VERSION 5.8 ;
BUSBITCHARS "[]" ;
DIVIDERCHAR "/" ;
UNITS
    DATABASE MICRONS 1000 ;
END UNITS

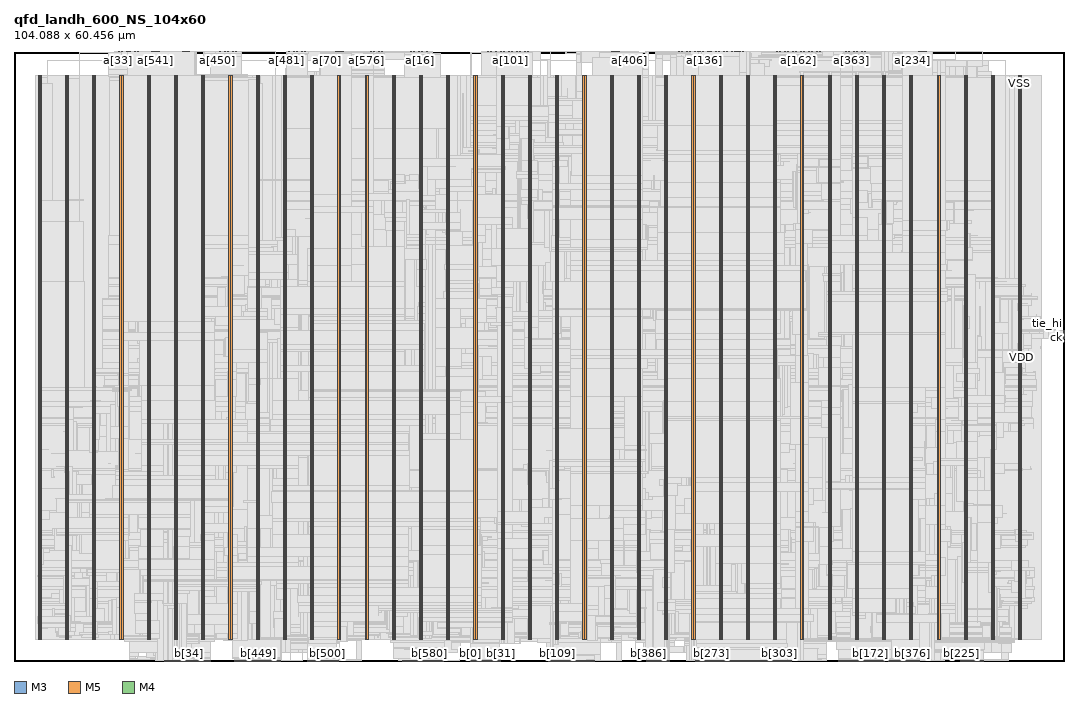
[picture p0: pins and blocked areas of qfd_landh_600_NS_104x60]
MACRO qfd_landh_600_NS_104x60
  FOREIGN qfd_landh_600_NS_104x60 0 0 ;
  CLASS BLOCK ;
  SIZE 104.088 BY 60.456 ;
  PIN a[0]
    DIRECTION INPUT ;
    USE SIGNAL ;
    PORT
      LAYER M3 ;
        RECT  39.06 60.419 39.078 60.456 ;
    END
  END a[0]
  PIN a[100]
    DIRECTION INPUT ;
    USE SIGNAL ;
    PORT
      LAYER M3 ;
        RECT  49.14 60.419 49.158 60.456 ;
    END
  END a[100]
  PIN a[101]
    DIRECTION INPUT ;
    USE SIGNAL ;
    PORT
      LAYER M3 ;
        RECT  49.212 60.419 49.23 60.456 ;
    END
  END a[101]
  PIN a[102]
    DIRECTION INPUT ;
    USE SIGNAL ;
    PORT
      LAYER M3 ;
        RECT  49.284 60.419 49.302 60.456 ;
    END
  END a[102]
  PIN a[103]
    DIRECTION INPUT ;
    USE SIGNAL ;
    PORT
      LAYER M3 ;
        RECT  49.356 60.419 49.374 60.456 ;
    END
  END a[103]
  PIN a[104]
    DIRECTION INPUT ;
    USE SIGNAL ;
    PORT
      LAYER M3 ;
        RECT  49.428 60.419 49.446 60.456 ;
    END
  END a[104]
  PIN a[105]
    DIRECTION INPUT ;
    USE SIGNAL ;
    PORT
      LAYER M3 ;
        RECT  49.5 60.419 49.518 60.456 ;
    END
  END a[105]
  PIN a[106]
    DIRECTION INPUT ;
    USE SIGNAL ;
    PORT
      LAYER M3 ;
        RECT  49.572 60.419 49.59 60.456 ;
    END
  END a[106]
  PIN a[107]
    DIRECTION INPUT ;
    USE SIGNAL ;
    PORT
      LAYER M3 ;
        RECT  49.644 60.419 49.662 60.456 ;
    END
  END a[107]
  PIN a[108]
    DIRECTION INPUT ;
    USE SIGNAL ;
    PORT
      LAYER M3 ;
        RECT  49.716 60.419 49.734 60.456 ;
    END
  END a[108]
  PIN a[109]
    DIRECTION INPUT ;
    USE SIGNAL ;
    PORT
      LAYER M3 ;
        RECT  49.788 60.419 49.806 60.456 ;
    END
  END a[109]
  PIN a[10]
    DIRECTION INPUT ;
    USE SIGNAL ;
    PORT
      LAYER M3 ;
        RECT  39.78 60.419 39.798 60.456 ;
    END
  END a[10]
  PIN a[110]
    DIRECTION INPUT ;
    USE SIGNAL ;
    PORT
      LAYER M3 ;
        RECT  49.86 60.419 49.878 60.456 ;
    END
  END a[110]
  PIN a[111]
    DIRECTION INPUT ;
    USE SIGNAL ;
    PORT
      LAYER M3 ;
        RECT  49.932 60.419 49.95 60.456 ;
    END
  END a[111]
  PIN a[112]
    DIRECTION INPUT ;
    USE SIGNAL ;
    PORT
      LAYER M3 ;
        RECT  50.004 60.419 50.022 60.456 ;
    END
  END a[112]
  PIN a[113]
    DIRECTION INPUT ;
    USE SIGNAL ;
    PORT
      LAYER M3 ;
        RECT  50.076 60.419 50.094 60.456 ;
    END
  END a[113]
  PIN a[114]
    DIRECTION INPUT ;
    USE SIGNAL ;
    PORT
      LAYER M3 ;
        RECT  50.148 60.419 50.166 60.456 ;
    END
  END a[114]
  PIN a[115]
    DIRECTION INPUT ;
    USE SIGNAL ;
    PORT
      LAYER M3 ;
        RECT  50.22 60.419 50.238 60.456 ;
    END
  END a[115]
  PIN a[116]
    DIRECTION INPUT ;
    USE SIGNAL ;
    PORT
      LAYER M3 ;
        RECT  50.292 60.419 50.31 60.456 ;
    END
  END a[116]
  PIN a[117]
    DIRECTION INPUT ;
    USE SIGNAL ;
    PORT
      LAYER M3 ;
        RECT  50.364 60.419 50.382 60.456 ;
    END
  END a[117]
  PIN a[118]
    DIRECTION INPUT ;
    USE SIGNAL ;
    PORT
      LAYER M3 ;
        RECT  50.436 60.419 50.454 60.456 ;
    END
  END a[118]
  PIN a[119]
    DIRECTION INPUT ;
    USE SIGNAL ;
    PORT
      LAYER M3 ;
        RECT  50.508 60.419 50.526 60.456 ;
    END
  END a[119]
  PIN a[11]
    DIRECTION INPUT ;
    USE SIGNAL ;
    PORT
      LAYER M3 ;
        RECT  39.852 60.419 39.87 60.456 ;
    END
  END a[11]
  PIN a[120]
    DIRECTION INPUT ;
    USE SIGNAL ;
    PORT
      LAYER M3 ;
        RECT  50.58 60.419 50.598 60.456 ;
    END
  END a[120]
  PIN a[121]
    DIRECTION INPUT ;
    USE SIGNAL ;
    PORT
      LAYER M3 ;
        RECT  50.652 60.419 50.67 60.456 ;
    END
  END a[121]
  PIN a[122]
    DIRECTION INPUT ;
    USE SIGNAL ;
    PORT
      LAYER M3 ;
        RECT  50.724 60.419 50.742 60.456 ;
    END
  END a[122]
  PIN a[123]
    DIRECTION INPUT ;
    USE SIGNAL ;
    PORT
      LAYER M3 ;
        RECT  50.796 60.419 50.814 60.456 ;
    END
  END a[123]
  PIN a[124]
    DIRECTION INPUT ;
    USE SIGNAL ;
    PORT
      LAYER M3 ;
        RECT  50.868 60.419 50.886 60.456 ;
    END
  END a[124]
  PIN a[125]
    DIRECTION INPUT ;
    USE SIGNAL ;
    PORT
      LAYER M3 ;
        RECT  50.94 60.419 50.958 60.456 ;
    END
  END a[125]
  PIN a[126]
    DIRECTION INPUT ;
    USE SIGNAL ;
    PORT
      LAYER M3 ;
        RECT  51.012 60.419 51.03 60.456 ;
    END
  END a[126]
  PIN a[127]
    DIRECTION INPUT ;
    USE SIGNAL ;
    PORT
      LAYER M3 ;
        RECT  51.084 60.419 51.102 60.456 ;
    END
  END a[127]
  PIN a[128]
    DIRECTION INPUT ;
    USE SIGNAL ;
    PORT
      LAYER M3 ;
        RECT  67.86 60.419 67.878 60.456 ;
    END
  END a[128]
  PIN a[129]
    DIRECTION INPUT ;
    USE SIGNAL ;
    PORT
      LAYER M3 ;
        RECT  67.932 60.419 67.95 60.456 ;
    END
  END a[129]
  PIN a[12]
    DIRECTION INPUT ;
    USE SIGNAL ;
    PORT
      LAYER M3 ;
        RECT  39.924 60.419 39.942 60.456 ;
    END
  END a[12]
  PIN a[130]
    DIRECTION INPUT ;
    USE SIGNAL ;
    PORT
      LAYER M3 ;
        RECT  68.004 60.419 68.022 60.456 ;
    END
  END a[130]
  PIN a[131]
    DIRECTION INPUT ;
    USE SIGNAL ;
    PORT
      LAYER M3 ;
        RECT  68.076 60.419 68.094 60.456 ;
    END
  END a[131]
  PIN a[132]
    DIRECTION INPUT ;
    USE SIGNAL ;
    PORT
      LAYER M3 ;
        RECT  68.148 60.419 68.166 60.456 ;
    END
  END a[132]
  PIN a[133]
    DIRECTION INPUT ;
    USE SIGNAL ;
    PORT
      LAYER M3 ;
        RECT  68.22 60.419 68.238 60.456 ;
    END
  END a[133]
  PIN a[134]
    DIRECTION INPUT ;
    USE SIGNAL ;
    PORT
      LAYER M3 ;
        RECT  68.292 60.419 68.31 60.456 ;
    END
  END a[134]
  PIN a[135]
    DIRECTION INPUT ;
    USE SIGNAL ;
    PORT
      LAYER M3 ;
        RECT  68.364 60.419 68.382 60.456 ;
    END
  END a[135]
  PIN a[136]
    DIRECTION INPUT ;
    USE SIGNAL ;
    PORT
      LAYER M3 ;
        RECT  68.436 60.419 68.454 60.456 ;
    END
  END a[136]
  PIN a[137]
    DIRECTION INPUT ;
    USE SIGNAL ;
    PORT
      LAYER M3 ;
        RECT  68.508 60.419 68.526 60.456 ;
    END
  END a[137]
  PIN a[138]
    DIRECTION INPUT ;
    USE SIGNAL ;
    PORT
      LAYER M3 ;
        RECT  68.58 60.419 68.598 60.456 ;
    END
  END a[138]
  PIN a[139]
    DIRECTION INPUT ;
    USE SIGNAL ;
    PORT
      LAYER M3 ;
        RECT  68.652 60.419 68.67 60.456 ;
    END
  END a[139]
  PIN a[13]
    DIRECTION INPUT ;
    USE SIGNAL ;
    PORT
      LAYER M3 ;
        RECT  39.996 60.419 40.014 60.456 ;
    END
  END a[13]
  PIN a[140]
    DIRECTION INPUT ;
    USE SIGNAL ;
    PORT
      LAYER M3 ;
        RECT  68.724 60.419 68.742 60.456 ;
    END
  END a[140]
  PIN a[141]
    DIRECTION INPUT ;
    USE SIGNAL ;
    PORT
      LAYER M3 ;
        RECT  68.796 60.419 68.814 60.456 ;
    END
  END a[141]
  PIN a[142]
    DIRECTION INPUT ;
    USE SIGNAL ;
    PORT
      LAYER M3 ;
        RECT  68.868 60.419 68.886 60.456 ;
    END
  END a[142]
  PIN a[143]
    DIRECTION INPUT ;
    USE SIGNAL ;
    PORT
      LAYER M3 ;
        RECT  68.94 60.419 68.958 60.456 ;
    END
  END a[143]
  PIN a[144]
    DIRECTION INPUT ;
    USE SIGNAL ;
    PORT
      LAYER M3 ;
        RECT  69.012 60.419 69.03 60.456 ;
    END
  END a[144]
  PIN a[145]
    DIRECTION INPUT ;
    USE SIGNAL ;
    PORT
      LAYER M3 ;
        RECT  69.084 60.419 69.102 60.456 ;
    END
  END a[145]
  PIN a[146]
    DIRECTION INPUT ;
    USE SIGNAL ;
    PORT
      LAYER M3 ;
        RECT  69.156 60.419 69.174 60.456 ;
    END
  END a[146]
  PIN a[147]
    DIRECTION INPUT ;
    USE SIGNAL ;
    PORT
      LAYER M3 ;
        RECT  69.228 60.419 69.246 60.456 ;
    END
  END a[147]
  PIN a[148]
    DIRECTION INPUT ;
    USE SIGNAL ;
    PORT
      LAYER M3 ;
        RECT  69.3 60.419 69.318 60.456 ;
    END
  END a[148]
  PIN a[149]
    DIRECTION INPUT ;
    USE SIGNAL ;
    PORT
      LAYER M3 ;
        RECT  69.372 60.419 69.39 60.456 ;
    END
  END a[149]
  PIN a[14]
    DIRECTION INPUT ;
    USE SIGNAL ;
    PORT
      LAYER M3 ;
        RECT  40.068 60.419 40.086 60.456 ;
    END
  END a[14]
  PIN a[150]
    DIRECTION INPUT ;
    USE SIGNAL ;
    PORT
      LAYER M3 ;
        RECT  69.444 60.419 69.462 60.456 ;
    END
  END a[150]
  PIN a[151]
    DIRECTION INPUT ;
    USE SIGNAL ;
    PORT
      LAYER M3 ;
        RECT  69.516 60.419 69.534 60.456 ;
    END
  END a[151]
  PIN a[152]
    DIRECTION INPUT ;
    USE SIGNAL ;
    PORT
      LAYER M3 ;
        RECT  69.588 60.419 69.606 60.456 ;
    END
  END a[152]
  PIN a[153]
    DIRECTION INPUT ;
    USE SIGNAL ;
    PORT
      LAYER M3 ;
        RECT  69.66 60.419 69.678 60.456 ;
    END
  END a[153]
  PIN a[154]
    DIRECTION INPUT ;
    USE SIGNAL ;
    PORT
      LAYER M3 ;
        RECT  69.732 60.419 69.75 60.456 ;
    END
  END a[154]
  PIN a[155]
    DIRECTION INPUT ;
    USE SIGNAL ;
    PORT
      LAYER M3 ;
        RECT  69.804 60.419 69.822 60.456 ;
    END
  END a[155]
  PIN a[156]
    DIRECTION INPUT ;
    USE SIGNAL ;
    PORT
      LAYER M3 ;
        RECT  69.876 60.419 69.894 60.456 ;
    END
  END a[156]
  PIN a[157]
    DIRECTION INPUT ;
    USE SIGNAL ;
    PORT
      LAYER M3 ;
        RECT  69.948 60.419 69.966 60.456 ;
    END
  END a[157]
  PIN a[158]
    DIRECTION INPUT ;
    USE SIGNAL ;
    PORT
      LAYER M3 ;
        RECT  70.02 60.419 70.038 60.456 ;
    END
  END a[158]
  PIN a[159]
    DIRECTION INPUT ;
    USE SIGNAL ;
    PORT
      LAYER M3 ;
        RECT  70.092 60.419 70.11 60.456 ;
    END
  END a[159]
  PIN a[15]
    DIRECTION INPUT ;
    USE SIGNAL ;
    PORT
      LAYER M3 ;
        RECT  40.14 60.419 40.158 60.456 ;
    END
  END a[15]
  PIN a[160]
    DIRECTION INPUT ;
    USE SIGNAL ;
    PORT
      LAYER M3 ;
        RECT  77.652 60.419 77.67 60.456 ;
    END
  END a[160]
  PIN a[161]
    DIRECTION INPUT ;
    USE SIGNAL ;
    PORT
      LAYER M3 ;
        RECT  77.724 60.419 77.742 60.456 ;
    END
  END a[161]
  PIN a[162]
    DIRECTION INPUT ;
    USE SIGNAL ;
    PORT
      LAYER M3 ;
        RECT  77.796 60.419 77.814 60.456 ;
    END
  END a[162]
  PIN a[163]
    DIRECTION INPUT ;
    USE SIGNAL ;
    PORT
      LAYER M3 ;
        RECT  77.868 60.419 77.886 60.456 ;
    END
  END a[163]
  PIN a[164]
    DIRECTION INPUT ;
    USE SIGNAL ;
    PORT
      LAYER M3 ;
        RECT  77.94 60.419 77.958 60.456 ;
    END
  END a[164]
  PIN a[165]
    DIRECTION INPUT ;
    USE SIGNAL ;
    PORT
      LAYER M3 ;
        RECT  78.012 60.419 78.03 60.456 ;
    END
  END a[165]
  PIN a[166]
    DIRECTION INPUT ;
    USE SIGNAL ;
    PORT
      LAYER M3 ;
        RECT  78.084 60.419 78.102 60.456 ;
    END
  END a[166]
  PIN a[167]
    DIRECTION INPUT ;
    USE SIGNAL ;
    PORT
      LAYER M3 ;
        RECT  78.156 60.419 78.174 60.456 ;
    END
  END a[167]
  PIN a[168]
    DIRECTION INPUT ;
    USE SIGNAL ;
    PORT
      LAYER M3 ;
        RECT  78.228 60.419 78.246 60.456 ;
    END
  END a[168]
  PIN a[169]
    DIRECTION INPUT ;
    USE SIGNAL ;
    PORT
      LAYER M3 ;
        RECT  78.3 60.419 78.318 60.456 ;
    END
  END a[169]
  PIN a[16]
    DIRECTION INPUT ;
    USE SIGNAL ;
    PORT
      LAYER M3 ;
        RECT  40.212 60.419 40.23 60.456 ;
    END
  END a[16]
  PIN a[170]
    DIRECTION INPUT ;
    USE SIGNAL ;
    PORT
      LAYER M3 ;
        RECT  78.372 60.419 78.39 60.456 ;
    END
  END a[170]
  PIN a[171]
    DIRECTION INPUT ;
    USE SIGNAL ;
    PORT
      LAYER M3 ;
        RECT  78.444 60.419 78.462 60.456 ;
    END
  END a[171]
  PIN a[172]
    DIRECTION INPUT ;
    USE SIGNAL ;
    PORT
      LAYER M3 ;
        RECT  78.516 60.419 78.534 60.456 ;
    END
  END a[172]
  PIN a[173]
    DIRECTION INPUT ;
    USE SIGNAL ;
    PORT
      LAYER M3 ;
        RECT  78.588 60.419 78.606 60.456 ;
    END
  END a[173]
  PIN a[174]
    DIRECTION INPUT ;
    USE SIGNAL ;
    PORT
      LAYER M3 ;
        RECT  78.66 60.419 78.678 60.456 ;
    END
  END a[174]
  PIN a[175]
    DIRECTION INPUT ;
    USE SIGNAL ;
    PORT
      LAYER M3 ;
        RECT  78.732 60.419 78.75 60.456 ;
    END
  END a[175]
  PIN a[176]
    DIRECTION INPUT ;
    USE SIGNAL ;
    PORT
      LAYER M3 ;
        RECT  78.804 60.419 78.822 60.456 ;
    END
  END a[176]
  PIN a[177]
    DIRECTION INPUT ;
    USE SIGNAL ;
    PORT
      LAYER M3 ;
        RECT  78.876 60.419 78.894 60.456 ;
    END
  END a[177]
  PIN a[178]
    DIRECTION INPUT ;
    USE SIGNAL ;
    PORT
      LAYER M3 ;
        RECT  78.948 60.419 78.966 60.456 ;
    END
  END a[178]
  PIN a[179]
    DIRECTION INPUT ;
    USE SIGNAL ;
    PORT
      LAYER M3 ;
        RECT  79.02 60.419 79.038 60.456 ;
    END
  END a[179]
  PIN a[17]
    DIRECTION INPUT ;
    USE SIGNAL ;
    PORT
      LAYER M3 ;
        RECT  40.284 60.419 40.302 60.456 ;
    END
  END a[17]
  PIN a[180]
    DIRECTION INPUT ;
    USE SIGNAL ;
    PORT
      LAYER M3 ;
        RECT  79.092 60.419 79.11 60.456 ;
    END
  END a[180]
  PIN a[181]
    DIRECTION INPUT ;
    USE SIGNAL ;
    PORT
      LAYER M3 ;
        RECT  79.164 60.419 79.182 60.456 ;
    END
  END a[181]
  PIN a[182]
    DIRECTION INPUT ;
    USE SIGNAL ;
    PORT
      LAYER M3 ;
        RECT  79.236 60.419 79.254 60.456 ;
    END
  END a[182]
  PIN a[183]
    DIRECTION INPUT ;
    USE SIGNAL ;
    PORT
      LAYER M3 ;
        RECT  79.308 60.419 79.326 60.456 ;
    END
  END a[183]
  PIN a[184]
    DIRECTION INPUT ;
    USE SIGNAL ;
    PORT
      LAYER M3 ;
        RECT  79.38 60.419 79.398 60.456 ;
    END
  END a[184]
  PIN a[185]
    DIRECTION INPUT ;
    USE SIGNAL ;
    PORT
      LAYER M3 ;
        RECT  79.452 60.419 79.47 60.456 ;
    END
  END a[185]
  PIN a[186]
    DIRECTION INPUT ;
    USE SIGNAL ;
    PORT
      LAYER M3 ;
        RECT  79.524 60.419 79.542 60.456 ;
    END
  END a[186]
  PIN a[187]
    DIRECTION INPUT ;
    USE SIGNAL ;
    PORT
      LAYER M3 ;
        RECT  79.596 60.419 79.614 60.456 ;
    END
  END a[187]
  PIN a[188]
    DIRECTION INPUT ;
    USE SIGNAL ;
    PORT
      LAYER M3 ;
        RECT  79.668 60.419 79.686 60.456 ;
    END
  END a[188]
  PIN a[189]
    DIRECTION INPUT ;
    USE SIGNAL ;
    PORT
      LAYER M3 ;
        RECT  79.74 60.419 79.758 60.456 ;
    END
  END a[189]
  PIN a[18]
    DIRECTION INPUT ;
    USE SIGNAL ;
    PORT
      LAYER M3 ;
        RECT  40.356 60.419 40.374 60.456 ;
    END
  END a[18]
  PIN a[190]
    DIRECTION INPUT ;
    USE SIGNAL ;
    PORT
      LAYER M3 ;
        RECT  79.812 60.419 79.83 60.456 ;
    END
  END a[190]
  PIN a[191]
    DIRECTION INPUT ;
    USE SIGNAL ;
    PORT
      LAYER M3 ;
        RECT  79.884 60.419 79.902 60.456 ;
    END
  END a[191]
  PIN a[192]
    DIRECTION INPUT ;
    USE SIGNAL ;
    PORT
      LAYER M3 ;
        RECT  70.164 60.419 70.182 60.456 ;
    END
  END a[192]
  PIN a[193]
    DIRECTION INPUT ;
    USE SIGNAL ;
    PORT
      LAYER M3 ;
        RECT  70.236 60.419 70.254 60.456 ;
    END
  END a[193]
  PIN a[194]
    DIRECTION INPUT ;
    USE SIGNAL ;
    PORT
      LAYER M3 ;
        RECT  70.308 60.419 70.326 60.456 ;
    END
  END a[194]
  PIN a[195]
    DIRECTION INPUT ;
    USE SIGNAL ;
    PORT
      LAYER M3 ;
        RECT  70.38 60.419 70.398 60.456 ;
    END
  END a[195]
  PIN a[196]
    DIRECTION INPUT ;
    USE SIGNAL ;
    PORT
      LAYER M3 ;
        RECT  70.452 60.419 70.47 60.456 ;
    END
  END a[196]
  PIN a[197]
    DIRECTION INPUT ;
    USE SIGNAL ;
    PORT
      LAYER M3 ;
        RECT  70.524 60.419 70.542 60.456 ;
    END
  END a[197]
  PIN a[198]
    DIRECTION INPUT ;
    USE SIGNAL ;
    PORT
      LAYER M3 ;
        RECT  70.596 60.419 70.614 60.456 ;
    END
  END a[198]
  PIN a[199]
    DIRECTION INPUT ;
    USE SIGNAL ;
    PORT
      LAYER M3 ;
        RECT  70.668 60.419 70.686 60.456 ;
    END
  END a[199]
  PIN a[19]
    DIRECTION INPUT ;
    USE SIGNAL ;
    PORT
      LAYER M3 ;
        RECT  40.428 60.419 40.446 60.456 ;
    END
  END a[19]
  PIN a[1]
    DIRECTION INPUT ;
    USE SIGNAL ;
    PORT
      LAYER M3 ;
        RECT  39.132 60.419 39.15 60.456 ;
    END
  END a[1]
  PIN a[200]
    DIRECTION INPUT ;
    USE SIGNAL ;
    PORT
      LAYER M3 ;
        RECT  70.74 60.419 70.758 60.456 ;
    END
  END a[200]
  PIN a[201]
    DIRECTION INPUT ;
    USE SIGNAL ;
    PORT
      LAYER M3 ;
        RECT  70.812 60.419 70.83 60.456 ;
    END
  END a[201]
  PIN a[202]
    DIRECTION INPUT ;
    USE SIGNAL ;
    PORT
      LAYER M3 ;
        RECT  70.884 60.419 70.902 60.456 ;
    END
  END a[202]
  PIN a[203]
    DIRECTION INPUT ;
    USE SIGNAL ;
    PORT
      LAYER M3 ;
        RECT  70.956 60.419 70.974 60.456 ;
    END
  END a[203]
  PIN a[204]
    DIRECTION INPUT ;
    USE SIGNAL ;
    PORT
      LAYER M3 ;
        RECT  71.028 60.419 71.046 60.456 ;
    END
  END a[204]
  PIN a[205]
    DIRECTION INPUT ;
    USE SIGNAL ;
    PORT
      LAYER M3 ;
        RECT  71.1 60.419 71.118 60.456 ;
    END
  END a[205]
  PIN a[206]
    DIRECTION INPUT ;
    USE SIGNAL ;
    PORT
      LAYER M3 ;
        RECT  71.172 60.419 71.19 60.456 ;
    END
  END a[206]
  PIN a[207]
    DIRECTION INPUT ;
    USE SIGNAL ;
    PORT
      LAYER M3 ;
        RECT  71.244 60.419 71.262 60.456 ;
    END
  END a[207]
  PIN a[208]
    DIRECTION INPUT ;
    USE SIGNAL ;
    PORT
      LAYER M3 ;
        RECT  71.316 60.419 71.334 60.456 ;
    END
  END a[208]
  PIN a[209]
    DIRECTION INPUT ;
    USE SIGNAL ;
    PORT
      LAYER M3 ;
        RECT  71.388 60.419 71.406 60.456 ;
    END
  END a[209]
  PIN a[20]
    DIRECTION INPUT ;
    USE SIGNAL ;
    PORT
      LAYER M3 ;
        RECT  40.5 60.419 40.518 60.456 ;
    END
  END a[20]
  PIN a[210]
    DIRECTION INPUT ;
    USE SIGNAL ;
    PORT
      LAYER M3 ;
        RECT  71.46 60.419 71.478 60.456 ;
    END
  END a[210]
  PIN a[211]
    DIRECTION INPUT ;
    USE SIGNAL ;
    PORT
      LAYER M3 ;
        RECT  71.532 60.419 71.55 60.456 ;
    END
  END a[211]
  PIN a[212]
    DIRECTION INPUT ;
    USE SIGNAL ;
    PORT
      LAYER M3 ;
        RECT  71.604 60.419 71.622 60.456 ;
    END
  END a[212]
  PIN a[213]
    DIRECTION INPUT ;
    USE SIGNAL ;
    PORT
      LAYER M3 ;
        RECT  71.676 60.419 71.694 60.456 ;
    END
  END a[213]
  PIN a[214]
    DIRECTION INPUT ;
    USE SIGNAL ;
    PORT
      LAYER M3 ;
        RECT  71.748 60.419 71.766 60.456 ;
    END
  END a[214]
  PIN a[215]
    DIRECTION INPUT ;
    USE SIGNAL ;
    PORT
      LAYER M3 ;
        RECT  71.82 60.419 71.838 60.456 ;
    END
  END a[215]
  PIN a[216]
    DIRECTION INPUT ;
    USE SIGNAL ;
    PORT
      LAYER M3 ;
        RECT  71.892 60.419 71.91 60.456 ;
    END
  END a[216]
  PIN a[217]
    DIRECTION INPUT ;
    USE SIGNAL ;
    PORT
      LAYER M3 ;
        RECT  71.964 60.419 71.982 60.456 ;
    END
  END a[217]
  PIN a[218]
    DIRECTION INPUT ;
    USE SIGNAL ;
    PORT
      LAYER M3 ;
        RECT  72.036 60.419 72.054 60.456 ;
    END
  END a[218]
  PIN a[219]
    DIRECTION INPUT ;
    USE SIGNAL ;
    PORT
      LAYER M3 ;
        RECT  72.108 60.419 72.126 60.456 ;
    END
  END a[219]
  PIN a[21]
    DIRECTION INPUT ;
    USE SIGNAL ;
    PORT
      LAYER M3 ;
        RECT  40.572 60.419 40.59 60.456 ;
    END
  END a[21]
  PIN a[220]
    DIRECTION INPUT ;
    USE SIGNAL ;
    PORT
      LAYER M3 ;
        RECT  72.18 60.419 72.198 60.456 ;
    END
  END a[220]
  PIN a[221]
    DIRECTION INPUT ;
    USE SIGNAL ;
    PORT
      LAYER M3 ;
        RECT  72.252 60.419 72.27 60.456 ;
    END
  END a[221]
  PIN a[222]
    DIRECTION INPUT ;
    USE SIGNAL ;
    PORT
      LAYER M3 ;
        RECT  72.324 60.419 72.342 60.456 ;
    END
  END a[222]
  PIN a[223]
    DIRECTION INPUT ;
    USE SIGNAL ;
    PORT
      LAYER M3 ;
        RECT  72.396 60.419 72.414 60.456 ;
    END
  END a[223]
  PIN a[224]
    DIRECTION INPUT ;
    USE SIGNAL ;
    PORT
      LAYER M5 ;
        RECT  88.08 60.372 88.104 60.456 ;
    END
  END a[224]
  PIN a[225]
    DIRECTION INPUT ;
    USE SIGNAL ;
    PORT
      LAYER M5 ;
        RECT  88.176 60.372 88.2 60.456 ;
    END
  END a[225]
  PIN a[226]
    DIRECTION INPUT ;
    USE SIGNAL ;
    PORT
      LAYER M5 ;
        RECT  88.272 60.372 88.296 60.456 ;
    END
  END a[226]
  PIN a[227]
    DIRECTION INPUT ;
    USE SIGNAL ;
    PORT
      LAYER M5 ;
        RECT  88.368 60.372 88.392 60.456 ;
    END
  END a[227]
  PIN a[228]
    DIRECTION INPUT ;
    USE SIGNAL ;
    PORT
      LAYER M5 ;
        RECT  88.464 60.372 88.488 60.456 ;
    END
  END a[228]
  PIN a[229]
    DIRECTION INPUT ;
    USE SIGNAL ;
    PORT
      LAYER M5 ;
        RECT  88.56 60.372 88.584 60.456 ;
    END
  END a[229]
  PIN a[22]
    DIRECTION INPUT ;
    USE SIGNAL ;
    PORT
      LAYER M3 ;
        RECT  40.644 60.419 40.662 60.456 ;
    END
  END a[22]
  PIN a[230]
    DIRECTION INPUT ;
    USE SIGNAL ;
    PORT
      LAYER M5 ;
        RECT  88.656 60.372 88.68 60.456 ;
    END
  END a[230]
  PIN a[231]
    DIRECTION INPUT ;
    USE SIGNAL ;
    PORT
      LAYER M5 ;
        RECT  88.752 60.372 88.776 60.456 ;
    END
  END a[231]
  PIN a[232]
    DIRECTION INPUT ;
    USE SIGNAL ;
    PORT
      LAYER M5 ;
        RECT  88.848 60.372 88.872 60.456 ;
    END
  END a[232]
  PIN a[233]
    DIRECTION INPUT ;
    USE SIGNAL ;
    PORT
      LAYER M5 ;
        RECT  88.944 60.372 88.968 60.456 ;
    END
  END a[233]
  PIN a[234]
    DIRECTION INPUT ;
    USE SIGNAL ;
    PORT
      LAYER M5 ;
        RECT  89.04 60.372 89.064 60.456 ;
    END
  END a[234]
  PIN a[235]
    DIRECTION INPUT ;
    USE SIGNAL ;
    PORT
      LAYER M5 ;
        RECT  89.136 60.372 89.16 60.456 ;
    END
  END a[235]
  PIN a[236]
    DIRECTION INPUT ;
    USE SIGNAL ;
    PORT
      LAYER M5 ;
        RECT  89.232 60.372 89.256 60.456 ;
    END
  END a[236]
  PIN a[237]
    DIRECTION INPUT ;
    USE SIGNAL ;
    PORT
      LAYER M5 ;
        RECT  89.328 60.372 89.352 60.456 ;
    END
  END a[237]
  PIN a[238]
    DIRECTION INPUT ;
    USE SIGNAL ;
    PORT
      LAYER M5 ;
        RECT  89.424 60.372 89.448 60.456 ;
    END
  END a[238]
  PIN a[239]
    DIRECTION INPUT ;
    USE SIGNAL ;
    PORT
      LAYER M5 ;
        RECT  89.52 60.372 89.544 60.456 ;
    END
  END a[239]
  PIN a[23]
    DIRECTION INPUT ;
    USE SIGNAL ;
    PORT
      LAYER M3 ;
        RECT  40.716 60.419 40.734 60.456 ;
    END
  END a[23]
  PIN a[240]
    DIRECTION INPUT ;
    USE SIGNAL ;
    PORT
      LAYER M5 ;
        RECT  89.616 60.372 89.64 60.456 ;
    END
  END a[240]
  PIN a[241]
    DIRECTION INPUT ;
    USE SIGNAL ;
    PORT
      LAYER M5 ;
        RECT  89.712 60.372 89.736 60.456 ;
    END
  END a[241]
  PIN a[242]
    DIRECTION INPUT ;
    USE SIGNAL ;
    PORT
      LAYER M5 ;
        RECT  89.808 60.372 89.832 60.456 ;
    END
  END a[242]
  PIN a[243]
    DIRECTION INPUT ;
    USE SIGNAL ;
    PORT
      LAYER M5 ;
        RECT  89.904 60.372 89.928 60.456 ;
    END
  END a[243]
  PIN a[244]
    DIRECTION INPUT ;
    USE SIGNAL ;
    PORT
      LAYER M5 ;
        RECT  90 60.372 90.024 60.456 ;
    END
  END a[244]
  PIN a[245]
    DIRECTION INPUT ;
    USE SIGNAL ;
    PORT
      LAYER M5 ;
        RECT  90.096 60.372 90.12 60.456 ;
    END
  END a[245]
  PIN a[246]
    DIRECTION INPUT ;
    USE SIGNAL ;
    PORT
      LAYER M5 ;
        RECT  90.192 60.372 90.216 60.456 ;
    END
  END a[246]
  PIN a[247]
    DIRECTION INPUT ;
    USE SIGNAL ;
    PORT
      LAYER M5 ;
        RECT  90.288 60.372 90.312 60.456 ;
    END
  END a[247]
  PIN a[248]
    DIRECTION INPUT ;
    USE SIGNAL ;
    PORT
      LAYER M5 ;
        RECT  90.384 60.372 90.408 60.456 ;
    END
  END a[248]
  PIN a[249]
    DIRECTION INPUT ;
    USE SIGNAL ;
    PORT
      LAYER M5 ;
        RECT  90.48 60.372 90.504 60.456 ;
    END
  END a[249]
  PIN a[24]
    DIRECTION INPUT ;
    USE SIGNAL ;
    PORT
      LAYER M3 ;
        RECT  40.788 60.419 40.806 60.456 ;
    END
  END a[24]
  PIN a[250]
    DIRECTION INPUT ;
    USE SIGNAL ;
    PORT
      LAYER M5 ;
        RECT  90.576 60.372 90.6 60.456 ;
    END
  END a[250]
  PIN a[251]
    DIRECTION INPUT ;
    USE SIGNAL ;
    PORT
      LAYER M5 ;
        RECT  90.672 60.372 90.696 60.456 ;
    END
  END a[251]
  PIN a[252]
    DIRECTION INPUT ;
    USE SIGNAL ;
    PORT
      LAYER M5 ;
        RECT  90.768 60.372 90.792 60.456 ;
    END
  END a[252]
  PIN a[253]
    DIRECTION INPUT ;
    USE SIGNAL ;
    PORT
      LAYER M5 ;
        RECT  90.864 60.372 90.888 60.456 ;
    END
  END a[253]
  PIN a[254]
    DIRECTION INPUT ;
    USE SIGNAL ;
    PORT
      LAYER M5 ;
        RECT  90.96 60.372 90.984 60.456 ;
    END
  END a[254]
  PIN a[255]
    DIRECTION INPUT ;
    USE SIGNAL ;
    PORT
      LAYER M5 ;
        RECT  91.056 60.372 91.08 60.456 ;
    END
  END a[255]
  PIN a[256]
    DIRECTION INPUT ;
    USE SIGNAL ;
    PORT
      LAYER M3 ;
        RECT  65.556 60.419 65.574 60.456 ;
    END
  END a[256]
  PIN a[257]
    DIRECTION INPUT ;
    USE SIGNAL ;
    PORT
      LAYER M3 ;
        RECT  65.628 60.419 65.646 60.456 ;
    END
  END a[257]
  PIN a[258]
    DIRECTION INPUT ;
    USE SIGNAL ;
    PORT
      LAYER M3 ;
        RECT  65.7 60.419 65.718 60.456 ;
    END
  END a[258]
  PIN a[259]
    DIRECTION INPUT ;
    USE SIGNAL ;
    PORT
      LAYER M3 ;
        RECT  65.772 60.419 65.79 60.456 ;
    END
  END a[259]
  PIN a[25]
    DIRECTION INPUT ;
    USE SIGNAL ;
    PORT
      LAYER M3 ;
        RECT  40.86 60.419 40.878 60.456 ;
    END
  END a[25]
  PIN a[260]
    DIRECTION INPUT ;
    USE SIGNAL ;
    PORT
      LAYER M3 ;
        RECT  65.844 60.419 65.862 60.456 ;
    END
  END a[260]
  PIN a[261]
    DIRECTION INPUT ;
    USE SIGNAL ;
    PORT
      LAYER M3 ;
        RECT  65.916 60.419 65.934 60.456 ;
    END
  END a[261]
  PIN a[262]
    DIRECTION INPUT ;
    USE SIGNAL ;
    PORT
      LAYER M3 ;
        RECT  65.988 60.419 66.006 60.456 ;
    END
  END a[262]
  PIN a[263]
    DIRECTION INPUT ;
    USE SIGNAL ;
    PORT
      LAYER M3 ;
        RECT  66.06 60.419 66.078 60.456 ;
    END
  END a[263]
  PIN a[264]
    DIRECTION INPUT ;
    USE SIGNAL ;
    PORT
      LAYER M3 ;
        RECT  66.132 60.419 66.15 60.456 ;
    END
  END a[264]
  PIN a[265]
    DIRECTION INPUT ;
    USE SIGNAL ;
    PORT
      LAYER M3 ;
        RECT  66.204 60.419 66.222 60.456 ;
    END
  END a[265]
  PIN a[266]
    DIRECTION INPUT ;
    USE SIGNAL ;
    PORT
      LAYER M3 ;
        RECT  66.276 60.419 66.294 60.456 ;
    END
  END a[266]
  PIN a[267]
    DIRECTION INPUT ;
    USE SIGNAL ;
    PORT
      LAYER M3 ;
        RECT  66.348 60.419 66.366 60.456 ;
    END
  END a[267]
  PIN a[268]
    DIRECTION INPUT ;
    USE SIGNAL ;
    PORT
      LAYER M3 ;
        RECT  66.42 60.419 66.438 60.456 ;
    END
  END a[268]
  PIN a[269]
    DIRECTION INPUT ;
    USE SIGNAL ;
    PORT
      LAYER M3 ;
        RECT  66.492 60.419 66.51 60.456 ;
    END
  END a[269]
  PIN a[26]
    DIRECTION INPUT ;
    USE SIGNAL ;
    PORT
      LAYER M3 ;
        RECT  40.932 60.419 40.95 60.456 ;
    END
  END a[26]
  PIN a[270]
    DIRECTION INPUT ;
    USE SIGNAL ;
    PORT
      LAYER M3 ;
        RECT  66.564 60.419 66.582 60.456 ;
    END
  END a[270]
  PIN a[271]
    DIRECTION INPUT ;
    USE SIGNAL ;
    PORT
      LAYER M3 ;
        RECT  66.636 60.419 66.654 60.456 ;
    END
  END a[271]
  PIN a[272]
    DIRECTION INPUT ;
    USE SIGNAL ;
    PORT
      LAYER M3 ;
        RECT  66.708 60.419 66.726 60.456 ;
    END
  END a[272]
  PIN a[273]
    DIRECTION INPUT ;
    USE SIGNAL ;
    PORT
      LAYER M3 ;
        RECT  66.78 60.419 66.798 60.456 ;
    END
  END a[273]
  PIN a[274]
    DIRECTION INPUT ;
    USE SIGNAL ;
    PORT
      LAYER M3 ;
        RECT  66.852 60.419 66.87 60.456 ;
    END
  END a[274]
  PIN a[275]
    DIRECTION INPUT ;
    USE SIGNAL ;
    PORT
      LAYER M3 ;
        RECT  66.924 60.419 66.942 60.456 ;
    END
  END a[275]
  PIN a[276]
    DIRECTION INPUT ;
    USE SIGNAL ;
    PORT
      LAYER M3 ;
        RECT  66.996 60.419 67.014 60.456 ;
    END
  END a[276]
  PIN a[277]
    DIRECTION INPUT ;
    USE SIGNAL ;
    PORT
      LAYER M3 ;
        RECT  67.068 60.419 67.086 60.456 ;
    END
  END a[277]
  PIN a[278]
    DIRECTION INPUT ;
    USE SIGNAL ;
    PORT
      LAYER M3 ;
        RECT  67.14 60.419 67.158 60.456 ;
    END
  END a[278]
  PIN a[279]
    DIRECTION INPUT ;
    USE SIGNAL ;
    PORT
      LAYER M3 ;
        RECT  67.212 60.419 67.23 60.456 ;
    END
  END a[279]
  PIN a[27]
    DIRECTION INPUT ;
    USE SIGNAL ;
    PORT
      LAYER M3 ;
        RECT  41.004 60.419 41.022 60.456 ;
    END
  END a[27]
  PIN a[280]
    DIRECTION INPUT ;
    USE SIGNAL ;
    PORT
      LAYER M3 ;
        RECT  67.284 60.419 67.302 60.456 ;
    END
  END a[280]
  PIN a[281]
    DIRECTION INPUT ;
    USE SIGNAL ;
    PORT
      LAYER M3 ;
        RECT  67.356 60.419 67.374 60.456 ;
    END
  END a[281]
  PIN a[282]
    DIRECTION INPUT ;
    USE SIGNAL ;
    PORT
      LAYER M3 ;
        RECT  67.428 60.419 67.446 60.456 ;
    END
  END a[282]
  PIN a[283]
    DIRECTION INPUT ;
    USE SIGNAL ;
    PORT
      LAYER M3 ;
        RECT  67.5 60.419 67.518 60.456 ;
    END
  END a[283]
  PIN a[284]
    DIRECTION INPUT ;
    USE SIGNAL ;
    PORT
      LAYER M3 ;
        RECT  67.572 60.419 67.59 60.456 ;
    END
  END a[284]
  PIN a[285]
    DIRECTION INPUT ;
    USE SIGNAL ;
    PORT
      LAYER M3 ;
        RECT  67.644 60.419 67.662 60.456 ;
    END
  END a[285]
  PIN a[286]
    DIRECTION INPUT ;
    USE SIGNAL ;
    PORT
      LAYER M3 ;
        RECT  67.716 60.419 67.734 60.456 ;
    END
  END a[286]
  PIN a[287]
    DIRECTION INPUT ;
    USE SIGNAL ;
    PORT
      LAYER M3 ;
        RECT  67.788 60.419 67.806 60.456 ;
    END
  END a[287]
  PIN a[288]
    DIRECTION INPUT ;
    USE SIGNAL ;
    PORT
      LAYER M5 ;
        RECT  68.88 60.372 68.904 60.456 ;
    END
  END a[288]
  PIN a[289]
    DIRECTION INPUT ;
    USE SIGNAL ;
    PORT
      LAYER M5 ;
        RECT  68.976 60.372 69 60.456 ;
    END
  END a[289]
  PIN a[28]
    DIRECTION INPUT ;
    USE SIGNAL ;
    PORT
      LAYER M3 ;
        RECT  41.076 60.419 41.094 60.456 ;
    END
  END a[28]
  PIN a[290]
    DIRECTION INPUT ;
    USE SIGNAL ;
    PORT
      LAYER M5 ;
        RECT  69.072 60.372 69.096 60.456 ;
    END
  END a[290]
  PIN a[291]
    DIRECTION INPUT ;
    USE SIGNAL ;
    PORT
      LAYER M5 ;
        RECT  69.168 60.372 69.192 60.456 ;
    END
  END a[291]
  PIN a[292]
    DIRECTION INPUT ;
    USE SIGNAL ;
    PORT
      LAYER M5 ;
        RECT  69.264 60.372 69.288 60.456 ;
    END
  END a[292]
  PIN a[293]
    DIRECTION INPUT ;
    USE SIGNAL ;
    PORT
      LAYER M5 ;
        RECT  69.36 60.372 69.384 60.456 ;
    END
  END a[293]
  PIN a[294]
    DIRECTION INPUT ;
    USE SIGNAL ;
    PORT
      LAYER M5 ;
        RECT  69.456 60.372 69.48 60.456 ;
    END
  END a[294]
  PIN a[295]
    DIRECTION INPUT ;
    USE SIGNAL ;
    PORT
      LAYER M5 ;
        RECT  69.552 60.372 69.576 60.456 ;
    END
  END a[295]
  PIN a[296]
    DIRECTION INPUT ;
    USE SIGNAL ;
    PORT
      LAYER M5 ;
        RECT  69.648 60.372 69.672 60.456 ;
    END
  END a[296]
  PIN a[297]
    DIRECTION INPUT ;
    USE SIGNAL ;
    PORT
      LAYER M5 ;
        RECT  69.744 60.372 69.768 60.456 ;
    END
  END a[297]
  PIN a[298]
    DIRECTION INPUT ;
    USE SIGNAL ;
    PORT
      LAYER M5 ;
        RECT  69.84 60.372 69.864 60.456 ;
    END
  END a[298]
  PIN a[299]
    DIRECTION INPUT ;
    USE SIGNAL ;
    PORT
      LAYER M5 ;
        RECT  69.936 60.372 69.96 60.456 ;
    END
  END a[299]
  PIN a[29]
    DIRECTION INPUT ;
    USE SIGNAL ;
    PORT
      LAYER M3 ;
        RECT  41.148 60.419 41.166 60.456 ;
    END
  END a[29]
  PIN a[2]
    DIRECTION INPUT ;
    USE SIGNAL ;
    PORT
      LAYER M3 ;
        RECT  39.204 60.419 39.222 60.456 ;
    END
  END a[2]
  PIN a[300]
    DIRECTION INPUT ;
    USE SIGNAL ;
    PORT
      LAYER M5 ;
        RECT  70.032 60.372 70.056 60.456 ;
    END
  END a[300]
  PIN a[301]
    DIRECTION INPUT ;
    USE SIGNAL ;
    PORT
      LAYER M5 ;
        RECT  70.128 60.372 70.152 60.456 ;
    END
  END a[301]
  PIN a[302]
    DIRECTION INPUT ;
    USE SIGNAL ;
    PORT
      LAYER M5 ;
        RECT  70.224 60.372 70.248 60.456 ;
    END
  END a[302]
  PIN a[303]
    DIRECTION INPUT ;
    USE SIGNAL ;
    PORT
      LAYER M5 ;
        RECT  70.32 60.372 70.344 60.456 ;
    END
  END a[303]
  PIN a[304]
    DIRECTION INPUT ;
    USE SIGNAL ;
    PORT
      LAYER M5 ;
        RECT  70.416 60.372 70.44 60.456 ;
    END
  END a[304]
  PIN a[305]
    DIRECTION INPUT ;
    USE SIGNAL ;
    PORT
      LAYER M5 ;
        RECT  70.512 60.372 70.536 60.456 ;
    END
  END a[305]
  PIN a[306]
    DIRECTION INPUT ;
    USE SIGNAL ;
    PORT
      LAYER M5 ;
        RECT  70.608 60.372 70.632 60.456 ;
    END
  END a[306]
  PIN a[307]
    DIRECTION INPUT ;
    USE SIGNAL ;
    PORT
      LAYER M5 ;
        RECT  70.704 60.372 70.728 60.456 ;
    END
  END a[307]
  PIN a[308]
    DIRECTION INPUT ;
    USE SIGNAL ;
    PORT
      LAYER M5 ;
        RECT  70.8 60.372 70.824 60.456 ;
    END
  END a[308]
  PIN a[309]
    DIRECTION INPUT ;
    USE SIGNAL ;
    PORT
      LAYER M5 ;
        RECT  70.896 60.372 70.92 60.456 ;
    END
  END a[309]
  PIN a[30]
    DIRECTION INPUT ;
    USE SIGNAL ;
    PORT
      LAYER M3 ;
        RECT  41.22 60.419 41.238 60.456 ;
    END
  END a[30]
  PIN a[310]
    DIRECTION INPUT ;
    USE SIGNAL ;
    PORT
      LAYER M5 ;
        RECT  70.992 60.372 71.016 60.456 ;
    END
  END a[310]
  PIN a[311]
    DIRECTION INPUT ;
    USE SIGNAL ;
    PORT
      LAYER M5 ;
        RECT  71.088 60.372 71.112 60.456 ;
    END
  END a[311]
  PIN a[312]
    DIRECTION INPUT ;
    USE SIGNAL ;
    PORT
      LAYER M5 ;
        RECT  71.184 60.372 71.208 60.456 ;
    END
  END a[312]
  PIN a[313]
    DIRECTION INPUT ;
    USE SIGNAL ;
    PORT
      LAYER M5 ;
        RECT  71.28 60.372 71.304 60.456 ;
    END
  END a[313]
  PIN a[314]
    DIRECTION INPUT ;
    USE SIGNAL ;
    PORT
      LAYER M5 ;
        RECT  71.376 60.372 71.4 60.456 ;
    END
  END a[314]
  PIN a[315]
    DIRECTION INPUT ;
    USE SIGNAL ;
    PORT
      LAYER M5 ;
        RECT  71.472 60.372 71.496 60.456 ;
    END
  END a[315]
  PIN a[316]
    DIRECTION INPUT ;
    USE SIGNAL ;
    PORT
      LAYER M5 ;
        RECT  71.568 60.372 71.592 60.456 ;
    END
  END a[316]
  PIN a[317]
    DIRECTION INPUT ;
    USE SIGNAL ;
    PORT
      LAYER M5 ;
        RECT  71.664 60.372 71.688 60.456 ;
    END
  END a[317]
  PIN a[318]
    DIRECTION INPUT ;
    USE SIGNAL ;
    PORT
      LAYER M5 ;
        RECT  71.76 60.372 71.784 60.456 ;
    END
  END a[318]
  PIN a[319]
    DIRECTION INPUT ;
    USE SIGNAL ;
    PORT
      LAYER M5 ;
        RECT  71.856 60.372 71.88 60.456 ;
    END
  END a[319]
  PIN a[31]
    DIRECTION INPUT ;
    USE SIGNAL ;
    PORT
      LAYER M3 ;
        RECT  41.292 60.419 41.31 60.456 ;
    END
  END a[31]
  PIN a[320]
    DIRECTION INPUT ;
    USE SIGNAL ;
    PORT
      LAYER M3 ;
        RECT  75.348 60.419 75.366 60.456 ;
    END
  END a[320]
  PIN a[321]
    DIRECTION INPUT ;
    USE SIGNAL ;
    PORT
      LAYER M3 ;
        RECT  75.42 60.419 75.438 60.456 ;
    END
  END a[321]
  PIN a[322]
    DIRECTION INPUT ;
    USE SIGNAL ;
    PORT
      LAYER M3 ;
        RECT  75.492 60.419 75.51 60.456 ;
    END
  END a[322]
  PIN a[323]
    DIRECTION INPUT ;
    USE SIGNAL ;
    PORT
      LAYER M3 ;
        RECT  75.564 60.419 75.582 60.456 ;
    END
  END a[323]
  PIN a[324]
    DIRECTION INPUT ;
    USE SIGNAL ;
    PORT
      LAYER M3 ;
        RECT  75.636 60.419 75.654 60.456 ;
    END
  END a[324]
  PIN a[325]
    DIRECTION INPUT ;
    USE SIGNAL ;
    PORT
      LAYER M3 ;
        RECT  75.708 60.419 75.726 60.456 ;
    END
  END a[325]
  PIN a[326]
    DIRECTION INPUT ;
    USE SIGNAL ;
    PORT
      LAYER M3 ;
        RECT  75.78 60.419 75.798 60.456 ;
    END
  END a[326]
  PIN a[327]
    DIRECTION INPUT ;
    USE SIGNAL ;
    PORT
      LAYER M3 ;
        RECT  75.852 60.419 75.87 60.456 ;
    END
  END a[327]
  PIN a[328]
    DIRECTION INPUT ;
    USE SIGNAL ;
    PORT
      LAYER M3 ;
        RECT  75.924 60.419 75.942 60.456 ;
    END
  END a[328]
  PIN a[329]
    DIRECTION INPUT ;
    USE SIGNAL ;
    PORT
      LAYER M3 ;
        RECT  75.996 60.419 76.014 60.456 ;
    END
  END a[329]
  PIN a[32]
    DIRECTION INPUT ;
    USE SIGNAL ;
    PORT
      LAYER M3 ;
        RECT  10.26 60.419 10.278 60.456 ;
    END
  END a[32]
  PIN a[330]
    DIRECTION INPUT ;
    USE SIGNAL ;
    PORT
      LAYER M3 ;
        RECT  76.068 60.419 76.086 60.456 ;
    END
  END a[330]
  PIN a[331]
    DIRECTION INPUT ;
    USE SIGNAL ;
    PORT
      LAYER M3 ;
        RECT  76.14 60.419 76.158 60.456 ;
    END
  END a[331]
  PIN a[332]
    DIRECTION INPUT ;
    USE SIGNAL ;
    PORT
      LAYER M3 ;
        RECT  76.212 60.419 76.23 60.456 ;
    END
  END a[332]
  PIN a[333]
    DIRECTION INPUT ;
    USE SIGNAL ;
    PORT
      LAYER M3 ;
        RECT  76.284 60.419 76.302 60.456 ;
    END
  END a[333]
  PIN a[334]
    DIRECTION INPUT ;
    USE SIGNAL ;
    PORT
      LAYER M3 ;
        RECT  76.356 60.419 76.374 60.456 ;
    END
  END a[334]
  PIN a[335]
    DIRECTION INPUT ;
    USE SIGNAL ;
    PORT
      LAYER M3 ;
        RECT  76.428 60.419 76.446 60.456 ;
    END
  END a[335]
  PIN a[336]
    DIRECTION INPUT ;
    USE SIGNAL ;
    PORT
      LAYER M3 ;
        RECT  76.5 60.419 76.518 60.456 ;
    END
  END a[336]
  PIN a[337]
    DIRECTION INPUT ;
    USE SIGNAL ;
    PORT
      LAYER M3 ;
        RECT  76.572 60.419 76.59 60.456 ;
    END
  END a[337]
  PIN a[338]
    DIRECTION INPUT ;
    USE SIGNAL ;
    PORT
      LAYER M3 ;
        RECT  76.644 60.419 76.662 60.456 ;
    END
  END a[338]
  PIN a[339]
    DIRECTION INPUT ;
    USE SIGNAL ;
    PORT
      LAYER M3 ;
        RECT  76.716 60.419 76.734 60.456 ;
    END
  END a[339]
  PIN a[33]
    DIRECTION INPUT ;
    USE SIGNAL ;
    PORT
      LAYER M3 ;
        RECT  10.332 60.419 10.35 60.456 ;
    END
  END a[33]
  PIN a[340]
    DIRECTION INPUT ;
    USE SIGNAL ;
    PORT
      LAYER M3 ;
        RECT  76.788 60.419 76.806 60.456 ;
    END
  END a[340]
  PIN a[341]
    DIRECTION INPUT ;
    USE SIGNAL ;
    PORT
      LAYER M3 ;
        RECT  76.86 60.419 76.878 60.456 ;
    END
  END a[341]
  PIN a[342]
    DIRECTION INPUT ;
    USE SIGNAL ;
    PORT
      LAYER M3 ;
        RECT  76.932 60.419 76.95 60.456 ;
    END
  END a[342]
  PIN a[343]
    DIRECTION INPUT ;
    USE SIGNAL ;
    PORT
      LAYER M3 ;
        RECT  77.004 60.419 77.022 60.456 ;
    END
  END a[343]
  PIN a[344]
    DIRECTION INPUT ;
    USE SIGNAL ;
    PORT
      LAYER M3 ;
        RECT  77.076 60.419 77.094 60.456 ;
    END
  END a[344]
  PIN a[345]
    DIRECTION INPUT ;
    USE SIGNAL ;
    PORT
      LAYER M3 ;
        RECT  77.148 60.419 77.166 60.456 ;
    END
  END a[345]
  PIN a[346]
    DIRECTION INPUT ;
    USE SIGNAL ;
    PORT
      LAYER M3 ;
        RECT  77.22 60.419 77.238 60.456 ;
    END
  END a[346]
  PIN a[347]
    DIRECTION INPUT ;
    USE SIGNAL ;
    PORT
      LAYER M3 ;
        RECT  77.292 60.419 77.31 60.456 ;
    END
  END a[347]
  PIN a[348]
    DIRECTION INPUT ;
    USE SIGNAL ;
    PORT
      LAYER M3 ;
        RECT  77.364 60.419 77.382 60.456 ;
    END
  END a[348]
  PIN a[349]
    DIRECTION INPUT ;
    USE SIGNAL ;
    PORT
      LAYER M3 ;
        RECT  77.436 60.419 77.454 60.456 ;
    END
  END a[349]
  PIN a[34]
    DIRECTION INPUT ;
    USE SIGNAL ;
    PORT
      LAYER M3 ;
        RECT  10.404 60.419 10.422 60.456 ;
    END
  END a[34]
  PIN a[350]
    DIRECTION INPUT ;
    USE SIGNAL ;
    PORT
      LAYER M3 ;
        RECT  77.508 60.419 77.526 60.456 ;
    END
  END a[350]
  PIN a[351]
    DIRECTION INPUT ;
    USE SIGNAL ;
    PORT
      LAYER M3 ;
        RECT  77.58 60.419 77.598 60.456 ;
    END
  END a[351]
  PIN a[352]
    DIRECTION INPUT ;
    USE SIGNAL ;
    PORT
      LAYER M3 ;
        RECT  82.26 60.419 82.278 60.456 ;
    END
  END a[352]
  PIN a[353]
    DIRECTION INPUT ;
    USE SIGNAL ;
    PORT
      LAYER M3 ;
        RECT  82.332 60.419 82.35 60.456 ;
    END
  END a[353]
  PIN a[354]
    DIRECTION INPUT ;
    USE SIGNAL ;
    PORT
      LAYER M3 ;
        RECT  82.404 60.419 82.422 60.456 ;
    END
  END a[354]
  PIN a[355]
    DIRECTION INPUT ;
    USE SIGNAL ;
    PORT
      LAYER M3 ;
        RECT  82.476 60.419 82.494 60.456 ;
    END
  END a[355]
  PIN a[356]
    DIRECTION INPUT ;
    USE SIGNAL ;
    PORT
      LAYER M3 ;
        RECT  82.548 60.419 82.566 60.456 ;
    END
  END a[356]
  PIN a[357]
    DIRECTION INPUT ;
    USE SIGNAL ;
    PORT
      LAYER M3 ;
        RECT  82.62 60.419 82.638 60.456 ;
    END
  END a[357]
  PIN a[358]
    DIRECTION INPUT ;
    USE SIGNAL ;
    PORT
      LAYER M3 ;
        RECT  82.692 60.419 82.71 60.456 ;
    END
  END a[358]
  PIN a[359]
    DIRECTION INPUT ;
    USE SIGNAL ;
    PORT
      LAYER M3 ;
        RECT  82.764 60.419 82.782 60.456 ;
    END
  END a[359]
  PIN a[35]
    DIRECTION INPUT ;
    USE SIGNAL ;
    PORT
      LAYER M3 ;
        RECT  10.476 60.419 10.494 60.456 ;
    END
  END a[35]
  PIN a[360]
    DIRECTION INPUT ;
    USE SIGNAL ;
    PORT
      LAYER M3 ;
        RECT  82.836 60.419 82.854 60.456 ;
    END
  END a[360]
  PIN a[361]
    DIRECTION INPUT ;
    USE SIGNAL ;
    PORT
      LAYER M3 ;
        RECT  82.908 60.419 82.926 60.456 ;
    END
  END a[361]
  PIN a[362]
    DIRECTION INPUT ;
    USE SIGNAL ;
    PORT
      LAYER M3 ;
        RECT  82.98 60.419 82.998 60.456 ;
    END
  END a[362]
  PIN a[363]
    DIRECTION INPUT ;
    USE SIGNAL ;
    PORT
      LAYER M3 ;
        RECT  83.052 60.419 83.07 60.456 ;
    END
  END a[363]
  PIN a[364]
    DIRECTION INPUT ;
    USE SIGNAL ;
    PORT
      LAYER M3 ;
        RECT  83.124 60.419 83.142 60.456 ;
    END
  END a[364]
  PIN a[365]
    DIRECTION INPUT ;
    USE SIGNAL ;
    PORT
      LAYER M3 ;
        RECT  83.196 60.419 83.214 60.456 ;
    END
  END a[365]
  PIN a[366]
    DIRECTION INPUT ;
    USE SIGNAL ;
    PORT
      LAYER M3 ;
        RECT  83.268 60.419 83.286 60.456 ;
    END
  END a[366]
  PIN a[367]
    DIRECTION INPUT ;
    USE SIGNAL ;
    PORT
      LAYER M3 ;
        RECT  83.34 60.419 83.358 60.456 ;
    END
  END a[367]
  PIN a[368]
    DIRECTION INPUT ;
    USE SIGNAL ;
    PORT
      LAYER M3 ;
        RECT  83.412 60.419 83.43 60.456 ;
    END
  END a[368]
  PIN a[369]
    DIRECTION INPUT ;
    USE SIGNAL ;
    PORT
      LAYER M3 ;
        RECT  83.484 60.419 83.502 60.456 ;
    END
  END a[369]
  PIN a[36]
    DIRECTION INPUT ;
    USE SIGNAL ;
    PORT
      LAYER M3 ;
        RECT  10.548 60.419 10.566 60.456 ;
    END
  END a[36]
  PIN a[370]
    DIRECTION INPUT ;
    USE SIGNAL ;
    PORT
      LAYER M3 ;
        RECT  83.556 60.419 83.574 60.456 ;
    END
  END a[370]
  PIN a[371]
    DIRECTION INPUT ;
    USE SIGNAL ;
    PORT
      LAYER M3 ;
        RECT  83.628 60.419 83.646 60.456 ;
    END
  END a[371]
  PIN a[372]
    DIRECTION INPUT ;
    USE SIGNAL ;
    PORT
      LAYER M3 ;
        RECT  83.7 60.419 83.718 60.456 ;
    END
  END a[372]
  PIN a[373]
    DIRECTION INPUT ;
    USE SIGNAL ;
    PORT
      LAYER M3 ;
        RECT  83.772 60.419 83.79 60.456 ;
    END
  END a[373]
  PIN a[374]
    DIRECTION INPUT ;
    USE SIGNAL ;
    PORT
      LAYER M3 ;
        RECT  83.844 60.419 83.862 60.456 ;
    END
  END a[374]
  PIN a[375]
    DIRECTION INPUT ;
    USE SIGNAL ;
    PORT
      LAYER M3 ;
        RECT  83.916 60.419 83.934 60.456 ;
    END
  END a[375]
  PIN a[376]
    DIRECTION INPUT ;
    USE SIGNAL ;
    PORT
      LAYER M3 ;
        RECT  83.988 60.419 84.006 60.456 ;
    END
  END a[376]
  PIN a[377]
    DIRECTION INPUT ;
    USE SIGNAL ;
    PORT
      LAYER M3 ;
        RECT  84.06 60.419 84.078 60.456 ;
    END
  END a[377]
  PIN a[378]
    DIRECTION INPUT ;
    USE SIGNAL ;
    PORT
      LAYER M3 ;
        RECT  84.132 60.419 84.15 60.456 ;
    END
  END a[378]
  PIN a[379]
    DIRECTION INPUT ;
    USE SIGNAL ;
    PORT
      LAYER M3 ;
        RECT  84.204 60.419 84.222 60.456 ;
    END
  END a[379]
  PIN a[37]
    DIRECTION INPUT ;
    USE SIGNAL ;
    PORT
      LAYER M3 ;
        RECT  10.62 60.419 10.638 60.456 ;
    END
  END a[37]
  PIN a[380]
    DIRECTION INPUT ;
    USE SIGNAL ;
    PORT
      LAYER M3 ;
        RECT  84.276 60.419 84.294 60.456 ;
    END
  END a[380]
  PIN a[381]
    DIRECTION INPUT ;
    USE SIGNAL ;
    PORT
      LAYER M3 ;
        RECT  84.348 60.419 84.366 60.456 ;
    END
  END a[381]
  PIN a[382]
    DIRECTION INPUT ;
    USE SIGNAL ;
    PORT
      LAYER M3 ;
        RECT  84.42 60.419 84.438 60.456 ;
    END
  END a[382]
  PIN a[383]
    DIRECTION INPUT ;
    USE SIGNAL ;
    PORT
      LAYER M3 ;
        RECT  84.492 60.419 84.51 60.456 ;
    END
  END a[383]
  PIN a[384]
    DIRECTION INPUT ;
    USE SIGNAL ;
    PORT
      LAYER M5 ;
        RECT  58.896 60.372 58.92 60.456 ;
    END
  END a[384]
  PIN a[385]
    DIRECTION INPUT ;
    USE SIGNAL ;
    PORT
      LAYER M5 ;
        RECT  58.992 60.372 59.016 60.456 ;
    END
  END a[385]
  PIN a[386]
    DIRECTION INPUT ;
    USE SIGNAL ;
    PORT
      LAYER M5 ;
        RECT  59.088 60.372 59.112 60.456 ;
    END
  END a[386]
  PIN a[387]
    DIRECTION INPUT ;
    USE SIGNAL ;
    PORT
      LAYER M5 ;
        RECT  59.184 60.372 59.208 60.456 ;
    END
  END a[387]
  PIN a[388]
    DIRECTION INPUT ;
    USE SIGNAL ;
    PORT
      LAYER M5 ;
        RECT  59.28 60.372 59.304 60.456 ;
    END
  END a[388]
  PIN a[389]
    DIRECTION INPUT ;
    USE SIGNAL ;
    PORT
      LAYER M5 ;
        RECT  59.376 60.372 59.4 60.456 ;
    END
  END a[389]
  PIN a[38]
    DIRECTION INPUT ;
    USE SIGNAL ;
    PORT
      LAYER M3 ;
        RECT  10.692 60.419 10.71 60.456 ;
    END
  END a[38]
  PIN a[390]
    DIRECTION INPUT ;
    USE SIGNAL ;
    PORT
      LAYER M5 ;
        RECT  59.472 60.372 59.496 60.456 ;
    END
  END a[390]
  PIN a[391]
    DIRECTION INPUT ;
    USE SIGNAL ;
    PORT
      LAYER M5 ;
        RECT  59.568 60.372 59.592 60.456 ;
    END
  END a[391]
  PIN a[392]
    DIRECTION INPUT ;
    USE SIGNAL ;
    PORT
      LAYER M5 ;
        RECT  59.664 60.372 59.688 60.456 ;
    END
  END a[392]
  PIN a[393]
    DIRECTION INPUT ;
    USE SIGNAL ;
    PORT
      LAYER M5 ;
        RECT  59.76 60.372 59.784 60.456 ;
    END
  END a[393]
  PIN a[394]
    DIRECTION INPUT ;
    USE SIGNAL ;
    PORT
      LAYER M5 ;
        RECT  59.856 60.372 59.88 60.456 ;
    END
  END a[394]
  PIN a[395]
    DIRECTION INPUT ;
    USE SIGNAL ;
    PORT
      LAYER M5 ;
        RECT  59.952 60.372 59.976 60.456 ;
    END
  END a[395]
  PIN a[396]
    DIRECTION INPUT ;
    USE SIGNAL ;
    PORT
      LAYER M5 ;
        RECT  60.048 60.372 60.072 60.456 ;
    END
  END a[396]
  PIN a[397]
    DIRECTION INPUT ;
    USE SIGNAL ;
    PORT
      LAYER M5 ;
        RECT  60.144 60.372 60.168 60.456 ;
    END
  END a[397]
  PIN a[398]
    DIRECTION INPUT ;
    USE SIGNAL ;
    PORT
      LAYER M5 ;
        RECT  60.24 60.372 60.264 60.456 ;
    END
  END a[398]
  PIN a[399]
    DIRECTION INPUT ;
    USE SIGNAL ;
    PORT
      LAYER M5 ;
        RECT  60.336 60.372 60.36 60.456 ;
    END
  END a[399]
  PIN a[39]
    DIRECTION INPUT ;
    USE SIGNAL ;
    PORT
      LAYER M3 ;
        RECT  10.764 60.419 10.782 60.456 ;
    END
  END a[39]
  PIN a[3]
    DIRECTION INPUT ;
    USE SIGNAL ;
    PORT
      LAYER M3 ;
        RECT  39.276 60.419 39.294 60.456 ;
    END
  END a[3]
  PIN a[400]
    DIRECTION INPUT ;
    USE SIGNAL ;
    PORT
      LAYER M5 ;
        RECT  60.432 60.372 60.456 60.456 ;
    END
  END a[400]
  PIN a[401]
    DIRECTION INPUT ;
    USE SIGNAL ;
    PORT
      LAYER M5 ;
        RECT  60.528 60.372 60.552 60.456 ;
    END
  END a[401]
  PIN a[402]
    DIRECTION INPUT ;
    USE SIGNAL ;
    PORT
      LAYER M5 ;
        RECT  60.624 60.372 60.648 60.456 ;
    END
  END a[402]
  PIN a[403]
    DIRECTION INPUT ;
    USE SIGNAL ;
    PORT
      LAYER M5 ;
        RECT  60.72 60.372 60.744 60.456 ;
    END
  END a[403]
  PIN a[404]
    DIRECTION INPUT ;
    USE SIGNAL ;
    PORT
      LAYER M5 ;
        RECT  60.816 60.372 60.84 60.456 ;
    END
  END a[404]
  PIN a[405]
    DIRECTION INPUT ;
    USE SIGNAL ;
    PORT
      LAYER M5 ;
        RECT  60.912 60.372 60.936 60.456 ;
    END
  END a[405]
  PIN a[406]
    DIRECTION INPUT ;
    USE SIGNAL ;
    PORT
      LAYER M5 ;
        RECT  61.008 60.372 61.032 60.456 ;
    END
  END a[406]
  PIN a[407]
    DIRECTION INPUT ;
    USE SIGNAL ;
    PORT
      LAYER M5 ;
        RECT  61.104 60.372 61.128 60.456 ;
    END
  END a[407]
  PIN a[408]
    DIRECTION INPUT ;
    USE SIGNAL ;
    PORT
      LAYER M5 ;
        RECT  61.2 60.372 61.224 60.456 ;
    END
  END a[408]
  PIN a[409]
    DIRECTION INPUT ;
    USE SIGNAL ;
    PORT
      LAYER M5 ;
        RECT  61.296 60.372 61.32 60.456 ;
    END
  END a[409]
  PIN a[40]
    DIRECTION INPUT ;
    USE SIGNAL ;
    PORT
      LAYER M3 ;
        RECT  10.836 60.419 10.854 60.456 ;
    END
  END a[40]
  PIN a[410]
    DIRECTION INPUT ;
    USE SIGNAL ;
    PORT
      LAYER M5 ;
        RECT  61.392 60.372 61.416 60.456 ;
    END
  END a[410]
  PIN a[411]
    DIRECTION INPUT ;
    USE SIGNAL ;
    PORT
      LAYER M5 ;
        RECT  61.488 60.372 61.512 60.456 ;
    END
  END a[411]
  PIN a[412]
    DIRECTION INPUT ;
    USE SIGNAL ;
    PORT
      LAYER M5 ;
        RECT  61.584 60.372 61.608 60.456 ;
    END
  END a[412]
  PIN a[413]
    DIRECTION INPUT ;
    USE SIGNAL ;
    PORT
      LAYER M5 ;
        RECT  61.68 60.372 61.704 60.456 ;
    END
  END a[413]
  PIN a[414]
    DIRECTION INPUT ;
    USE SIGNAL ;
    PORT
      LAYER M5 ;
        RECT  61.776 60.372 61.8 60.456 ;
    END
  END a[414]
  PIN a[415]
    DIRECTION INPUT ;
    USE SIGNAL ;
    PORT
      LAYER M5 ;
        RECT  61.872 60.372 61.896 60.456 ;
    END
  END a[415]
  PIN a[416]
    DIRECTION INPUT ;
    USE SIGNAL ;
    PORT
      LAYER M3 ;
        RECT  46.548 60.419 46.566 60.456 ;
    END
  END a[416]
  PIN a[417]
    DIRECTION INPUT ;
    USE SIGNAL ;
    PORT
      LAYER M3 ;
        RECT  46.62 60.419 46.638 60.456 ;
    END
  END a[417]
  PIN a[418]
    DIRECTION INPUT ;
    USE SIGNAL ;
    PORT
      LAYER M3 ;
        RECT  46.692 60.419 46.71 60.456 ;
    END
  END a[418]
  PIN a[419]
    DIRECTION INPUT ;
    USE SIGNAL ;
    PORT
      LAYER M3 ;
        RECT  46.764 60.419 46.782 60.456 ;
    END
  END a[419]
  PIN a[41]
    DIRECTION INPUT ;
    USE SIGNAL ;
    PORT
      LAYER M3 ;
        RECT  10.908 60.419 10.926 60.456 ;
    END
  END a[41]
  PIN a[420]
    DIRECTION INPUT ;
    USE SIGNAL ;
    PORT
      LAYER M3 ;
        RECT  46.836 60.419 46.854 60.456 ;
    END
  END a[420]
  PIN a[421]
    DIRECTION INPUT ;
    USE SIGNAL ;
    PORT
      LAYER M3 ;
        RECT  46.908 60.419 46.926 60.456 ;
    END
  END a[421]
  PIN a[422]
    DIRECTION INPUT ;
    USE SIGNAL ;
    PORT
      LAYER M3 ;
        RECT  46.98 60.419 46.998 60.456 ;
    END
  END a[422]
  PIN a[423]
    DIRECTION INPUT ;
    USE SIGNAL ;
    PORT
      LAYER M3 ;
        RECT  47.052 60.419 47.07 60.456 ;
    END
  END a[423]
  PIN a[424]
    DIRECTION INPUT ;
    USE SIGNAL ;
    PORT
      LAYER M3 ;
        RECT  47.124 60.419 47.142 60.456 ;
    END
  END a[424]
  PIN a[425]
    DIRECTION INPUT ;
    USE SIGNAL ;
    PORT
      LAYER M3 ;
        RECT  47.196 60.419 47.214 60.456 ;
    END
  END a[425]
  PIN a[426]
    DIRECTION INPUT ;
    USE SIGNAL ;
    PORT
      LAYER M3 ;
        RECT  47.268 60.419 47.286 60.456 ;
    END
  END a[426]
  PIN a[427]
    DIRECTION INPUT ;
    USE SIGNAL ;
    PORT
      LAYER M3 ;
        RECT  47.34 60.419 47.358 60.456 ;
    END
  END a[427]
  PIN a[428]
    DIRECTION INPUT ;
    USE SIGNAL ;
    PORT
      LAYER M3 ;
        RECT  47.412 60.419 47.43 60.456 ;
    END
  END a[428]
  PIN a[429]
    DIRECTION INPUT ;
    USE SIGNAL ;
    PORT
      LAYER M3 ;
        RECT  47.484 60.419 47.502 60.456 ;
    END
  END a[429]
  PIN a[42]
    DIRECTION INPUT ;
    USE SIGNAL ;
    PORT
      LAYER M3 ;
        RECT  10.98 60.419 10.998 60.456 ;
    END
  END a[42]
  PIN a[430]
    DIRECTION INPUT ;
    USE SIGNAL ;
    PORT
      LAYER M3 ;
        RECT  47.556 60.419 47.574 60.456 ;
    END
  END a[430]
  PIN a[431]
    DIRECTION INPUT ;
    USE SIGNAL ;
    PORT
      LAYER M3 ;
        RECT  47.628 60.419 47.646 60.456 ;
    END
  END a[431]
  PIN a[432]
    DIRECTION INPUT ;
    USE SIGNAL ;
    PORT
      LAYER M3 ;
        RECT  47.7 60.419 47.718 60.456 ;
    END
  END a[432]
  PIN a[433]
    DIRECTION INPUT ;
    USE SIGNAL ;
    PORT
      LAYER M3 ;
        RECT  47.772 60.419 47.79 60.456 ;
    END
  END a[433]
  PIN a[434]
    DIRECTION INPUT ;
    USE SIGNAL ;
    PORT
      LAYER M3 ;
        RECT  47.844 60.419 47.862 60.456 ;
    END
  END a[434]
  PIN a[435]
    DIRECTION INPUT ;
    USE SIGNAL ;
    PORT
      LAYER M3 ;
        RECT  47.916 60.419 47.934 60.456 ;
    END
  END a[435]
  PIN a[436]
    DIRECTION INPUT ;
    USE SIGNAL ;
    PORT
      LAYER M3 ;
        RECT  47.988 60.419 48.006 60.456 ;
    END
  END a[436]
  PIN a[437]
    DIRECTION INPUT ;
    USE SIGNAL ;
    PORT
      LAYER M3 ;
        RECT  48.06 60.419 48.078 60.456 ;
    END
  END a[437]
  PIN a[438]
    DIRECTION INPUT ;
    USE SIGNAL ;
    PORT
      LAYER M3 ;
        RECT  48.132 60.419 48.15 60.456 ;
    END
  END a[438]
  PIN a[439]
    DIRECTION INPUT ;
    USE SIGNAL ;
    PORT
      LAYER M3 ;
        RECT  48.204 60.419 48.222 60.456 ;
    END
  END a[439]
  PIN a[43]
    DIRECTION INPUT ;
    USE SIGNAL ;
    PORT
      LAYER M3 ;
        RECT  11.052 60.419 11.07 60.456 ;
    END
  END a[43]
  PIN a[440]
    DIRECTION INPUT ;
    USE SIGNAL ;
    PORT
      LAYER M3 ;
        RECT  48.276 60.419 48.294 60.456 ;
    END
  END a[440]
  PIN a[441]
    DIRECTION INPUT ;
    USE SIGNAL ;
    PORT
      LAYER M3 ;
        RECT  48.348 60.419 48.366 60.456 ;
    END
  END a[441]
  PIN a[442]
    DIRECTION INPUT ;
    USE SIGNAL ;
    PORT
      LAYER M3 ;
        RECT  48.42 60.419 48.438 60.456 ;
    END
  END a[442]
  PIN a[443]
    DIRECTION INPUT ;
    USE SIGNAL ;
    PORT
      LAYER M3 ;
        RECT  48.492 60.419 48.51 60.456 ;
    END
  END a[443]
  PIN a[444]
    DIRECTION INPUT ;
    USE SIGNAL ;
    PORT
      LAYER M3 ;
        RECT  48.564 60.419 48.582 60.456 ;
    END
  END a[444]
  PIN a[445]
    DIRECTION INPUT ;
    USE SIGNAL ;
    PORT
      LAYER M3 ;
        RECT  48.636 60.419 48.654 60.456 ;
    END
  END a[445]
  PIN a[446]
    DIRECTION INPUT ;
    USE SIGNAL ;
    PORT
      LAYER M3 ;
        RECT  48.708 60.419 48.726 60.456 ;
    END
  END a[446]
  PIN a[447]
    DIRECTION INPUT ;
    USE SIGNAL ;
    PORT
      LAYER M3 ;
        RECT  48.78 60.419 48.798 60.456 ;
    END
  END a[447]
  PIN a[448]
    DIRECTION INPUT ;
    USE SIGNAL ;
    PORT
      LAYER M3 ;
        RECT  20.052 60.419 20.07 60.456 ;
    END
  END a[448]
  PIN a[449]
    DIRECTION INPUT ;
    USE SIGNAL ;
    PORT
      LAYER M3 ;
        RECT  20.124 60.419 20.142 60.456 ;
    END
  END a[449]
  PIN a[44]
    DIRECTION INPUT ;
    USE SIGNAL ;
    PORT
      LAYER M3 ;
        RECT  11.124 60.419 11.142 60.456 ;
    END
  END a[44]
  PIN a[450]
    DIRECTION INPUT ;
    USE SIGNAL ;
    PORT
      LAYER M3 ;
        RECT  20.196 60.419 20.214 60.456 ;
    END
  END a[450]
  PIN a[451]
    DIRECTION INPUT ;
    USE SIGNAL ;
    PORT
      LAYER M3 ;
        RECT  20.268 60.419 20.286 60.456 ;
    END
  END a[451]
  PIN a[452]
    DIRECTION INPUT ;
    USE SIGNAL ;
    PORT
      LAYER M3 ;
        RECT  20.34 60.419 20.358 60.456 ;
    END
  END a[452]
  PIN a[453]
    DIRECTION INPUT ;
    USE SIGNAL ;
    PORT
      LAYER M3 ;
        RECT  20.412 60.419 20.43 60.456 ;
    END
  END a[453]
  PIN a[454]
    DIRECTION INPUT ;
    USE SIGNAL ;
    PORT
      LAYER M3 ;
        RECT  20.484 60.419 20.502 60.456 ;
    END
  END a[454]
  PIN a[455]
    DIRECTION INPUT ;
    USE SIGNAL ;
    PORT
      LAYER M3 ;
        RECT  20.556 60.419 20.574 60.456 ;
    END
  END a[455]
  PIN a[456]
    DIRECTION INPUT ;
    USE SIGNAL ;
    PORT
      LAYER M3 ;
        RECT  20.628 60.419 20.646 60.456 ;
    END
  END a[456]
  PIN a[457]
    DIRECTION INPUT ;
    USE SIGNAL ;
    PORT
      LAYER M3 ;
        RECT  20.7 60.419 20.718 60.456 ;
    END
  END a[457]
  PIN a[458]
    DIRECTION INPUT ;
    USE SIGNAL ;
    PORT
      LAYER M3 ;
        RECT  20.772 60.419 20.79 60.456 ;
    END
  END a[458]
  PIN a[459]
    DIRECTION INPUT ;
    USE SIGNAL ;
    PORT
      LAYER M3 ;
        RECT  20.844 60.419 20.862 60.456 ;
    END
  END a[459]
  PIN a[45]
    DIRECTION INPUT ;
    USE SIGNAL ;
    PORT
      LAYER M3 ;
        RECT  11.196 60.419 11.214 60.456 ;
    END
  END a[45]
  PIN a[460]
    DIRECTION INPUT ;
    USE SIGNAL ;
    PORT
      LAYER M3 ;
        RECT  20.916 60.419 20.934 60.456 ;
    END
  END a[460]
  PIN a[461]
    DIRECTION INPUT ;
    USE SIGNAL ;
    PORT
      LAYER M3 ;
        RECT  20.988 60.419 21.006 60.456 ;
    END
  END a[461]
  PIN a[462]
    DIRECTION INPUT ;
    USE SIGNAL ;
    PORT
      LAYER M3 ;
        RECT  21.06 60.419 21.078 60.456 ;
    END
  END a[462]
  PIN a[463]
    DIRECTION INPUT ;
    USE SIGNAL ;
    PORT
      LAYER M3 ;
        RECT  21.132 60.419 21.15 60.456 ;
    END
  END a[463]
  PIN a[464]
    DIRECTION INPUT ;
    USE SIGNAL ;
    PORT
      LAYER M3 ;
        RECT  21.204 60.419 21.222 60.456 ;
    END
  END a[464]
  PIN a[465]
    DIRECTION INPUT ;
    USE SIGNAL ;
    PORT
      LAYER M3 ;
        RECT  21.276 60.419 21.294 60.456 ;
    END
  END a[465]
  PIN a[466]
    DIRECTION INPUT ;
    USE SIGNAL ;
    PORT
      LAYER M3 ;
        RECT  21.348 60.419 21.366 60.456 ;
    END
  END a[466]
  PIN a[467]
    DIRECTION INPUT ;
    USE SIGNAL ;
    PORT
      LAYER M3 ;
        RECT  21.42 60.419 21.438 60.456 ;
    END
  END a[467]
  PIN a[468]
    DIRECTION INPUT ;
    USE SIGNAL ;
    PORT
      LAYER M3 ;
        RECT  21.492 60.419 21.51 60.456 ;
    END
  END a[468]
  PIN a[469]
    DIRECTION INPUT ;
    USE SIGNAL ;
    PORT
      LAYER M3 ;
        RECT  21.564 60.419 21.582 60.456 ;
    END
  END a[469]
  PIN a[46]
    DIRECTION INPUT ;
    USE SIGNAL ;
    PORT
      LAYER M3 ;
        RECT  11.268 60.419 11.286 60.456 ;
    END
  END a[46]
  PIN a[470]
    DIRECTION INPUT ;
    USE SIGNAL ;
    PORT
      LAYER M3 ;
        RECT  21.636 60.419 21.654 60.456 ;
    END
  END a[470]
  PIN a[471]
    DIRECTION INPUT ;
    USE SIGNAL ;
    PORT
      LAYER M3 ;
        RECT  21.708 60.419 21.726 60.456 ;
    END
  END a[471]
  PIN a[472]
    DIRECTION INPUT ;
    USE SIGNAL ;
    PORT
      LAYER M3 ;
        RECT  21.78 60.419 21.798 60.456 ;
    END
  END a[472]
  PIN a[473]
    DIRECTION INPUT ;
    USE SIGNAL ;
    PORT
      LAYER M3 ;
        RECT  21.852 60.419 21.87 60.456 ;
    END
  END a[473]
  PIN a[474]
    DIRECTION INPUT ;
    USE SIGNAL ;
    PORT
      LAYER M3 ;
        RECT  21.924 60.419 21.942 60.456 ;
    END
  END a[474]
  PIN a[475]
    DIRECTION INPUT ;
    USE SIGNAL ;
    PORT
      LAYER M3 ;
        RECT  21.996 60.419 22.014 60.456 ;
    END
  END a[475]
  PIN a[476]
    DIRECTION INPUT ;
    USE SIGNAL ;
    PORT
      LAYER M3 ;
        RECT  22.068 60.419 22.086 60.456 ;
    END
  END a[476]
  PIN a[477]
    DIRECTION INPUT ;
    USE SIGNAL ;
    PORT
      LAYER M3 ;
        RECT  22.14 60.419 22.158 60.456 ;
    END
  END a[477]
  PIN a[478]
    DIRECTION INPUT ;
    USE SIGNAL ;
    PORT
      LAYER M3 ;
        RECT  22.212 60.419 22.23 60.456 ;
    END
  END a[478]
  PIN a[479]
    DIRECTION INPUT ;
    USE SIGNAL ;
    PORT
      LAYER M3 ;
        RECT  22.284 60.419 22.302 60.456 ;
    END
  END a[479]
  PIN a[47]
    DIRECTION INPUT ;
    USE SIGNAL ;
    PORT
      LAYER M3 ;
        RECT  11.34 60.419 11.358 60.456 ;
    END
  END a[47]
  PIN a[480]
    DIRECTION INPUT ;
    USE SIGNAL ;
    PORT
      LAYER M3 ;
        RECT  26.964 60.419 26.982 60.456 ;
    END
  END a[480]
  PIN a[481]
    DIRECTION INPUT ;
    USE SIGNAL ;
    PORT
      LAYER M3 ;
        RECT  27.036 60.419 27.054 60.456 ;
    END
  END a[481]
  PIN a[482]
    DIRECTION INPUT ;
    USE SIGNAL ;
    PORT
      LAYER M3 ;
        RECT  27.108 60.419 27.126 60.456 ;
    END
  END a[482]
  PIN a[483]
    DIRECTION INPUT ;
    USE SIGNAL ;
    PORT
      LAYER M3 ;
        RECT  27.18 60.419 27.198 60.456 ;
    END
  END a[483]
  PIN a[484]
    DIRECTION INPUT ;
    USE SIGNAL ;
    PORT
      LAYER M3 ;
        RECT  27.252 60.419 27.27 60.456 ;
    END
  END a[484]
  PIN a[485]
    DIRECTION INPUT ;
    USE SIGNAL ;
    PORT
      LAYER M3 ;
        RECT  27.324 60.419 27.342 60.456 ;
    END
  END a[485]
  PIN a[486]
    DIRECTION INPUT ;
    USE SIGNAL ;
    PORT
      LAYER M3 ;
        RECT  27.396 60.419 27.414 60.456 ;
    END
  END a[486]
  PIN a[487]
    DIRECTION INPUT ;
    USE SIGNAL ;
    PORT
      LAYER M3 ;
        RECT  27.468 60.419 27.486 60.456 ;
    END
  END a[487]
  PIN a[488]
    DIRECTION INPUT ;
    USE SIGNAL ;
    PORT
      LAYER M3 ;
        RECT  27.54 60.419 27.558 60.456 ;
    END
  END a[488]
  PIN a[489]
    DIRECTION INPUT ;
    USE SIGNAL ;
    PORT
      LAYER M3 ;
        RECT  27.612 60.419 27.63 60.456 ;
    END
  END a[489]
  PIN a[48]
    DIRECTION INPUT ;
    USE SIGNAL ;
    PORT
      LAYER M3 ;
        RECT  11.412 60.419 11.43 60.456 ;
    END
  END a[48]
  PIN a[490]
    DIRECTION INPUT ;
    USE SIGNAL ;
    PORT
      LAYER M3 ;
        RECT  27.684 60.419 27.702 60.456 ;
    END
  END a[490]
  PIN a[491]
    DIRECTION INPUT ;
    USE SIGNAL ;
    PORT
      LAYER M3 ;
        RECT  27.756 60.419 27.774 60.456 ;
    END
  END a[491]
  PIN a[492]
    DIRECTION INPUT ;
    USE SIGNAL ;
    PORT
      LAYER M3 ;
        RECT  27.828 60.419 27.846 60.456 ;
    END
  END a[492]
  PIN a[493]
    DIRECTION INPUT ;
    USE SIGNAL ;
    PORT
      LAYER M3 ;
        RECT  27.9 60.419 27.918 60.456 ;
    END
  END a[493]
  PIN a[494]
    DIRECTION INPUT ;
    USE SIGNAL ;
    PORT
      LAYER M3 ;
        RECT  27.972 60.419 27.99 60.456 ;
    END
  END a[494]
  PIN a[495]
    DIRECTION INPUT ;
    USE SIGNAL ;
    PORT
      LAYER M3 ;
        RECT  28.044 60.419 28.062 60.456 ;
    END
  END a[495]
  PIN a[496]
    DIRECTION INPUT ;
    USE SIGNAL ;
    PORT
      LAYER M3 ;
        RECT  28.116 60.419 28.134 60.456 ;
    END
  END a[496]
  PIN a[497]
    DIRECTION INPUT ;
    USE SIGNAL ;
    PORT
      LAYER M3 ;
        RECT  28.188 60.419 28.206 60.456 ;
    END
  END a[497]
  PIN a[498]
    DIRECTION INPUT ;
    USE SIGNAL ;
    PORT
      LAYER M3 ;
        RECT  28.26 60.419 28.278 60.456 ;
    END
  END a[498]
  PIN a[499]
    DIRECTION INPUT ;
    USE SIGNAL ;
    PORT
      LAYER M3 ;
        RECT  28.332 60.419 28.35 60.456 ;
    END
  END a[499]
  PIN a[49]
    DIRECTION INPUT ;
    USE SIGNAL ;
    PORT
      LAYER M3 ;
        RECT  11.484 60.419 11.502 60.456 ;
    END
  END a[49]
  PIN a[4]
    DIRECTION INPUT ;
    USE SIGNAL ;
    PORT
      LAYER M3 ;
        RECT  39.348 60.419 39.366 60.456 ;
    END
  END a[4]
  PIN a[500]
    DIRECTION INPUT ;
    USE SIGNAL ;
    PORT
      LAYER M3 ;
        RECT  28.404 60.419 28.422 60.456 ;
    END
  END a[500]
  PIN a[501]
    DIRECTION INPUT ;
    USE SIGNAL ;
    PORT
      LAYER M3 ;
        RECT  28.476 60.419 28.494 60.456 ;
    END
  END a[501]
  PIN a[502]
    DIRECTION INPUT ;
    USE SIGNAL ;
    PORT
      LAYER M3 ;
        RECT  28.548 60.419 28.566 60.456 ;
    END
  END a[502]
  PIN a[503]
    DIRECTION INPUT ;
    USE SIGNAL ;
    PORT
      LAYER M3 ;
        RECT  28.62 60.419 28.638 60.456 ;
    END
  END a[503]
  PIN a[504]
    DIRECTION INPUT ;
    USE SIGNAL ;
    PORT
      LAYER M3 ;
        RECT  28.692 60.419 28.71 60.456 ;
    END
  END a[504]
  PIN a[505]
    DIRECTION INPUT ;
    USE SIGNAL ;
    PORT
      LAYER M3 ;
        RECT  28.764 60.419 28.782 60.456 ;
    END
  END a[505]
  PIN a[506]
    DIRECTION INPUT ;
    USE SIGNAL ;
    PORT
      LAYER M3 ;
        RECT  28.836 60.419 28.854 60.456 ;
    END
  END a[506]
  PIN a[507]
    DIRECTION INPUT ;
    USE SIGNAL ;
    PORT
      LAYER M3 ;
        RECT  28.908 60.419 28.926 60.456 ;
    END
  END a[507]
  PIN a[508]
    DIRECTION INPUT ;
    USE SIGNAL ;
    PORT
      LAYER M3 ;
        RECT  28.98 60.419 28.998 60.456 ;
    END
  END a[508]
  PIN a[509]
    DIRECTION INPUT ;
    USE SIGNAL ;
    PORT
      LAYER M3 ;
        RECT  29.052 60.419 29.07 60.456 ;
    END
  END a[509]
  PIN a[50]
    DIRECTION INPUT ;
    USE SIGNAL ;
    PORT
      LAYER M3 ;
        RECT  11.556 60.419 11.574 60.456 ;
    END
  END a[50]
  PIN a[510]
    DIRECTION INPUT ;
    USE SIGNAL ;
    PORT
      LAYER M3 ;
        RECT  29.124 60.419 29.142 60.456 ;
    END
  END a[510]
  PIN a[511]
    DIRECTION INPUT ;
    USE SIGNAL ;
    PORT
      LAYER M3 ;
        RECT  29.196 60.419 29.214 60.456 ;
    END
  END a[511]
  PIN a[512]
    DIRECTION INPUT ;
    USE SIGNAL ;
    PORT
      LAYER M5 ;
        RECT  11.28 60.372 11.304 60.456 ;
    END
  END a[512]
  PIN a[513]
    DIRECTION INPUT ;
    USE SIGNAL ;
    PORT
      LAYER M5 ;
        RECT  11.376 60.372 11.4 60.456 ;
    END
  END a[513]
  PIN a[514]
    DIRECTION INPUT ;
    USE SIGNAL ;
    PORT
      LAYER M5 ;
        RECT  11.472 60.372 11.496 60.456 ;
    END
  END a[514]
  PIN a[515]
    DIRECTION INPUT ;
    USE SIGNAL ;
    PORT
      LAYER M5 ;
        RECT  11.568 60.372 11.592 60.456 ;
    END
  END a[515]
  PIN a[516]
    DIRECTION INPUT ;
    USE SIGNAL ;
    PORT
      LAYER M5 ;
        RECT  11.664 60.372 11.688 60.456 ;
    END
  END a[516]
  PIN a[517]
    DIRECTION INPUT ;
    USE SIGNAL ;
    PORT
      LAYER M5 ;
        RECT  11.76 60.372 11.784 60.456 ;
    END
  END a[517]
  PIN a[518]
    DIRECTION INPUT ;
    USE SIGNAL ;
    PORT
      LAYER M5 ;
        RECT  11.856 60.372 11.88 60.456 ;
    END
  END a[518]
  PIN a[519]
    DIRECTION INPUT ;
    USE SIGNAL ;
    PORT
      LAYER M5 ;
        RECT  11.952 60.372 11.976 60.456 ;
    END
  END a[519]
  PIN a[51]
    DIRECTION INPUT ;
    USE SIGNAL ;
    PORT
      LAYER M3 ;
        RECT  11.628 60.419 11.646 60.456 ;
    END
  END a[51]
  PIN a[520]
    DIRECTION INPUT ;
    USE SIGNAL ;
    PORT
      LAYER M5 ;
        RECT  12.048 60.372 12.072 60.456 ;
    END
  END a[520]
  PIN a[521]
    DIRECTION INPUT ;
    USE SIGNAL ;
    PORT
      LAYER M5 ;
        RECT  12.144 60.372 12.168 60.456 ;
    END
  END a[521]
  PIN a[522]
    DIRECTION INPUT ;
    USE SIGNAL ;
    PORT
      LAYER M5 ;
        RECT  12.24 60.372 12.264 60.456 ;
    END
  END a[522]
  PIN a[523]
    DIRECTION INPUT ;
    USE SIGNAL ;
    PORT
      LAYER M5 ;
        RECT  12.336 60.372 12.36 60.456 ;
    END
  END a[523]
  PIN a[524]
    DIRECTION INPUT ;
    USE SIGNAL ;
    PORT
      LAYER M5 ;
        RECT  12.432 60.372 12.456 60.456 ;
    END
  END a[524]
  PIN a[525]
    DIRECTION INPUT ;
    USE SIGNAL ;
    PORT
      LAYER M5 ;
        RECT  12.528 60.372 12.552 60.456 ;
    END
  END a[525]
  PIN a[526]
    DIRECTION INPUT ;
    USE SIGNAL ;
    PORT
      LAYER M5 ;
        RECT  12.624 60.372 12.648 60.456 ;
    END
  END a[526]
  PIN a[527]
    DIRECTION INPUT ;
    USE SIGNAL ;
    PORT
      LAYER M5 ;
        RECT  12.72 60.372 12.744 60.456 ;
    END
  END a[527]
  PIN a[528]
    DIRECTION INPUT ;
    USE SIGNAL ;
    PORT
      LAYER M5 ;
        RECT  12.816 60.372 12.84 60.456 ;
    END
  END a[528]
  PIN a[529]
    DIRECTION INPUT ;
    USE SIGNAL ;
    PORT
      LAYER M5 ;
        RECT  12.912 60.372 12.936 60.456 ;
    END
  END a[529]
  PIN a[52]
    DIRECTION INPUT ;
    USE SIGNAL ;
    PORT
      LAYER M3 ;
        RECT  11.7 60.419 11.718 60.456 ;
    END
  END a[52]
  PIN a[530]
    DIRECTION INPUT ;
    USE SIGNAL ;
    PORT
      LAYER M5 ;
        RECT  13.008 60.372 13.032 60.456 ;
    END
  END a[530]
  PIN a[531]
    DIRECTION INPUT ;
    USE SIGNAL ;
    PORT
      LAYER M5 ;
        RECT  13.104 60.372 13.128 60.456 ;
    END
  END a[531]
  PIN a[532]
    DIRECTION INPUT ;
    USE SIGNAL ;
    PORT
      LAYER M5 ;
        RECT  13.2 60.372 13.224 60.456 ;
    END
  END a[532]
  PIN a[533]
    DIRECTION INPUT ;
    USE SIGNAL ;
    PORT
      LAYER M5 ;
        RECT  13.296 60.372 13.32 60.456 ;
    END
  END a[533]
  PIN a[534]
    DIRECTION INPUT ;
    USE SIGNAL ;
    PORT
      LAYER M5 ;
        RECT  13.392 60.372 13.416 60.456 ;
    END
  END a[534]
  PIN a[535]
    DIRECTION INPUT ;
    USE SIGNAL ;
    PORT
      LAYER M5 ;
        RECT  13.488 60.372 13.512 60.456 ;
    END
  END a[535]
  PIN a[536]
    DIRECTION INPUT ;
    USE SIGNAL ;
    PORT
      LAYER M5 ;
        RECT  13.584 60.372 13.608 60.456 ;
    END
  END a[536]
  PIN a[537]
    DIRECTION INPUT ;
    USE SIGNAL ;
    PORT
      LAYER M5 ;
        RECT  13.68 60.372 13.704 60.456 ;
    END
  END a[537]
  PIN a[538]
    DIRECTION INPUT ;
    USE SIGNAL ;
    PORT
      LAYER M5 ;
        RECT  13.776 60.372 13.8 60.456 ;
    END
  END a[538]
  PIN a[539]
    DIRECTION INPUT ;
    USE SIGNAL ;
    PORT
      LAYER M5 ;
        RECT  13.872 60.372 13.896 60.456 ;
    END
  END a[539]
  PIN a[53]
    DIRECTION INPUT ;
    USE SIGNAL ;
    PORT
      LAYER M3 ;
        RECT  11.772 60.419 11.79 60.456 ;
    END
  END a[53]
  PIN a[540]
    DIRECTION INPUT ;
    USE SIGNAL ;
    PORT
      LAYER M5 ;
        RECT  13.968 60.372 13.992 60.456 ;
    END
  END a[540]
  PIN a[541]
    DIRECTION INPUT ;
    USE SIGNAL ;
    PORT
      LAYER M5 ;
        RECT  14.064 60.372 14.088 60.456 ;
    END
  END a[541]
  PIN a[542]
    DIRECTION INPUT ;
    USE SIGNAL ;
    PORT
      LAYER M5 ;
        RECT  14.16 60.372 14.184 60.456 ;
    END
  END a[542]
  PIN a[543]
    DIRECTION INPUT ;
    USE SIGNAL ;
    PORT
      LAYER M5 ;
        RECT  14.256 60.372 14.28 60.456 ;
    END
  END a[543]
  PIN a[544]
    DIRECTION INPUT ;
    USE SIGNAL ;
    PORT
      LAYER M5 ;
        RECT  14.352 60.372 14.376 60.456 ;
    END
  END a[544]
  PIN a[545]
    DIRECTION INPUT ;
    USE SIGNAL ;
    PORT
      LAYER M5 ;
        RECT  14.448 60.372 14.472 60.456 ;
    END
  END a[545]
  PIN a[546]
    DIRECTION INPUT ;
    USE SIGNAL ;
    PORT
      LAYER M5 ;
        RECT  14.544 60.372 14.568 60.456 ;
    END
  END a[546]
  PIN a[547]
    DIRECTION INPUT ;
    USE SIGNAL ;
    PORT
      LAYER M5 ;
        RECT  14.64 60.372 14.664 60.456 ;
    END
  END a[547]
  PIN a[548]
    DIRECTION INPUT ;
    USE SIGNAL ;
    PORT
      LAYER M5 ;
        RECT  14.736 60.372 14.76 60.456 ;
    END
  END a[548]
  PIN a[549]
    DIRECTION INPUT ;
    USE SIGNAL ;
    PORT
      LAYER M5 ;
        RECT  14.832 60.372 14.856 60.456 ;
    END
  END a[549]
  PIN a[54]
    DIRECTION INPUT ;
    USE SIGNAL ;
    PORT
      LAYER M3 ;
        RECT  11.844 60.419 11.862 60.456 ;
    END
  END a[54]
  PIN a[550]
    DIRECTION INPUT ;
    USE SIGNAL ;
    PORT
      LAYER M5 ;
        RECT  14.928 60.372 14.952 60.456 ;
    END
  END a[550]
  PIN a[551]
    DIRECTION INPUT ;
    USE SIGNAL ;
    PORT
      LAYER M5 ;
        RECT  15.024 60.372 15.048 60.456 ;
    END
  END a[551]
  PIN a[552]
    DIRECTION INPUT ;
    USE SIGNAL ;
    PORT
      LAYER M5 ;
        RECT  15.12 60.372 15.144 60.456 ;
    END
  END a[552]
  PIN a[553]
    DIRECTION INPUT ;
    USE SIGNAL ;
    PORT
      LAYER M5 ;
        RECT  15.216 60.372 15.24 60.456 ;
    END
  END a[553]
  PIN a[554]
    DIRECTION INPUT ;
    USE SIGNAL ;
    PORT
      LAYER M5 ;
        RECT  15.312 60.372 15.336 60.456 ;
    END
  END a[554]
  PIN a[555]
    DIRECTION INPUT ;
    USE SIGNAL ;
    PORT
      LAYER M5 ;
        RECT  15.408 60.372 15.432 60.456 ;
    END
  END a[555]
  PIN a[556]
    DIRECTION INPUT ;
    USE SIGNAL ;
    PORT
      LAYER M5 ;
        RECT  15.504 60.372 15.528 60.456 ;
    END
  END a[556]
  PIN a[557]
    DIRECTION INPUT ;
    USE SIGNAL ;
    PORT
      LAYER M5 ;
        RECT  15.6 60.372 15.624 60.456 ;
    END
  END a[557]
  PIN a[558]
    DIRECTION INPUT ;
    USE SIGNAL ;
    PORT
      LAYER M5 ;
        RECT  15.696 60.372 15.72 60.456 ;
    END
  END a[558]
  PIN a[559]
    DIRECTION INPUT ;
    USE SIGNAL ;
    PORT
      LAYER M5 ;
        RECT  15.792 60.372 15.816 60.456 ;
    END
  END a[559]
  PIN a[55]
    DIRECTION INPUT ;
    USE SIGNAL ;
    PORT
      LAYER M3 ;
        RECT  11.916 60.419 11.934 60.456 ;
    END
  END a[55]
  PIN a[560]
    DIRECTION INPUT ;
    USE SIGNAL ;
    PORT
      LAYER M5 ;
        RECT  15.888 60.372 15.912 60.456 ;
    END
  END a[560]
  PIN a[561]
    DIRECTION INPUT ;
    USE SIGNAL ;
    PORT
      LAYER M5 ;
        RECT  15.984 60.372 16.008 60.456 ;
    END
  END a[561]
  PIN a[562]
    DIRECTION INPUT ;
    USE SIGNAL ;
    PORT
      LAYER M5 ;
        RECT  16.08 60.372 16.104 60.456 ;
    END
  END a[562]
  PIN a[563]
    DIRECTION INPUT ;
    USE SIGNAL ;
    PORT
      LAYER M5 ;
        RECT  16.176 60.372 16.2 60.456 ;
    END
  END a[563]
  PIN a[564]
    DIRECTION INPUT ;
    USE SIGNAL ;
    PORT
      LAYER M5 ;
        RECT  16.272 60.372 16.296 60.456 ;
    END
  END a[564]
  PIN a[565]
    DIRECTION INPUT ;
    USE SIGNAL ;
    PORT
      LAYER M5 ;
        RECT  16.368 60.372 16.392 60.456 ;
    END
  END a[565]
  PIN a[566]
    DIRECTION INPUT ;
    USE SIGNAL ;
    PORT
      LAYER M5 ;
        RECT  16.464 60.372 16.488 60.456 ;
    END
  END a[566]
  PIN a[567]
    DIRECTION INPUT ;
    USE SIGNAL ;
    PORT
      LAYER M5 ;
        RECT  16.56 60.372 16.584 60.456 ;
    END
  END a[567]
  PIN a[568]
    DIRECTION INPUT ;
    USE SIGNAL ;
    PORT
      LAYER M5 ;
        RECT  16.656 60.372 16.68 60.456 ;
    END
  END a[568]
  PIN a[569]
    DIRECTION INPUT ;
    USE SIGNAL ;
    PORT
      LAYER M5 ;
        RECT  16.752 60.372 16.776 60.456 ;
    END
  END a[569]
  PIN a[56]
    DIRECTION INPUT ;
    USE SIGNAL ;
    PORT
      LAYER M3 ;
        RECT  11.988 60.419 12.006 60.456 ;
    END
  END a[56]
  PIN a[570]
    DIRECTION INPUT ;
    USE SIGNAL ;
    PORT
      LAYER M5 ;
        RECT  16.848 60.372 16.872 60.456 ;
    END
  END a[570]
  PIN a[571]
    DIRECTION INPUT ;
    USE SIGNAL ;
    PORT
      LAYER M5 ;
        RECT  16.944 60.372 16.968 60.456 ;
    END
  END a[571]
  PIN a[572]
    DIRECTION INPUT ;
    USE SIGNAL ;
    PORT
      LAYER M5 ;
        RECT  17.04 60.372 17.064 60.456 ;
    END
  END a[572]
  PIN a[573]
    DIRECTION INPUT ;
    USE SIGNAL ;
    PORT
      LAYER M5 ;
        RECT  17.136 60.372 17.16 60.456 ;
    END
  END a[573]
  PIN a[574]
    DIRECTION INPUT ;
    USE SIGNAL ;
    PORT
      LAYER M5 ;
        RECT  17.232 60.372 17.256 60.456 ;
    END
  END a[574]
  PIN a[575]
    DIRECTION INPUT ;
    USE SIGNAL ;
    PORT
      LAYER M5 ;
        RECT  17.328 60.372 17.352 60.456 ;
    END
  END a[575]
  PIN a[576]
    DIRECTION INPUT ;
    USE SIGNAL ;
    PORT
      LAYER M3 ;
        RECT  34.956 60.419 34.974 60.456 ;
    END
  END a[576]
  PIN a[577]
    DIRECTION INPUT ;
    USE SIGNAL ;
    PORT
      LAYER M3 ;
        RECT  35.028 60.419 35.046 60.456 ;
    END
  END a[577]
  PIN a[578]
    DIRECTION INPUT ;
    USE SIGNAL ;
    PORT
      LAYER M3 ;
        RECT  35.1 60.419 35.118 60.456 ;
    END
  END a[578]
  PIN a[579]
    DIRECTION INPUT ;
    USE SIGNAL ;
    PORT
      LAYER M3 ;
        RECT  35.172 60.419 35.19 60.456 ;
    END
  END a[579]
  PIN a[57]
    DIRECTION INPUT ;
    USE SIGNAL ;
    PORT
      LAYER M3 ;
        RECT  12.06 60.419 12.078 60.456 ;
    END
  END a[57]
  PIN a[580]
    DIRECTION INPUT ;
    USE SIGNAL ;
    PORT
      LAYER M3 ;
        RECT  35.244 60.419 35.262 60.456 ;
    END
  END a[580]
  PIN a[581]
    DIRECTION INPUT ;
    USE SIGNAL ;
    PORT
      LAYER M3 ;
        RECT  35.316 60.419 35.334 60.456 ;
    END
  END a[581]
  PIN a[582]
    DIRECTION INPUT ;
    USE SIGNAL ;
    PORT
      LAYER M3 ;
        RECT  35.388 60.419 35.406 60.456 ;
    END
  END a[582]
  PIN a[583]
    DIRECTION INPUT ;
    USE SIGNAL ;
    PORT
      LAYER M3 ;
        RECT  35.46 60.419 35.478 60.456 ;
    END
  END a[583]
  PIN a[584]
    DIRECTION INPUT ;
    USE SIGNAL ;
    PORT
      LAYER M3 ;
        RECT  35.532 60.419 35.55 60.456 ;
    END
  END a[584]
  PIN a[585]
    DIRECTION INPUT ;
    USE SIGNAL ;
    PORT
      LAYER M3 ;
        RECT  35.604 60.419 35.622 60.456 ;
    END
  END a[585]
  PIN a[586]
    DIRECTION INPUT ;
    USE SIGNAL ;
    PORT
      LAYER M3 ;
        RECT  35.676 60.419 35.694 60.456 ;
    END
  END a[586]
  PIN a[587]
    DIRECTION INPUT ;
    USE SIGNAL ;
    PORT
      LAYER M3 ;
        RECT  35.748 60.419 35.766 60.456 ;
    END
  END a[587]
  PIN a[588]
    DIRECTION INPUT ;
    USE SIGNAL ;
    PORT
      LAYER M3 ;
        RECT  35.82 60.419 35.838 60.456 ;
    END
  END a[588]
  PIN a[589]
    DIRECTION INPUT ;
    USE SIGNAL ;
    PORT
      LAYER M3 ;
        RECT  35.892 60.419 35.91 60.456 ;
    END
  END a[589]
  PIN a[58]
    DIRECTION INPUT ;
    USE SIGNAL ;
    PORT
      LAYER M3 ;
        RECT  12.132 60.419 12.15 60.456 ;
    END
  END a[58]
  PIN a[590]
    DIRECTION INPUT ;
    USE SIGNAL ;
    PORT
      LAYER M3 ;
        RECT  35.964 60.419 35.982 60.456 ;
    END
  END a[590]
  PIN a[591]
    DIRECTION INPUT ;
    USE SIGNAL ;
    PORT
      LAYER M3 ;
        RECT  36.036 60.419 36.054 60.456 ;
    END
  END a[591]
  PIN a[592]
    DIRECTION INPUT ;
    USE SIGNAL ;
    PORT
      LAYER M3 ;
        RECT  36.108 60.419 36.126 60.456 ;
    END
  END a[592]
  PIN a[593]
    DIRECTION INPUT ;
    USE SIGNAL ;
    PORT
      LAYER M3 ;
        RECT  36.18 60.419 36.198 60.456 ;
    END
  END a[593]
  PIN a[594]
    DIRECTION INPUT ;
    USE SIGNAL ;
    PORT
      LAYER M3 ;
        RECT  36.252 60.419 36.27 60.456 ;
    END
  END a[594]
  PIN a[595]
    DIRECTION INPUT ;
    USE SIGNAL ;
    PORT
      LAYER M3 ;
        RECT  36.324 60.419 36.342 60.456 ;
    END
  END a[595]
  PIN a[596]
    DIRECTION INPUT ;
    USE SIGNAL ;
    PORT
      LAYER M3 ;
        RECT  36.396 60.419 36.414 60.456 ;
    END
  END a[596]
  PIN a[597]
    DIRECTION INPUT ;
    USE SIGNAL ;
    PORT
      LAYER M3 ;
        RECT  36.468 60.419 36.486 60.456 ;
    END
  END a[597]
  PIN a[598]
    DIRECTION INPUT ;
    USE SIGNAL ;
    PORT
      LAYER M3 ;
        RECT  36.54 60.419 36.558 60.456 ;
    END
  END a[598]
  PIN a[599]
    DIRECTION INPUT ;
    USE SIGNAL ;
    PORT
      LAYER M3 ;
        RECT  36.612 60.419 36.63 60.456 ;
    END
  END a[599]
  PIN a[59]
    DIRECTION INPUT ;
    USE SIGNAL ;
    PORT
      LAYER M3 ;
        RECT  12.204 60.419 12.222 60.456 ;
    END
  END a[59]
  PIN a[5]
    DIRECTION INPUT ;
    USE SIGNAL ;
    PORT
      LAYER M3 ;
        RECT  39.42 60.419 39.438 60.456 ;
    END
  END a[5]
  PIN a[60]
    DIRECTION INPUT ;
    USE SIGNAL ;
    PORT
      LAYER M3 ;
        RECT  12.276 60.419 12.294 60.456 ;
    END
  END a[60]
  PIN a[61]
    DIRECTION INPUT ;
    USE SIGNAL ;
    PORT
      LAYER M3 ;
        RECT  12.348 60.419 12.366 60.456 ;
    END
  END a[61]
  PIN a[62]
    DIRECTION INPUT ;
    USE SIGNAL ;
    PORT
      LAYER M3 ;
        RECT  12.42 60.419 12.438 60.456 ;
    END
  END a[62]
  PIN a[63]
    DIRECTION INPUT ;
    USE SIGNAL ;
    PORT
      LAYER M3 ;
        RECT  12.492 60.419 12.51 60.456 ;
    END
  END a[63]
  PIN a[64]
    DIRECTION INPUT ;
    USE SIGNAL ;
    PORT
      LAYER M5 ;
        RECT  30.48 60.372 30.504 60.456 ;
    END
  END a[64]
  PIN a[65]
    DIRECTION INPUT ;
    USE SIGNAL ;
    PORT
      LAYER M5 ;
        RECT  30.576 60.372 30.6 60.456 ;
    END
  END a[65]
  PIN a[66]
    DIRECTION INPUT ;
    USE SIGNAL ;
    PORT
      LAYER M5 ;
        RECT  30.672 60.372 30.696 60.456 ;
    END
  END a[66]
  PIN a[67]
    DIRECTION INPUT ;
    USE SIGNAL ;
    PORT
      LAYER M5 ;
        RECT  30.768 60.372 30.792 60.456 ;
    END
  END a[67]
  PIN a[68]
    DIRECTION INPUT ;
    USE SIGNAL ;
    PORT
      LAYER M5 ;
        RECT  30.864 60.372 30.888 60.456 ;
    END
  END a[68]
  PIN a[69]
    DIRECTION INPUT ;
    USE SIGNAL ;
    PORT
      LAYER M5 ;
        RECT  30.96 60.372 30.984 60.456 ;
    END
  END a[69]
  PIN a[6]
    DIRECTION INPUT ;
    USE SIGNAL ;
    PORT
      LAYER M3 ;
        RECT  39.492 60.419 39.51 60.456 ;
    END
  END a[6]
  PIN a[70]
    DIRECTION INPUT ;
    USE SIGNAL ;
    PORT
      LAYER M5 ;
        RECT  31.056 60.372 31.08 60.456 ;
    END
  END a[70]
  PIN a[71]
    DIRECTION INPUT ;
    USE SIGNAL ;
    PORT
      LAYER M5 ;
        RECT  31.152 60.372 31.176 60.456 ;
    END
  END a[71]
  PIN a[72]
    DIRECTION INPUT ;
    USE SIGNAL ;
    PORT
      LAYER M5 ;
        RECT  31.248 60.372 31.272 60.456 ;
    END
  END a[72]
  PIN a[73]
    DIRECTION INPUT ;
    USE SIGNAL ;
    PORT
      LAYER M5 ;
        RECT  31.344 60.372 31.368 60.456 ;
    END
  END a[73]
  PIN a[74]
    DIRECTION INPUT ;
    USE SIGNAL ;
    PORT
      LAYER M5 ;
        RECT  31.44 60.372 31.464 60.456 ;
    END
  END a[74]
  PIN a[75]
    DIRECTION INPUT ;
    USE SIGNAL ;
    PORT
      LAYER M5 ;
        RECT  31.536 60.372 31.56 60.456 ;
    END
  END a[75]
  PIN a[76]
    DIRECTION INPUT ;
    USE SIGNAL ;
    PORT
      LAYER M5 ;
        RECT  31.632 60.372 31.656 60.456 ;
    END
  END a[76]
  PIN a[77]
    DIRECTION INPUT ;
    USE SIGNAL ;
    PORT
      LAYER M5 ;
        RECT  31.728 60.372 31.752 60.456 ;
    END
  END a[77]
  PIN a[78]
    DIRECTION INPUT ;
    USE SIGNAL ;
    PORT
      LAYER M5 ;
        RECT  31.824 60.372 31.848 60.456 ;
    END
  END a[78]
  PIN a[79]
    DIRECTION INPUT ;
    USE SIGNAL ;
    PORT
      LAYER M5 ;
        RECT  31.92 60.372 31.944 60.456 ;
    END
  END a[79]
  PIN a[7]
    DIRECTION INPUT ;
    USE SIGNAL ;
    PORT
      LAYER M3 ;
        RECT  39.564 60.419 39.582 60.456 ;
    END
  END a[7]
  PIN a[80]
    DIRECTION INPUT ;
    USE SIGNAL ;
    PORT
      LAYER M5 ;
        RECT  32.016 60.372 32.04 60.456 ;
    END
  END a[80]
  PIN a[81]
    DIRECTION INPUT ;
    USE SIGNAL ;
    PORT
      LAYER M5 ;
        RECT  32.112 60.372 32.136 60.456 ;
    END
  END a[81]
  PIN a[82]
    DIRECTION INPUT ;
    USE SIGNAL ;
    PORT
      LAYER M5 ;
        RECT  32.208 60.372 32.232 60.456 ;
    END
  END a[82]
  PIN a[83]
    DIRECTION INPUT ;
    USE SIGNAL ;
    PORT
      LAYER M5 ;
        RECT  32.304 60.372 32.328 60.456 ;
    END
  END a[83]
  PIN a[84]
    DIRECTION INPUT ;
    USE SIGNAL ;
    PORT
      LAYER M5 ;
        RECT  32.4 60.372 32.424 60.456 ;
    END
  END a[84]
  PIN a[85]
    DIRECTION INPUT ;
    USE SIGNAL ;
    PORT
      LAYER M5 ;
        RECT  32.496 60.372 32.52 60.456 ;
    END
  END a[85]
  PIN a[86]
    DIRECTION INPUT ;
    USE SIGNAL ;
    PORT
      LAYER M5 ;
        RECT  32.592 60.372 32.616 60.456 ;
    END
  END a[86]
  PIN a[87]
    DIRECTION INPUT ;
    USE SIGNAL ;
    PORT
      LAYER M5 ;
        RECT  32.688 60.372 32.712 60.456 ;
    END
  END a[87]
  PIN a[88]
    DIRECTION INPUT ;
    USE SIGNAL ;
    PORT
      LAYER M5 ;
        RECT  32.784 60.372 32.808 60.456 ;
    END
  END a[88]
  PIN a[89]
    DIRECTION INPUT ;
    USE SIGNAL ;
    PORT
      LAYER M5 ;
        RECT  32.88 60.372 32.904 60.456 ;
    END
  END a[89]
  PIN a[8]
    DIRECTION INPUT ;
    USE SIGNAL ;
    PORT
      LAYER M3 ;
        RECT  39.636 60.419 39.654 60.456 ;
    END
  END a[8]
  PIN a[90]
    DIRECTION INPUT ;
    USE SIGNAL ;
    PORT
      LAYER M5 ;
        RECT  32.976 60.372 33 60.456 ;
    END
  END a[90]
  PIN a[91]
    DIRECTION INPUT ;
    USE SIGNAL ;
    PORT
      LAYER M5 ;
        RECT  33.072 60.372 33.096 60.456 ;
    END
  END a[91]
  PIN a[92]
    DIRECTION INPUT ;
    USE SIGNAL ;
    PORT
      LAYER M5 ;
        RECT  33.168 60.372 33.192 60.456 ;
    END
  END a[92]
  PIN a[93]
    DIRECTION INPUT ;
    USE SIGNAL ;
    PORT
      LAYER M5 ;
        RECT  33.264 60.372 33.288 60.456 ;
    END
  END a[93]
  PIN a[94]
    DIRECTION INPUT ;
    USE SIGNAL ;
    PORT
      LAYER M5 ;
        RECT  33.36 60.372 33.384 60.456 ;
    END
  END a[94]
  PIN a[95]
    DIRECTION INPUT ;
    USE SIGNAL ;
    PORT
      LAYER M5 ;
        RECT  33.456 60.372 33.48 60.456 ;
    END
  END a[95]
  PIN a[96]
    DIRECTION INPUT ;
    USE SIGNAL ;
    PORT
      LAYER M3 ;
        RECT  48.852 60.419 48.87 60.456 ;
    END
  END a[96]
  PIN a[97]
    DIRECTION INPUT ;
    USE SIGNAL ;
    PORT
      LAYER M3 ;
        RECT  48.924 60.419 48.942 60.456 ;
    END
  END a[97]
  PIN a[98]
    DIRECTION INPUT ;
    USE SIGNAL ;
    PORT
      LAYER M3 ;
        RECT  48.996 60.419 49.014 60.456 ;
    END
  END a[98]
  PIN a[99]
    DIRECTION INPUT ;
    USE SIGNAL ;
    PORT
      LAYER M3 ;
        RECT  49.068 60.419 49.086 60.456 ;
    END
  END a[99]
  PIN a[9]
    DIRECTION INPUT ;
    USE SIGNAL ;
    PORT
      LAYER M3 ;
        RECT  39.708 60.419 39.726 60.456 ;
    END
  END a[9]
  PIN b[0]
    DIRECTION OUTPUT ;
    USE SIGNAL ;
    PORT
      LAYER M5 ;
        RECT  45.264 0 45.288 0.084 ;
    END
  END b[0]
  PIN b[100]
    DIRECTION OUTPUT ;
    USE SIGNAL ;
    PORT
      LAYER M3 ;
        RECT  53.244 0 53.262 0.037 ;
    END
  END b[100]
  PIN b[101]
    DIRECTION OUTPUT ;
    USE SIGNAL ;
    PORT
      LAYER M3 ;
        RECT  53.316 0 53.334 0.037 ;
    END
  END b[101]
  PIN b[102]
    DIRECTION OUTPUT ;
    USE SIGNAL ;
    PORT
      LAYER M3 ;
        RECT  53.388 0 53.406 0.037 ;
    END
  END b[102]
  PIN b[103]
    DIRECTION OUTPUT ;
    USE SIGNAL ;
    PORT
      LAYER M3 ;
        RECT  53.46 0 53.478 0.037 ;
    END
  END b[103]
  PIN b[104]
    DIRECTION OUTPUT ;
    USE SIGNAL ;
    PORT
      LAYER M3 ;
        RECT  53.532 0 53.55 0.037 ;
    END
  END b[104]
  PIN b[105]
    DIRECTION OUTPUT ;
    USE SIGNAL ;
    PORT
      LAYER M3 ;
        RECT  53.604 0 53.622 0.037 ;
    END
  END b[105]
  PIN b[106]
    DIRECTION OUTPUT ;
    USE SIGNAL ;
    PORT
      LAYER M3 ;
        RECT  53.676 0 53.694 0.037 ;
    END
  END b[106]
  PIN b[107]
    DIRECTION OUTPUT ;
    USE SIGNAL ;
    PORT
      LAYER M3 ;
        RECT  53.748 0 53.766 0.037 ;
    END
  END b[107]
  PIN b[108]
    DIRECTION OUTPUT ;
    USE SIGNAL ;
    PORT
      LAYER M3 ;
        RECT  53.82 0 53.838 0.037 ;
    END
  END b[108]
  PIN b[109]
    DIRECTION OUTPUT ;
    USE SIGNAL ;
    PORT
      LAYER M3 ;
        RECT  53.892 0 53.91 0.037 ;
    END
  END b[109]
  PIN b[10]
    DIRECTION OUTPUT ;
    USE SIGNAL ;
    PORT
      LAYER M5 ;
        RECT  46.224 0 46.248 0.084 ;
    END
  END b[10]
  PIN b[110]
    DIRECTION OUTPUT ;
    USE SIGNAL ;
    PORT
      LAYER M3 ;
        RECT  53.964 0 53.982 0.037 ;
    END
  END b[110]
  PIN b[111]
    DIRECTION OUTPUT ;
    USE SIGNAL ;
    PORT
      LAYER M3 ;
        RECT  54.036 0 54.054 0.037 ;
    END
  END b[111]
  PIN b[112]
    DIRECTION OUTPUT ;
    USE SIGNAL ;
    PORT
      LAYER M3 ;
        RECT  54.108 0 54.126 0.037 ;
    END
  END b[112]
  PIN b[113]
    DIRECTION OUTPUT ;
    USE SIGNAL ;
    PORT
      LAYER M3 ;
        RECT  54.18 0 54.198 0.037 ;
    END
  END b[113]
  PIN b[114]
    DIRECTION OUTPUT ;
    USE SIGNAL ;
    PORT
      LAYER M3 ;
        RECT  54.252 0 54.27 0.037 ;
    END
  END b[114]
  PIN b[115]
    DIRECTION OUTPUT ;
    USE SIGNAL ;
    PORT
      LAYER M3 ;
        RECT  54.324 0 54.342 0.037 ;
    END
  END b[115]
  PIN b[116]
    DIRECTION OUTPUT ;
    USE SIGNAL ;
    PORT
      LAYER M3 ;
        RECT  54.396 0 54.414 0.037 ;
    END
  END b[116]
  PIN b[117]
    DIRECTION OUTPUT ;
    USE SIGNAL ;
    PORT
      LAYER M3 ;
        RECT  54.468 0 54.486 0.037 ;
    END
  END b[117]
  PIN b[118]
    DIRECTION OUTPUT ;
    USE SIGNAL ;
    PORT
      LAYER M3 ;
        RECT  54.54 0 54.558 0.037 ;
    END
  END b[118]
  PIN b[119]
    DIRECTION OUTPUT ;
    USE SIGNAL ;
    PORT
      LAYER M3 ;
        RECT  54.612 0 54.63 0.037 ;
    END
  END b[119]
  PIN b[11]
    DIRECTION OUTPUT ;
    USE SIGNAL ;
    PORT
      LAYER M5 ;
        RECT  46.32 0 46.344 0.084 ;
    END
  END b[11]
  PIN b[120]
    DIRECTION OUTPUT ;
    USE SIGNAL ;
    PORT
      LAYER M3 ;
        RECT  54.684 0 54.702 0.037 ;
    END
  END b[120]
  PIN b[121]
    DIRECTION OUTPUT ;
    USE SIGNAL ;
    PORT
      LAYER M3 ;
        RECT  54.756 0 54.774 0.037 ;
    END
  END b[121]
  PIN b[122]
    DIRECTION OUTPUT ;
    USE SIGNAL ;
    PORT
      LAYER M3 ;
        RECT  54.828 0 54.846 0.037 ;
    END
  END b[122]
  PIN b[123]
    DIRECTION OUTPUT ;
    USE SIGNAL ;
    PORT
      LAYER M3 ;
        RECT  54.9 0 54.918 0.037 ;
    END
  END b[123]
  PIN b[124]
    DIRECTION OUTPUT ;
    USE SIGNAL ;
    PORT
      LAYER M3 ;
        RECT  54.972 0 54.99 0.037 ;
    END
  END b[124]
  PIN b[125]
    DIRECTION OUTPUT ;
    USE SIGNAL ;
    PORT
      LAYER M3 ;
        RECT  55.044 0 55.062 0.037 ;
    END
  END b[125]
  PIN b[126]
    DIRECTION OUTPUT ;
    USE SIGNAL ;
    PORT
      LAYER M3 ;
        RECT  55.116 0 55.134 0.037 ;
    END
  END b[126]
  PIN b[127]
    DIRECTION OUTPUT ;
    USE SIGNAL ;
    PORT
      LAYER M3 ;
        RECT  55.188 0 55.206 0.037 ;
    END
  END b[127]
  PIN b[128]
    DIRECTION OUTPUT ;
    USE SIGNAL ;
    PORT
      LAYER M5 ;
        RECT  70.608 0 70.632 0.084 ;
    END
  END b[128]
  PIN b[129]
    DIRECTION OUTPUT ;
    USE SIGNAL ;
    PORT
      LAYER M5 ;
        RECT  70.704 0 70.728 0.084 ;
    END
  END b[129]
  PIN b[12]
    DIRECTION OUTPUT ;
    USE SIGNAL ;
    PORT
      LAYER M5 ;
        RECT  46.416 0 46.44 0.084 ;
    END
  END b[12]
  PIN b[130]
    DIRECTION OUTPUT ;
    USE SIGNAL ;
    PORT
      LAYER M5 ;
        RECT  70.8 0 70.824 0.084 ;
    END
  END b[130]
  PIN b[131]
    DIRECTION OUTPUT ;
    USE SIGNAL ;
    PORT
      LAYER M5 ;
        RECT  70.896 0 70.92 0.084 ;
    END
  END b[131]
  PIN b[132]
    DIRECTION OUTPUT ;
    USE SIGNAL ;
    PORT
      LAYER M5 ;
        RECT  70.992 0 71.016 0.084 ;
    END
  END b[132]
  PIN b[133]
    DIRECTION OUTPUT ;
    USE SIGNAL ;
    PORT
      LAYER M5 ;
        RECT  71.088 0 71.112 0.084 ;
    END
  END b[133]
  PIN b[134]
    DIRECTION OUTPUT ;
    USE SIGNAL ;
    PORT
      LAYER M5 ;
        RECT  71.184 0 71.208 0.084 ;
    END
  END b[134]
  PIN b[135]
    DIRECTION OUTPUT ;
    USE SIGNAL ;
    PORT
      LAYER M5 ;
        RECT  71.28 0 71.304 0.084 ;
    END
  END b[135]
  PIN b[136]
    DIRECTION OUTPUT ;
    USE SIGNAL ;
    PORT
      LAYER M5 ;
        RECT  71.376 0 71.4 0.084 ;
    END
  END b[136]
  PIN b[137]
    DIRECTION OUTPUT ;
    USE SIGNAL ;
    PORT
      LAYER M5 ;
        RECT  71.472 0 71.496 0.084 ;
    END
  END b[137]
  PIN b[138]
    DIRECTION OUTPUT ;
    USE SIGNAL ;
    PORT
      LAYER M5 ;
        RECT  71.568 0 71.592 0.084 ;
    END
  END b[138]
  PIN b[139]
    DIRECTION OUTPUT ;
    USE SIGNAL ;
    PORT
      LAYER M5 ;
        RECT  71.664 0 71.688 0.084 ;
    END
  END b[139]
  PIN b[13]
    DIRECTION OUTPUT ;
    USE SIGNAL ;
    PORT
      LAYER M5 ;
        RECT  46.512 0 46.536 0.084 ;
    END
  END b[13]
  PIN b[140]
    DIRECTION OUTPUT ;
    USE SIGNAL ;
    PORT
      LAYER M5 ;
        RECT  71.76 0 71.784 0.084 ;
    END
  END b[140]
  PIN b[141]
    DIRECTION OUTPUT ;
    USE SIGNAL ;
    PORT
      LAYER M5 ;
        RECT  71.856 0 71.88 0.084 ;
    END
  END b[141]
  PIN b[142]
    DIRECTION OUTPUT ;
    USE SIGNAL ;
    PORT
      LAYER M5 ;
        RECT  71.952 0 71.976 0.084 ;
    END
  END b[142]
  PIN b[143]
    DIRECTION OUTPUT ;
    USE SIGNAL ;
    PORT
      LAYER M5 ;
        RECT  72.048 0 72.072 0.084 ;
    END
  END b[143]
  PIN b[144]
    DIRECTION OUTPUT ;
    USE SIGNAL ;
    PORT
      LAYER M5 ;
        RECT  72.144 0 72.168 0.084 ;
    END
  END b[144]
  PIN b[145]
    DIRECTION OUTPUT ;
    USE SIGNAL ;
    PORT
      LAYER M5 ;
        RECT  72.24 0 72.264 0.084 ;
    END
  END b[145]
  PIN b[146]
    DIRECTION OUTPUT ;
    USE SIGNAL ;
    PORT
      LAYER M5 ;
        RECT  72.336 0 72.36 0.084 ;
    END
  END b[146]
  PIN b[147]
    DIRECTION OUTPUT ;
    USE SIGNAL ;
    PORT
      LAYER M5 ;
        RECT  72.432 0 72.456 0.084 ;
    END
  END b[147]
  PIN b[148]
    DIRECTION OUTPUT ;
    USE SIGNAL ;
    PORT
      LAYER M5 ;
        RECT  72.528 0 72.552 0.084 ;
    END
  END b[148]
  PIN b[149]
    DIRECTION OUTPUT ;
    USE SIGNAL ;
    PORT
      LAYER M5 ;
        RECT  72.624 0 72.648 0.084 ;
    END
  END b[149]
  PIN b[14]
    DIRECTION OUTPUT ;
    USE SIGNAL ;
    PORT
      LAYER M5 ;
        RECT  46.608 0 46.632 0.084 ;
    END
  END b[14]
  PIN b[150]
    DIRECTION OUTPUT ;
    USE SIGNAL ;
    PORT
      LAYER M5 ;
        RECT  72.72 0 72.744 0.084 ;
    END
  END b[150]
  PIN b[151]
    DIRECTION OUTPUT ;
    USE SIGNAL ;
    PORT
      LAYER M5 ;
        RECT  72.816 0 72.84 0.084 ;
    END
  END b[151]
  PIN b[152]
    DIRECTION OUTPUT ;
    USE SIGNAL ;
    PORT
      LAYER M5 ;
        RECT  72.912 0 72.936 0.084 ;
    END
  END b[152]
  PIN b[153]
    DIRECTION OUTPUT ;
    USE SIGNAL ;
    PORT
      LAYER M5 ;
        RECT  73.008 0 73.032 0.084 ;
    END
  END b[153]
  PIN b[154]
    DIRECTION OUTPUT ;
    USE SIGNAL ;
    PORT
      LAYER M5 ;
        RECT  73.104 0 73.128 0.084 ;
    END
  END b[154]
  PIN b[155]
    DIRECTION OUTPUT ;
    USE SIGNAL ;
    PORT
      LAYER M5 ;
        RECT  73.2 0 73.224 0.084 ;
    END
  END b[155]
  PIN b[156]
    DIRECTION OUTPUT ;
    USE SIGNAL ;
    PORT
      LAYER M5 ;
        RECT  73.296 0 73.32 0.084 ;
    END
  END b[156]
  PIN b[157]
    DIRECTION OUTPUT ;
    USE SIGNAL ;
    PORT
      LAYER M5 ;
        RECT  73.392 0 73.416 0.084 ;
    END
  END b[157]
  PIN b[158]
    DIRECTION OUTPUT ;
    USE SIGNAL ;
    PORT
      LAYER M5 ;
        RECT  73.488 0 73.512 0.084 ;
    END
  END b[158]
  PIN b[159]
    DIRECTION OUTPUT ;
    USE SIGNAL ;
    PORT
      LAYER M5 ;
        RECT  73.584 0 73.608 0.084 ;
    END
  END b[159]
  PIN b[15]
    DIRECTION OUTPUT ;
    USE SIGNAL ;
    PORT
      LAYER M5 ;
        RECT  46.704 0 46.728 0.084 ;
    END
  END b[15]
  PIN b[160]
    DIRECTION OUTPUT ;
    USE SIGNAL ;
    PORT
      LAYER M3 ;
        RECT  84.06 0 84.078 0.037 ;
    END
  END b[160]
  PIN b[161]
    DIRECTION OUTPUT ;
    USE SIGNAL ;
    PORT
      LAYER M3 ;
        RECT  84.132 0 84.15 0.037 ;
    END
  END b[161]
  PIN b[162]
    DIRECTION OUTPUT ;
    USE SIGNAL ;
    PORT
      LAYER M3 ;
        RECT  84.204 0 84.222 0.037 ;
    END
  END b[162]
  PIN b[163]
    DIRECTION OUTPUT ;
    USE SIGNAL ;
    PORT
      LAYER M3 ;
        RECT  84.276 0 84.294 0.037 ;
    END
  END b[163]
  PIN b[164]
    DIRECTION OUTPUT ;
    USE SIGNAL ;
    PORT
      LAYER M3 ;
        RECT  84.348 0 84.366 0.037 ;
    END
  END b[164]
  PIN b[165]
    DIRECTION OUTPUT ;
    USE SIGNAL ;
    PORT
      LAYER M3 ;
        RECT  84.42 0 84.438 0.037 ;
    END
  END b[165]
  PIN b[166]
    DIRECTION OUTPUT ;
    USE SIGNAL ;
    PORT
      LAYER M3 ;
        RECT  84.492 0 84.51 0.037 ;
    END
  END b[166]
  PIN b[167]
    DIRECTION OUTPUT ;
    USE SIGNAL ;
    PORT
      LAYER M3 ;
        RECT  84.564 0 84.582 0.037 ;
    END
  END b[167]
  PIN b[168]
    DIRECTION OUTPUT ;
    USE SIGNAL ;
    PORT
      LAYER M3 ;
        RECT  84.636 0 84.654 0.037 ;
    END
  END b[168]
  PIN b[169]
    DIRECTION OUTPUT ;
    USE SIGNAL ;
    PORT
      LAYER M3 ;
        RECT  84.708 0 84.726 0.037 ;
    END
  END b[169]
  PIN b[16]
    DIRECTION OUTPUT ;
    USE SIGNAL ;
    PORT
      LAYER M5 ;
        RECT  46.8 0 46.824 0.084 ;
    END
  END b[16]
  PIN b[170]
    DIRECTION OUTPUT ;
    USE SIGNAL ;
    PORT
      LAYER M3 ;
        RECT  84.78 0 84.798 0.037 ;
    END
  END b[170]
  PIN b[171]
    DIRECTION OUTPUT ;
    USE SIGNAL ;
    PORT
      LAYER M3 ;
        RECT  84.852 0 84.87 0.037 ;
    END
  END b[171]
  PIN b[172]
    DIRECTION OUTPUT ;
    USE SIGNAL ;
    PORT
      LAYER M3 ;
        RECT  84.924 0 84.942 0.037 ;
    END
  END b[172]
  PIN b[173]
    DIRECTION OUTPUT ;
    USE SIGNAL ;
    PORT
      LAYER M3 ;
        RECT  84.996 0 85.014 0.037 ;
    END
  END b[173]
  PIN b[174]
    DIRECTION OUTPUT ;
    USE SIGNAL ;
    PORT
      LAYER M3 ;
        RECT  85.068 0 85.086 0.037 ;
    END
  END b[174]
  PIN b[175]
    DIRECTION OUTPUT ;
    USE SIGNAL ;
    PORT
      LAYER M3 ;
        RECT  85.14 0 85.158 0.037 ;
    END
  END b[175]
  PIN b[176]
    DIRECTION OUTPUT ;
    USE SIGNAL ;
    PORT
      LAYER M3 ;
        RECT  85.212 0 85.23 0.037 ;
    END
  END b[176]
  PIN b[177]
    DIRECTION OUTPUT ;
    USE SIGNAL ;
    PORT
      LAYER M3 ;
        RECT  85.284 0 85.302 0.037 ;
    END
  END b[177]
  PIN b[178]
    DIRECTION OUTPUT ;
    USE SIGNAL ;
    PORT
      LAYER M3 ;
        RECT  85.356 0 85.374 0.037 ;
    END
  END b[178]
  PIN b[179]
    DIRECTION OUTPUT ;
    USE SIGNAL ;
    PORT
      LAYER M3 ;
        RECT  85.428 0 85.446 0.037 ;
    END
  END b[179]
  PIN b[17]
    DIRECTION OUTPUT ;
    USE SIGNAL ;
    PORT
      LAYER M5 ;
        RECT  46.896 0 46.92 0.084 ;
    END
  END b[17]
  PIN b[180]
    DIRECTION OUTPUT ;
    USE SIGNAL ;
    PORT
      LAYER M3 ;
        RECT  85.5 0 85.518 0.037 ;
    END
  END b[180]
  PIN b[181]
    DIRECTION OUTPUT ;
    USE SIGNAL ;
    PORT
      LAYER M3 ;
        RECT  85.572 0 85.59 0.037 ;
    END
  END b[181]
  PIN b[182]
    DIRECTION OUTPUT ;
    USE SIGNAL ;
    PORT
      LAYER M3 ;
        RECT  85.644 0 85.662 0.037 ;
    END
  END b[182]
  PIN b[183]
    DIRECTION OUTPUT ;
    USE SIGNAL ;
    PORT
      LAYER M3 ;
        RECT  85.716 0 85.734 0.037 ;
    END
  END b[183]
  PIN b[184]
    DIRECTION OUTPUT ;
    USE SIGNAL ;
    PORT
      LAYER M3 ;
        RECT  85.788 0 85.806 0.037 ;
    END
  END b[184]
  PIN b[185]
    DIRECTION OUTPUT ;
    USE SIGNAL ;
    PORT
      LAYER M3 ;
        RECT  85.86 0 85.878 0.037 ;
    END
  END b[185]
  PIN b[186]
    DIRECTION OUTPUT ;
    USE SIGNAL ;
    PORT
      LAYER M3 ;
        RECT  85.932 0 85.95 0.037 ;
    END
  END b[186]
  PIN b[187]
    DIRECTION OUTPUT ;
    USE SIGNAL ;
    PORT
      LAYER M3 ;
        RECT  86.004 0 86.022 0.037 ;
    END
  END b[187]
  PIN b[188]
    DIRECTION OUTPUT ;
    USE SIGNAL ;
    PORT
      LAYER M3 ;
        RECT  86.076 0 86.094 0.037 ;
    END
  END b[188]
  PIN b[189]
    DIRECTION OUTPUT ;
    USE SIGNAL ;
    PORT
      LAYER M3 ;
        RECT  86.148 0 86.166 0.037 ;
    END
  END b[189]
  PIN b[18]
    DIRECTION OUTPUT ;
    USE SIGNAL ;
    PORT
      LAYER M5 ;
        RECT  46.992 0 47.016 0.084 ;
    END
  END b[18]
  PIN b[190]
    DIRECTION OUTPUT ;
    USE SIGNAL ;
    PORT
      LAYER M3 ;
        RECT  86.22 0 86.238 0.037 ;
    END
  END b[190]
  PIN b[191]
    DIRECTION OUTPUT ;
    USE SIGNAL ;
    PORT
      LAYER M3 ;
        RECT  86.292 0 86.31 0.037 ;
    END
  END b[191]
  PIN b[192]
    DIRECTION OUTPUT ;
    USE SIGNAL ;
    PORT
      LAYER M5 ;
        RECT  73.68 0 73.704 0.084 ;
    END
  END b[192]
  PIN b[193]
    DIRECTION OUTPUT ;
    USE SIGNAL ;
    PORT
      LAYER M5 ;
        RECT  73.776 0 73.8 0.084 ;
    END
  END b[193]
  PIN b[194]
    DIRECTION OUTPUT ;
    USE SIGNAL ;
    PORT
      LAYER M5 ;
        RECT  73.872 0 73.896 0.084 ;
    END
  END b[194]
  PIN b[195]
    DIRECTION OUTPUT ;
    USE SIGNAL ;
    PORT
      LAYER M5 ;
        RECT  73.968 0 73.992 0.084 ;
    END
  END b[195]
  PIN b[196]
    DIRECTION OUTPUT ;
    USE SIGNAL ;
    PORT
      LAYER M5 ;
        RECT  74.064 0 74.088 0.084 ;
    END
  END b[196]
  PIN b[197]
    DIRECTION OUTPUT ;
    USE SIGNAL ;
    PORT
      LAYER M5 ;
        RECT  74.16 0 74.184 0.084 ;
    END
  END b[197]
  PIN b[198]
    DIRECTION OUTPUT ;
    USE SIGNAL ;
    PORT
      LAYER M5 ;
        RECT  74.256 0 74.28 0.084 ;
    END
  END b[198]
  PIN b[199]
    DIRECTION OUTPUT ;
    USE SIGNAL ;
    PORT
      LAYER M5 ;
        RECT  74.352 0 74.376 0.084 ;
    END
  END b[199]
  PIN b[19]
    DIRECTION OUTPUT ;
    USE SIGNAL ;
    PORT
      LAYER M5 ;
        RECT  47.088 0 47.112 0.084 ;
    END
  END b[19]
  PIN b[1]
    DIRECTION OUTPUT ;
    USE SIGNAL ;
    PORT
      LAYER M5 ;
        RECT  45.36 0 45.384 0.084 ;
    END
  END b[1]
  PIN b[200]
    DIRECTION OUTPUT ;
    USE SIGNAL ;
    PORT
      LAYER M5 ;
        RECT  74.448 0 74.472 0.084 ;
    END
  END b[200]
  PIN b[201]
    DIRECTION OUTPUT ;
    USE SIGNAL ;
    PORT
      LAYER M5 ;
        RECT  74.544 0 74.568 0.084 ;
    END
  END b[201]
  PIN b[202]
    DIRECTION OUTPUT ;
    USE SIGNAL ;
    PORT
      LAYER M5 ;
        RECT  74.64 0 74.664 0.084 ;
    END
  END b[202]
  PIN b[203]
    DIRECTION OUTPUT ;
    USE SIGNAL ;
    PORT
      LAYER M5 ;
        RECT  74.736 0 74.76 0.084 ;
    END
  END b[203]
  PIN b[204]
    DIRECTION OUTPUT ;
    USE SIGNAL ;
    PORT
      LAYER M5 ;
        RECT  74.832 0 74.856 0.084 ;
    END
  END b[204]
  PIN b[205]
    DIRECTION OUTPUT ;
    USE SIGNAL ;
    PORT
      LAYER M5 ;
        RECT  74.928 0 74.952 0.084 ;
    END
  END b[205]
  PIN b[206]
    DIRECTION OUTPUT ;
    USE SIGNAL ;
    PORT
      LAYER M5 ;
        RECT  75.024 0 75.048 0.084 ;
    END
  END b[206]
  PIN b[207]
    DIRECTION OUTPUT ;
    USE SIGNAL ;
    PORT
      LAYER M5 ;
        RECT  75.12 0 75.144 0.084 ;
    END
  END b[207]
  PIN b[208]
    DIRECTION OUTPUT ;
    USE SIGNAL ;
    PORT
      LAYER M5 ;
        RECT  75.216 0 75.24 0.084 ;
    END
  END b[208]
  PIN b[209]
    DIRECTION OUTPUT ;
    USE SIGNAL ;
    PORT
      LAYER M5 ;
        RECT  75.312 0 75.336 0.084 ;
    END
  END b[209]
  PIN b[20]
    DIRECTION OUTPUT ;
    USE SIGNAL ;
    PORT
      LAYER M5 ;
        RECT  47.184 0 47.208 0.084 ;
    END
  END b[20]
  PIN b[210]
    DIRECTION OUTPUT ;
    USE SIGNAL ;
    PORT
      LAYER M5 ;
        RECT  75.408 0 75.432 0.084 ;
    END
  END b[210]
  PIN b[211]
    DIRECTION OUTPUT ;
    USE SIGNAL ;
    PORT
      LAYER M5 ;
        RECT  75.504 0 75.528 0.084 ;
    END
  END b[211]
  PIN b[212]
    DIRECTION OUTPUT ;
    USE SIGNAL ;
    PORT
      LAYER M5 ;
        RECT  75.6 0 75.624 0.084 ;
    END
  END b[212]
  PIN b[213]
    DIRECTION OUTPUT ;
    USE SIGNAL ;
    PORT
      LAYER M5 ;
        RECT  75.696 0 75.72 0.084 ;
    END
  END b[213]
  PIN b[214]
    DIRECTION OUTPUT ;
    USE SIGNAL ;
    PORT
      LAYER M5 ;
        RECT  75.792 0 75.816 0.084 ;
    END
  END b[214]
  PIN b[215]
    DIRECTION OUTPUT ;
    USE SIGNAL ;
    PORT
      LAYER M5 ;
        RECT  75.888 0 75.912 0.084 ;
    END
  END b[215]
  PIN b[216]
    DIRECTION OUTPUT ;
    USE SIGNAL ;
    PORT
      LAYER M5 ;
        RECT  75.984 0 76.008 0.084 ;
    END
  END b[216]
  PIN b[217]
    DIRECTION OUTPUT ;
    USE SIGNAL ;
    PORT
      LAYER M5 ;
        RECT  76.08 0 76.104 0.084 ;
    END
  END b[217]
  PIN b[218]
    DIRECTION OUTPUT ;
    USE SIGNAL ;
    PORT
      LAYER M5 ;
        RECT  76.176 0 76.2 0.084 ;
    END
  END b[218]
  PIN b[219]
    DIRECTION OUTPUT ;
    USE SIGNAL ;
    PORT
      LAYER M5 ;
        RECT  76.272 0 76.296 0.084 ;
    END
  END b[219]
  PIN b[21]
    DIRECTION OUTPUT ;
    USE SIGNAL ;
    PORT
      LAYER M5 ;
        RECT  47.28 0 47.304 0.084 ;
    END
  END b[21]
  PIN b[220]
    DIRECTION OUTPUT ;
    USE SIGNAL ;
    PORT
      LAYER M5 ;
        RECT  76.368 0 76.392 0.084 ;
    END
  END b[220]
  PIN b[221]
    DIRECTION OUTPUT ;
    USE SIGNAL ;
    PORT
      LAYER M5 ;
        RECT  76.464 0 76.488 0.084 ;
    END
  END b[221]
  PIN b[222]
    DIRECTION OUTPUT ;
    USE SIGNAL ;
    PORT
      LAYER M5 ;
        RECT  76.56 0 76.584 0.084 ;
    END
  END b[222]
  PIN b[223]
    DIRECTION OUTPUT ;
    USE SIGNAL ;
    PORT
      LAYER M5 ;
        RECT  76.656 0 76.68 0.084 ;
    END
  END b[223]
  PIN b[224]
    DIRECTION OUTPUT ;
    USE SIGNAL ;
    PORT
      LAYER M3 ;
        RECT  93.852 0 93.87 0.037 ;
    END
  END b[224]
  PIN b[225]
    DIRECTION OUTPUT ;
    USE SIGNAL ;
    PORT
      LAYER M3 ;
        RECT  93.924 0 93.942 0.037 ;
    END
  END b[225]
  PIN b[226]
    DIRECTION OUTPUT ;
    USE SIGNAL ;
    PORT
      LAYER M3 ;
        RECT  93.996 0 94.014 0.037 ;
    END
  END b[226]
  PIN b[227]
    DIRECTION OUTPUT ;
    USE SIGNAL ;
    PORT
      LAYER M3 ;
        RECT  94.068 0 94.086 0.037 ;
    END
  END b[227]
  PIN b[228]
    DIRECTION OUTPUT ;
    USE SIGNAL ;
    PORT
      LAYER M3 ;
        RECT  94.14 0 94.158 0.037 ;
    END
  END b[228]
  PIN b[229]
    DIRECTION OUTPUT ;
    USE SIGNAL ;
    PORT
      LAYER M3 ;
        RECT  94.212 0 94.23 0.037 ;
    END
  END b[229]
  PIN b[22]
    DIRECTION OUTPUT ;
    USE SIGNAL ;
    PORT
      LAYER M5 ;
        RECT  47.376 0 47.4 0.084 ;
    END
  END b[22]
  PIN b[230]
    DIRECTION OUTPUT ;
    USE SIGNAL ;
    PORT
      LAYER M3 ;
        RECT  94.284 0 94.302 0.037 ;
    END
  END b[230]
  PIN b[231]
    DIRECTION OUTPUT ;
    USE SIGNAL ;
    PORT
      LAYER M3 ;
        RECT  94.356 0 94.374 0.037 ;
    END
  END b[231]
  PIN b[232]
    DIRECTION OUTPUT ;
    USE SIGNAL ;
    PORT
      LAYER M3 ;
        RECT  94.428 0 94.446 0.037 ;
    END
  END b[232]
  PIN b[233]
    DIRECTION OUTPUT ;
    USE SIGNAL ;
    PORT
      LAYER M3 ;
        RECT  94.5 0 94.518 0.037 ;
    END
  END b[233]
  PIN b[234]
    DIRECTION OUTPUT ;
    USE SIGNAL ;
    PORT
      LAYER M3 ;
        RECT  94.572 0 94.59 0.037 ;
    END
  END b[234]
  PIN b[235]
    DIRECTION OUTPUT ;
    USE SIGNAL ;
    PORT
      LAYER M3 ;
        RECT  94.644 0 94.662 0.037 ;
    END
  END b[235]
  PIN b[236]
    DIRECTION OUTPUT ;
    USE SIGNAL ;
    PORT
      LAYER M3 ;
        RECT  94.716 0 94.734 0.037 ;
    END
  END b[236]
  PIN b[237]
    DIRECTION OUTPUT ;
    USE SIGNAL ;
    PORT
      LAYER M3 ;
        RECT  94.788 0 94.806 0.037 ;
    END
  END b[237]
  PIN b[238]
    DIRECTION OUTPUT ;
    USE SIGNAL ;
    PORT
      LAYER M3 ;
        RECT  94.86 0 94.878 0.037 ;
    END
  END b[238]
  PIN b[239]
    DIRECTION OUTPUT ;
    USE SIGNAL ;
    PORT
      LAYER M3 ;
        RECT  94.932 0 94.95 0.037 ;
    END
  END b[239]
  PIN b[23]
    DIRECTION OUTPUT ;
    USE SIGNAL ;
    PORT
      LAYER M5 ;
        RECT  47.472 0 47.496 0.084 ;
    END
  END b[23]
  PIN b[240]
    DIRECTION OUTPUT ;
    USE SIGNAL ;
    PORT
      LAYER M3 ;
        RECT  95.004 0 95.022 0.037 ;
    END
  END b[240]
  PIN b[241]
    DIRECTION OUTPUT ;
    USE SIGNAL ;
    PORT
      LAYER M3 ;
        RECT  95.076 0 95.094 0.037 ;
    END
  END b[241]
  PIN b[242]
    DIRECTION OUTPUT ;
    USE SIGNAL ;
    PORT
      LAYER M3 ;
        RECT  95.148 0 95.166 0.037 ;
    END
  END b[242]
  PIN b[243]
    DIRECTION OUTPUT ;
    USE SIGNAL ;
    PORT
      LAYER M3 ;
        RECT  95.22 0 95.238 0.037 ;
    END
  END b[243]
  PIN b[244]
    DIRECTION OUTPUT ;
    USE SIGNAL ;
    PORT
      LAYER M3 ;
        RECT  95.292 0 95.31 0.037 ;
    END
  END b[244]
  PIN b[245]
    DIRECTION OUTPUT ;
    USE SIGNAL ;
    PORT
      LAYER M3 ;
        RECT  95.364 0 95.382 0.037 ;
    END
  END b[245]
  PIN b[246]
    DIRECTION OUTPUT ;
    USE SIGNAL ;
    PORT
      LAYER M3 ;
        RECT  95.436 0 95.454 0.037 ;
    END
  END b[246]
  PIN b[247]
    DIRECTION OUTPUT ;
    USE SIGNAL ;
    PORT
      LAYER M3 ;
        RECT  95.508 0 95.526 0.037 ;
    END
  END b[247]
  PIN b[248]
    DIRECTION OUTPUT ;
    USE SIGNAL ;
    PORT
      LAYER M3 ;
        RECT  95.58 0 95.598 0.037 ;
    END
  END b[248]
  PIN b[249]
    DIRECTION OUTPUT ;
    USE SIGNAL ;
    PORT
      LAYER M3 ;
        RECT  95.652 0 95.67 0.037 ;
    END
  END b[249]
  PIN b[24]
    DIRECTION OUTPUT ;
    USE SIGNAL ;
    PORT
      LAYER M5 ;
        RECT  47.568 0 47.592 0.084 ;
    END
  END b[24]
  PIN b[250]
    DIRECTION OUTPUT ;
    USE SIGNAL ;
    PORT
      LAYER M3 ;
        RECT  95.724 0 95.742 0.037 ;
    END
  END b[250]
  PIN b[251]
    DIRECTION OUTPUT ;
    USE SIGNAL ;
    PORT
      LAYER M3 ;
        RECT  95.796 0 95.814 0.037 ;
    END
  END b[251]
  PIN b[252]
    DIRECTION OUTPUT ;
    USE SIGNAL ;
    PORT
      LAYER M3 ;
        RECT  95.868 0 95.886 0.037 ;
    END
  END b[252]
  PIN b[253]
    DIRECTION OUTPUT ;
    USE SIGNAL ;
    PORT
      LAYER M3 ;
        RECT  95.94 0 95.958 0.037 ;
    END
  END b[253]
  PIN b[254]
    DIRECTION OUTPUT ;
    USE SIGNAL ;
    PORT
      LAYER M3 ;
        RECT  96.012 0 96.03 0.037 ;
    END
  END b[254]
  PIN b[255]
    DIRECTION OUTPUT ;
    USE SIGNAL ;
    PORT
      LAYER M3 ;
        RECT  96.084 0 96.102 0.037 ;
    END
  END b[255]
  PIN b[256]
    DIRECTION OUTPUT ;
    USE SIGNAL ;
    PORT
      LAYER M5 ;
        RECT  67.536 0 67.56 0.084 ;
    END
  END b[256]
  PIN b[257]
    DIRECTION OUTPUT ;
    USE SIGNAL ;
    PORT
      LAYER M5 ;
        RECT  67.632 0 67.656 0.084 ;
    END
  END b[257]
  PIN b[258]
    DIRECTION OUTPUT ;
    USE SIGNAL ;
    PORT
      LAYER M5 ;
        RECT  67.728 0 67.752 0.084 ;
    END
  END b[258]
  PIN b[259]
    DIRECTION OUTPUT ;
    USE SIGNAL ;
    PORT
      LAYER M5 ;
        RECT  67.824 0 67.848 0.084 ;
    END
  END b[259]
  PIN b[25]
    DIRECTION OUTPUT ;
    USE SIGNAL ;
    PORT
      LAYER M5 ;
        RECT  47.664 0 47.688 0.084 ;
    END
  END b[25]
  PIN b[260]
    DIRECTION OUTPUT ;
    USE SIGNAL ;
    PORT
      LAYER M5 ;
        RECT  67.92 0 67.944 0.084 ;
    END
  END b[260]
  PIN b[261]
    DIRECTION OUTPUT ;
    USE SIGNAL ;
    PORT
      LAYER M5 ;
        RECT  68.016 0 68.04 0.084 ;
    END
  END b[261]
  PIN b[262]
    DIRECTION OUTPUT ;
    USE SIGNAL ;
    PORT
      LAYER M5 ;
        RECT  68.112 0 68.136 0.084 ;
    END
  END b[262]
  PIN b[263]
    DIRECTION OUTPUT ;
    USE SIGNAL ;
    PORT
      LAYER M5 ;
        RECT  68.208 0 68.232 0.084 ;
    END
  END b[263]
  PIN b[264]
    DIRECTION OUTPUT ;
    USE SIGNAL ;
    PORT
      LAYER M5 ;
        RECT  68.304 0 68.328 0.084 ;
    END
  END b[264]
  PIN b[265]
    DIRECTION OUTPUT ;
    USE SIGNAL ;
    PORT
      LAYER M5 ;
        RECT  68.4 0 68.424 0.084 ;
    END
  END b[265]
  PIN b[266]
    DIRECTION OUTPUT ;
    USE SIGNAL ;
    PORT
      LAYER M5 ;
        RECT  68.496 0 68.52 0.084 ;
    END
  END b[266]
  PIN b[267]
    DIRECTION OUTPUT ;
    USE SIGNAL ;
    PORT
      LAYER M5 ;
        RECT  68.592 0 68.616 0.084 ;
    END
  END b[267]
  PIN b[268]
    DIRECTION OUTPUT ;
    USE SIGNAL ;
    PORT
      LAYER M5 ;
        RECT  68.688 0 68.712 0.084 ;
    END
  END b[268]
  PIN b[269]
    DIRECTION OUTPUT ;
    USE SIGNAL ;
    PORT
      LAYER M5 ;
        RECT  68.784 0 68.808 0.084 ;
    END
  END b[269]
  PIN b[26]
    DIRECTION OUTPUT ;
    USE SIGNAL ;
    PORT
      LAYER M5 ;
        RECT  47.76 0 47.784 0.084 ;
    END
  END b[26]
  PIN b[270]
    DIRECTION OUTPUT ;
    USE SIGNAL ;
    PORT
      LAYER M5 ;
        RECT  68.88 0 68.904 0.084 ;
    END
  END b[270]
  PIN b[271]
    DIRECTION OUTPUT ;
    USE SIGNAL ;
    PORT
      LAYER M5 ;
        RECT  68.976 0 69 0.084 ;
    END
  END b[271]
  PIN b[272]
    DIRECTION OUTPUT ;
    USE SIGNAL ;
    PORT
      LAYER M5 ;
        RECT  69.072 0 69.096 0.084 ;
    END
  END b[272]
  PIN b[273]
    DIRECTION OUTPUT ;
    USE SIGNAL ;
    PORT
      LAYER M5 ;
        RECT  69.168 0 69.192 0.084 ;
    END
  END b[273]
  PIN b[274]
    DIRECTION OUTPUT ;
    USE SIGNAL ;
    PORT
      LAYER M5 ;
        RECT  69.264 0 69.288 0.084 ;
    END
  END b[274]
  PIN b[275]
    DIRECTION OUTPUT ;
    USE SIGNAL ;
    PORT
      LAYER M5 ;
        RECT  69.36 0 69.384 0.084 ;
    END
  END b[275]
  PIN b[276]
    DIRECTION OUTPUT ;
    USE SIGNAL ;
    PORT
      LAYER M5 ;
        RECT  69.456 0 69.48 0.084 ;
    END
  END b[276]
  PIN b[277]
    DIRECTION OUTPUT ;
    USE SIGNAL ;
    PORT
      LAYER M5 ;
        RECT  69.552 0 69.576 0.084 ;
    END
  END b[277]
  PIN b[278]
    DIRECTION OUTPUT ;
    USE SIGNAL ;
    PORT
      LAYER M5 ;
        RECT  69.648 0 69.672 0.084 ;
    END
  END b[278]
  PIN b[279]
    DIRECTION OUTPUT ;
    USE SIGNAL ;
    PORT
      LAYER M5 ;
        RECT  69.744 0 69.768 0.084 ;
    END
  END b[279]
  PIN b[27]
    DIRECTION OUTPUT ;
    USE SIGNAL ;
    PORT
      LAYER M5 ;
        RECT  47.856 0 47.88 0.084 ;
    END
  END b[27]
  PIN b[280]
    DIRECTION OUTPUT ;
    USE SIGNAL ;
    PORT
      LAYER M5 ;
        RECT  69.84 0 69.864 0.084 ;
    END
  END b[280]
  PIN b[281]
    DIRECTION OUTPUT ;
    USE SIGNAL ;
    PORT
      LAYER M5 ;
        RECT  69.936 0 69.96 0.084 ;
    END
  END b[281]
  PIN b[282]
    DIRECTION OUTPUT ;
    USE SIGNAL ;
    PORT
      LAYER M5 ;
        RECT  70.032 0 70.056 0.084 ;
    END
  END b[282]
  PIN b[283]
    DIRECTION OUTPUT ;
    USE SIGNAL ;
    PORT
      LAYER M5 ;
        RECT  70.128 0 70.152 0.084 ;
    END
  END b[283]
  PIN b[284]
    DIRECTION OUTPUT ;
    USE SIGNAL ;
    PORT
      LAYER M5 ;
        RECT  70.224 0 70.248 0.084 ;
    END
  END b[284]
  PIN b[285]
    DIRECTION OUTPUT ;
    USE SIGNAL ;
    PORT
      LAYER M5 ;
        RECT  70.32 0 70.344 0.084 ;
    END
  END b[285]
  PIN b[286]
    DIRECTION OUTPUT ;
    USE SIGNAL ;
    PORT
      LAYER M5 ;
        RECT  70.416 0 70.44 0.084 ;
    END
  END b[286]
  PIN b[287]
    DIRECTION OUTPUT ;
    USE SIGNAL ;
    PORT
      LAYER M5 ;
        RECT  70.512 0 70.536 0.084 ;
    END
  END b[287]
  PIN b[288]
    DIRECTION OUTPUT ;
    USE SIGNAL ;
    PORT
      LAYER M3 ;
        RECT  74.844 0 74.862 0.037 ;
    END
  END b[288]
  PIN b[289]
    DIRECTION OUTPUT ;
    USE SIGNAL ;
    PORT
      LAYER M3 ;
        RECT  74.916 0 74.934 0.037 ;
    END
  END b[289]
  PIN b[28]
    DIRECTION OUTPUT ;
    USE SIGNAL ;
    PORT
      LAYER M5 ;
        RECT  47.952 0 47.976 0.084 ;
    END
  END b[28]
  PIN b[290]
    DIRECTION OUTPUT ;
    USE SIGNAL ;
    PORT
      LAYER M3 ;
        RECT  74.988 0 75.006 0.037 ;
    END
  END b[290]
  PIN b[291]
    DIRECTION OUTPUT ;
    USE SIGNAL ;
    PORT
      LAYER M3 ;
        RECT  75.06 0 75.078 0.037 ;
    END
  END b[291]
  PIN b[292]
    DIRECTION OUTPUT ;
    USE SIGNAL ;
    PORT
      LAYER M3 ;
        RECT  75.132 0 75.15 0.037 ;
    END
  END b[292]
  PIN b[293]
    DIRECTION OUTPUT ;
    USE SIGNAL ;
    PORT
      LAYER M3 ;
        RECT  75.204 0 75.222 0.037 ;
    END
  END b[293]
  PIN b[294]
    DIRECTION OUTPUT ;
    USE SIGNAL ;
    PORT
      LAYER M3 ;
        RECT  75.276 0 75.294 0.037 ;
    END
  END b[294]
  PIN b[295]
    DIRECTION OUTPUT ;
    USE SIGNAL ;
    PORT
      LAYER M3 ;
        RECT  75.348 0 75.366 0.037 ;
    END
  END b[295]
  PIN b[296]
    DIRECTION OUTPUT ;
    USE SIGNAL ;
    PORT
      LAYER M3 ;
        RECT  75.42 0 75.438 0.037 ;
    END
  END b[296]
  PIN b[297]
    DIRECTION OUTPUT ;
    USE SIGNAL ;
    PORT
      LAYER M3 ;
        RECT  75.492 0 75.51 0.037 ;
    END
  END b[297]
  PIN b[298]
    DIRECTION OUTPUT ;
    USE SIGNAL ;
    PORT
      LAYER M3 ;
        RECT  75.564 0 75.582 0.037 ;
    END
  END b[298]
  PIN b[299]
    DIRECTION OUTPUT ;
    USE SIGNAL ;
    PORT
      LAYER M3 ;
        RECT  75.636 0 75.654 0.037 ;
    END
  END b[299]
  PIN b[29]
    DIRECTION OUTPUT ;
    USE SIGNAL ;
    PORT
      LAYER M5 ;
        RECT  48.048 0 48.072 0.084 ;
    END
  END b[29]
  PIN b[2]
    DIRECTION OUTPUT ;
    USE SIGNAL ;
    PORT
      LAYER M5 ;
        RECT  45.456 0 45.48 0.084 ;
    END
  END b[2]
  PIN b[300]
    DIRECTION OUTPUT ;
    USE SIGNAL ;
    PORT
      LAYER M3 ;
        RECT  75.708 0 75.726 0.037 ;
    END
  END b[300]
  PIN b[301]
    DIRECTION OUTPUT ;
    USE SIGNAL ;
    PORT
      LAYER M3 ;
        RECT  75.78 0 75.798 0.037 ;
    END
  END b[301]
  PIN b[302]
    DIRECTION OUTPUT ;
    USE SIGNAL ;
    PORT
      LAYER M3 ;
        RECT  75.852 0 75.87 0.037 ;
    END
  END b[302]
  PIN b[303]
    DIRECTION OUTPUT ;
    USE SIGNAL ;
    PORT
      LAYER M3 ;
        RECT  75.924 0 75.942 0.037 ;
    END
  END b[303]
  PIN b[304]
    DIRECTION OUTPUT ;
    USE SIGNAL ;
    PORT
      LAYER M3 ;
        RECT  75.996 0 76.014 0.037 ;
    END
  END b[304]
  PIN b[305]
    DIRECTION OUTPUT ;
    USE SIGNAL ;
    PORT
      LAYER M3 ;
        RECT  76.068 0 76.086 0.037 ;
    END
  END b[305]
  PIN b[306]
    DIRECTION OUTPUT ;
    USE SIGNAL ;
    PORT
      LAYER M3 ;
        RECT  76.14 0 76.158 0.037 ;
    END
  END b[306]
  PIN b[307]
    DIRECTION OUTPUT ;
    USE SIGNAL ;
    PORT
      LAYER M3 ;
        RECT  76.212 0 76.23 0.037 ;
    END
  END b[307]
  PIN b[308]
    DIRECTION OUTPUT ;
    USE SIGNAL ;
    PORT
      LAYER M3 ;
        RECT  76.284 0 76.302 0.037 ;
    END
  END b[308]
  PIN b[309]
    DIRECTION OUTPUT ;
    USE SIGNAL ;
    PORT
      LAYER M3 ;
        RECT  76.356 0 76.374 0.037 ;
    END
  END b[309]
  PIN b[30]
    DIRECTION OUTPUT ;
    USE SIGNAL ;
    PORT
      LAYER M5 ;
        RECT  48.144 0 48.168 0.084 ;
    END
  END b[30]
  PIN b[310]
    DIRECTION OUTPUT ;
    USE SIGNAL ;
    PORT
      LAYER M3 ;
        RECT  76.428 0 76.446 0.037 ;
    END
  END b[310]
  PIN b[311]
    DIRECTION OUTPUT ;
    USE SIGNAL ;
    PORT
      LAYER M3 ;
        RECT  76.5 0 76.518 0.037 ;
    END
  END b[311]
  PIN b[312]
    DIRECTION OUTPUT ;
    USE SIGNAL ;
    PORT
      LAYER M3 ;
        RECT  76.572 0 76.59 0.037 ;
    END
  END b[312]
  PIN b[313]
    DIRECTION OUTPUT ;
    USE SIGNAL ;
    PORT
      LAYER M3 ;
        RECT  76.644 0 76.662 0.037 ;
    END
  END b[313]
  PIN b[314]
    DIRECTION OUTPUT ;
    USE SIGNAL ;
    PORT
      LAYER M3 ;
        RECT  76.716 0 76.734 0.037 ;
    END
  END b[314]
  PIN b[315]
    DIRECTION OUTPUT ;
    USE SIGNAL ;
    PORT
      LAYER M3 ;
        RECT  76.788 0 76.806 0.037 ;
    END
  END b[315]
  PIN b[316]
    DIRECTION OUTPUT ;
    USE SIGNAL ;
    PORT
      LAYER M3 ;
        RECT  76.86 0 76.878 0.037 ;
    END
  END b[316]
  PIN b[317]
    DIRECTION OUTPUT ;
    USE SIGNAL ;
    PORT
      LAYER M3 ;
        RECT  76.932 0 76.95 0.037 ;
    END
  END b[317]
  PIN b[318]
    DIRECTION OUTPUT ;
    USE SIGNAL ;
    PORT
      LAYER M3 ;
        RECT  77.004 0 77.022 0.037 ;
    END
  END b[318]
  PIN b[319]
    DIRECTION OUTPUT ;
    USE SIGNAL ;
    PORT
      LAYER M3 ;
        RECT  77.076 0 77.094 0.037 ;
    END
  END b[319]
  PIN b[31]
    DIRECTION OUTPUT ;
    USE SIGNAL ;
    PORT
      LAYER M5 ;
        RECT  48.24 0 48.264 0.084 ;
    END
  END b[31]
  PIN b[320]
    DIRECTION OUTPUT ;
    USE SIGNAL ;
    PORT
      LAYER M3 ;
        RECT  81.756 0 81.774 0.037 ;
    END
  END b[320]
  PIN b[321]
    DIRECTION OUTPUT ;
    USE SIGNAL ;
    PORT
      LAYER M3 ;
        RECT  81.828 0 81.846 0.037 ;
    END
  END b[321]
  PIN b[322]
    DIRECTION OUTPUT ;
    USE SIGNAL ;
    PORT
      LAYER M3 ;
        RECT  81.9 0 81.918 0.037 ;
    END
  END b[322]
  PIN b[323]
    DIRECTION OUTPUT ;
    USE SIGNAL ;
    PORT
      LAYER M3 ;
        RECT  81.972 0 81.99 0.037 ;
    END
  END b[323]
  PIN b[324]
    DIRECTION OUTPUT ;
    USE SIGNAL ;
    PORT
      LAYER M3 ;
        RECT  82.044 0 82.062 0.037 ;
    END
  END b[324]
  PIN b[325]
    DIRECTION OUTPUT ;
    USE SIGNAL ;
    PORT
      LAYER M3 ;
        RECT  82.116 0 82.134 0.037 ;
    END
  END b[325]
  PIN b[326]
    DIRECTION OUTPUT ;
    USE SIGNAL ;
    PORT
      LAYER M3 ;
        RECT  82.188 0 82.206 0.037 ;
    END
  END b[326]
  PIN b[327]
    DIRECTION OUTPUT ;
    USE SIGNAL ;
    PORT
      LAYER M3 ;
        RECT  82.26 0 82.278 0.037 ;
    END
  END b[327]
  PIN b[328]
    DIRECTION OUTPUT ;
    USE SIGNAL ;
    PORT
      LAYER M3 ;
        RECT  82.332 0 82.35 0.037 ;
    END
  END b[328]
  PIN b[329]
    DIRECTION OUTPUT ;
    USE SIGNAL ;
    PORT
      LAYER M3 ;
        RECT  82.404 0 82.422 0.037 ;
    END
  END b[329]
  PIN b[32]
    DIRECTION OUTPUT ;
    USE SIGNAL ;
    PORT
      LAYER M3 ;
        RECT  17.244 0 17.262 0.037 ;
    END
  END b[32]
  PIN b[330]
    DIRECTION OUTPUT ;
    USE SIGNAL ;
    PORT
      LAYER M3 ;
        RECT  82.476 0 82.494 0.037 ;
    END
  END b[330]
  PIN b[331]
    DIRECTION OUTPUT ;
    USE SIGNAL ;
    PORT
      LAYER M3 ;
        RECT  82.548 0 82.566 0.037 ;
    END
  END b[331]
  PIN b[332]
    DIRECTION OUTPUT ;
    USE SIGNAL ;
    PORT
      LAYER M3 ;
        RECT  82.62 0 82.638 0.037 ;
    END
  END b[332]
  PIN b[333]
    DIRECTION OUTPUT ;
    USE SIGNAL ;
    PORT
      LAYER M3 ;
        RECT  82.692 0 82.71 0.037 ;
    END
  END b[333]
  PIN b[334]
    DIRECTION OUTPUT ;
    USE SIGNAL ;
    PORT
      LAYER M3 ;
        RECT  82.764 0 82.782 0.037 ;
    END
  END b[334]
  PIN b[335]
    DIRECTION OUTPUT ;
    USE SIGNAL ;
    PORT
      LAYER M3 ;
        RECT  82.836 0 82.854 0.037 ;
    END
  END b[335]
  PIN b[336]
    DIRECTION OUTPUT ;
    USE SIGNAL ;
    PORT
      LAYER M3 ;
        RECT  82.908 0 82.926 0.037 ;
    END
  END b[336]
  PIN b[337]
    DIRECTION OUTPUT ;
    USE SIGNAL ;
    PORT
      LAYER M3 ;
        RECT  82.98 0 82.998 0.037 ;
    END
  END b[337]
  PIN b[338]
    DIRECTION OUTPUT ;
    USE SIGNAL ;
    PORT
      LAYER M3 ;
        RECT  83.052 0 83.07 0.037 ;
    END
  END b[338]
  PIN b[339]
    DIRECTION OUTPUT ;
    USE SIGNAL ;
    PORT
      LAYER M3 ;
        RECT  83.124 0 83.142 0.037 ;
    END
  END b[339]
  PIN b[33]
    DIRECTION OUTPUT ;
    USE SIGNAL ;
    PORT
      LAYER M3 ;
        RECT  17.316 0 17.334 0.037 ;
    END
  END b[33]
  PIN b[340]
    DIRECTION OUTPUT ;
    USE SIGNAL ;
    PORT
      LAYER M3 ;
        RECT  83.196 0 83.214 0.037 ;
    END
  END b[340]
  PIN b[341]
    DIRECTION OUTPUT ;
    USE SIGNAL ;
    PORT
      LAYER M3 ;
        RECT  83.268 0 83.286 0.037 ;
    END
  END b[341]
  PIN b[342]
    DIRECTION OUTPUT ;
    USE SIGNAL ;
    PORT
      LAYER M3 ;
        RECT  83.34 0 83.358 0.037 ;
    END
  END b[342]
  PIN b[343]
    DIRECTION OUTPUT ;
    USE SIGNAL ;
    PORT
      LAYER M3 ;
        RECT  83.412 0 83.43 0.037 ;
    END
  END b[343]
  PIN b[344]
    DIRECTION OUTPUT ;
    USE SIGNAL ;
    PORT
      LAYER M3 ;
        RECT  83.484 0 83.502 0.037 ;
    END
  END b[344]
  PIN b[345]
    DIRECTION OUTPUT ;
    USE SIGNAL ;
    PORT
      LAYER M3 ;
        RECT  83.556 0 83.574 0.037 ;
    END
  END b[345]
  PIN b[346]
    DIRECTION OUTPUT ;
    USE SIGNAL ;
    PORT
      LAYER M3 ;
        RECT  83.628 0 83.646 0.037 ;
    END
  END b[346]
  PIN b[347]
    DIRECTION OUTPUT ;
    USE SIGNAL ;
    PORT
      LAYER M3 ;
        RECT  83.7 0 83.718 0.037 ;
    END
  END b[347]
  PIN b[348]
    DIRECTION OUTPUT ;
    USE SIGNAL ;
    PORT
      LAYER M3 ;
        RECT  83.772 0 83.79 0.037 ;
    END
  END b[348]
  PIN b[349]
    DIRECTION OUTPUT ;
    USE SIGNAL ;
    PORT
      LAYER M3 ;
        RECT  83.844 0 83.862 0.037 ;
    END
  END b[349]
  PIN b[34]
    DIRECTION OUTPUT ;
    USE SIGNAL ;
    PORT
      LAYER M3 ;
        RECT  17.388 0 17.406 0.037 ;
    END
  END b[34]
  PIN b[350]
    DIRECTION OUTPUT ;
    USE SIGNAL ;
    PORT
      LAYER M3 ;
        RECT  83.916 0 83.934 0.037 ;
    END
  END b[350]
  PIN b[351]
    DIRECTION OUTPUT ;
    USE SIGNAL ;
    PORT
      LAYER M3 ;
        RECT  83.988 0 84.006 0.037 ;
    END
  END b[351]
  PIN b[352]
    DIRECTION OUTPUT ;
    USE SIGNAL ;
    PORT
      LAYER M5 ;
        RECT  86.736 0 86.76 0.084 ;
    END
  END b[352]
  PIN b[353]
    DIRECTION OUTPUT ;
    USE SIGNAL ;
    PORT
      LAYER M5 ;
        RECT  86.832 0 86.856 0.084 ;
    END
  END b[353]
  PIN b[354]
    DIRECTION OUTPUT ;
    USE SIGNAL ;
    PORT
      LAYER M5 ;
        RECT  86.928 0 86.952 0.084 ;
    END
  END b[354]
  PIN b[355]
    DIRECTION OUTPUT ;
    USE SIGNAL ;
    PORT
      LAYER M5 ;
        RECT  87.024 0 87.048 0.084 ;
    END
  END b[355]
  PIN b[356]
    DIRECTION OUTPUT ;
    USE SIGNAL ;
    PORT
      LAYER M5 ;
        RECT  87.12 0 87.144 0.084 ;
    END
  END b[356]
  PIN b[357]
    DIRECTION OUTPUT ;
    USE SIGNAL ;
    PORT
      LAYER M5 ;
        RECT  87.216 0 87.24 0.084 ;
    END
  END b[357]
  PIN b[358]
    DIRECTION OUTPUT ;
    USE SIGNAL ;
    PORT
      LAYER M5 ;
        RECT  87.312 0 87.336 0.084 ;
    END
  END b[358]
  PIN b[359]
    DIRECTION OUTPUT ;
    USE SIGNAL ;
    PORT
      LAYER M5 ;
        RECT  87.408 0 87.432 0.084 ;
    END
  END b[359]
  PIN b[35]
    DIRECTION OUTPUT ;
    USE SIGNAL ;
    PORT
      LAYER M3 ;
        RECT  17.46 0 17.478 0.037 ;
    END
  END b[35]
  PIN b[360]
    DIRECTION OUTPUT ;
    USE SIGNAL ;
    PORT
      LAYER M5 ;
        RECT  87.504 0 87.528 0.084 ;
    END
  END b[360]
  PIN b[361]
    DIRECTION OUTPUT ;
    USE SIGNAL ;
    PORT
      LAYER M5 ;
        RECT  87.6 0 87.624 0.084 ;
    END
  END b[361]
  PIN b[362]
    DIRECTION OUTPUT ;
    USE SIGNAL ;
    PORT
      LAYER M5 ;
        RECT  87.696 0 87.72 0.084 ;
    END
  END b[362]
  PIN b[363]
    DIRECTION OUTPUT ;
    USE SIGNAL ;
    PORT
      LAYER M5 ;
        RECT  87.792 0 87.816 0.084 ;
    END
  END b[363]
  PIN b[364]
    DIRECTION OUTPUT ;
    USE SIGNAL ;
    PORT
      LAYER M5 ;
        RECT  87.888 0 87.912 0.084 ;
    END
  END b[364]
  PIN b[365]
    DIRECTION OUTPUT ;
    USE SIGNAL ;
    PORT
      LAYER M5 ;
        RECT  87.984 0 88.008 0.084 ;
    END
  END b[365]
  PIN b[366]
    DIRECTION OUTPUT ;
    USE SIGNAL ;
    PORT
      LAYER M5 ;
        RECT  88.08 0 88.104 0.084 ;
    END
  END b[366]
  PIN b[367]
    DIRECTION OUTPUT ;
    USE SIGNAL ;
    PORT
      LAYER M5 ;
        RECT  88.176 0 88.2 0.084 ;
    END
  END b[367]
  PIN b[368]
    DIRECTION OUTPUT ;
    USE SIGNAL ;
    PORT
      LAYER M5 ;
        RECT  88.272 0 88.296 0.084 ;
    END
  END b[368]
  PIN b[369]
    DIRECTION OUTPUT ;
    USE SIGNAL ;
    PORT
      LAYER M5 ;
        RECT  88.368 0 88.392 0.084 ;
    END
  END b[369]
  PIN b[36]
    DIRECTION OUTPUT ;
    USE SIGNAL ;
    PORT
      LAYER M3 ;
        RECT  17.532 0 17.55 0.037 ;
    END
  END b[36]
  PIN b[370]
    DIRECTION OUTPUT ;
    USE SIGNAL ;
    PORT
      LAYER M5 ;
        RECT  88.464 0 88.488 0.084 ;
    END
  END b[370]
  PIN b[371]
    DIRECTION OUTPUT ;
    USE SIGNAL ;
    PORT
      LAYER M5 ;
        RECT  88.56 0 88.584 0.084 ;
    END
  END b[371]
  PIN b[372]
    DIRECTION OUTPUT ;
    USE SIGNAL ;
    PORT
      LAYER M5 ;
        RECT  88.656 0 88.68 0.084 ;
    END
  END b[372]
  PIN b[373]
    DIRECTION OUTPUT ;
    USE SIGNAL ;
    PORT
      LAYER M5 ;
        RECT  88.752 0 88.776 0.084 ;
    END
  END b[373]
  PIN b[374]
    DIRECTION OUTPUT ;
    USE SIGNAL ;
    PORT
      LAYER M5 ;
        RECT  88.848 0 88.872 0.084 ;
    END
  END b[374]
  PIN b[375]
    DIRECTION OUTPUT ;
    USE SIGNAL ;
    PORT
      LAYER M5 ;
        RECT  88.944 0 88.968 0.084 ;
    END
  END b[375]
  PIN b[376]
    DIRECTION OUTPUT ;
    USE SIGNAL ;
    PORT
      LAYER M5 ;
        RECT  89.04 0 89.064 0.084 ;
    END
  END b[376]
  PIN b[377]
    DIRECTION OUTPUT ;
    USE SIGNAL ;
    PORT
      LAYER M5 ;
        RECT  89.136 0 89.16 0.084 ;
    END
  END b[377]
  PIN b[378]
    DIRECTION OUTPUT ;
    USE SIGNAL ;
    PORT
      LAYER M5 ;
        RECT  89.232 0 89.256 0.084 ;
    END
  END b[378]
  PIN b[379]
    DIRECTION OUTPUT ;
    USE SIGNAL ;
    PORT
      LAYER M5 ;
        RECT  89.328 0 89.352 0.084 ;
    END
  END b[379]
  PIN b[37]
    DIRECTION OUTPUT ;
    USE SIGNAL ;
    PORT
      LAYER M3 ;
        RECT  17.604 0 17.622 0.037 ;
    END
  END b[37]
  PIN b[380]
    DIRECTION OUTPUT ;
    USE SIGNAL ;
    PORT
      LAYER M5 ;
        RECT  89.424 0 89.448 0.084 ;
    END
  END b[380]
  PIN b[381]
    DIRECTION OUTPUT ;
    USE SIGNAL ;
    PORT
      LAYER M5 ;
        RECT  89.52 0 89.544 0.084 ;
    END
  END b[381]
  PIN b[382]
    DIRECTION OUTPUT ;
    USE SIGNAL ;
    PORT
      LAYER M5 ;
        RECT  89.616 0 89.64 0.084 ;
    END
  END b[382]
  PIN b[383]
    DIRECTION OUTPUT ;
    USE SIGNAL ;
    PORT
      LAYER M5 ;
        RECT  89.712 0 89.736 0.084 ;
    END
  END b[383]
  PIN b[384]
    DIRECTION OUTPUT ;
    USE SIGNAL ;
    PORT
      LAYER M3 ;
        RECT  62.748 0 62.766 0.037 ;
    END
  END b[384]
  PIN b[385]
    DIRECTION OUTPUT ;
    USE SIGNAL ;
    PORT
      LAYER M3 ;
        RECT  62.82 0 62.838 0.037 ;
    END
  END b[385]
  PIN b[386]
    DIRECTION OUTPUT ;
    USE SIGNAL ;
    PORT
      LAYER M3 ;
        RECT  62.892 0 62.91 0.037 ;
    END
  END b[386]
  PIN b[387]
    DIRECTION OUTPUT ;
    USE SIGNAL ;
    PORT
      LAYER M3 ;
        RECT  62.964 0 62.982 0.037 ;
    END
  END b[387]
  PIN b[388]
    DIRECTION OUTPUT ;
    USE SIGNAL ;
    PORT
      LAYER M3 ;
        RECT  63.036 0 63.054 0.037 ;
    END
  END b[388]
  PIN b[389]
    DIRECTION OUTPUT ;
    USE SIGNAL ;
    PORT
      LAYER M3 ;
        RECT  63.108 0 63.126 0.037 ;
    END
  END b[389]
  PIN b[38]
    DIRECTION OUTPUT ;
    USE SIGNAL ;
    PORT
      LAYER M3 ;
        RECT  17.676 0 17.694 0.037 ;
    END
  END b[38]
  PIN b[390]
    DIRECTION OUTPUT ;
    USE SIGNAL ;
    PORT
      LAYER M3 ;
        RECT  63.18 0 63.198 0.037 ;
    END
  END b[390]
  PIN b[391]
    DIRECTION OUTPUT ;
    USE SIGNAL ;
    PORT
      LAYER M3 ;
        RECT  63.252 0 63.27 0.037 ;
    END
  END b[391]
  PIN b[392]
    DIRECTION OUTPUT ;
    USE SIGNAL ;
    PORT
      LAYER M3 ;
        RECT  63.324 0 63.342 0.037 ;
    END
  END b[392]
  PIN b[393]
    DIRECTION OUTPUT ;
    USE SIGNAL ;
    PORT
      LAYER M3 ;
        RECT  63.396 0 63.414 0.037 ;
    END
  END b[393]
  PIN b[394]
    DIRECTION OUTPUT ;
    USE SIGNAL ;
    PORT
      LAYER M3 ;
        RECT  63.468 0 63.486 0.037 ;
    END
  END b[394]
  PIN b[395]
    DIRECTION OUTPUT ;
    USE SIGNAL ;
    PORT
      LAYER M3 ;
        RECT  63.54 0 63.558 0.037 ;
    END
  END b[395]
  PIN b[396]
    DIRECTION OUTPUT ;
    USE SIGNAL ;
    PORT
      LAYER M3 ;
        RECT  63.612 0 63.63 0.037 ;
    END
  END b[396]
  PIN b[397]
    DIRECTION OUTPUT ;
    USE SIGNAL ;
    PORT
      LAYER M3 ;
        RECT  63.684 0 63.702 0.037 ;
    END
  END b[397]
  PIN b[398]
    DIRECTION OUTPUT ;
    USE SIGNAL ;
    PORT
      LAYER M3 ;
        RECT  63.756 0 63.774 0.037 ;
    END
  END b[398]
  PIN b[399]
    DIRECTION OUTPUT ;
    USE SIGNAL ;
    PORT
      LAYER M3 ;
        RECT  63.828 0 63.846 0.037 ;
    END
  END b[399]
  PIN b[39]
    DIRECTION OUTPUT ;
    USE SIGNAL ;
    PORT
      LAYER M3 ;
        RECT  17.748 0 17.766 0.037 ;
    END
  END b[39]
  PIN b[3]
    DIRECTION OUTPUT ;
    USE SIGNAL ;
    PORT
      LAYER M5 ;
        RECT  45.552 0 45.576 0.084 ;
    END
  END b[3]
  PIN b[400]
    DIRECTION OUTPUT ;
    USE SIGNAL ;
    PORT
      LAYER M3 ;
        RECT  63.9 0 63.918 0.037 ;
    END
  END b[400]
  PIN b[401]
    DIRECTION OUTPUT ;
    USE SIGNAL ;
    PORT
      LAYER M3 ;
        RECT  63.972 0 63.99 0.037 ;
    END
  END b[401]
  PIN b[402]
    DIRECTION OUTPUT ;
    USE SIGNAL ;
    PORT
      LAYER M3 ;
        RECT  64.044 0 64.062 0.037 ;
    END
  END b[402]
  PIN b[403]
    DIRECTION OUTPUT ;
    USE SIGNAL ;
    PORT
      LAYER M3 ;
        RECT  64.116 0 64.134 0.037 ;
    END
  END b[403]
  PIN b[404]
    DIRECTION OUTPUT ;
    USE SIGNAL ;
    PORT
      LAYER M3 ;
        RECT  64.188 0 64.206 0.037 ;
    END
  END b[404]
  PIN b[405]
    DIRECTION OUTPUT ;
    USE SIGNAL ;
    PORT
      LAYER M3 ;
        RECT  64.26 0 64.278 0.037 ;
    END
  END b[405]
  PIN b[406]
    DIRECTION OUTPUT ;
    USE SIGNAL ;
    PORT
      LAYER M3 ;
        RECT  64.332 0 64.35 0.037 ;
    END
  END b[406]
  PIN b[407]
    DIRECTION OUTPUT ;
    USE SIGNAL ;
    PORT
      LAYER M3 ;
        RECT  64.404 0 64.422 0.037 ;
    END
  END b[407]
  PIN b[408]
    DIRECTION OUTPUT ;
    USE SIGNAL ;
    PORT
      LAYER M3 ;
        RECT  64.476 0 64.494 0.037 ;
    END
  END b[408]
  PIN b[409]
    DIRECTION OUTPUT ;
    USE SIGNAL ;
    PORT
      LAYER M3 ;
        RECT  64.548 0 64.566 0.037 ;
    END
  END b[409]
  PIN b[40]
    DIRECTION OUTPUT ;
    USE SIGNAL ;
    PORT
      LAYER M3 ;
        RECT  17.82 0 17.838 0.037 ;
    END
  END b[40]
  PIN b[410]
    DIRECTION OUTPUT ;
    USE SIGNAL ;
    PORT
      LAYER M3 ;
        RECT  64.62 0 64.638 0.037 ;
    END
  END b[410]
  PIN b[411]
    DIRECTION OUTPUT ;
    USE SIGNAL ;
    PORT
      LAYER M3 ;
        RECT  64.692 0 64.71 0.037 ;
    END
  END b[411]
  PIN b[412]
    DIRECTION OUTPUT ;
    USE SIGNAL ;
    PORT
      LAYER M3 ;
        RECT  64.764 0 64.782 0.037 ;
    END
  END b[412]
  PIN b[413]
    DIRECTION OUTPUT ;
    USE SIGNAL ;
    PORT
      LAYER M3 ;
        RECT  64.836 0 64.854 0.037 ;
    END
  END b[413]
  PIN b[414]
    DIRECTION OUTPUT ;
    USE SIGNAL ;
    PORT
      LAYER M3 ;
        RECT  64.908 0 64.926 0.037 ;
    END
  END b[414]
  PIN b[415]
    DIRECTION OUTPUT ;
    USE SIGNAL ;
    PORT
      LAYER M3 ;
        RECT  64.98 0 64.998 0.037 ;
    END
  END b[415]
  PIN b[416]
    DIRECTION OUTPUT ;
    USE SIGNAL ;
    PORT
      LAYER M3 ;
        RECT  55.26 0 55.278 0.037 ;
    END
  END b[416]
  PIN b[417]
    DIRECTION OUTPUT ;
    USE SIGNAL ;
    PORT
      LAYER M3 ;
        RECT  55.332 0 55.35 0.037 ;
    END
  END b[417]
  PIN b[418]
    DIRECTION OUTPUT ;
    USE SIGNAL ;
    PORT
      LAYER M3 ;
        RECT  55.404 0 55.422 0.037 ;
    END
  END b[418]
  PIN b[419]
    DIRECTION OUTPUT ;
    USE SIGNAL ;
    PORT
      LAYER M3 ;
        RECT  55.476 0 55.494 0.037 ;
    END
  END b[419]
  PIN b[41]
    DIRECTION OUTPUT ;
    USE SIGNAL ;
    PORT
      LAYER M3 ;
        RECT  17.892 0 17.91 0.037 ;
    END
  END b[41]
  PIN b[420]
    DIRECTION OUTPUT ;
    USE SIGNAL ;
    PORT
      LAYER M3 ;
        RECT  55.548 0 55.566 0.037 ;
    END
  END b[420]
  PIN b[421]
    DIRECTION OUTPUT ;
    USE SIGNAL ;
    PORT
      LAYER M3 ;
        RECT  55.62 0 55.638 0.037 ;
    END
  END b[421]
  PIN b[422]
    DIRECTION OUTPUT ;
    USE SIGNAL ;
    PORT
      LAYER M3 ;
        RECT  55.692 0 55.71 0.037 ;
    END
  END b[422]
  PIN b[423]
    DIRECTION OUTPUT ;
    USE SIGNAL ;
    PORT
      LAYER M3 ;
        RECT  55.764 0 55.782 0.037 ;
    END
  END b[423]
  PIN b[424]
    DIRECTION OUTPUT ;
    USE SIGNAL ;
    PORT
      LAYER M3 ;
        RECT  55.836 0 55.854 0.037 ;
    END
  END b[424]
  PIN b[425]
    DIRECTION OUTPUT ;
    USE SIGNAL ;
    PORT
      LAYER M3 ;
        RECT  55.908 0 55.926 0.037 ;
    END
  END b[425]
  PIN b[426]
    DIRECTION OUTPUT ;
    USE SIGNAL ;
    PORT
      LAYER M3 ;
        RECT  55.98 0 55.998 0.037 ;
    END
  END b[426]
  PIN b[427]
    DIRECTION OUTPUT ;
    USE SIGNAL ;
    PORT
      LAYER M3 ;
        RECT  56.052 0 56.07 0.037 ;
    END
  END b[427]
  PIN b[428]
    DIRECTION OUTPUT ;
    USE SIGNAL ;
    PORT
      LAYER M3 ;
        RECT  56.124 0 56.142 0.037 ;
    END
  END b[428]
  PIN b[429]
    DIRECTION OUTPUT ;
    USE SIGNAL ;
    PORT
      LAYER M3 ;
        RECT  56.196 0 56.214 0.037 ;
    END
  END b[429]
  PIN b[42]
    DIRECTION OUTPUT ;
    USE SIGNAL ;
    PORT
      LAYER M3 ;
        RECT  17.964 0 17.982 0.037 ;
    END
  END b[42]
  PIN b[430]
    DIRECTION OUTPUT ;
    USE SIGNAL ;
    PORT
      LAYER M3 ;
        RECT  56.268 0 56.286 0.037 ;
    END
  END b[430]
  PIN b[431]
    DIRECTION OUTPUT ;
    USE SIGNAL ;
    PORT
      LAYER M3 ;
        RECT  56.34 0 56.358 0.037 ;
    END
  END b[431]
  PIN b[432]
    DIRECTION OUTPUT ;
    USE SIGNAL ;
    PORT
      LAYER M3 ;
        RECT  56.412 0 56.43 0.037 ;
    END
  END b[432]
  PIN b[433]
    DIRECTION OUTPUT ;
    USE SIGNAL ;
    PORT
      LAYER M3 ;
        RECT  56.484 0 56.502 0.037 ;
    END
  END b[433]
  PIN b[434]
    DIRECTION OUTPUT ;
    USE SIGNAL ;
    PORT
      LAYER M3 ;
        RECT  56.556 0 56.574 0.037 ;
    END
  END b[434]
  PIN b[435]
    DIRECTION OUTPUT ;
    USE SIGNAL ;
    PORT
      LAYER M3 ;
        RECT  56.628 0 56.646 0.037 ;
    END
  END b[435]
  PIN b[436]
    DIRECTION OUTPUT ;
    USE SIGNAL ;
    PORT
      LAYER M3 ;
        RECT  56.7 0 56.718 0.037 ;
    END
  END b[436]
  PIN b[437]
    DIRECTION OUTPUT ;
    USE SIGNAL ;
    PORT
      LAYER M3 ;
        RECT  56.772 0 56.79 0.037 ;
    END
  END b[437]
  PIN b[438]
    DIRECTION OUTPUT ;
    USE SIGNAL ;
    PORT
      LAYER M3 ;
        RECT  56.844 0 56.862 0.037 ;
    END
  END b[438]
  PIN b[439]
    DIRECTION OUTPUT ;
    USE SIGNAL ;
    PORT
      LAYER M3 ;
        RECT  56.916 0 56.934 0.037 ;
    END
  END b[439]
  PIN b[43]
    DIRECTION OUTPUT ;
    USE SIGNAL ;
    PORT
      LAYER M3 ;
        RECT  18.036 0 18.054 0.037 ;
    END
  END b[43]
  PIN b[440]
    DIRECTION OUTPUT ;
    USE SIGNAL ;
    PORT
      LAYER M3 ;
        RECT  56.988 0 57.006 0.037 ;
    END
  END b[440]
  PIN b[441]
    DIRECTION OUTPUT ;
    USE SIGNAL ;
    PORT
      LAYER M3 ;
        RECT  57.06 0 57.078 0.037 ;
    END
  END b[441]
  PIN b[442]
    DIRECTION OUTPUT ;
    USE SIGNAL ;
    PORT
      LAYER M3 ;
        RECT  57.132 0 57.15 0.037 ;
    END
  END b[442]
  PIN b[443]
    DIRECTION OUTPUT ;
    USE SIGNAL ;
    PORT
      LAYER M3 ;
        RECT  57.204 0 57.222 0.037 ;
    END
  END b[443]
  PIN b[444]
    DIRECTION OUTPUT ;
    USE SIGNAL ;
    PORT
      LAYER M3 ;
        RECT  57.276 0 57.294 0.037 ;
    END
  END b[444]
  PIN b[445]
    DIRECTION OUTPUT ;
    USE SIGNAL ;
    PORT
      LAYER M3 ;
        RECT  57.348 0 57.366 0.037 ;
    END
  END b[445]
  PIN b[446]
    DIRECTION OUTPUT ;
    USE SIGNAL ;
    PORT
      LAYER M3 ;
        RECT  57.42 0 57.438 0.037 ;
    END
  END b[446]
  PIN b[447]
    DIRECTION OUTPUT ;
    USE SIGNAL ;
    PORT
      LAYER M3 ;
        RECT  57.492 0 57.51 0.037 ;
    END
  END b[447]
  PIN b[448]
    DIRECTION OUTPUT ;
    USE SIGNAL ;
    PORT
      LAYER M3 ;
        RECT  24.156 0 24.174 0.037 ;
    END
  END b[448]
  PIN b[449]
    DIRECTION OUTPUT ;
    USE SIGNAL ;
    PORT
      LAYER M3 ;
        RECT  24.228 0 24.246 0.037 ;
    END
  END b[449]
  PIN b[44]
    DIRECTION OUTPUT ;
    USE SIGNAL ;
    PORT
      LAYER M3 ;
        RECT  18.108 0 18.126 0.037 ;
    END
  END b[44]
  PIN b[450]
    DIRECTION OUTPUT ;
    USE SIGNAL ;
    PORT
      LAYER M3 ;
        RECT  24.3 0 24.318 0.037 ;
    END
  END b[450]
  PIN b[451]
    DIRECTION OUTPUT ;
    USE SIGNAL ;
    PORT
      LAYER M3 ;
        RECT  24.372 0 24.39 0.037 ;
    END
  END b[451]
  PIN b[452]
    DIRECTION OUTPUT ;
    USE SIGNAL ;
    PORT
      LAYER M3 ;
        RECT  24.444 0 24.462 0.037 ;
    END
  END b[452]
  PIN b[453]
    DIRECTION OUTPUT ;
    USE SIGNAL ;
    PORT
      LAYER M3 ;
        RECT  24.516 0 24.534 0.037 ;
    END
  END b[453]
  PIN b[454]
    DIRECTION OUTPUT ;
    USE SIGNAL ;
    PORT
      LAYER M3 ;
        RECT  24.588 0 24.606 0.037 ;
    END
  END b[454]
  PIN b[455]
    DIRECTION OUTPUT ;
    USE SIGNAL ;
    PORT
      LAYER M3 ;
        RECT  24.66 0 24.678 0.037 ;
    END
  END b[455]
  PIN b[456]
    DIRECTION OUTPUT ;
    USE SIGNAL ;
    PORT
      LAYER M3 ;
        RECT  24.732 0 24.75 0.037 ;
    END
  END b[456]
  PIN b[457]
    DIRECTION OUTPUT ;
    USE SIGNAL ;
    PORT
      LAYER M3 ;
        RECT  24.804 0 24.822 0.037 ;
    END
  END b[457]
  PIN b[458]
    DIRECTION OUTPUT ;
    USE SIGNAL ;
    PORT
      LAYER M3 ;
        RECT  24.876 0 24.894 0.037 ;
    END
  END b[458]
  PIN b[459]
    DIRECTION OUTPUT ;
    USE SIGNAL ;
    PORT
      LAYER M3 ;
        RECT  24.948 0 24.966 0.037 ;
    END
  END b[459]
  PIN b[45]
    DIRECTION OUTPUT ;
    USE SIGNAL ;
    PORT
      LAYER M3 ;
        RECT  18.18 0 18.198 0.037 ;
    END
  END b[45]
  PIN b[460]
    DIRECTION OUTPUT ;
    USE SIGNAL ;
    PORT
      LAYER M3 ;
        RECT  25.02 0 25.038 0.037 ;
    END
  END b[460]
  PIN b[461]
    DIRECTION OUTPUT ;
    USE SIGNAL ;
    PORT
      LAYER M3 ;
        RECT  25.092 0 25.11 0.037 ;
    END
  END b[461]
  PIN b[462]
    DIRECTION OUTPUT ;
    USE SIGNAL ;
    PORT
      LAYER M3 ;
        RECT  25.164 0 25.182 0.037 ;
    END
  END b[462]
  PIN b[463]
    DIRECTION OUTPUT ;
    USE SIGNAL ;
    PORT
      LAYER M3 ;
        RECT  25.236 0 25.254 0.037 ;
    END
  END b[463]
  PIN b[464]
    DIRECTION OUTPUT ;
    USE SIGNAL ;
    PORT
      LAYER M3 ;
        RECT  25.308 0 25.326 0.037 ;
    END
  END b[464]
  PIN b[465]
    DIRECTION OUTPUT ;
    USE SIGNAL ;
    PORT
      LAYER M3 ;
        RECT  25.38 0 25.398 0.037 ;
    END
  END b[465]
  PIN b[466]
    DIRECTION OUTPUT ;
    USE SIGNAL ;
    PORT
      LAYER M3 ;
        RECT  25.452 0 25.47 0.037 ;
    END
  END b[466]
  PIN b[467]
    DIRECTION OUTPUT ;
    USE SIGNAL ;
    PORT
      LAYER M3 ;
        RECT  25.524 0 25.542 0.037 ;
    END
  END b[467]
  PIN b[468]
    DIRECTION OUTPUT ;
    USE SIGNAL ;
    PORT
      LAYER M3 ;
        RECT  25.596 0 25.614 0.037 ;
    END
  END b[468]
  PIN b[469]
    DIRECTION OUTPUT ;
    USE SIGNAL ;
    PORT
      LAYER M3 ;
        RECT  25.668 0 25.686 0.037 ;
    END
  END b[469]
  PIN b[46]
    DIRECTION OUTPUT ;
    USE SIGNAL ;
    PORT
      LAYER M3 ;
        RECT  18.252 0 18.27 0.037 ;
    END
  END b[46]
  PIN b[470]
    DIRECTION OUTPUT ;
    USE SIGNAL ;
    PORT
      LAYER M3 ;
        RECT  25.74 0 25.758 0.037 ;
    END
  END b[470]
  PIN b[471]
    DIRECTION OUTPUT ;
    USE SIGNAL ;
    PORT
      LAYER M3 ;
        RECT  25.812 0 25.83 0.037 ;
    END
  END b[471]
  PIN b[472]
    DIRECTION OUTPUT ;
    USE SIGNAL ;
    PORT
      LAYER M3 ;
        RECT  25.884 0 25.902 0.037 ;
    END
  END b[472]
  PIN b[473]
    DIRECTION OUTPUT ;
    USE SIGNAL ;
    PORT
      LAYER M3 ;
        RECT  25.956 0 25.974 0.037 ;
    END
  END b[473]
  PIN b[474]
    DIRECTION OUTPUT ;
    USE SIGNAL ;
    PORT
      LAYER M3 ;
        RECT  26.028 0 26.046 0.037 ;
    END
  END b[474]
  PIN b[475]
    DIRECTION OUTPUT ;
    USE SIGNAL ;
    PORT
      LAYER M3 ;
        RECT  26.1 0 26.118 0.037 ;
    END
  END b[475]
  PIN b[476]
    DIRECTION OUTPUT ;
    USE SIGNAL ;
    PORT
      LAYER M3 ;
        RECT  26.172 0 26.19 0.037 ;
    END
  END b[476]
  PIN b[477]
    DIRECTION OUTPUT ;
    USE SIGNAL ;
    PORT
      LAYER M3 ;
        RECT  26.244 0 26.262 0.037 ;
    END
  END b[477]
  PIN b[478]
    DIRECTION OUTPUT ;
    USE SIGNAL ;
    PORT
      LAYER M3 ;
        RECT  26.316 0 26.334 0.037 ;
    END
  END b[478]
  PIN b[479]
    DIRECTION OUTPUT ;
    USE SIGNAL ;
    PORT
      LAYER M3 ;
        RECT  26.388 0 26.406 0.037 ;
    END
  END b[479]
  PIN b[47]
    DIRECTION OUTPUT ;
    USE SIGNAL ;
    PORT
      LAYER M3 ;
        RECT  18.324 0 18.342 0.037 ;
    END
  END b[47]
  PIN b[480]
    DIRECTION OUTPUT ;
    USE SIGNAL ;
    PORT
      LAYER M5 ;
        RECT  29.136 0 29.16 0.084 ;
    END
  END b[480]
  PIN b[481]
    DIRECTION OUTPUT ;
    USE SIGNAL ;
    PORT
      LAYER M5 ;
        RECT  29.232 0 29.256 0.084 ;
    END
  END b[481]
  PIN b[482]
    DIRECTION OUTPUT ;
    USE SIGNAL ;
    PORT
      LAYER M5 ;
        RECT  29.328 0 29.352 0.084 ;
    END
  END b[482]
  PIN b[483]
    DIRECTION OUTPUT ;
    USE SIGNAL ;
    PORT
      LAYER M5 ;
        RECT  29.424 0 29.448 0.084 ;
    END
  END b[483]
  PIN b[484]
    DIRECTION OUTPUT ;
    USE SIGNAL ;
    PORT
      LAYER M5 ;
        RECT  29.52 0 29.544 0.084 ;
    END
  END b[484]
  PIN b[485]
    DIRECTION OUTPUT ;
    USE SIGNAL ;
    PORT
      LAYER M5 ;
        RECT  29.616 0 29.64 0.084 ;
    END
  END b[485]
  PIN b[486]
    DIRECTION OUTPUT ;
    USE SIGNAL ;
    PORT
      LAYER M5 ;
        RECT  29.712 0 29.736 0.084 ;
    END
  END b[486]
  PIN b[487]
    DIRECTION OUTPUT ;
    USE SIGNAL ;
    PORT
      LAYER M5 ;
        RECT  29.808 0 29.832 0.084 ;
    END
  END b[487]
  PIN b[488]
    DIRECTION OUTPUT ;
    USE SIGNAL ;
    PORT
      LAYER M5 ;
        RECT  29.904 0 29.928 0.084 ;
    END
  END b[488]
  PIN b[489]
    DIRECTION OUTPUT ;
    USE SIGNAL ;
    PORT
      LAYER M5 ;
        RECT  30 0 30.024 0.084 ;
    END
  END b[489]
  PIN b[48]
    DIRECTION OUTPUT ;
    USE SIGNAL ;
    PORT
      LAYER M3 ;
        RECT  18.396 0 18.414 0.037 ;
    END
  END b[48]
  PIN b[490]
    DIRECTION OUTPUT ;
    USE SIGNAL ;
    PORT
      LAYER M5 ;
        RECT  30.096 0 30.12 0.084 ;
    END
  END b[490]
  PIN b[491]
    DIRECTION OUTPUT ;
    USE SIGNAL ;
    PORT
      LAYER M5 ;
        RECT  30.192 0 30.216 0.084 ;
    END
  END b[491]
  PIN b[492]
    DIRECTION OUTPUT ;
    USE SIGNAL ;
    PORT
      LAYER M5 ;
        RECT  30.288 0 30.312 0.084 ;
    END
  END b[492]
  PIN b[493]
    DIRECTION OUTPUT ;
    USE SIGNAL ;
    PORT
      LAYER M5 ;
        RECT  30.384 0 30.408 0.084 ;
    END
  END b[493]
  PIN b[494]
    DIRECTION OUTPUT ;
    USE SIGNAL ;
    PORT
      LAYER M5 ;
        RECT  30.48 0 30.504 0.084 ;
    END
  END b[494]
  PIN b[495]
    DIRECTION OUTPUT ;
    USE SIGNAL ;
    PORT
      LAYER M5 ;
        RECT  30.576 0 30.6 0.084 ;
    END
  END b[495]
  PIN b[496]
    DIRECTION OUTPUT ;
    USE SIGNAL ;
    PORT
      LAYER M5 ;
        RECT  30.672 0 30.696 0.084 ;
    END
  END b[496]
  PIN b[497]
    DIRECTION OUTPUT ;
    USE SIGNAL ;
    PORT
      LAYER M5 ;
        RECT  30.768 0 30.792 0.084 ;
    END
  END b[497]
  PIN b[498]
    DIRECTION OUTPUT ;
    USE SIGNAL ;
    PORT
      LAYER M5 ;
        RECT  30.864 0 30.888 0.084 ;
    END
  END b[498]
  PIN b[499]
    DIRECTION OUTPUT ;
    USE SIGNAL ;
    PORT
      LAYER M5 ;
        RECT  30.96 0 30.984 0.084 ;
    END
  END b[499]
  PIN b[49]
    DIRECTION OUTPUT ;
    USE SIGNAL ;
    PORT
      LAYER M3 ;
        RECT  18.468 0 18.486 0.037 ;
    END
  END b[49]
  PIN b[4]
    DIRECTION OUTPUT ;
    USE SIGNAL ;
    PORT
      LAYER M5 ;
        RECT  45.648 0 45.672 0.084 ;
    END
  END b[4]
  PIN b[500]
    DIRECTION OUTPUT ;
    USE SIGNAL ;
    PORT
      LAYER M5 ;
        RECT  31.056 0 31.08 0.084 ;
    END
  END b[500]
  PIN b[501]
    DIRECTION OUTPUT ;
    USE SIGNAL ;
    PORT
      LAYER M5 ;
        RECT  31.152 0 31.176 0.084 ;
    END
  END b[501]
  PIN b[502]
    DIRECTION OUTPUT ;
    USE SIGNAL ;
    PORT
      LAYER M5 ;
        RECT  31.248 0 31.272 0.084 ;
    END
  END b[502]
  PIN b[503]
    DIRECTION OUTPUT ;
    USE SIGNAL ;
    PORT
      LAYER M5 ;
        RECT  31.344 0 31.368 0.084 ;
    END
  END b[503]
  PIN b[504]
    DIRECTION OUTPUT ;
    USE SIGNAL ;
    PORT
      LAYER M5 ;
        RECT  31.44 0 31.464 0.084 ;
    END
  END b[504]
  PIN b[505]
    DIRECTION OUTPUT ;
    USE SIGNAL ;
    PORT
      LAYER M5 ;
        RECT  31.536 0 31.56 0.084 ;
    END
  END b[505]
  PIN b[506]
    DIRECTION OUTPUT ;
    USE SIGNAL ;
    PORT
      LAYER M5 ;
        RECT  31.632 0 31.656 0.084 ;
    END
  END b[506]
  PIN b[507]
    DIRECTION OUTPUT ;
    USE SIGNAL ;
    PORT
      LAYER M5 ;
        RECT  31.728 0 31.752 0.084 ;
    END
  END b[507]
  PIN b[508]
    DIRECTION OUTPUT ;
    USE SIGNAL ;
    PORT
      LAYER M5 ;
        RECT  31.824 0 31.848 0.084 ;
    END
  END b[508]
  PIN b[509]
    DIRECTION OUTPUT ;
    USE SIGNAL ;
    PORT
      LAYER M5 ;
        RECT  31.92 0 31.944 0.084 ;
    END
  END b[509]
  PIN b[50]
    DIRECTION OUTPUT ;
    USE SIGNAL ;
    PORT
      LAYER M3 ;
        RECT  18.54 0 18.558 0.037 ;
    END
  END b[50]
  PIN b[510]
    DIRECTION OUTPUT ;
    USE SIGNAL ;
    PORT
      LAYER M5 ;
        RECT  32.016 0 32.04 0.084 ;
    END
  END b[510]
  PIN b[511]
    DIRECTION OUTPUT ;
    USE SIGNAL ;
    PORT
      LAYER M5 ;
        RECT  32.112 0 32.136 0.084 ;
    END
  END b[511]
  PIN b[512]
    DIRECTION OUTPUT ;
    USE SIGNAL ;
    PORT
      LAYER M3 ;
        RECT  14.94 0 14.958 0.037 ;
    END
  END b[512]
  PIN b[513]
    DIRECTION OUTPUT ;
    USE SIGNAL ;
    PORT
      LAYER M3 ;
        RECT  15.012 0 15.03 0.037 ;
    END
  END b[513]
  PIN b[514]
    DIRECTION OUTPUT ;
    USE SIGNAL ;
    PORT
      LAYER M3 ;
        RECT  15.084 0 15.102 0.037 ;
    END
  END b[514]
  PIN b[515]
    DIRECTION OUTPUT ;
    USE SIGNAL ;
    PORT
      LAYER M3 ;
        RECT  15.156 0 15.174 0.037 ;
    END
  END b[515]
  PIN b[516]
    DIRECTION OUTPUT ;
    USE SIGNAL ;
    PORT
      LAYER M3 ;
        RECT  15.228 0 15.246 0.037 ;
    END
  END b[516]
  PIN b[517]
    DIRECTION OUTPUT ;
    USE SIGNAL ;
    PORT
      LAYER M3 ;
        RECT  15.3 0 15.318 0.037 ;
    END
  END b[517]
  PIN b[518]
    DIRECTION OUTPUT ;
    USE SIGNAL ;
    PORT
      LAYER M3 ;
        RECT  15.372 0 15.39 0.037 ;
    END
  END b[518]
  PIN b[519]
    DIRECTION OUTPUT ;
    USE SIGNAL ;
    PORT
      LAYER M3 ;
        RECT  15.444 0 15.462 0.037 ;
    END
  END b[519]
  PIN b[51]
    DIRECTION OUTPUT ;
    USE SIGNAL ;
    PORT
      LAYER M3 ;
        RECT  18.612 0 18.63 0.037 ;
    END
  END b[51]
  PIN b[520]
    DIRECTION OUTPUT ;
    USE SIGNAL ;
    PORT
      LAYER M3 ;
        RECT  15.516 0 15.534 0.037 ;
    END
  END b[520]
  PIN b[521]
    DIRECTION OUTPUT ;
    USE SIGNAL ;
    PORT
      LAYER M3 ;
        RECT  15.588 0 15.606 0.037 ;
    END
  END b[521]
  PIN b[522]
    DIRECTION OUTPUT ;
    USE SIGNAL ;
    PORT
      LAYER M3 ;
        RECT  15.66 0 15.678 0.037 ;
    END
  END b[522]
  PIN b[523]
    DIRECTION OUTPUT ;
    USE SIGNAL ;
    PORT
      LAYER M3 ;
        RECT  15.732 0 15.75 0.037 ;
    END
  END b[523]
  PIN b[524]
    DIRECTION OUTPUT ;
    USE SIGNAL ;
    PORT
      LAYER M3 ;
        RECT  15.804 0 15.822 0.037 ;
    END
  END b[524]
  PIN b[525]
    DIRECTION OUTPUT ;
    USE SIGNAL ;
    PORT
      LAYER M3 ;
        RECT  15.876 0 15.894 0.037 ;
    END
  END b[525]
  PIN b[526]
    DIRECTION OUTPUT ;
    USE SIGNAL ;
    PORT
      LAYER M3 ;
        RECT  15.948 0 15.966 0.037 ;
    END
  END b[526]
  PIN b[527]
    DIRECTION OUTPUT ;
    USE SIGNAL ;
    PORT
      LAYER M3 ;
        RECT  16.02 0 16.038 0.037 ;
    END
  END b[527]
  PIN b[528]
    DIRECTION OUTPUT ;
    USE SIGNAL ;
    PORT
      LAYER M3 ;
        RECT  16.092 0 16.11 0.037 ;
    END
  END b[528]
  PIN b[529]
    DIRECTION OUTPUT ;
    USE SIGNAL ;
    PORT
      LAYER M3 ;
        RECT  16.164 0 16.182 0.037 ;
    END
  END b[529]
  PIN b[52]
    DIRECTION OUTPUT ;
    USE SIGNAL ;
    PORT
      LAYER M3 ;
        RECT  18.684 0 18.702 0.037 ;
    END
  END b[52]
  PIN b[530]
    DIRECTION OUTPUT ;
    USE SIGNAL ;
    PORT
      LAYER M3 ;
        RECT  16.236 0 16.254 0.037 ;
    END
  END b[530]
  PIN b[531]
    DIRECTION OUTPUT ;
    USE SIGNAL ;
    PORT
      LAYER M3 ;
        RECT  16.308 0 16.326 0.037 ;
    END
  END b[531]
  PIN b[532]
    DIRECTION OUTPUT ;
    USE SIGNAL ;
    PORT
      LAYER M3 ;
        RECT  16.38 0 16.398 0.037 ;
    END
  END b[532]
  PIN b[533]
    DIRECTION OUTPUT ;
    USE SIGNAL ;
    PORT
      LAYER M3 ;
        RECT  16.452 0 16.47 0.037 ;
    END
  END b[533]
  PIN b[534]
    DIRECTION OUTPUT ;
    USE SIGNAL ;
    PORT
      LAYER M3 ;
        RECT  16.524 0 16.542 0.037 ;
    END
  END b[534]
  PIN b[535]
    DIRECTION OUTPUT ;
    USE SIGNAL ;
    PORT
      LAYER M3 ;
        RECT  16.596 0 16.614 0.037 ;
    END
  END b[535]
  PIN b[536]
    DIRECTION OUTPUT ;
    USE SIGNAL ;
    PORT
      LAYER M3 ;
        RECT  16.668 0 16.686 0.037 ;
    END
  END b[536]
  PIN b[537]
    DIRECTION OUTPUT ;
    USE SIGNAL ;
    PORT
      LAYER M3 ;
        RECT  16.74 0 16.758 0.037 ;
    END
  END b[537]
  PIN b[538]
    DIRECTION OUTPUT ;
    USE SIGNAL ;
    PORT
      LAYER M3 ;
        RECT  16.812 0 16.83 0.037 ;
    END
  END b[538]
  PIN b[539]
    DIRECTION OUTPUT ;
    USE SIGNAL ;
    PORT
      LAYER M3 ;
        RECT  16.884 0 16.902 0.037 ;
    END
  END b[539]
  PIN b[53]
    DIRECTION OUTPUT ;
    USE SIGNAL ;
    PORT
      LAYER M3 ;
        RECT  18.756 0 18.774 0.037 ;
    END
  END b[53]
  PIN b[540]
    DIRECTION OUTPUT ;
    USE SIGNAL ;
    PORT
      LAYER M3 ;
        RECT  16.956 0 16.974 0.037 ;
    END
  END b[540]
  PIN b[541]
    DIRECTION OUTPUT ;
    USE SIGNAL ;
    PORT
      LAYER M3 ;
        RECT  17.028 0 17.046 0.037 ;
    END
  END b[541]
  PIN b[542]
    DIRECTION OUTPUT ;
    USE SIGNAL ;
    PORT
      LAYER M3 ;
        RECT  17.1 0 17.118 0.037 ;
    END
  END b[542]
  PIN b[543]
    DIRECTION OUTPUT ;
    USE SIGNAL ;
    PORT
      LAYER M3 ;
        RECT  17.172 0 17.19 0.037 ;
    END
  END b[543]
  PIN b[544]
    DIRECTION OUTPUT ;
    USE SIGNAL ;
    PORT
      LAYER M3 ;
        RECT  21.852 0 21.87 0.037 ;
    END
  END b[544]
  PIN b[545]
    DIRECTION OUTPUT ;
    USE SIGNAL ;
    PORT
      LAYER M3 ;
        RECT  21.924 0 21.942 0.037 ;
    END
  END b[545]
  PIN b[546]
    DIRECTION OUTPUT ;
    USE SIGNAL ;
    PORT
      LAYER M3 ;
        RECT  21.996 0 22.014 0.037 ;
    END
  END b[546]
  PIN b[547]
    DIRECTION OUTPUT ;
    USE SIGNAL ;
    PORT
      LAYER M3 ;
        RECT  22.068 0 22.086 0.037 ;
    END
  END b[547]
  PIN b[548]
    DIRECTION OUTPUT ;
    USE SIGNAL ;
    PORT
      LAYER M3 ;
        RECT  22.14 0 22.158 0.037 ;
    END
  END b[548]
  PIN b[549]
    DIRECTION OUTPUT ;
    USE SIGNAL ;
    PORT
      LAYER M3 ;
        RECT  22.212 0 22.23 0.037 ;
    END
  END b[549]
  PIN b[54]
    DIRECTION OUTPUT ;
    USE SIGNAL ;
    PORT
      LAYER M3 ;
        RECT  18.828 0 18.846 0.037 ;
    END
  END b[54]
  PIN b[550]
    DIRECTION OUTPUT ;
    USE SIGNAL ;
    PORT
      LAYER M3 ;
        RECT  22.284 0 22.302 0.037 ;
    END
  END b[550]
  PIN b[551]
    DIRECTION OUTPUT ;
    USE SIGNAL ;
    PORT
      LAYER M3 ;
        RECT  22.356 0 22.374 0.037 ;
    END
  END b[551]
  PIN b[552]
    DIRECTION OUTPUT ;
    USE SIGNAL ;
    PORT
      LAYER M3 ;
        RECT  22.428 0 22.446 0.037 ;
    END
  END b[552]
  PIN b[553]
    DIRECTION OUTPUT ;
    USE SIGNAL ;
    PORT
      LAYER M3 ;
        RECT  22.5 0 22.518 0.037 ;
    END
  END b[553]
  PIN b[554]
    DIRECTION OUTPUT ;
    USE SIGNAL ;
    PORT
      LAYER M3 ;
        RECT  22.572 0 22.59 0.037 ;
    END
  END b[554]
  PIN b[555]
    DIRECTION OUTPUT ;
    USE SIGNAL ;
    PORT
      LAYER M3 ;
        RECT  22.644 0 22.662 0.037 ;
    END
  END b[555]
  PIN b[556]
    DIRECTION OUTPUT ;
    USE SIGNAL ;
    PORT
      LAYER M3 ;
        RECT  22.716 0 22.734 0.037 ;
    END
  END b[556]
  PIN b[557]
    DIRECTION OUTPUT ;
    USE SIGNAL ;
    PORT
      LAYER M3 ;
        RECT  22.788 0 22.806 0.037 ;
    END
  END b[557]
  PIN b[558]
    DIRECTION OUTPUT ;
    USE SIGNAL ;
    PORT
      LAYER M3 ;
        RECT  22.86 0 22.878 0.037 ;
    END
  END b[558]
  PIN b[559]
    DIRECTION OUTPUT ;
    USE SIGNAL ;
    PORT
      LAYER M3 ;
        RECT  22.932 0 22.95 0.037 ;
    END
  END b[559]
  PIN b[55]
    DIRECTION OUTPUT ;
    USE SIGNAL ;
    PORT
      LAYER M3 ;
        RECT  18.9 0 18.918 0.037 ;
    END
  END b[55]
  PIN b[560]
    DIRECTION OUTPUT ;
    USE SIGNAL ;
    PORT
      LAYER M3 ;
        RECT  23.004 0 23.022 0.037 ;
    END
  END b[560]
  PIN b[561]
    DIRECTION OUTPUT ;
    USE SIGNAL ;
    PORT
      LAYER M3 ;
        RECT  23.076 0 23.094 0.037 ;
    END
  END b[561]
  PIN b[562]
    DIRECTION OUTPUT ;
    USE SIGNAL ;
    PORT
      LAYER M3 ;
        RECT  23.148 0 23.166 0.037 ;
    END
  END b[562]
  PIN b[563]
    DIRECTION OUTPUT ;
    USE SIGNAL ;
    PORT
      LAYER M3 ;
        RECT  23.22 0 23.238 0.037 ;
    END
  END b[563]
  PIN b[564]
    DIRECTION OUTPUT ;
    USE SIGNAL ;
    PORT
      LAYER M3 ;
        RECT  23.292 0 23.31 0.037 ;
    END
  END b[564]
  PIN b[565]
    DIRECTION OUTPUT ;
    USE SIGNAL ;
    PORT
      LAYER M3 ;
        RECT  23.364 0 23.382 0.037 ;
    END
  END b[565]
  PIN b[566]
    DIRECTION OUTPUT ;
    USE SIGNAL ;
    PORT
      LAYER M3 ;
        RECT  23.436 0 23.454 0.037 ;
    END
  END b[566]
  PIN b[567]
    DIRECTION OUTPUT ;
    USE SIGNAL ;
    PORT
      LAYER M3 ;
        RECT  23.508 0 23.526 0.037 ;
    END
  END b[567]
  PIN b[568]
    DIRECTION OUTPUT ;
    USE SIGNAL ;
    PORT
      LAYER M3 ;
        RECT  23.58 0 23.598 0.037 ;
    END
  END b[568]
  PIN b[569]
    DIRECTION OUTPUT ;
    USE SIGNAL ;
    PORT
      LAYER M3 ;
        RECT  23.652 0 23.67 0.037 ;
    END
  END b[569]
  PIN b[56]
    DIRECTION OUTPUT ;
    USE SIGNAL ;
    PORT
      LAYER M3 ;
        RECT  18.972 0 18.99 0.037 ;
    END
  END b[56]
  PIN b[570]
    DIRECTION OUTPUT ;
    USE SIGNAL ;
    PORT
      LAYER M3 ;
        RECT  23.724 0 23.742 0.037 ;
    END
  END b[570]
  PIN b[571]
    DIRECTION OUTPUT ;
    USE SIGNAL ;
    PORT
      LAYER M3 ;
        RECT  23.796 0 23.814 0.037 ;
    END
  END b[571]
  PIN b[572]
    DIRECTION OUTPUT ;
    USE SIGNAL ;
    PORT
      LAYER M3 ;
        RECT  23.868 0 23.886 0.037 ;
    END
  END b[572]
  PIN b[573]
    DIRECTION OUTPUT ;
    USE SIGNAL ;
    PORT
      LAYER M3 ;
        RECT  23.94 0 23.958 0.037 ;
    END
  END b[573]
  PIN b[574]
    DIRECTION OUTPUT ;
    USE SIGNAL ;
    PORT
      LAYER M3 ;
        RECT  24.012 0 24.03 0.037 ;
    END
  END b[574]
  PIN b[575]
    DIRECTION OUTPUT ;
    USE SIGNAL ;
    PORT
      LAYER M3 ;
        RECT  24.084 0 24.102 0.037 ;
    END
  END b[575]
  PIN b[576]
    DIRECTION OUTPUT ;
    USE SIGNAL ;
    PORT
      LAYER M3 ;
        RECT  40.86 0 40.878 0.037 ;
    END
  END b[576]
  PIN b[577]
    DIRECTION OUTPUT ;
    USE SIGNAL ;
    PORT
      LAYER M3 ;
        RECT  40.932 0 40.95 0.037 ;
    END
  END b[577]
  PIN b[578]
    DIRECTION OUTPUT ;
    USE SIGNAL ;
    PORT
      LAYER M3 ;
        RECT  41.004 0 41.022 0.037 ;
    END
  END b[578]
  PIN b[579]
    DIRECTION OUTPUT ;
    USE SIGNAL ;
    PORT
      LAYER M3 ;
        RECT  41.076 0 41.094 0.037 ;
    END
  END b[579]
  PIN b[57]
    DIRECTION OUTPUT ;
    USE SIGNAL ;
    PORT
      LAYER M3 ;
        RECT  19.044 0 19.062 0.037 ;
    END
  END b[57]
  PIN b[580]
    DIRECTION OUTPUT ;
    USE SIGNAL ;
    PORT
      LAYER M3 ;
        RECT  41.148 0 41.166 0.037 ;
    END
  END b[580]
  PIN b[581]
    DIRECTION OUTPUT ;
    USE SIGNAL ;
    PORT
      LAYER M3 ;
        RECT  41.22 0 41.238 0.037 ;
    END
  END b[581]
  PIN b[582]
    DIRECTION OUTPUT ;
    USE SIGNAL ;
    PORT
      LAYER M3 ;
        RECT  41.292 0 41.31 0.037 ;
    END
  END b[582]
  PIN b[583]
    DIRECTION OUTPUT ;
    USE SIGNAL ;
    PORT
      LAYER M3 ;
        RECT  41.364 0 41.382 0.037 ;
    END
  END b[583]
  PIN b[584]
    DIRECTION OUTPUT ;
    USE SIGNAL ;
    PORT
      LAYER M3 ;
        RECT  41.436 0 41.454 0.037 ;
    END
  END b[584]
  PIN b[585]
    DIRECTION OUTPUT ;
    USE SIGNAL ;
    PORT
      LAYER M3 ;
        RECT  41.508 0 41.526 0.037 ;
    END
  END b[585]
  PIN b[586]
    DIRECTION OUTPUT ;
    USE SIGNAL ;
    PORT
      LAYER M3 ;
        RECT  41.58 0 41.598 0.037 ;
    END
  END b[586]
  PIN b[587]
    DIRECTION OUTPUT ;
    USE SIGNAL ;
    PORT
      LAYER M3 ;
        RECT  41.652 0 41.67 0.037 ;
    END
  END b[587]
  PIN b[588]
    DIRECTION OUTPUT ;
    USE SIGNAL ;
    PORT
      LAYER M3 ;
        RECT  41.724 0 41.742 0.037 ;
    END
  END b[588]
  PIN b[589]
    DIRECTION OUTPUT ;
    USE SIGNAL ;
    PORT
      LAYER M3 ;
        RECT  41.796 0 41.814 0.037 ;
    END
  END b[589]
  PIN b[58]
    DIRECTION OUTPUT ;
    USE SIGNAL ;
    PORT
      LAYER M3 ;
        RECT  19.116 0 19.134 0.037 ;
    END
  END b[58]
  PIN b[590]
    DIRECTION OUTPUT ;
    USE SIGNAL ;
    PORT
      LAYER M3 ;
        RECT  41.868 0 41.886 0.037 ;
    END
  END b[590]
  PIN b[591]
    DIRECTION OUTPUT ;
    USE SIGNAL ;
    PORT
      LAYER M3 ;
        RECT  41.94 0 41.958 0.037 ;
    END
  END b[591]
  PIN b[592]
    DIRECTION OUTPUT ;
    USE SIGNAL ;
    PORT
      LAYER M3 ;
        RECT  42.012 0 42.03 0.037 ;
    END
  END b[592]
  PIN b[593]
    DIRECTION OUTPUT ;
    USE SIGNAL ;
    PORT
      LAYER M3 ;
        RECT  42.084 0 42.102 0.037 ;
    END
  END b[593]
  PIN b[594]
    DIRECTION OUTPUT ;
    USE SIGNAL ;
    PORT
      LAYER M3 ;
        RECT  42.156 0 42.174 0.037 ;
    END
  END b[594]
  PIN b[595]
    DIRECTION OUTPUT ;
    USE SIGNAL ;
    PORT
      LAYER M3 ;
        RECT  42.228 0 42.246 0.037 ;
    END
  END b[595]
  PIN b[596]
    DIRECTION OUTPUT ;
    USE SIGNAL ;
    PORT
      LAYER M3 ;
        RECT  42.3 0 42.318 0.037 ;
    END
  END b[596]
  PIN b[597]
    DIRECTION OUTPUT ;
    USE SIGNAL ;
    PORT
      LAYER M3 ;
        RECT  42.372 0 42.39 0.037 ;
    END
  END b[597]
  PIN b[598]
    DIRECTION OUTPUT ;
    USE SIGNAL ;
    PORT
      LAYER M3 ;
        RECT  42.444 0 42.462 0.037 ;
    END
  END b[598]
  PIN b[599]
    DIRECTION OUTPUT ;
    USE SIGNAL ;
    PORT
      LAYER M3 ;
        RECT  42.516 0 42.534 0.037 ;
    END
  END b[599]
  PIN b[59]
    DIRECTION OUTPUT ;
    USE SIGNAL ;
    PORT
      LAYER M3 ;
        RECT  19.188 0 19.206 0.037 ;
    END
  END b[59]
  PIN b[5]
    DIRECTION OUTPUT ;
    USE SIGNAL ;
    PORT
      LAYER M5 ;
        RECT  45.744 0 45.768 0.084 ;
    END
  END b[5]
  PIN b[60]
    DIRECTION OUTPUT ;
    USE SIGNAL ;
    PORT
      LAYER M3 ;
        RECT  19.26 0 19.278 0.037 ;
    END
  END b[60]
  PIN b[61]
    DIRECTION OUTPUT ;
    USE SIGNAL ;
    PORT
      LAYER M3 ;
        RECT  19.332 0 19.35 0.037 ;
    END
  END b[61]
  PIN b[62]
    DIRECTION OUTPUT ;
    USE SIGNAL ;
    PORT
      LAYER M3 ;
        RECT  19.404 0 19.422 0.037 ;
    END
  END b[62]
  PIN b[63]
    DIRECTION OUTPUT ;
    USE SIGNAL ;
    PORT
      LAYER M3 ;
        RECT  19.476 0 19.494 0.037 ;
    END
  END b[63]
  PIN b[64]
    DIRECTION OUTPUT ;
    USE SIGNAL ;
    PORT
      LAYER M3 ;
        RECT  38.556 0 38.574 0.037 ;
    END
  END b[64]
  PIN b[65]
    DIRECTION OUTPUT ;
    USE SIGNAL ;
    PORT
      LAYER M3 ;
        RECT  38.628 0 38.646 0.037 ;
    END
  END b[65]
  PIN b[66]
    DIRECTION OUTPUT ;
    USE SIGNAL ;
    PORT
      LAYER M3 ;
        RECT  38.7 0 38.718 0.037 ;
    END
  END b[66]
  PIN b[67]
    DIRECTION OUTPUT ;
    USE SIGNAL ;
    PORT
      LAYER M3 ;
        RECT  38.772 0 38.79 0.037 ;
    END
  END b[67]
  PIN b[68]
    DIRECTION OUTPUT ;
    USE SIGNAL ;
    PORT
      LAYER M3 ;
        RECT  38.844 0 38.862 0.037 ;
    END
  END b[68]
  PIN b[69]
    DIRECTION OUTPUT ;
    USE SIGNAL ;
    PORT
      LAYER M3 ;
        RECT  38.916 0 38.934 0.037 ;
    END
  END b[69]
  PIN b[6]
    DIRECTION OUTPUT ;
    USE SIGNAL ;
    PORT
      LAYER M5 ;
        RECT  45.84 0 45.864 0.084 ;
    END
  END b[6]
  PIN b[70]
    DIRECTION OUTPUT ;
    USE SIGNAL ;
    PORT
      LAYER M3 ;
        RECT  38.988 0 39.006 0.037 ;
    END
  END b[70]
  PIN b[71]
    DIRECTION OUTPUT ;
    USE SIGNAL ;
    PORT
      LAYER M3 ;
        RECT  39.06 0 39.078 0.037 ;
    END
  END b[71]
  PIN b[72]
    DIRECTION OUTPUT ;
    USE SIGNAL ;
    PORT
      LAYER M3 ;
        RECT  39.132 0 39.15 0.037 ;
    END
  END b[72]
  PIN b[73]
    DIRECTION OUTPUT ;
    USE SIGNAL ;
    PORT
      LAYER M3 ;
        RECT  39.204 0 39.222 0.037 ;
    END
  END b[73]
  PIN b[74]
    DIRECTION OUTPUT ;
    USE SIGNAL ;
    PORT
      LAYER M3 ;
        RECT  39.276 0 39.294 0.037 ;
    END
  END b[74]
  PIN b[75]
    DIRECTION OUTPUT ;
    USE SIGNAL ;
    PORT
      LAYER M3 ;
        RECT  39.348 0 39.366 0.037 ;
    END
  END b[75]
  PIN b[76]
    DIRECTION OUTPUT ;
    USE SIGNAL ;
    PORT
      LAYER M3 ;
        RECT  39.42 0 39.438 0.037 ;
    END
  END b[76]
  PIN b[77]
    DIRECTION OUTPUT ;
    USE SIGNAL ;
    PORT
      LAYER M3 ;
        RECT  39.492 0 39.51 0.037 ;
    END
  END b[77]
  PIN b[78]
    DIRECTION OUTPUT ;
    USE SIGNAL ;
    PORT
      LAYER M3 ;
        RECT  39.564 0 39.582 0.037 ;
    END
  END b[78]
  PIN b[79]
    DIRECTION OUTPUT ;
    USE SIGNAL ;
    PORT
      LAYER M3 ;
        RECT  39.636 0 39.654 0.037 ;
    END
  END b[79]
  PIN b[7]
    DIRECTION OUTPUT ;
    USE SIGNAL ;
    PORT
      LAYER M5 ;
        RECT  45.936 0 45.96 0.084 ;
    END
  END b[7]
  PIN b[80]
    DIRECTION OUTPUT ;
    USE SIGNAL ;
    PORT
      LAYER M3 ;
        RECT  39.708 0 39.726 0.037 ;
    END
  END b[80]
  PIN b[81]
    DIRECTION OUTPUT ;
    USE SIGNAL ;
    PORT
      LAYER M3 ;
        RECT  39.78 0 39.798 0.037 ;
    END
  END b[81]
  PIN b[82]
    DIRECTION OUTPUT ;
    USE SIGNAL ;
    PORT
      LAYER M3 ;
        RECT  39.852 0 39.87 0.037 ;
    END
  END b[82]
  PIN b[83]
    DIRECTION OUTPUT ;
    USE SIGNAL ;
    PORT
      LAYER M3 ;
        RECT  39.924 0 39.942 0.037 ;
    END
  END b[83]
  PIN b[84]
    DIRECTION OUTPUT ;
    USE SIGNAL ;
    PORT
      LAYER M3 ;
        RECT  39.996 0 40.014 0.037 ;
    END
  END b[84]
  PIN b[85]
    DIRECTION OUTPUT ;
    USE SIGNAL ;
    PORT
      LAYER M3 ;
        RECT  40.068 0 40.086 0.037 ;
    END
  END b[85]
  PIN b[86]
    DIRECTION OUTPUT ;
    USE SIGNAL ;
    PORT
      LAYER M3 ;
        RECT  40.14 0 40.158 0.037 ;
    END
  END b[86]
  PIN b[87]
    DIRECTION OUTPUT ;
    USE SIGNAL ;
    PORT
      LAYER M3 ;
        RECT  40.212 0 40.23 0.037 ;
    END
  END b[87]
  PIN b[88]
    DIRECTION OUTPUT ;
    USE SIGNAL ;
    PORT
      LAYER M3 ;
        RECT  40.284 0 40.302 0.037 ;
    END
  END b[88]
  PIN b[89]
    DIRECTION OUTPUT ;
    USE SIGNAL ;
    PORT
      LAYER M3 ;
        RECT  40.356 0 40.374 0.037 ;
    END
  END b[89]
  PIN b[8]
    DIRECTION OUTPUT ;
    USE SIGNAL ;
    PORT
      LAYER M5 ;
        RECT  46.032 0 46.056 0.084 ;
    END
  END b[8]
  PIN b[90]
    DIRECTION OUTPUT ;
    USE SIGNAL ;
    PORT
      LAYER M3 ;
        RECT  40.428 0 40.446 0.037 ;
    END
  END b[90]
  PIN b[91]
    DIRECTION OUTPUT ;
    USE SIGNAL ;
    PORT
      LAYER M3 ;
        RECT  40.5 0 40.518 0.037 ;
    END
  END b[91]
  PIN b[92]
    DIRECTION OUTPUT ;
    USE SIGNAL ;
    PORT
      LAYER M3 ;
        RECT  40.572 0 40.59 0.037 ;
    END
  END b[92]
  PIN b[93]
    DIRECTION OUTPUT ;
    USE SIGNAL ;
    PORT
      LAYER M3 ;
        RECT  40.644 0 40.662 0.037 ;
    END
  END b[93]
  PIN b[94]
    DIRECTION OUTPUT ;
    USE SIGNAL ;
    PORT
      LAYER M3 ;
        RECT  40.716 0 40.734 0.037 ;
    END
  END b[94]
  PIN b[95]
    DIRECTION OUTPUT ;
    USE SIGNAL ;
    PORT
      LAYER M3 ;
        RECT  40.788 0 40.806 0.037 ;
    END
  END b[95]
  PIN b[96]
    DIRECTION OUTPUT ;
    USE SIGNAL ;
    PORT
      LAYER M3 ;
        RECT  52.956 0 52.974 0.037 ;
    END
  END b[96]
  PIN b[97]
    DIRECTION OUTPUT ;
    USE SIGNAL ;
    PORT
      LAYER M3 ;
        RECT  53.028 0 53.046 0.037 ;
    END
  END b[97]
  PIN b[98]
    DIRECTION OUTPUT ;
    USE SIGNAL ;
    PORT
      LAYER M3 ;
        RECT  53.1 0 53.118 0.037 ;
    END
  END b[98]
  PIN b[99]
    DIRECTION OUTPUT ;
    USE SIGNAL ;
    PORT
      LAYER M3 ;
        RECT  53.172 0 53.19 0.037 ;
    END
  END b[99]
  PIN b[9]
    DIRECTION OUTPUT ;
    USE SIGNAL ;
    PORT
      LAYER M5 ;
        RECT  46.128 0 46.152 0.084 ;
    END
  END b[9]
  PIN ck
    DIRECTION INPUT ;
    USE SIGNAL ;
    PORT
      LAYER M4 ;
        RECT  104.004 32.016 104.088 32.04 ;
    END
  END ck
  PIN ckf
    DIRECTION INPUT ;
    USE SIGNAL ;
    PORT
      LAYER M4 ;
        RECT  104.004 32.112 104.088 32.136 ;
    END
  END ckf
  PIN ea
    DIRECTION INPUT ;
    USE SIGNAL ;
    PORT
      LAYER M3 ;
        RECT  36.684 60.419 36.702 60.456 ;
    END
  END ea
  PIN fault
    DIRECTION OUTPUT ;
    USE SIGNAL ;
    PORT
      LAYER M4 ;
        RECT  104.004 32.208 104.088 32.232 ;
    END
  END fault
  PIN k0
    DIRECTION INPUT ;
    USE SIGNAL ;
    PORT
      LAYER M4 ;
        RECT  104.004 32.304 104.088 32.328 ;
    END
  END k0
  PIN k1
    DIRECTION INPUT ;
    USE SIGNAL ;
    PORT
      LAYER M4 ;
        RECT  104.004 32.4 104.088 32.424 ;
    END
  END k1
  PIN k2
    DIRECTION INPUT ;
    USE SIGNAL ;
    PORT
      LAYER M4 ;
        RECT  104.004 32.496 104.088 32.52 ;
    END
  END k2
  PIN rs
    DIRECTION INPUT ;
    USE SIGNAL ;
    PORT
      LAYER M4 ;
        RECT  104.004 32.592 104.088 32.616 ;
    END
  END rs
  PIN tie_hi
    DIRECTION OUTPUT ;
    USE SIGNAL ;
    PORT
      LAYER M4 ;
        RECT  104.004 32.688 104.088 32.712 ;
    END
  END tie_hi
  PIN tie_lo
    DIRECTION OUTPUT ;
    USE SIGNAL ;
    PORT
      LAYER M4 ;
        RECT  104.004 32.784 104.088 32.808 ;
    END
  END tie_lo
  PIN VDD
    DIRECTION INOUT ;
    USE POWER ;
    PORT
      LAYER M5 ;
        RECT  99.792 2.151 99.912 58.073 ;
        RECT  97.092 2.151 97.212 58.073 ;
        RECT  94.392 2.151 94.512 58.073 ;
        RECT  91.692 2.151 91.812 58.073 ;
        RECT  88.992 2.151 89.112 58.073 ;
        RECT  86.292 2.151 86.412 58.073 ;
        RECT  83.592 2.151 83.712 58.073 ;
        RECT  80.892 2.151 81.012 58.073 ;
        RECT  78.192 2.151 78.312 58.073 ;
        RECT  75.492 2.151 75.612 58.073 ;
        RECT  72.792 2.151 72.912 58.073 ;
        RECT  70.092 2.151 70.212 58.073 ;
        RECT  67.392 2.151 67.512 58.073 ;
        RECT  64.692 2.151 64.812 58.073 ;
        RECT  61.992 2.151 62.112 58.073 ;
        RECT  59.292 2.151 59.412 58.073 ;
        RECT  56.592 2.151 56.712 58.073 ;
        RECT  53.892 2.151 54.012 58.073 ;
        RECT  51.192 2.151 51.312 58.073 ;
        RECT  48.492 2.151 48.612 58.073 ;
        RECT  45.792 2.151 45.912 58.073 ;
        RECT  43.092 2.151 43.212 58.073 ;
        RECT  40.392 2.151 40.512 58.073 ;
        RECT  37.692 2.151 37.812 58.073 ;
        RECT  34.992 2.151 35.112 58.073 ;
        RECT  32.292 2.151 32.412 58.073 ;
        RECT  29.592 2.151 29.712 58.073 ;
        RECT  26.892 2.151 27.012 58.073 ;
        RECT  24.192 2.151 24.312 58.073 ;
        RECT  21.492 2.151 21.612 58.073 ;
        RECT  18.792 2.151 18.912 58.073 ;
        RECT  16.092 2.151 16.212 58.073 ;
        RECT  13.392 2.151 13.512 58.073 ;
        RECT  10.692 2.151 10.812 58.073 ;
        RECT  7.992 2.151 8.112 58.073 ;
        RECT  5.292 2.151 5.412 58.073 ;
        RECT  2.592 2.151 2.712 58.073 ;
    END
  END VDD
  PIN VSS
    DIRECTION INOUT ;
    USE GROUND ;
    PORT
      LAYER M5 ;
        RECT  99.6 2.137 99.72 58.059 ;
        RECT  96.9 2.137 97.02 58.059 ;
        RECT  94.2 2.137 94.32 58.059 ;
        RECT  91.5 2.137 91.62 58.059 ;
        RECT  88.8 2.137 88.92 58.059 ;
        RECT  86.1 2.137 86.22 58.059 ;
        RECT  83.4 2.137 83.52 58.059 ;
        RECT  80.7 2.137 80.82 58.059 ;
        RECT  78 2.137 78.12 58.059 ;
        RECT  75.3 2.137 75.42 58.059 ;
        RECT  72.6 2.137 72.72 58.059 ;
        RECT  69.9 2.137 70.02 58.059 ;
        RECT  67.2 2.137 67.32 58.059 ;
        RECT  64.5 2.137 64.62 58.059 ;
        RECT  61.8 2.137 61.92 58.059 ;
        RECT  59.1 2.137 59.22 58.059 ;
        RECT  56.4 2.137 56.52 58.059 ;
        RECT  53.7 2.137 53.82 58.059 ;
        RECT  51 2.137 51.12 58.059 ;
        RECT  48.3 2.137 48.42 58.059 ;
        RECT  45.6 2.137 45.72 58.059 ;
        RECT  42.9 2.137 43.02 58.059 ;
        RECT  40.2 2.137 40.32 58.059 ;
        RECT  37.5 2.137 37.62 58.059 ;
        RECT  34.8 2.137 34.92 58.059 ;
        RECT  32.1 2.137 32.22 58.059 ;
        RECT  29.4 2.137 29.52 58.059 ;
        RECT  26.7 2.137 26.82 58.059 ;
        RECT  24 2.137 24.12 58.059 ;
        RECT  21.3 2.137 21.42 58.059 ;
        RECT  18.6 2.137 18.72 58.059 ;
        RECT  15.9 2.137 16.02 58.059 ;
        RECT  13.2 2.137 13.32 58.059 ;
        RECT  10.5 2.137 10.62 58.059 ;
        RECT  7.8 2.137 7.92 58.059 ;
        RECT  5.1 2.137 5.22 58.059 ;
        RECT  2.4 2.137 2.52 58.059 ;
    END
  END VSS
  OBS
    LAYER RVTN ;
     RECT  2.16 2.16 101.898 2.295 ;
     RECT  2.16 2.565 101.898 2.835 ;
     RECT  2.16 3.105 101.898 3.375 ;
     RECT  2.16 3.645 101.898 3.915 ;
     RECT  2.16 4.185 101.898 4.455 ;
     RECT  2.16 4.725 101.898 4.995 ;
     RECT  2.16 5.265 101.898 5.535 ;
     RECT  2.16 5.805 101.898 6.075 ;
     RECT  2.16 6.345 101.898 6.615 ;
     RECT  2.16 6.885 101.898 7.155 ;
     RECT  2.16 7.425 101.898 7.695 ;
     RECT  2.16 7.965 101.898 8.235 ;
     RECT  2.16 8.505 101.898 8.775 ;
     RECT  2.16 9.045 101.898 9.315 ;
     RECT  2.16 9.585 101.898 9.855 ;
     RECT  2.16 10.125 101.898 10.395 ;
     RECT  2.16 10.665 101.898 10.935 ;
     RECT  2.16 11.205 101.898 11.475 ;
     RECT  2.16 11.745 101.898 12.015 ;
     RECT  2.16 12.285 101.898 12.555 ;
     RECT  2.16 12.825 101.898 13.095 ;
     RECT  2.16 13.365 101.898 13.635 ;
     RECT  2.16 13.905 101.898 14.175 ;
     RECT  2.16 14.445 101.898 14.715 ;
     RECT  2.16 14.985 101.898 15.255 ;
     RECT  2.16 15.525 101.898 15.795 ;
     RECT  2.16 16.065 101.898 16.335 ;
     RECT  2.16 16.605 101.898 16.875 ;
     RECT  2.16 17.145 101.898 17.415 ;
     RECT  2.16 17.685 101.898 17.955 ;
     RECT  2.16 18.225 101.898 18.495 ;
     RECT  2.16 18.765 101.898 19.035 ;
     RECT  2.16 19.305 101.898 19.575 ;
     RECT  2.16 19.845 101.898 20.115 ;
     RECT  2.16 20.385 101.898 20.655 ;
     RECT  2.16 20.925 101.898 21.195 ;
     RECT  2.16 21.465 101.898 21.735 ;
     RECT  2.16 22.005 101.898 22.275 ;
     RECT  2.16 22.545 101.898 22.815 ;
     RECT  2.16 23.085 101.898 23.355 ;
     RECT  2.16 23.625 101.898 23.895 ;
     RECT  2.16 24.165 101.898 24.435 ;
     RECT  2.16 24.705 101.898 24.975 ;
     RECT  2.16 25.245 101.898 25.515 ;
     RECT  2.16 25.785 101.898 26.055 ;
     RECT  2.16 26.325 101.898 26.595 ;
     RECT  2.16 26.865 101.898 27.135 ;
     RECT  2.16 27.405 101.898 27.675 ;
     RECT  2.16 27.945 101.898 28.215 ;
     RECT  2.16 28.485 101.898 28.755 ;
     RECT  2.16 29.025 101.898 29.295 ;
     RECT  2.16 29.565 101.898 29.835 ;
     RECT  2.16 30.105 101.898 30.375 ;
     RECT  2.16 30.645 101.898 30.915 ;
     RECT  2.16 31.185 101.898 31.455 ;
     RECT  2.16 31.725 101.898 31.995 ;
     RECT  2.16 32.265 101.898 32.535 ;
     RECT  2.16 32.805 101.898 33.075 ;
     RECT  2.16 33.345 101.898 33.615 ;
     RECT  2.16 33.885 101.898 34.155 ;
     RECT  2.16 34.425 101.898 34.695 ;
     RECT  2.16 34.965 101.898 35.235 ;
     RECT  2.16 35.505 101.898 35.775 ;
     RECT  2.16 36.045 101.898 36.315 ;
     RECT  2.16 36.585 101.898 36.855 ;
     RECT  2.16 37.125 101.898 37.395 ;
     RECT  2.16 37.665 101.898 37.935 ;
     RECT  2.16 38.205 101.898 38.475 ;
     RECT  2.16 38.745 101.898 39.015 ;
     RECT  2.16 39.285 101.898 39.555 ;
     RECT  2.16 39.825 101.898 40.095 ;
     RECT  2.16 40.365 101.898 40.635 ;
     RECT  2.16 40.905 101.898 41.175 ;
     RECT  2.16 41.445 101.898 41.715 ;
     RECT  2.16 41.985 101.898 42.255 ;
     RECT  2.16 42.525 101.898 42.795 ;
     RECT  2.16 43.065 101.898 43.335 ;
     RECT  2.16 43.605 101.898 43.875 ;
     RECT  2.16 44.145 101.898 44.415 ;
     RECT  2.16 44.685 101.898 44.955 ;
     RECT  2.16 45.225 101.898 45.495 ;
     RECT  2.16 45.765 101.898 46.035 ;
     RECT  2.16 46.305 101.898 46.575 ;
     RECT  2.16 46.845 101.898 47.115 ;
     RECT  2.16 47.385 101.898 47.655 ;
     RECT  2.16 47.925 101.898 48.195 ;
     RECT  2.16 48.465 101.898 48.735 ;
     RECT  2.16 49.005 101.898 49.275 ;
     RECT  2.16 49.545 101.898 49.815 ;
     RECT  2.16 50.085 101.898 50.355 ;
     RECT  2.16 50.625 101.898 50.895 ;
     RECT  2.16 51.165 101.898 51.435 ;
     RECT  2.16 51.705 101.898 51.975 ;
     RECT  2.16 52.245 101.898 52.515 ;
     RECT  2.16 52.785 101.898 53.055 ;
     RECT  2.16 53.325 101.898 53.595 ;
     RECT  2.16 53.865 101.898 54.135 ;
     RECT  2.16 54.405 101.898 54.675 ;
     RECT  2.16 54.945 101.898 55.215 ;
     RECT  2.16 55.485 101.898 55.755 ;
     RECT  2.16 56.025 101.898 56.295 ;
     RECT  2.16 56.565 101.898 56.835 ;
     RECT  2.16 57.105 101.898 57.375 ;
     RECT  2.16 57.645 101.898 57.915 ;
    LAYER RVTP ;
     RECT  2.16 2.295 101.898 2.565 ;
     RECT  2.16 2.835 101.898 3.105 ;
     RECT  2.16 3.375 101.898 3.645 ;
     RECT  2.16 3.915 101.898 4.185 ;
     RECT  2.16 4.455 101.898 4.725 ;
     RECT  2.16 4.995 101.898 5.265 ;
     RECT  2.16 5.535 101.898 5.805 ;
     RECT  2.16 6.075 101.898 6.345 ;
     RECT  2.16 6.615 101.898 6.885 ;
     RECT  2.16 7.155 101.898 7.425 ;
     RECT  2.16 7.695 101.898 7.965 ;
     RECT  2.16 8.235 101.898 8.505 ;
     RECT  2.16 8.775 101.898 9.045 ;
     RECT  2.16 9.315 101.898 9.585 ;
     RECT  2.16 9.855 101.898 10.125 ;
     RECT  2.16 10.395 101.898 10.665 ;
     RECT  2.16 10.935 101.898 11.205 ;
     RECT  2.16 11.475 101.898 11.745 ;
     RECT  2.16 12.015 101.898 12.285 ;
     RECT  2.16 12.555 101.898 12.825 ;
     RECT  2.16 13.095 101.898 13.365 ;
     RECT  2.16 13.635 101.898 13.905 ;
     RECT  2.16 14.175 101.898 14.445 ;
     RECT  2.16 14.715 101.898 14.985 ;
     RECT  2.16 15.255 101.898 15.525 ;
     RECT  2.16 15.795 101.898 16.065 ;
     RECT  2.16 16.335 101.898 16.605 ;
     RECT  2.16 16.875 101.898 17.145 ;
     RECT  2.16 17.415 101.898 17.685 ;
     RECT  2.16 17.955 101.898 18.225 ;
     RECT  2.16 18.495 101.898 18.765 ;
     RECT  2.16 19.035 101.898 19.305 ;
     RECT  2.16 19.575 101.898 19.845 ;
     RECT  2.16 20.115 101.898 20.385 ;
     RECT  2.16 20.655 101.898 20.925 ;
     RECT  2.16 21.195 101.898 21.465 ;
     RECT  2.16 21.735 101.898 22.005 ;
     RECT  2.16 22.275 101.898 22.545 ;
     RECT  2.16 22.815 101.898 23.085 ;
     RECT  2.16 23.355 101.898 23.625 ;
     RECT  2.16 23.895 101.898 24.165 ;
     RECT  2.16 24.435 101.898 24.705 ;
     RECT  2.16 24.975 101.898 25.245 ;
     RECT  2.16 25.515 101.898 25.785 ;
     RECT  2.16 26.055 101.898 26.325 ;
     RECT  2.16 26.595 101.898 26.865 ;
     RECT  2.16 27.135 101.898 27.405 ;
     RECT  2.16 27.675 101.898 27.945 ;
     RECT  2.16 28.215 101.898 28.485 ;
     RECT  2.16 28.755 101.898 29.025 ;
     RECT  2.16 29.295 101.898 29.565 ;
     RECT  2.16 29.835 101.898 30.105 ;
     RECT  2.16 30.375 101.898 30.645 ;
     RECT  2.16 30.915 101.898 31.185 ;
     RECT  2.16 31.455 101.898 31.725 ;
     RECT  2.16 31.995 101.898 32.265 ;
     RECT  2.16 32.535 101.898 32.805 ;
     RECT  2.16 33.075 101.898 33.345 ;
     RECT  2.16 33.615 101.898 33.885 ;
     RECT  2.16 34.155 101.898 34.425 ;
     RECT  2.16 34.695 101.898 34.965 ;
     RECT  2.16 35.235 101.898 35.505 ;
     RECT  2.16 35.775 101.898 36.045 ;
     RECT  2.16 36.315 101.898 36.585 ;
     RECT  2.16 36.855 101.898 37.125 ;
     RECT  2.16 37.395 101.898 37.665 ;
     RECT  2.16 37.935 101.898 38.205 ;
     RECT  2.16 38.475 101.898 38.745 ;
     RECT  2.16 39.015 101.898 39.285 ;
     RECT  2.16 39.555 101.898 39.825 ;
     RECT  2.16 40.095 101.898 40.365 ;
     RECT  2.16 40.635 101.898 40.905 ;
     RECT  2.16 41.175 101.898 41.445 ;
     RECT  2.16 41.715 101.898 41.985 ;
     RECT  2.16 42.255 101.898 42.525 ;
     RECT  2.16 42.795 101.898 43.065 ;
     RECT  2.16 43.335 101.898 43.605 ;
     RECT  2.16 43.875 101.898 44.145 ;
     RECT  2.16 44.415 101.898 44.685 ;
     RECT  2.16 44.955 101.898 45.225 ;
     RECT  2.16 45.495 101.898 45.765 ;
     RECT  2.16 46.035 101.898 46.305 ;
     RECT  2.16 46.575 101.898 46.845 ;
     RECT  2.16 47.115 101.898 47.385 ;
     RECT  2.16 47.655 101.898 47.925 ;
     RECT  2.16 48.195 101.898 48.465 ;
     RECT  2.16 48.735 101.898 49.005 ;
     RECT  2.16 49.275 101.898 49.545 ;
     RECT  2.16 49.815 101.898 50.085 ;
     RECT  2.16 50.355 101.898 50.625 ;
     RECT  2.16 50.895 101.898 51.165 ;
     RECT  2.16 51.435 101.898 51.705 ;
     RECT  2.16 51.975 101.898 52.245 ;
     RECT  2.16 52.515 101.898 52.785 ;
     RECT  2.16 53.055 101.898 53.325 ;
     RECT  2.16 53.595 101.898 53.865 ;
     RECT  2.16 54.135 101.898 54.405 ;
     RECT  2.16 54.675 101.898 54.945 ;
     RECT  2.16 55.215 101.898 55.485 ;
     RECT  2.16 55.755 101.898 56.025 ;
     RECT  2.16 56.295 101.898 56.565 ;
     RECT  2.16 56.835 101.898 57.105 ;
     RECT  2.16 57.375 101.898 57.645 ;
     RECT  2.16 57.915 101.898 58.05 ;
    LAYER M1 ;
     RECT  2.16 2.151 101.898 58.059 ;
    LAYER M2 ;
     RECT  3.307 59.544 9.427 59.562 ;
     RECT  2.16 2.151 9.535 58.059 ;
     RECT  9.535 2.151 9.959 58.176 ;
     RECT  9.427 59.274 10.075 59.562 ;
     RECT  9.931 60.39 10.075 60.408 ;
     RECT  10.075 59.274 10.283 60.408 ;
     RECT  10.283 59.544 10.319 60.408 ;
     RECT  10.319 60.156 10.787 60.408 ;
     RECT  9.959 2.151 10.939 58.059 ;
     RECT  10.939 1.926 11.623 58.059 ;
     RECT  11.623 1.926 11.947 58.104 ;
     RECT  11.407 0.18 12.055 0.198 ;
     RECT  11.947 1.422 12.163 58.104 ;
     RECT  12.055 0.18 12.271 0.234 ;
     RECT  10.787 60.201 13.171 60.408 ;
     RECT  13.171 60.201 13.199 60.444 ;
     RECT  12.271 0.18 13.567 0.468 ;
     RECT  12.163 1.422 13.603 58.14 ;
     RECT  13.567 0.144 13.819 0.468 ;
     RECT  13.603 1.296 13.819 58.14 ;
     RECT  13.199 60.39 14.027 60.444 ;
     RECT  13.819 0.144 15.259 58.14 ;
     RECT  15.259 0.036 17.339 58.14 ;
     RECT  14.027 60.426 18.031 60.444 ;
     RECT  17.339 0.036 18.059 58.104 ;
     RECT  18.059 1.422 18.131 58.104 ;
     RECT  18.059 0.036 18.779 0.549 ;
     RECT  18.031 60.39 18.823 60.444 ;
     RECT  18.823 59.976 18.851 60.444 ;
     RECT  18.779 0.036 18.959 0.396 ;
     RECT  18.131 1.8 18.995 58.104 ;
     RECT  18.959 0.036 19.211 0.234 ;
     RECT  19.211 0.036 19.247 0.054 ;
     RECT  18.995 1.836 19.319 58.104 ;
     RECT  19.319 1.926 19.895 58.104 ;
     RECT  19.895 2.151 20.119 58.104 ;
     RECT  18.851 59.976 20.767 60.408 ;
     RECT  20.119 2.151 20.803 58.176 ;
     RECT  20.767 59.931 20.947 60.408 ;
     RECT  20.947 59.886 21.235 60.408 ;
     RECT  20.803 2.07 21.271 58.176 ;
     RECT  21.271 2.07 21.695 58.716 ;
     RECT  21.703 0.216 21.811 0.234 ;
     RECT  21.695 2.07 21.919 58.104 ;
     RECT  21.811 0.144 21.955 0.234 ;
     RECT  21.955 0.072 22.091 0.234 ;
     RECT  22.091 0.072 22.279 0.162 ;
     RECT  22.243 1.152 22.379 1.17 ;
     RECT  21.235 59.544 22.567 60.408 ;
     RECT  22.387 1.224 22.595 1.242 ;
     RECT  22.567 59.544 22.595 60.444 ;
     RECT  21.919 2.034 22.667 58.104 ;
     RECT  22.279 0.036 22.819 0.162 ;
     RECT  22.819 0.036 22.891 0.234 ;
     RECT  22.667 2.07 23.171 58.104 ;
     RECT  23.251 1.152 23.575 1.17 ;
     RECT  22.891 0.036 23.639 0.279 ;
     RECT  23.575 1.152 23.683 1.242 ;
     RECT  23.171 2.07 23.683 58.059 ;
     RECT  23.639 0.072 24.007 0.279 ;
     RECT  24.007 0.072 24.079 0.324 ;
     RECT  24.079 0.072 24.323 0.36 ;
     RECT  24.323 0.108 24.395 0.36 ;
     RECT  23.683 1.152 24.431 58.059 ;
     RECT  24.395 0.216 24.467 0.36 ;
     RECT  24.467 0.306 24.503 0.36 ;
     RECT  24.503 0.306 25.447 0.324 ;
     RECT  25.447 0.036 25.591 0.324 ;
     RECT  24.431 1.422 25.591 58.059 ;
     RECT  22.595 60.426 25.943 60.444 ;
     RECT  25.591 0.036 26.519 58.059 ;
     RECT  26.519 0.846 26.959 58.059 ;
     RECT  22.595 59.544 27.031 59.562 ;
     RECT  27.031 59.544 27.103 60.102 ;
     RECT  26.959 0.846 28.247 58.716 ;
     RECT  26.519 0.036 28.607 0.054 ;
     RECT  27.103 59.544 29.083 60.372 ;
     RECT  28.247 0.846 29.831 58.446 ;
     RECT  29.831 2.106 29.975 58.446 ;
     RECT  29.831 0.846 30.127 0.864 ;
     RECT  30.127 0.108 30.487 0.864 ;
     RECT  29.975 2.151 30.883 58.446 ;
     RECT  30.487 0.036 31.091 0.864 ;
     RECT  30.883 2.106 31.235 58.446 ;
     RECT  31.235 2.106 31.963 58.14 ;
     RECT  31.963 2.07 32.171 58.14 ;
     RECT  32.171 2.07 33.431 58.104 ;
     RECT  33.431 2.106 33.647 58.104 ;
     RECT  31.091 0.036 34.223 0.198 ;
     RECT  34.195 1.152 34.295 1.17 ;
     RECT  34.223 0.036 34.403 0.126 ;
     RECT  34.403 0.108 34.475 0.126 ;
     RECT  33.647 2.151 34.627 58.104 ;
     RECT  34.627 2.151 34.663 58.599 ;
     RECT  34.663 2.151 34.951 58.644 ;
     RECT  34.951 2.151 35.699 58.716 ;
     RECT  35.699 2.151 36.347 58.104 ;
     RECT  29.083 59.544 36.527 60.444 ;
     RECT  36.347 2.151 37.327 58.059 ;
     RECT  37.651 0.261 38.155 0.279 ;
     RECT  37.327 1.8 38.767 58.059 ;
     RECT  38.767 1.224 38.839 58.059 ;
     RECT  36.527 59.58 38.939 60.444 ;
     RECT  38.155 0.036 39.595 0.279 ;
     RECT  38.839 1.152 39.595 58.059 ;
     RECT  39.595 0.036 39.811 58.059 ;
     RECT  39.811 0.036 39.947 58.518 ;
     RECT  38.939 59.58 40.163 60.408 ;
     RECT  40.163 60.084 41.531 60.408 ;
     RECT  41.531 60.084 41.639 60.219 ;
     RECT  39.947 0.036 42.035 58.059 ;
     RECT  41.639 60.201 42.323 60.219 ;
     RECT  42.035 0.846 43.943 58.059 ;
     RECT  42.035 0.036 44.195 0.054 ;
     RECT  43.943 1.152 44.267 58.059 ;
     RECT  44.267 1.836 44.879 58.059 ;
     RECT  44.879 2.151 45.751 58.059 ;
     RECT  45.751 2.106 45.823 58.059 ;
     RECT  45.823 2.07 46.031 58.059 ;
     RECT  45.283 60.282 46.363 60.3 ;
     RECT  46.363 60.282 46.399 60.408 ;
     RECT  46.031 2.106 46.795 58.059 ;
     RECT  46.399 60.201 46.831 60.408 ;
     RECT  46.831 60.156 47.003 60.408 ;
     RECT  46.795 1.881 47.111 58.059 ;
     RECT  47.003 60.201 47.687 60.408 ;
     RECT  47.687 60.201 47.723 60.336 ;
     RECT  47.111 2.034 47.911 58.059 ;
     RECT  47.723 60.201 47.983 60.219 ;
     RECT  47.983 59.58 48.487 60.219 ;
     RECT  48.487 59.58 48.631 60.408 ;
     RECT  48.631 59.544 51.043 60.408 ;
     RECT  47.911 1.962 51.907 58.059 ;
     RECT  51.043 59.544 52.187 60.444 ;
     RECT  51.907 1.881 52.447 58.059 ;
     RECT  52.187 59.544 52.943 59.598 ;
     RECT  52.447 1.836 52.951 58.059 ;
     RECT  52.951 1.728 53.167 58.059 ;
     RECT  53.167 1.224 53.483 58.059 ;
     RECT  53.599 0.108 53.671 0.126 ;
     RECT  53.671 0.036 53.815 0.126 ;
     RECT  53.815 0.036 54.059 0.198 ;
     RECT  54.059 0.036 54.131 0.126 ;
     RECT  53.483 1.836 54.319 58.059 ;
     RECT  54.895 0.036 55.687 0.234 ;
     RECT  54.319 1.152 55.687 58.059 ;
     RECT  55.687 0.036 55.823 58.059 ;
     RECT  55.823 1.881 56.695 58.059 ;
     RECT  55.823 0.036 56.803 0.666 ;
     RECT  56.695 1.836 56.803 58.059 ;
     RECT  56.803 0.036 57.011 58.059 ;
     RECT  57.011 1.836 57.911 58.059 ;
     RECT  52.943 59.544 57.911 59.562 ;
     RECT  57.011 0.036 58.127 0.666 ;
     RECT  52.187 60.426 58.415 60.444 ;
     RECT  57.911 1.881 59.279 58.059 ;
     RECT  59.279 1.926 59.567 58.059 ;
     RECT  58.127 0.036 59.783 0.054 ;
     RECT  59.567 2.034 62.311 58.059 ;
     RECT  62.635 60.39 62.851 60.408 ;
     RECT  62.311 1.836 62.923 58.059 ;
     RECT  62.923 1.728 63.283 58.059 ;
     RECT  62.851 0.036 63.463 0.054 ;
     RECT  62.419 59.544 63.607 59.562 ;
     RECT  62.851 60.39 63.607 60.444 ;
     RECT  63.463 0.036 63.859 0.126 ;
     RECT  63.859 0.036 64.399 0.198 ;
     RECT  64.399 0.036 64.435 0.36 ;
     RECT  63.283 1.152 64.435 58.059 ;
     RECT  64.435 0.036 64.715 58.059 ;
     RECT  64.715 1.152 64.823 58.059 ;
     RECT  64.715 0.036 64.931 0.279 ;
     RECT  64.931 0.036 64.967 0.054 ;
     RECT  64.823 1.962 65.111 58.059 ;
     RECT  63.607 59.544 65.119 60.444 ;
     RECT  64.823 1.152 65.435 1.17 ;
     RECT  65.111 2.07 66.487 58.059 ;
     RECT  65.119 59.391 67.307 60.444 ;
     RECT  66.559 1.152 67.351 1.17 ;
     RECT  66.487 1.926 67.351 58.059 ;
     RECT  67.351 1.152 67.855 58.716 ;
     RECT  67.855 0.486 67.955 58.716 ;
     RECT  67.955 1.764 68.027 58.716 ;
     RECT  67.955 0.486 68.179 0.504 ;
     RECT  67.307 60.084 68.215 60.444 ;
     RECT  68.179 0.414 68.899 0.504 ;
     RECT  68.027 1.764 69.079 58.14 ;
     RECT  69.079 1.764 69.115 58.176 ;
     RECT  68.215 59.814 69.431 60.444 ;
     RECT  69.431 59.814 69.503 60.408 ;
     RECT  68.899 0.414 69.647 0.549 ;
     RECT  69.503 59.814 70.051 60.336 ;
     RECT  69.647 0.414 70.151 0.504 ;
     RECT  69.115 1.764 70.375 58.248 ;
     RECT  70.051 59.742 70.411 60.336 ;
     RECT  70.411 59.742 70.519 60.408 ;
     RECT  70.375 1.764 71.375 58.446 ;
     RECT  71.375 1.926 71.735 58.446 ;
     RECT  71.735 2.106 71.879 58.446 ;
     RECT  71.879 2.106 72.643 58.104 ;
     RECT  72.643 2.106 73.283 58.716 ;
     RECT  73.283 2.106 74.255 58.059 ;
     RECT  70.519 59.544 74.435 60.408 ;
     RECT  74.435 59.661 74.651 60.408 ;
     RECT  74.651 60.156 74.687 60.408 ;
     RECT  74.911 1.26 74.983 1.278 ;
     RECT  74.983 1.152 75.199 1.278 ;
     RECT  75.199 1.152 75.379 1.359 ;
     RECT  74.767 0.036 75.415 0.054 ;
     RECT  74.687 60.156 75.415 60.336 ;
     RECT  75.379 1.152 75.487 1.404 ;
     RECT  74.255 2.151 75.487 58.059 ;
     RECT  75.487 1.152 75.559 58.059 ;
     RECT  75.415 60.156 75.631 60.408 ;
     RECT  75.415 0.036 75.739 0.126 ;
     RECT  75.559 1.152 75.739 58.716 ;
     RECT  75.739 0.036 76.091 58.716 ;
     RECT  75.631 59.976 76.495 60.408 ;
     RECT  76.783 58.968 77.143 58.986 ;
     RECT  76.495 59.931 77.143 60.408 ;
     RECT  77.143 58.968 77.927 60.408 ;
     RECT  76.091 0.036 78.079 58.059 ;
     RECT  77.927 58.968 78.079 60.372 ;
     RECT  78.079 0.036 78.763 60.372 ;
     RECT  78.763 0.036 79.555 60.408 ;
     RECT  79.555 0.036 79.763 60.444 ;
     RECT  79.763 1.881 79.943 60.444 ;
     RECT  79.943 1.926 79.979 60.444 ;
     RECT  79.763 0.036 80.087 0.864 ;
     RECT  80.087 0.036 80.195 0.09 ;
     RECT  80.087 0.846 80.231 0.864 ;
     RECT  80.195 0.036 80.591 0.054 ;
     RECT  79.979 2.034 81.247 60.444 ;
     RECT  81.715 0.036 81.931 0.054 ;
     RECT  81.931 0.036 81.967 0.126 ;
     RECT  81.967 0.036 82.067 0.198 ;
     RECT  81.535 1.152 82.291 1.17 ;
     RECT  81.247 1.962 82.291 60.444 ;
     RECT  82.291 1.152 82.571 60.444 ;
     RECT  82.067 0.036 82.975 0.126 ;
     RECT  82.571 1.728 83.479 60.444 ;
     RECT  83.479 1.53 83.659 60.444 ;
     RECT  82.975 0.036 83.695 0.198 ;
     RECT  83.659 1.26 83.875 60.444 ;
     RECT  83.695 0.036 83.947 0.279 ;
     RECT  83.875 1.224 83.947 60.444 ;
     RECT  83.947 0.036 84.775 0.324 ;
     RECT  83.947 1.152 84.775 60.444 ;
     RECT  84.775 0.036 86.279 60.444 ;
     RECT  86.279 0.108 86.675 60.444 ;
     RECT  86.675 0.18 87.143 60.444 ;
     RECT  87.143 0.306 87.539 60.444 ;
     RECT  87.539 0.846 87.683 60.444 ;
     RECT  88.879 0.036 92.039 0.054 ;
     RECT  87.683 0.846 92.795 59.634 ;
     RECT  87.683 60.39 93.335 60.444 ;
     RECT  92.795 0.846 94.171 59.562 ;
     RECT  94.171 0.108 94.279 59.562 ;
     RECT  94.279 0.036 95.423 59.562 ;
     RECT  95.423 0.882 95.495 59.562 ;
     RECT  95.423 0.036 95.891 0.126 ;
     RECT  95.891 0.036 95.999 0.054 ;
     RECT  93.335 60.39 96.035 60.408 ;
     RECT  95.495 59.544 96.611 59.562 ;
     RECT  95.495 0.882 96.899 58.446 ;
     RECT  96.899 0.882 98.663 58.059 ;
     RECT  98.663 0.882 98.843 0.9 ;
     RECT  98.663 1.881 99.167 58.059 ;
     RECT  99.167 2.151 101.898 58.059 ;
     RECT  101.898 32.274 102.047 32.904 ;
     RECT  102.047 32.31 103.199 32.904 ;
     RECT  103.199 32.31 103.235 32.49 ;
     RECT  103.235 32.472 103.271 32.49 ;
    LAYER M3 ;
     RECT  21.852 0.012 26.406 0.031 ;
     RECT  38.556 0.012 42.534 0.031 ;
     RECT  74.844 0.012 77.094 0.031 ;
     RECT  81.756 0.012 86.31 0.031 ;
     RECT  59.76 0.031 59.778 0.043 ;
     RECT  80.568 0.031 80.586 0.043 ;
     RECT  80.28 0.043 80.586 0.067 ;
     RECT  30.492 0.031 30.51 0.091 ;
     RECT  74.772 0.031 77.094 0.091 ;
     RECT  80.172 0.067 80.586 0.091 ;
     RECT  88.884 0.031 88.902 0.091 ;
     RECT  92.016 0.031 92.034 0.091 ;
     RECT  34.38 0.031 34.398 0.103 ;
     RECT  81.72 0.031 86.31 0.103 ;
     RECT  87.228 0.091 87.246 0.103 ;
     RECT  14.04 0.091 14.058 0.139 ;
     RECT  21.852 0.031 26.514 0.139 ;
     RECT  34.38 0.103 34.47 0.139 ;
     RECT  73.332 0.091 73.35 0.139 ;
     RECT  81.72 0.103 87.246 0.139 ;
     RECT  88.452 0.091 88.902 0.139 ;
     RECT  98.568 0.091 98.586 0.139 ;
     RECT  81.72 0.139 88.902 0.173 ;
     RECT  93.852 0.012 96.102 0.187 ;
     RECT  11.412 0.175 11.43 0.211 ;
     RECT  21.816 0.139 26.514 0.211 ;
     RECT  80.028 0.091 80.586 0.211 ;
     RECT  29.34 0.091 31.266 0.221 ;
     RECT  13.572 0.139 14.058 0.256 ;
     RECT  14.94 0.012 19.494 0.256 ;
     RECT  38.16 0.031 42.534 0.256 ;
     RECT  81.72 0.173 88.47 0.269 ;
     RECT  21.708 0.211 26.514 0.329 ;
     RECT  30.888 0.221 31.086 0.365 ;
     RECT  13.572 0.256 19.494 0.373 ;
     RECT  70.092 0.091 70.11 0.379 ;
     RECT  67.644 0.091 67.662 0.409 ;
     RECT  11.412 0.211 12.078 0.445 ;
     RECT  68.976 0.043 68.994 0.52 ;
     RECT  70.092 0.379 70.146 0.52 ;
     RECT  67.644 0.409 68.202 0.523 ;
     RECT  68.976 0.52 70.146 0.523 ;
     RECT  71.712 0.235 71.73 0.523 ;
     RECT  52.956 0.012 57.51 0.571 ;
     RECT  73.332 0.139 73.458 0.571 ;
     RECT  74.268 0.091 77.094 0.571 ;
     RECT  73.332 0.571 77.346 0.619 ;
     RECT  78.372 0.103 78.462 0.619 ;
     RECT  79.416 0.211 80.586 0.619 ;
     RECT  52.74 0.571 57.51 0.643 ;
     RECT  11.412 0.445 12.294 0.811 ;
     RECT  13.176 0.373 19.494 0.811 ;
     RECT  44.172 0.031 44.19 0.841 ;
     RECT  62.748 0.012 64.998 0.859 ;
     RECT  92.016 0.091 92.214 0.859 ;
     RECT  28.584 0.031 28.602 0.877 ;
     RECT  29.34 0.221 29.898 0.877 ;
     RECT  91.836 0.859 92.214 0.877 ;
     RECT  97.848 0.139 98.586 0.877 ;
     RECT  62.676 0.859 64.998 0.907 ;
     RECT  91.152 0.877 92.214 0.913 ;
     RECT  91.044 0.913 92.214 0.949 ;
     RECT  66.672 0.043 66.69 0.955 ;
     RECT  67.644 0.523 70.29 0.955 ;
     RECT  91.008 0.949 92.214 0.985 ;
     RECT  91.008 0.985 92.394 1.066 ;
     RECT  93.24 0.187 96.102 1.066 ;
     RECT  31.068 0.365 31.086 1.099 ;
     RECT  81.72 0.269 88.398 1.139 ;
     RECT  27.432 0.043 27.45 1.147 ;
     RECT  28.584 0.877 29.898 1.147 ;
     RECT  43.92 0.841 44.19 1.147 ;
     RECT  62.388 0.907 64.998 1.147 ;
     RECT  66.672 0.955 70.29 1.147 ;
     RECT  71.712 0.523 72.378 1.147 ;
     RECT  81.72 1.139 88.218 1.147 ;
     RECT  90.072 0.571 90.09 1.147 ;
     RECT  90.936 1.066 96.102 1.147 ;
     RECT  66.564 1.147 70.29 1.243 ;
     RECT  37.656 0.256 42.534 1.255 ;
     RECT  37.656 1.255 42.57 1.336 ;
     RECT  66.564 1.243 70.722 1.435 ;
     RECT  45.468 0.091 45.486 1.627 ;
     RECT  27.432 1.147 29.898 1.723 ;
     RECT  31.068 1.099 31.518 1.723 ;
     RECT  32.256 0.091 32.274 1.723 ;
     RECT  45.432 1.627 45.486 1.723 ;
     RECT  71.532 1.147 72.594 1.723 ;
     RECT  73.332 0.619 80.586 1.723 ;
     RECT  66.42 1.435 70.722 1.759 ;
     RECT  71.532 1.723 80.586 1.759 ;
     RECT  97.848 0.877 98.838 1.759 ;
     RECT  45.396 1.723 47.61 1.771 ;
     RECT  37.656 1.336 42.642 1.795 ;
     RECT  90.072 1.147 96.174 1.795 ;
     RECT  90.072 1.795 96.786 1.819 ;
     RECT  43.38 1.147 44.262 1.831 ;
     RECT  45.396 1.771 47.898 1.831 ;
     RECT  52.74 0.643 58.122 1.831 ;
     RECT  61.632 0.811 61.65 1.831 ;
     RECT  62.388 1.147 65.43 1.831 ;
     RECT  90.072 1.819 96.894 1.831 ;
     RECT  97.632 1.759 98.838 1.831 ;
     RECT  27.432 1.723 30.186 1.867 ;
     RECT  31.068 1.723 32.274 1.867 ;
     RECT  48.996 1.819 49.014 1.867 ;
     RECT  52.452 1.831 58.122 1.876 ;
     RECT  59.76 0.043 60.21 1.876 ;
     RECT  89.532 1.831 98.838 1.876 ;
     RECT  11.412 0.811 19.494 1.921 ;
     RECT  89.532 1.876 99.162 1.921 ;
     RECT  43.38 1.831 47.898 1.957 ;
     RECT  48.636 1.867 49.014 1.957 ;
     RECT  66.42 1.759 80.586 1.957 ;
     RECT  81.54 1.147 88.218 1.957 ;
     RECT  37.332 1.795 42.642 1.993 ;
     RECT  43.38 1.957 49.014 1.993 ;
     RECT  89.46 1.921 99.162 1.993 ;
     RECT  37.332 1.993 49.014 2.029 ;
     RECT  66.42 1.957 88.218 2.029 ;
     RECT  88.956 1.993 99.162 2.029 ;
     RECT  27.432 1.867 32.274 2.059 ;
     RECT  33.012 1.915 33.03 2.059 ;
     RECT  27.432 2.059 33.03 2.065 ;
     RECT  33.912 0.139 34.47 2.065 ;
     RECT  59.256 1.876 60.21 2.065 ;
     RECT  61.632 1.831 65.43 2.065 ;
     RECT  21.708 0.329 26.442 2.101 ;
     RECT  27.432 2.065 34.47 2.101 ;
     RECT  10.944 1.921 19.89 2.143 ;
     RECT  20.808 2.065 20.826 2.143 ;
     RECT  21.708 2.101 34.47 2.143 ;
     RECT  66.42 2.029 99.162 2.143 ;
     RECT  50.148 1.723 50.166 2.191 ;
     RECT  51.015 2.143 51.105 2.191 ;
     RECT  51.912 1.876 58.122 2.191 ;
     RECT  58.968 2.065 60.21 2.191 ;
     RECT  61.632 2.065 65.574 2.191 ;
     RECT  66.42 2.143 99.705 2.219 ;
     RECT  50.148 2.191 51.105 2.227 ;
     RECT  10.515 2.143 19.89 2.263 ;
     RECT  20.808 2.143 34.905 2.263 ;
     RECT  61.632 2.191 65.682 2.263 ;
     RECT  5.115 2.143 5.205 2.299 ;
     RECT  7.815 2.143 7.905 2.299 ;
     RECT  37.332 2.029 49.302 2.299 ;
     RECT  50.076 2.227 51.105 2.299 ;
     RECT  7.308 2.299 7.905 2.335 ;
     RECT  37.332 2.299 51.105 2.335 ;
     RECT  6.66 2.335 7.974 2.371 ;
     RECT  61.416 2.263 65.682 2.371 ;
     RECT  66.42 2.219 98.838 2.371 ;
     RECT  2.415 2.143 2.505 2.413 ;
     RECT  10.515 2.263 34.905 2.413 ;
     RECT  37.152 2.335 51.105 2.413 ;
     RECT  51.912 2.191 60.21 2.413 ;
     RECT  99.615 2.219 99.705 2.413 ;
     RECT  4.5 2.299 5.742 2.461 ;
     RECT  10.515 2.413 35.097 2.533 ;
     RECT  36.072 2.299 36.09 2.533 ;
     RECT  10.515 2.533 36.09 2.569 ;
     RECT  10.515 2.569 36.198 2.587 ;
     RECT  37.152 2.413 60.21 2.605 ;
     RECT  60.948 2.371 98.838 2.605 ;
     RECT  6.66 2.371 8.406 2.641 ;
     RECT  37.152 2.605 98.838 2.767 ;
     RECT  6.48 2.641 9.126 2.795 ;
     RECT  10.08 2.587 36.198 2.803 ;
     RECT  36.936 2.767 98.838 2.803 ;
     RECT  4.248 2.461 5.742 2.827 ;
     RECT  6.912 2.795 9.126 2.839 ;
     RECT  10.08 2.803 98.838 2.839 ;
     RECT  4.104 2.827 5.742 2.875 ;
     RECT  2.415 2.413 2.697 3.181 ;
     RECT  6.912 2.839 98.838 3.299 ;
     RECT  2.415 3.181 3.366 3.343 ;
     RECT  4.104 2.875 6.138 3.343 ;
     RECT  6.912 3.299 98.73 3.569 ;
     RECT  2.415 3.343 6.138 3.685 ;
     RECT  6.912 3.569 98.658 3.685 ;
     RECT  2.376 3.685 98.658 3.839 ;
     RECT  2.376 3.839 98.586 4.379 ;
     RECT  2.415 4.379 98.586 5.071 ;
     RECT  99.615 2.413 99.897 5.233 ;
     RECT  2.415 5.071 98.73 5.539 ;
     RECT  99.615 5.233 100.422 5.539 ;
     RECT  2.415 5.539 100.422 5.737 ;
     RECT  2.415 5.737 100.818 5.881 ;
     RECT  2.415 5.881 101.178 6.305 ;
     RECT  2.415 6.305 101.034 7.051 ;
     RECT  2.415 7.051 101.142 7.349 ;
     RECT  2.415 7.349 101.034 7.385 ;
     RECT  2.415 7.385 100.926 8.195 ;
     RECT  6.84 8.195 100.926 8.311 ;
     RECT  2.415 8.195 5.958 8.401 ;
     RECT  2.376 8.401 5.958 8.477 ;
     RECT  2.415 8.477 5.958 8.941 ;
     RECT  6.84 8.311 101.142 8.941 ;
     RECT  2.415 8.941 101.142 9.275 ;
     RECT  2.415 9.275 100.53 9.923 ;
     RECT  2.415 9.923 99.897 11.209 ;
     RECT  2.415 11.209 99.918 11.245 ;
     RECT  2.415 11.245 100.242 11.479 ;
     RECT  2.415 11.479 100.458 12.091 ;
     RECT  2.415 12.091 101.034 12.785 ;
     RECT  2.415 12.785 100.35 12.929 ;
     RECT  2.415 12.929 99.897 18.841 ;
     RECT  100.8 18.967 100.818 19.037 ;
     RECT  2.415 18.841 99.99 19.103 ;
     RECT  100.728 19.111 100.746 19.265 ;
     RECT  2.415 19.103 99.897 23.323 ;
     RECT  101.088 23.053 101.106 23.549 ;
     RECT  2.415 23.323 100.17 23.593 ;
     RECT  100.908 23.557 101.07 23.593 ;
     RECT  2.415 23.593 101.07 23.999 ;
     RECT  2.415 23.999 100.998 24.161 ;
     RECT  2.415 24.161 100.89 25.249 ;
     RECT  2.415 25.249 100.962 25.717 ;
     RECT  2.415 25.717 100.998 26.833 ;
     RECT  2.415 26.833 101.322 27.101 ;
     RECT  8.892 27.101 101.322 27.139 ;
     RECT  7.776 27.101 8.154 27.203 ;
     RECT  8.892 27.139 101.394 27.239 ;
     RECT  8.892 27.239 101.322 27.329 ;
     RECT  8.964 27.329 101.322 27.869 ;
     RECT  7.776 27.203 8.097 28.255 ;
     RECT  8.964 27.869 101.214 28.255 ;
     RECT  7.776 28.255 101.214 28.589 ;
     RECT  101.052 28.589 101.214 28.679 ;
     RECT  101.052 28.679 101.07 28.715 ;
     RECT  7.776 28.589 100.278 28.949 ;
     RECT  8.82 28.949 100.278 29.605 ;
     RECT  8.82 29.605 100.566 30.955 ;
     RECT  101.736 30.991 101.754 31.181 ;
     RECT  8.82 30.955 100.818 31.325 ;
     RECT  8.82 31.325 100.71 31.919 ;
     RECT  103.176 32.299 103.194 32.305 ;
     RECT  102.024 32.203 102.042 32.341 ;
     RECT  103.176 32.305 103.23 32.467 ;
     RECT  8.82 31.919 100.674 32.701 ;
     RECT  101.664 32.341 102.042 32.701 ;
     RECT  103.176 32.467 103.266 32.717 ;
     RECT  8.82 32.701 102.042 32.773 ;
     RECT  103.176 32.717 103.194 32.773 ;
     RECT  8.82 32.773 103.194 32.813 ;
     RECT  8.82 32.813 102.042 32.873 ;
     RECT  103.176 32.813 103.194 32.909 ;
     RECT  8.82 32.873 101.682 33.961 ;
     RECT  8.82 33.961 101.754 34.115 ;
     RECT  8.82 34.115 101.394 34.151 ;
     RECT  101.376 34.151 101.394 34.349 ;
     RECT  8.82 34.151 100.566 35.239 ;
     RECT  8.82 35.239 100.89 35.851 ;
     RECT  8.82 35.851 101.43 35.969 ;
     RECT  9.396 35.969 101.43 36.113 ;
     RECT  9.396 36.113 100.89 36.239 ;
     RECT  100.872 36.239 100.89 36.383 ;
     RECT  9.396 36.239 100.026 37.129 ;
     RECT  9.396 37.129 100.242 37.319 ;
     RECT  2.415 27.101 7.038 37.589 ;
     RECT  9.396 37.319 99.897 37.967 ;
     RECT  9.396 37.967 97.47 38.003 ;
     RECT  98.244 37.967 98.298 38.003 ;
     RECT  9.396 38.003 97.197 41.309 ;
     RECT  24.015 41.309 97.197 41.711 ;
     RECT  25.92 41.711 97.197 41.945 ;
     RECT  9.396 41.309 23.202 42.179 ;
     RECT  2.415 37.589 6.93 43.529 ;
     RECT  26.715 41.945 97.197 44.723 ;
     RECT  26.715 44.723 43.218 45.535 ;
     RECT  43.992 44.723 97.197 45.535 ;
     RECT  26.715 45.535 97.197 45.629 ;
     RECT  2.415 43.529 6.534 45.689 ;
     RECT  5.115 45.689 6.534 45.697 ;
     RECT  5.115 45.697 6.858 45.797 ;
     RECT  26.715 45.629 43.197 46.579 ;
     RECT  43.92 45.629 97.197 46.579 ;
     RECT  26.715 46.579 97.197 47.615 ;
     RECT  26.715 47.615 90.774 49.775 ;
     RECT  42.915 49.775 90.774 50.153 ;
     RECT  44.28 50.153 90.774 50.315 ;
     RECT  44.496 50.315 90.774 50.891 ;
     RECT  45.288 50.891 90.774 51.089 ;
     RECT  45.288 51.089 54.522 51.359 ;
     RECT  45.288 51.359 54.414 52.141 ;
     RECT  55.368 51.089 90.774 52.141 ;
     RECT  45.288 52.141 90.774 52.583 ;
     RECT  26.715 49.775 41.886 52.825 ;
     RECT  42.915 50.153 43.197 52.825 ;
     RECT  45.288 52.583 54.702 53.329 ;
     RECT  55.44 52.583 90.774 53.329 ;
     RECT  45.288 53.329 90.774 53.555 ;
     RECT  45.288 53.555 62.874 53.933 ;
     RECT  45.288 53.933 60.606 55.049 ;
     RECT  52.92 55.049 60.606 55.715 ;
     RECT  52.92 55.715 54.918 55.949 ;
     RECT  52.92 55.949 54.162 55.985 ;
     RECT  44.496 50.891 44.514 56.219 ;
     RECT  55.728 55.715 60.606 56.489 ;
     RECT  57.852 56.489 60.606 56.561 ;
     RECT  54.9 55.949 54.918 56.759 ;
     RECT  57.888 56.561 60.606 57.001 ;
     RECT  63.612 53.555 90.774 57.029 ;
     RECT  2.415 45.689 3.834 57.209 ;
     RECT  24.015 41.711 24.678 57.209 ;
     RECT  9.432 42.179 23.202 57.595 ;
     RECT  24.015 57.209 24.297 57.595 ;
     RECT  5.115 45.797 6.534 57.749 ;
     RECT  2.415 57.209 3.33 57.797 ;
     RECT  5.115 57.749 5.397 57.797 ;
     RECT  9.432 57.595 24.297 57.797 ;
     RECT  26.715 52.825 43.197 57.797 ;
     RECT  52.92 55.985 53.997 57.797 ;
     RECT  57.888 57.001 60.642 57.797 ;
     RECT  61.815 53.933 62.874 57.797 ;
     RECT  99.615 37.967 99.897 57.797 ;
     RECT  63.612 57.029 90.63 57.811 ;
     RECT  91.515 47.615 97.197 57.811 ;
     RECT  7.776 28.949 8.097 57.839 ;
     RECT  9.432 57.797 23.31 57.839 ;
     RECT  26.856 57.797 42.318 57.839 ;
     RECT  45.288 55.049 52.182 57.839 ;
     RECT  63.612 57.811 97.197 57.839 ;
     RECT  63.612 57.839 94.497 57.911 ;
     RECT  9.432 57.839 23.166 57.917 ;
     RECT  26.856 57.839 37.797 57.947 ;
     RECT  9.432 57.917 18.054 57.955 ;
     RECT  26.907 57.947 37.797 58.019 ;
     RECT  91.707 57.911 94.497 58.019 ;
     RECT  2.607 57.797 3.33 58.067 ;
     RECT  5.307 57.797 5.397 58.067 ;
     RECT  8.007 57.839 8.097 58.067 ;
     RECT  18.807 57.917 23.166 58.067 ;
     RECT  24.207 57.797 24.297 58.067 ;
     RECT  26.907 58.019 36.774 58.067 ;
     RECT  37.707 58.019 37.797 58.067 ;
     RECT  43.107 57.797 43.197 58.067 ;
     RECT  45.288 57.839 51.354 58.067 ;
     RECT  53.907 57.797 53.997 58.067 ;
     RECT  55.728 56.489 56.697 58.067 ;
     RECT  59.307 57.797 60.642 58.067 ;
     RECT  62.007 57.797 62.874 58.067 ;
     RECT  63.612 57.911 90.882 58.067 ;
     RECT  91.707 58.019 91.797 58.067 ;
     RECT  94.407 58.019 94.497 58.067 ;
     RECT  95.472 57.839 97.197 58.067 ;
     RECT  99.807 57.797 99.897 58.067 ;
     RECT  19.512 58.067 23.166 58.109 ;
     RECT  9.396 57.955 18.054 58.145 ;
     RECT  17.604 58.145 18.054 58.205 ;
     RECT  30.276 58.067 36.774 58.205 ;
     RECT  86.724 58.067 88.722 58.205 ;
     RECT  95.472 58.067 96.894 58.451 ;
     RECT  86.724 58.205 87.93 58.523 ;
     RECT  32.544 58.205 36.774 58.541 ;
     RECT  32.616 58.541 36.774 58.637 ;
     RECT  88.704 58.205 88.722 58.637 ;
     RECT  89.46 58.067 90.882 58.637 ;
     RECT  9.396 58.145 16.83 58.685 ;
     RECT  62.316 58.067 62.874 58.685 ;
     RECT  89.568 58.637 90.882 58.685 ;
     RECT  95.472 58.451 96.606 59.027 ;
     RECT  55.728 58.067 56.286 59.357 ;
     RECT  98.244 38.003 98.262 59.549 ;
     RECT  3.312 58.067 3.33 59.567 ;
     RECT  57.888 57.797 58.41 59.567 ;
     RECT  62.424 58.685 62.874 59.567 ;
     RECT  96.012 59.027 96.606 59.567 ;
     RECT  52.92 57.797 53.154 59.603 ;
     RECT  92.772 58.019 93.33 59.639 ;
     RECT  63.612 58.067 64.278 59.684 ;
     RECT  30.276 58.205 31.662 59.837 ;
     RECT  65.124 58.067 85.95 59.837 ;
     RECT  89.568 58.685 90.234 59.851 ;
     RECT  15.12 58.685 16.83 59.885 ;
     RECT  30.492 59.837 31.662 59.885 ;
     RECT  73.836 59.837 85.95 59.909 ;
     RECT  9.396 58.685 14.166 59.933 ;
     RECT  57.996 59.567 58.41 59.933 ;
     RECT  19.512 58.109 22.518 59.971 ;
     RECT  9.684 59.933 14.166 59.981 ;
     RECT  14.004 59.981 14.166 59.995 ;
     RECT  59.868 58.067 60.642 59.995 ;
     RECT  52.164 57.839 52.182 60.035 ;
     RECT  73.836 59.909 80.154 60.071 ;
     RECT  55.728 59.357 56.178 60.077 ;
     RECT  65.124 59.837 73.098 60.079 ;
     RECT  38.736 57.839 42.318 60.107 ;
     RECT  74.088 60.071 80.154 60.107 ;
     RECT  81.252 59.909 85.95 60.143 ;
     RECT  26.964 58.067 29.07 60.151 ;
     RECT  63.72 59.684 64.278 60.151 ;
     RECT  65.052 60.079 73.098 60.151 ;
     RECT  59.868 59.995 61.038 60.173 ;
     RECT  63.72 60.151 73.098 60.179 ;
     RECT  26.964 60.151 29.142 60.196 ;
     RECT  82.116 60.143 85.95 60.196 ;
     RECT  18.828 59.971 22.59 60.224 ;
     RECT  42.3 60.107 42.318 60.224 ;
     RECT  81.252 60.143 81.27 60.224 ;
     RECT  87.048 58.523 87.93 60.235 ;
     RECT  32.724 58.637 36.774 60.269 ;
     RECT  82.116 60.196 86.022 60.269 ;
     RECT  87.048 60.235 88.218 60.269 ;
     RECT  45.288 58.067 45.306 60.305 ;
     RECT  63.72 60.179 73.026 60.305 ;
     RECT  82.188 60.269 85.95 60.305 ;
     RECT  9.684 59.981 13.194 60.317 ;
     RECT  59.868 60.173 60.246 60.317 ;
     RECT  89.568 59.851 90.918 60.317 ;
     RECT  38.736 60.107 41.526 60.341 ;
     RECT  46.368 58.067 51.354 60.341 ;
     RECT  63.72 60.305 64.17 60.341 ;
     RECT  64.98 60.305 73.026 60.341 ;
     RECT  74.088 60.107 80.118 60.341 ;
     RECT  82.188 60.305 85.518 60.341 ;
     RECT  6.516 57.749 6.534 60.365 ;
     RECT  14.004 59.995 14.382 60.365 ;
     RECT  15.444 59.885 16.83 60.365 ;
     RECT  30.492 59.885 31.302 60.365 ;
     RECT  33.084 60.269 36.774 60.365 ;
     RECT  60.048 60.317 60.246 60.365 ;
     RECT  61.128 60.235 61.146 60.365 ;
     RECT  87.66 60.269 88.218 60.365 ;
     RECT  89.748 60.317 90.918 60.365 ;
     RECT  30.492 60.365 30.654 60.377 ;
     RECT  33.624 60.365 36.774 60.377 ;
     RECT  63.72 60.341 64.062 60.377 ;
     RECT  87.66 60.365 87.678 60.377 ;
     RECT  9.936 60.317 13.194 60.413 ;
     RECT  14.004 60.365 14.022 60.413 ;
     RECT  18.036 58.205 18.054 60.413 ;
     RECT  19.944 60.224 22.59 60.413 ;
     RECT  30.564 60.377 30.582 60.413 ;
     RECT  34.092 60.377 36.774 60.413 ;
     RECT  38.772 60.341 41.526 60.413 ;
     RECT  46.368 60.341 51.102 60.413 ;
     RECT  53.136 59.603 53.154 60.413 ;
     RECT  54.72 60.187 54.738 60.413 ;
     RECT  55.728 60.077 55.746 60.413 ;
     RECT  60.048 60.365 60.066 60.413 ;
     RECT  62.64 59.567 62.874 60.413 ;
     RECT  64.044 60.377 64.062 60.413 ;
     RECT  65.016 60.341 72.414 60.413 ;
     RECT  74.088 60.341 80.082 60.413 ;
     RECT  82.188 60.341 84.51 60.413 ;
     RECT  85.428 60.341 85.518 60.413 ;
     RECT  96.012 59.567 96.03 60.413 ;
     RECT  10.26 60.413 13.194 60.444 ;
     RECT  20.052 60.413 22.59 60.444 ;
     RECT  26.964 60.196 29.214 60.444 ;
     RECT  34.092 60.413 36.702 60.444 ;
     RECT  38.916 60.413 41.31 60.444 ;
     RECT  46.548 60.413 51.102 60.444 ;
     RECT  65.556 60.413 72.414 60.444 ;
     RECT  75.348 60.413 79.902 60.444 ;
     RECT  82.26 60.413 84.51 60.444 ;
     RECT  13.176 60.444 13.194 60.449 ;
     RECT  18.828 60.224 18.846 60.449 ;
     RECT  22.572 60.444 22.59 60.449 ;
     RECT  25.92 41.945 25.938 60.449 ;
     RECT  29.088 60.444 29.106 60.449 ;
     RECT  34.092 60.444 34.47 60.449 ;
     RECT  38.916 60.444 38.934 60.449 ;
     RECT  51.048 60.444 51.066 60.449 ;
     RECT  58.392 59.933 58.41 60.449 ;
     RECT  62.856 60.413 62.874 60.449 ;
     RECT  69.408 60.444 69.426 60.449 ;
     RECT  79.56 60.444 79.578 60.449 ;
     RECT  93.312 59.639 93.33 60.449 ;
    LAYER M4 ;
     RECT  2.365 8.448 2.408 8.472 ;
     RECT  2.408 2.148 2.512 57.792 ;
     RECT  2.512 2.418 2.6 57.792 ;
     RECT  2.6 2.418 2.704 58.062 ;
     RECT  2.704 9.6 2.917 9.624 ;
     RECT  2.704 20.976 3.377 21 ;
     RECT  2.704 14.016 3.491 14.952 ;
     RECT  2.704 10.752 3.557 11.16 ;
     RECT  2.704 6.24 3.733 6.264 ;
     RECT  2.704 12.48 3.769 12.504 ;
     RECT  2.704 4.368 3.805 4.392 ;
     RECT  3.697 18.24 3.953 18.936 ;
     RECT  3.557 10.992 3.985 11.16 ;
     RECT  3.769 12.48 3.985 13.128 ;
     RECT  3.805 4.368 4.025 5.16 ;
     RECT  3.953 18.24 4.061 18.264 ;
     RECT  2.704 8.448 4.201 8.472 ;
     RECT  3.491 14.736 4.237 14.952 ;
     RECT  4.129 16.08 4.237 16.104 ;
     RECT  4.093 2.832 4.345 2.856 ;
     RECT  4.345 2.496 4.417 2.856 ;
     RECT  3.733 6.24 4.525 6.648 ;
     RECT  4.525 5.664 4.885 7.128 ;
     RECT  4.201 8.448 4.885 8.52 ;
     RECT  4.201 19.248 5.029 19.272 ;
     RECT  4.885 5.664 5.065 8.52 ;
     RECT  4.417 2.496 5.108 3.336 ;
     RECT  4.025 4.656 5.108 4.68 ;
     RECT  5.065 5.664 5.108 8.808 ;
     RECT  3.985 10.992 5.108 13.128 ;
     RECT  4.237 14.736 5.108 16.104 ;
     RECT  2.704 17.088 5.108 17.112 ;
     RECT  5.029 18.72 5.108 19.272 ;
     RECT  3.697 20.544 5.108 20.568 ;
     RECT  4.885 22.752 5.108 22.776 ;
     RECT  5.108 2.148 5.212 57.792 ;
     RECT  5.212 2.418 5.3 57.792 ;
     RECT  5.3 2.418 5.404 58.062 ;
     RECT  5.404 2.496 5.645 9.144 ;
     RECT  5.645 3.888 5.651 9.144 ;
     RECT  5.651 3.888 5.747 7.464 ;
     RECT  5.404 10.992 5.753 19.272 ;
     RECT  5.404 20.88 5.897 23.928 ;
     RECT  5.645 2.496 6.013 2.904 ;
     RECT  5.747 3.888 6.041 6.312 ;
     RECT  5.897 20.88 6.185 23.736 ;
     RECT  5.753 10.992 6.221 18.792 ;
     RECT  6.185 20.88 6.293 23.4 ;
     RECT  6.221 18.48 6.437 18.792 ;
     RECT  6.221 10.992 6.505 17.448 ;
     RECT  5.651 8.784 6.577 9.144 ;
     RECT  6.041 3.888 6.617 3.912 ;
     RECT  6.505 10.608 6.653 17.448 ;
     RECT  6.013 2.496 6.797 2.52 ;
     RECT  5.404 25.104 6.797 25.128 ;
     RECT  6.041 4.944 7.045 6.312 ;
     RECT  5.747 7.44 7.045 7.464 ;
     RECT  6.577 8.784 7.153 9.192 ;
     RECT  7.045 4.944 7.189 7.464 ;
     RECT  7.189 4.416 7.513 7.464 ;
     RECT  7.153 8.496 7.513 9.192 ;
     RECT  6.293 20.88 7.513 23.16 ;
     RECT  6.653 15.744 7.669 17.448 ;
     RECT  6.437 18.48 7.669 18.504 ;
     RECT  7.657 2.592 7.808 2.616 ;
     RECT  7.513 4.416 7.808 9.192 ;
     RECT  6.653 10.608 7.808 14.76 ;
     RECT  7.669 15.744 7.808 18.504 ;
     RECT  7.513 20.688 7.808 23.16 ;
     RECT  7.549 25.824 7.808 25.848 ;
     RECT  7.045 27.072 7.808 27.096 ;
     RECT  7.808 2.148 7.912 57.792 ;
     RECT  7.912 2.418 8 57.792 ;
     RECT  8 2.418 8.104 58.062 ;
     RECT  8.104 20.688 8.165 24.552 ;
     RECT  8.104 2.592 8.237 6.696 ;
     RECT  8.165 20.688 8.237 22.248 ;
     RECT  8.237 2.592 8.243 6.6 ;
     RECT  8.165 23.328 8.531 24.552 ;
     RECT  8.104 25.824 8.597 25.848 ;
     RECT  8.104 27.072 8.741 27.096 ;
     RECT  8.104 10.848 8.893 12.312 ;
     RECT  8.893 10.944 9.107 12.312 ;
     RECT  8.237 20.736 9.169 22.248 ;
     RECT  8.531 23.328 9.169 24.504 ;
     RECT  8.243 2.592 9.385 2.856 ;
     RECT  8.243 3.888 9.385 5.736 ;
     RECT  6.505 60.336 9.385 60.36 ;
     RECT  9.385 19.536 9.533 19.56 ;
     RECT  9.169 20.736 9.601 24.504 ;
     RECT  9.385 3.888 9.637 6.024 ;
     RECT  9.74 26.928 9.745 26.952 ;
     RECT  9.385 2.592 9.781 2.904 ;
     RECT  9.637 3.888 9.781 6.072 ;
     RECT  9.745 26.736 9.781 26.952 ;
     RECT  9.781 26.736 9.817 27.144 ;
     RECT  9.601 20.736 10.033 25.464 ;
     RECT  9.817 26.736 10.033 27.288 ;
     RECT  8.104 13.536 10.061 18.504 ;
     RECT  9.781 2.592 10.117 6.072 ;
     RECT  9.745 12.48 10.141 12.504 ;
     RECT  10.061 13.536 10.141 19.368 ;
     RECT  8.104 7.92 10.177 9.816 ;
     RECT  9.107 10.944 10.177 11.448 ;
     RECT  10.177 7.92 10.213 11.448 ;
     RECT  10.141 12.48 10.213 19.368 ;
     RECT  8.104 28.464 10.248 28.488 ;
     RECT  10.033 20.736 10.357 27.288 ;
     RECT  10.248 28.272 10.357 28.488 ;
     RECT  10.117 2.592 10.508 6.312 ;
     RECT  10.213 7.92 10.508 19.368 ;
     RECT  10.357 20.736 10.508 28.488 ;
     RECT  10.508 2.148 10.612 57.792 ;
     RECT  9.385 59.904 10.681 60.36 ;
     RECT  10.612 2.418 10.7 57.792 ;
     RECT  10.7 2.418 10.804 58.062 ;
     RECT  10.804 28.272 10.973 28.488 ;
     RECT  10.804 10.176 11.081 19.272 ;
     RECT  10.804 21.408 11.117 27 ;
     RECT  11.081 10.176 11.363 18.696 ;
     RECT  11.363 10.176 11.405 11.256 ;
     RECT  11.363 12.48 11.405 18.696 ;
     RECT  10.681 59.904 11.42 60.408 ;
     RECT  11.117 21.936 11.441 27 ;
     RECT  10.804 57.936 11.699 57.96 ;
     RECT  11.42 59.856 11.795 60.408 ;
     RECT  10.804 32.496 12.013 32.52 ;
     RECT  10.804 33.648 12.013 33.672 ;
     RECT  11.405 12.72 12.229 18.696 ;
     RECT  11.441 26.256 12.229 27 ;
     RECT  12.013 32.496 12.229 33.672 ;
     RECT  10.804 29.616 12.265 29.64 ;
     RECT  12.229 31.776 12.265 33.672 ;
     RECT  12.229 26.256 12.301 27.048 ;
     RECT  10.973 28.272 12.301 28.44 ;
     RECT  11.405 10.944 12.373 11.256 ;
     RECT  10.804 2.544 12.409 9.096 ;
     RECT  12.409 2.544 12.445 9.384 ;
     RECT  12.301 26.256 12.469 28.44 ;
     RECT  12.265 29.616 12.469 30.024 ;
     RECT  12.265 31.488 12.469 33.672 ;
     RECT  12.445 2.544 12.517 9.672 ;
     RECT  12.373 10.848 12.517 11.4 ;
     RECT  12.229 12.72 12.517 18.744 ;
     RECT  11.833 35.28 12.589 35.304 ;
     RECT  12.517 2.544 12.697 18.744 ;
     RECT  12.325 58.128 12.697 58.152 ;
     RECT  12.013 20.544 12.769 20.568 ;
     RECT  12.469 26.256 12.805 33.672 ;
     RECT  12.769 20.4 12.908 20.568 ;
     RECT  11.795 59.904 13.121 60.408 ;
     RECT  12.697 2.544 13.208 18.792 ;
     RECT  12.908 20.112 13.208 20.568 ;
     RECT  11.441 21.936 13.208 24.696 ;
     RECT  12.805 26.112 13.208 33.672 ;
     RECT  12.589 35.28 13.208 36.12 ;
     RECT  12.841 38.736 13.208 38.76 ;
     RECT  12.697 58.128 13.208 58.728 ;
     RECT  13.208 2.148 13.504 58.728 ;
     RECT  13.504 12.816 13.565 18.792 ;
     RECT  13.504 24.672 13.601 26.328 ;
     RECT  13.504 31.488 13.745 34.152 ;
     RECT  12.553 0.816 13.813 0.84 ;
     RECT  13.504 27.36 13.817 30.408 ;
     RECT  13.504 35.28 13.953 36.696 ;
     RECT  13.813 0.576 14.029 0.84 ;
     RECT  13.504 57.888 14.041 58.728 ;
     RECT  13.745 31.776 14.147 34.152 ;
     RECT  14.029 0.096 14.209 0.84 ;
     RECT  13.504 2.148 14.209 9.912 ;
     RECT  13.953 36.672 14.243 36.696 ;
     RECT  13.817 27.744 14.429 30.408 ;
     RECT  13.565 12.816 14.533 13.128 ;
     RECT  13.565 14.112 14.533 18.792 ;
     RECT  13.121 59.856 14.533 60.408 ;
     RECT  14.533 59.76 14.675 60.408 ;
     RECT  14.209 0.096 14.821 9.912 ;
     RECT  13.504 10.944 14.821 11.784 ;
     RECT  14.533 12.816 14.821 18.792 ;
     RECT  13.504 20.16 14.821 23.352 ;
     RECT  13.601 24.672 14.821 26.28 ;
     RECT  14.713 35.232 14.861 35.256 ;
     RECT  14.147 33.024 14.893 34.152 ;
     RECT  14.041 57.888 14.969 58.68 ;
     RECT  14.821 0.096 15.253 11.784 ;
     RECT  14.821 12.816 15.253 26.28 ;
     RECT  14.893 33.024 15.301 35.016 ;
     RECT  14.675 59.856 15.347 60.408 ;
     RECT  15.253 0.096 15.349 26.28 ;
     RECT  14.429 27.888 15.361 30.408 ;
     RECT  14.147 31.776 15.577 31.8 ;
     RECT  15.301 32.784 15.577 35.016 ;
     RECT  15.349 0.096 15.733 26.808 ;
     RECT  15.361 27.888 15.733 30.696 ;
     RECT  15.733 0.096 15.749 30.696 ;
     RECT  15.577 31.776 15.749 35.016 ;
     RECT  15.749 0.096 15.761 35.016 ;
     RECT  15.761 0.432 15.908 35.016 ;
     RECT  15.577 36.096 15.908 36.12 ;
     RECT  13.504 40.848 15.908 40.872 ;
     RECT  14.969 57.888 15.908 58.2 ;
     RECT  15.908 0.432 16.069 58.2 ;
     RECT  16.069 0.432 16.204 58.68 ;
     RECT  16.204 0.432 16.229 24.696 ;
     RECT  16.229 0.816 16.451 24.696 ;
     RECT  16.204 26.016 16.451 26.808 ;
     RECT  16.204 57.888 16.517 58.68 ;
     RECT  15.347 60.192 16.549 60.408 ;
     RECT  16.204 34.992 16.553 36.12 ;
     RECT  16.451 0.816 16.589 24.648 ;
     RECT  16.589 0.816 16.595 22.776 ;
     RECT  16.204 27.936 16.643 32.472 ;
     RECT  16.549 60.096 16.741 60.408 ;
     RECT  16.741 60 16.883 60.408 ;
     RECT  16.883 60.096 16.931 60.408 ;
     RECT  16.595 0.816 17.057 18.216 ;
     RECT  16.931 60.192 17.075 60.408 ;
     RECT  16.451 26.784 17.197 26.808 ;
     RECT  17.057 2.736 17.201 18.216 ;
     RECT  16.553 34.992 17.26 35.064 ;
     RECT  16.204 33.888 17.269 33.912 ;
     RECT  17.201 11.136 17.309 18.216 ;
     RECT  17.197 26.784 17.413 26.904 ;
     RECT  16.643 27.936 17.413 28.536 ;
     RECT  17.075 60.24 17.555 60.408 ;
     RECT  17.057 0.816 17.561 1.752 ;
     RECT  16.643 29.664 17.561 32.472 ;
     RECT  16.595 19.344 17.605 22.776 ;
     RECT  16.517 57.888 17.633 58.2 ;
     RECT  17.633 57.888 17.669 57.96 ;
     RECT  17.309 11.76 17.845 18.216 ;
     RECT  17.605 19.344 17.845 23.016 ;
     RECT  17.773 0.048 17.921 0.12 ;
     RECT  17.555 60.384 17.939 60.408 ;
     RECT  17.413 26.784 18.061 28.536 ;
     RECT  18.061 26.784 18.097 28.968 ;
     RECT  17.921 0.096 18.101 0.12 ;
     RECT  16.589 24.096 18.133 24.648 ;
     RECT  17.561 1.728 18.277 1.752 ;
     RECT  17.201 2.736 18.277 10.056 ;
     RECT  18.097 26.736 18.373 28.968 ;
     RECT  18.277 1.728 18.425 10.056 ;
     RECT  18.425 2.148 18.608 10.056 ;
     RECT  17.845 11.76 18.608 23.016 ;
     RECT  18.133 24.096 18.608 24.984 ;
     RECT  18.373 26.064 18.608 28.968 ;
     RECT  17.561 30.384 18.608 32.472 ;
     RECT  17.269 33.6 18.608 33.912 ;
     RECT  17.26 34.992 18.608 35.016 ;
     RECT  16.553 36.096 18.608 36.12 ;
     RECT  16.204 40.848 18.608 41.784 ;
     RECT  17.669 57.888 18.608 57.912 ;
     RECT  18.608 2.148 18.712 57.912 ;
     RECT  18.712 2.418 18.8 57.912 ;
     RECT  18.8 2.418 18.904 58.062 ;
     RECT  18.904 11.424 19.043 24.984 ;
     RECT  19.043 23.04 19.325 24.696 ;
     RECT  18.904 26.064 19.564 28.968 ;
     RECT  18.904 30.384 19.577 33.912 ;
     RECT  19.043 11.424 19.756 22.056 ;
     RECT  19.577 33.12 19.829 33.912 ;
     RECT  18.904 2.496 19.897 9.912 ;
     RECT  19.897 2.496 19.909 10.824 ;
     RECT  19.564 26.064 19.916 27.912 ;
     RECT  19.564 28.944 19.937 28.968 ;
     RECT  19.916 25.824 20.003 27.912 ;
     RECT  19.829 33.264 20.005 33.912 ;
     RECT  19.909 2.208 20.117 10.824 ;
     RECT  18.904 35.136 20.221 36.072 ;
     RECT  19.756 12.24 20.261 22.056 ;
     RECT  19.325 23.28 20.581 24.696 ;
     RECT  19.577 30.384 20.725 31.8 ;
     RECT  20.117 9.792 20.761 10.824 ;
     RECT  20.261 12.24 20.761 21.72 ;
     RECT  20.725 30.192 20.869 31.8 ;
     RECT  20.869 30.192 20.941 31.992 ;
     RECT  20.221 35.136 20.941 37.032 ;
     RECT  20.117 2.208 21.157 8.28 ;
     RECT  20.003 26.208 21.157 27.912 ;
     RECT  20.941 35.136 21.157 37.128 ;
     RECT  20.581 38.112 21.157 38.136 ;
     RECT  21.157 2.064 21.308 8.28 ;
     RECT  20.761 9.792 21.308 21.72 ;
     RECT  20.581 22.752 21.308 24.696 ;
     RECT  21.157 26.208 21.308 28.728 ;
     RECT  20.941 30.192 21.308 32.04 ;
     RECT  20.005 33.264 21.308 34.104 ;
     RECT  21.157 35.136 21.308 38.136 ;
     RECT  18.904 40.848 21.308 40.872 ;
     RECT  21.308 2.064 21.5 57.792 ;
     RECT  21.5 2.064 21.604 58.062 ;
     RECT  21.604 9.696 21.917 10.824 ;
     RECT  21.604 23.952 21.964 24.744 ;
     RECT  21.917 9.696 22.211 10.68 ;
     RECT  21.604 2.064 22.597 8.568 ;
     RECT  21.604 29.568 22.601 35.208 ;
     RECT  22.601 29.568 22.684 33.288 ;
     RECT  21.604 39.216 22.781 39.24 ;
     RECT  22.684 31.392 22.787 33.288 ;
     RECT  21.604 11.808 22.813 13.176 ;
     RECT  22.787 31.392 22.853 32.76 ;
     RECT  21.604 36.336 22.889 38.184 ;
     RECT  22.601 34.656 22.957 35.208 ;
     RECT  21.964 23.952 22.981 24.648 ;
     RECT  21.604 25.728 22.981 28.488 ;
     RECT  22.957 34.656 22.997 35.352 ;
     RECT  22.981 23.952 23.027 28.488 ;
     RECT  22.211 10.08 23.029 10.68 ;
     RECT  22.813 11.808 23.029 13.368 ;
     RECT  23.029 10.08 23.137 13.368 ;
     RECT  22.597 2.064 23.177 8.76 ;
     RECT  21.604 40.848 23.209 40.872 ;
     RECT  23.177 2.148 23.269 8.76 ;
     RECT  23.137 10.08 23.269 13.896 ;
     RECT  22.889 36.432 23.324 38.184 ;
     RECT  23.209 40.56 23.353 40.872 ;
     RECT  23.269 2.148 23.497 13.896 ;
     RECT  21.604 14.976 23.497 22.776 ;
     RECT  23.027 24.624 23.557 28.488 ;
     RECT  22.684 29.568 23.557 30.168 ;
     RECT  23.497 2.148 23.677 22.776 ;
     RECT  23.353 40.08 23.708 40.872 ;
     RECT  23.324 36.432 23.785 38.376 ;
     RECT  23.785 36.432 23.929 38.76 ;
     RECT  23.677 2.148 24.008 23.304 ;
     RECT  23.557 24.624 24.008 30.168 ;
     RECT  22.853 31.392 24.008 31.8 ;
     RECT  24.001 33.84 24.008 33.864 ;
     RECT  22.997 34.848 24.008 35.352 ;
     RECT  23.929 36.432 24.008 39 ;
     RECT  23.708 40.08 24.008 41.304 ;
     RECT  23.749 47.664 24.008 47.688 ;
     RECT  23.237 57.6 24.008 57.624 ;
     RECT  24.008 2.148 24.112 57.792 ;
     RECT  24.112 2.256 24.2 57.792 ;
     RECT  24.2 2.256 24.304 58.062 ;
     RECT  24.304 33.84 24.365 40.968 ;
     RECT  24.365 33.84 24.467 37.08 ;
     RECT  24.304 2.256 24.473 13.128 ;
     RECT  24.304 24.624 25.085 32.568 ;
     RECT  25.085 24.624 25.121 31.992 ;
     RECT  24.304 14.448 25.297 23.304 ;
     RECT  25.121 24.624 25.297 31.56 ;
     RECT  24.467 37.056 25.369 37.08 ;
     RECT  24.365 38.16 25.369 40.968 ;
     RECT  25.297 14.448 25.373 31.56 ;
     RECT  24.473 2.352 25.409 13.128 ;
     RECT  24.467 33.84 25.481 36.072 ;
     RECT  25.369 37.056 25.513 40.968 ;
     RECT  25.373 23.904 25.667 31.56 ;
     RECT  25.409 8.496 25.669 13.128 ;
     RECT  25.373 14.448 25.669 22.344 ;
     RECT  25.669 8.496 25.705 22.344 ;
     RECT  25.705 8.736 25.715 22.344 ;
     RECT  25.667 23.904 25.715 24.12 ;
     RECT  25.409 2.352 25.873 7.464 ;
     RECT  25.481 33.84 25.873 34.968 ;
     RECT  25.667 25.536 26.125 31.56 ;
     RECT  25.513 37.056 26.125 41.112 ;
     RECT  25.873 33.312 26.377 34.968 ;
     RECT  26.125 25.536 26.449 31.944 ;
     RECT  26.377 33.072 26.449 34.968 ;
     RECT  25.873 2.304 26.708 7.464 ;
     RECT  25.715 8.736 26.708 21.528 ;
     RECT  26.377 23.328 26.708 23.352 ;
     RECT  26.449 25.536 26.708 34.968 ;
     RECT  25.481 36.048 26.708 36.072 ;
     RECT  26.125 37.056 26.708 41.688 ;
     RECT  24.304 47.664 26.708 47.688 ;
     RECT  26.708 2.148 26.812 57.792 ;
     RECT  26.812 2.418 26.9 57.792 ;
     RECT  26.9 2.418 27.004 58.062 ;
     RECT  27.004 33.6 27.203 39.288 ;
     RECT  27.004 10.992 27.209 22.776 ;
     RECT  27.004 31.92 27.389 32.616 ;
     RECT  27.004 2.544 27.425 9.912 ;
     RECT  23.569 0.048 27.461 0.072 ;
     RECT  27.457 60.384 27.677 60.408 ;
     RECT  27.209 15.744 27.923 22.776 ;
     RECT  27.425 2.544 27.929 2.616 ;
     RECT  27.004 40.32 27.937 42.792 ;
     RECT  27.923 21.456 28.069 22.776 ;
     RECT  27.203 36.432 28.069 39.288 ;
     RECT  27.937 40.32 28.069 42.12 ;
     RECT  27.004 24.048 28.076 24.984 ;
     RECT  27.004 26.736 28.163 30.936 ;
     RECT  28.069 36.432 28.217 42.12 ;
     RECT  28.069 21.456 28.249 23.016 ;
     RECT  28.076 24.048 28.249 25.176 ;
     RECT  27.389 32.592 28.285 32.616 ;
     RECT  27.203 33.6 28.285 35.448 ;
     RECT  28.285 32.592 28.357 35.448 ;
     RECT  28.217 36.432 28.357 36.648 ;
     RECT  28.163 26.832 28.412 30.936 ;
     RECT  27.929 2.592 28.429 2.616 ;
     RECT  27.425 3.648 28.429 9.912 ;
     RECT  28.412 26.832 28.453 31.416 ;
     RECT  28.357 32.592 28.453 36.648 ;
     RECT  27.209 10.992 28.681 14.712 ;
     RECT  28.429 2.592 28.693 9.912 ;
     RECT  28.681 10.944 28.693 14.712 ;
     RECT  28.249 21.456 28.741 25.176 ;
     RECT  27.923 15.744 29.077 20.184 ;
     RECT  28.693 2.592 29.105 14.712 ;
     RECT  28.969 60.384 29.117 60.408 ;
     RECT  29.077 15.744 29.125 20.376 ;
     RECT  28.741 21.456 29.125 25.848 ;
     RECT  29.125 15.744 29.221 25.848 ;
     RECT  28.453 26.832 29.221 36.648 ;
     RECT  29.105 1.728 29.408 14.712 ;
     RECT  29.221 15.744 29.408 36.648 ;
     RECT  28.217 37.68 29.408 42.12 ;
     RECT  28.933 43.872 29.408 43.896 ;
     RECT  27.004 47.664 29.408 47.688 ;
     RECT  29.408 1.728 29.6 57.792 ;
     RECT  29.285 0.096 29.605 0.12 ;
     RECT  29.6 1.728 29.704 58.062 ;
     RECT  29.704 24.96 29.843 35.448 ;
     RECT  29.704 46.704 30.053 47.592 ;
     RECT  29.843 24.96 30.089 31.8 ;
     RECT  29.605 0.096 30.157 0.168 ;
     RECT  29.704 15.744 30.341 22.536 ;
     RECT  30.265 59.808 30.373 59.832 ;
     RECT  29.704 1.728 30.377 8.76 ;
     RECT  30.341 15.744 30.377 21.72 ;
     RECT  30.377 15.744 30.467 21.672 ;
     RECT  30.467 15.744 30.557 19.8 ;
     RECT  29.704 23.616 30.593 23.88 ;
     RECT  29.704 44.976 30.593 45 ;
     RECT  29.704 10.08 30.733 14.712 ;
     RECT  30.557 15.744 30.733 17.688 ;
     RECT  30.053 47.568 30.769 47.592 ;
     RECT  29.704 36.48 30.803 42.168 ;
     RECT  29.704 43.872 30.805 43.896 ;
     RECT  30.769 47.568 30.809 47.688 ;
     RECT  30.805 43.296 30.845 43.896 ;
     RECT  30.157 0.096 30.877 0.216 ;
     RECT  29.843 32.976 30.997 35.448 ;
     RECT  30.733 10.08 31.043 17.688 ;
     RECT  30.877 0.096 31.057 0.36 ;
     RECT  30.997 32.88 31.141 35.448 ;
     RECT  30.803 36.48 31.141 39.24 ;
     RECT  30.373 59.808 31.165 60.36 ;
     RECT  30.593 23.856 31.189 23.88 ;
     RECT  30.089 24.96 31.189 31.416 ;
     RECT  31.165 59.28 31.313 60.36 ;
     RECT  31.313 59.28 31.436 60.312 ;
     RECT  31.043 10.08 31.484 13.608 ;
     RECT  31.057 0.096 31.489 0.456 ;
     RECT  30.377 1.728 31.489 2.616 ;
     RECT  30.803 40.56 31.525 42.168 ;
     RECT  30.845 43.296 31.525 43.32 ;
     RECT  30.377 3.696 31.561 8.76 ;
     RECT  31.484 9.936 31.561 13.608 ;
     RECT  31.436 59.184 31.571 60.312 ;
     RECT  31.489 0.096 31.763 2.616 ;
     RECT  31.525 40.56 31.777 43.32 ;
     RECT  31.141 32.88 31.813 39.24 ;
     RECT  31.571 59.856 31.859 60.312 ;
     RECT  31.813 32.88 31.877 39.384 ;
     RECT  31.777 40.416 31.877 43.32 ;
     RECT  31.189 23.856 31.885 31.416 ;
     RECT  31.877 32.88 31.885 43.32 ;
     RECT  31.237 58.128 31.885 58.152 ;
     RECT  31.763 1.728 31.909 2.616 ;
     RECT  31.561 3.696 31.909 13.608 ;
     RECT  30.557 18.672 31.921 19.272 ;
     RECT  30.467 20.928 31.921 21.672 ;
     RECT  31.909 1.728 31.961 13.608 ;
     RECT  31.961 1.872 31.997 13.608 ;
     RECT  31.885 58.128 32.005 58.2 ;
     RECT  31.043 14.688 32.065 17.688 ;
     RECT  31.921 18.672 32.065 21.672 ;
     RECT  31.997 1.92 32.108 13.608 ;
     RECT  32.065 14.688 32.108 21.672 ;
     RECT  31.333 22.752 32.108 22.776 ;
     RECT  31.885 23.856 32.108 43.32 ;
     RECT  31.957 44.448 32.108 44.472 ;
     RECT  30.809 47.664 32.108 47.688 ;
     RECT  32.005 58.128 32.108 58.68 ;
     RECT  31.763 0.096 32.147 0.216 ;
     RECT  32.147 0.096 32.285 0.168 ;
     RECT  32.108 1.92 32.404 58.68 ;
     RECT  31.859 60 32.485 60.312 ;
     RECT  32.404 58.512 32.627 58.68 ;
     RECT  32.404 40.848 32.645 42.744 ;
     RECT  32.627 58.56 32.789 58.68 ;
     RECT  32.485 60 32.924 60.36 ;
     RECT  32.404 1.92 32.933 15.48 ;
     RECT  32.789 58.656 32.933 58.68 ;
     RECT  32.933 9.264 32.969 15.48 ;
     RECT  32.924 59.856 33.011 60.36 ;
     RECT  32.933 1.92 33.041 8.28 ;
     RECT  32.404 16.512 33.049 39.528 ;
     RECT  33.049 16.656 33.059 39.528 ;
     RECT  33.059 20.112 33.077 39.528 ;
     RECT  33.011 60.096 33.329 60.36 ;
     RECT  32.404 44.448 33.404 44.472 ;
     RECT  33.077 31.536 33.437 39.528 ;
     RECT  33.059 16.656 33.443 18.984 ;
     RECT  33.404 44.448 33.445 45.432 ;
     RECT  33.437 31.536 33.481 39.336 ;
     RECT  33.329 60.096 33.484 60.312 ;
     RECT  33.445 44.448 33.491 46.248 ;
     RECT  33.443 16.656 33.545 17.688 ;
     RECT  33.041 2.496 33.617 8.28 ;
     RECT  32.969 9.936 33.645 15.48 ;
     RECT  33.481 31.536 33.725 33.048 ;
     RECT  33.645 12.768 33.731 15.48 ;
     RECT  32.285 0.144 33.941 0.168 ;
     RECT  33.077 20.112 34.213 30.072 ;
     RECT  33.725 31.536 34.213 31.8 ;
     RECT  33.617 3.888 34.297 8.28 ;
     RECT  33.725 32.784 34.453 33.048 ;
     RECT  33.484 60.144 34.625 60.312 ;
     RECT  33.545 16.656 34.693 17.64 ;
     RECT  33.443 18.672 34.693 18.984 ;
     RECT  33.617 2.496 34.808 2.808 ;
     RECT  34.297 3.888 34.808 8.472 ;
     RECT  33.645 9.936 34.808 11.784 ;
     RECT  33.731 12.768 34.808 15.288 ;
     RECT  34.693 16.656 34.808 18.984 ;
     RECT  34.213 20.112 34.808 31.8 ;
     RECT  34.453 32.784 34.808 33.288 ;
     RECT  33.481 34.416 34.808 39.336 ;
     RECT  32.645 40.848 34.808 42.264 ;
     RECT  33.491 44.448 34.808 45.048 ;
     RECT  33.491 46.224 34.808 46.248 ;
     RECT  32.404 47.664 34.808 47.688 ;
     RECT  34.808 2.148 34.912 57.792 ;
     RECT  34.912 2.418 35 57.792 ;
     RECT  35 2.418 35.104 58.062 ;
     RECT  35.104 22.176 35.219 26.088 ;
     RECT  35.104 40.56 35.309 45.768 ;
     RECT  34.625 60.24 35.341 60.312 ;
     RECT  35.309 40.896 35.417 45.768 ;
     RECT  35.219 22.176 35.525 24.456 ;
     RECT  35.104 8.016 35.548 19.8 ;
     RECT  35.341 60.24 35.564 60.36 ;
     RECT  35.548 8.016 35.597 18.984 ;
     RECT  35.104 34.752 35.633 39.336 ;
     RECT  35.417 44.208 35.669 45.768 ;
     RECT  35.597 8.016 35.705 12.936 ;
     RECT  35.104 27.168 35.813 33.576 ;
     RECT  35.564 60.24 35.957 60.408 ;
     RECT  35.813 27.168 35.993 31.944 ;
     RECT  35.813 33.072 36.169 33.576 ;
     RECT  35.219 25.632 36.173 26.088 ;
     RECT  35.525 24.432 36.277 24.456 ;
     RECT  35.104 20.928 36.349 20.952 ;
     RECT  35.525 22.176 36.349 23.112 ;
     RECT  36.349 20.928 36.421 23.112 ;
     RECT  35.669 44.304 36.421 45.768 ;
     RECT  35.104 3.888 36.709 6.936 ;
     RECT  35.705 8.16 36.709 12.936 ;
     RECT  36.421 20.592 36.745 23.112 ;
     RECT  36.169 33.072 36.745 33.672 ;
     RECT  35.633 34.752 36.745 38.184 ;
     RECT  36.421 44.304 36.757 46.296 ;
     RECT  36.709 3.888 36.764 12.936 ;
     RECT  35.597 14.112 36.764 18.984 ;
     RECT  36.764 3.888 36.781 18.984 ;
     RECT  36.757 44.016 36.805 46.296 ;
     RECT  35.633 39.216 36.853 39.336 ;
     RECT  36.781 3.888 36.925 19.368 ;
     RECT  36.745 33.072 36.925 38.184 ;
     RECT  36.853 39.216 36.925 39.576 ;
     RECT  35.417 40.896 36.925 42.744 ;
     RECT  36.805 43.92 36.925 46.296 ;
     RECT  36.925 3.12 36.997 19.368 ;
     RECT  36.745 20.592 36.997 23.304 ;
     RECT  35.993 27.456 37.033 31.944 ;
     RECT  36.925 33.072 37.033 39.576 ;
     RECT  37.033 27.312 37.141 39.576 ;
     RECT  36.925 40.896 37.141 46.296 ;
     RECT  35.104 47.664 37.141 47.688 ;
     RECT  36.997 3.12 37.249 23.304 ;
     RECT  37.141 26.784 37.465 39.576 ;
     RECT  37.249 2.832 37.508 23.304 ;
     RECT  36.277 24.432 37.508 24.888 ;
     RECT  37.465 26.544 37.508 39.576 ;
     RECT  37.141 40.896 37.508 47.688 ;
     RECT  37.508 2.148 37.612 57.792 ;
     RECT  37.612 2.418 37.7 57.792 ;
     RECT  37.7 2.418 37.804 58.062 ;
     RECT  37.804 24.336 37.955 25.56 ;
     RECT  37.804 18.528 38.099 23.112 ;
     RECT  38.099 18.768 38.195 23.112 ;
     RECT  37.804 26.544 38.513 45.576 ;
     RECT  37.804 2.736 38.621 9.816 ;
     RECT  35.957 60.336 38.761 60.408 ;
     RECT  38.513 26.544 38.764 39.816 ;
     RECT  37.804 47.328 38.771 48.168 ;
     RECT  38.732 1.152 38.773 1.176 ;
     RECT  38.771 47.568 38.801 48.168 ;
     RECT  38.761 60.288 38.801 60.408 ;
     RECT  38.621 9.792 38.821 9.816 ;
     RECT  38.821 9.792 38.908 9.96 ;
     RECT  38.513 40.848 38.909 45.576 ;
     RECT  38.909 42.24 38.917 45.576 ;
     RECT  38.195 18.96 38.941 23.112 ;
     RECT  37.955 24.336 38.941 24.696 ;
     RECT  38.773 1.152 39.017 1.272 ;
     RECT  37.804 14.64 39.116 17.208 ;
     RECT  38.941 18.96 39.157 24.696 ;
     RECT  38.917 42.24 39.161 45.72 ;
     RECT  38.801 47.664 39.193 48.168 ;
     RECT  39.161 42.24 39.197 45.192 ;
     RECT  39.116 14.64 39.203 17.4 ;
     RECT  39.157 18.96 39.203 25.464 ;
     RECT  39.017 1.152 39.233 1.176 ;
     RECT  39.203 24.336 39.233 25.464 ;
     RECT  38.621 2.736 39.337 8.52 ;
     RECT  37.804 10.944 39.373 13.176 ;
     RECT  39.373 10.944 39.445 13.656 ;
     RECT  39.203 14.64 39.445 17.16 ;
     RECT  39.233 24.624 39.445 25.464 ;
     RECT  38.764 26.544 39.445 33.768 ;
     RECT  39.337 2.496 39.625 8.52 ;
     RECT  38.908 9.792 39.625 9.912 ;
     RECT  39.445 24.624 39.733 33.768 ;
     RECT  38.764 34.896 39.733 39.816 ;
     RECT  39.625 2.496 39.985 9.912 ;
     RECT  39.193 47.664 40.057 48.264 ;
     RECT  39.985 2.352 40.069 9.912 ;
     RECT  39.203 18.96 40.165 23.352 ;
     RECT  38.801 60.288 40.165 60.36 ;
     RECT  40.069 2.256 40.208 9.912 ;
     RECT  39.445 10.944 40.208 17.16 ;
     RECT  40.165 18.24 40.208 23.352 ;
     RECT  39.733 24.624 40.208 39.816 ;
     RECT  38.909 40.848 40.208 41.208 ;
     RECT  39.197 42.288 40.208 45.192 ;
     RECT  40.057 46.848 40.208 48.264 ;
     RECT  40.208 2.148 40.312 57.792 ;
     RECT  40.165 60.288 40.313 60.408 ;
     RECT  40.312 2.256 40.4 57.792 ;
     RECT  40.4 2.256 40.504 58.062 ;
     RECT  40.504 2.256 40.787 45.192 ;
     RECT  40.787 42.288 40.883 45.192 ;
     RECT  40.504 46.176 40.961 49.032 ;
     RECT  40.313 60.288 41.029 60.36 ;
     RECT  40.883 42.288 41.069 42.312 ;
     RECT  41.029 60.24 41.069 60.36 ;
     RECT  40.787 10.944 41.105 41.304 ;
     RECT  41.105 10.944 41.123 18.984 ;
     RECT  40.787 2.256 41.141 9.912 ;
     RECT  41.069 60.24 41.177 60.312 ;
     RECT  41.123 10.944 41.357 14.856 ;
     RECT  41.141 2.256 41.429 9.768 ;
     RECT  41.105 20.256 41.452 41.304 ;
     RECT  41.123 15.888 41.465 18.984 ;
     RECT  41.177 60.288 41.501 60.312 ;
     RECT  41.429 2.496 41.507 9.768 ;
     RECT  41.507 2.592 41.609 9.768 ;
     RECT  41.465 17.616 41.717 18.984 ;
     RECT  41.452 25.104 41.795 41.304 ;
     RECT  40.961 46.176 41.795 47.688 ;
     RECT  40.883 43.392 42.109 45.192 ;
     RECT  41.465 15.888 42.145 16.344 ;
     RECT  38.869 0.048 42.149 0.072 ;
     RECT  42.109 43.392 42.433 45.576 ;
     RECT  42.289 1.152 42.437 1.176 ;
     RECT  42.433 43.344 42.469 45.576 ;
     RECT  42.145 15.456 42.613 16.344 ;
     RECT  41.717 17.616 42.613 17.64 ;
     RECT  41.717 18.96 42.757 18.984 ;
     RECT  41.452 20.256 42.757 23.592 ;
     RECT  42.757 18.96 42.793 23.88 ;
     RECT  41.795 25.104 42.793 40.824 ;
     RECT  42.469 42.48 42.793 45.576 ;
     RECT  41.357 10.944 42.829 14.232 ;
     RECT  41.609 2.592 42.908 9.624 ;
     RECT  42.829 10.608 42.908 14.232 ;
     RECT  42.613 15.456 42.908 17.64 ;
     RECT  42.793 18.96 42.908 40.824 ;
     RECT  42.793 42.288 42.908 45.576 ;
     RECT  41.795 46.848 42.908 47.688 ;
     RECT  40.961 49.008 42.908 49.032 ;
     RECT  42.908 2.148 43.012 57.792 ;
     RECT  43.012 2.418 43.1 57.792 ;
     RECT  43.1 2.418 43.204 58.062 ;
     RECT  43.204 10.608 43.265 16.344 ;
     RECT  43.204 17.616 43.331 17.64 ;
     RECT  43.204 20.688 43.331 20.904 ;
     RECT  43.204 34.656 43.331 41.112 ;
     RECT  43.204 21.936 43.337 24.696 ;
     RECT  43.331 34.752 43.337 41.112 ;
     RECT  43.265 11.952 43.409 16.344 ;
     RECT  43.331 20.688 43.445 20.712 ;
     RECT  43.204 26.016 43.445 33.48 ;
     RECT  43.204 18.816 43.517 19.368 ;
     RECT  43.445 26.064 43.553 33.48 ;
     RECT  43.204 49.008 43.769 49.032 ;
     RECT  43.204 42.288 43.949 45.624 ;
     RECT  43.949 42.48 43.985 45.624 ;
     RECT  43.204 2.592 44.021 9.624 ;
     RECT  43.409 12.528 44.057 16.344 ;
     RECT  43.553 26.592 44.195 33.48 ;
     RECT  44.021 2.592 44.197 8.568 ;
     RECT  44.057 12.528 44.345 14.424 ;
     RECT  44.345 12.528 44.377 14.232 ;
     RECT  43.337 34.944 44.38 41.112 ;
     RECT  44.197 2.544 44.381 8.568 ;
     RECT  44.195 26.736 44.387 33.48 ;
     RECT  44.021 9.6 44.413 9.624 ;
     RECT  43.265 10.608 44.413 10.968 ;
     RECT  44.057 15.408 44.417 16.344 ;
     RECT  44.417 15.408 44.597 16.056 ;
     RECT  44.38 36 44.665 41.112 ;
     RECT  44.387 30.48 44.737 33.48 ;
     RECT  44.413 9.6 44.773 10.968 ;
     RECT  44.377 11.952 44.773 14.232 ;
     RECT  44.665 36 45.157 41.16 ;
     RECT  44.381 2.544 45.253 6.6 ;
     RECT  43.204 47.04 45.308 47.688 ;
     RECT  45.308 47.04 45.385 47.784 ;
     RECT  45.321 48.768 45.385 48.792 ;
     RECT  45.253 1.728 45.421 6.6 ;
     RECT  44.381 7.824 45.445 8.568 ;
     RECT  43.985 42.528 45.457 45.624 ;
     RECT  45.157 36 45.493 41.208 ;
     RECT  45.457 42.192 45.493 45.624 ;
     RECT  45.349 0.096 45.497 0.12 ;
     RECT  45.421 1.632 45.587 6.6 ;
     RECT  45.587 1.728 45.608 6.6 ;
     RECT  45.445 7.728 45.608 8.568 ;
     RECT  44.773 9.6 45.608 14.232 ;
     RECT  44.597 16.032 45.608 16.056 ;
     RECT  43.517 18.96 45.608 18.984 ;
     RECT  43.337 21.936 45.608 24.648 ;
     RECT  44.387 26.784 45.608 29.304 ;
     RECT  44.737 30.48 45.608 33.96 ;
     RECT  44.38 34.944 45.608 34.968 ;
     RECT  45.493 36 45.608 45.624 ;
     RECT  45.385 47.04 45.608 48.792 ;
     RECT  45.061 50.544 45.608 50.568 ;
     RECT  45.608 1.728 45.8 57.792 ;
     RECT  45.8 1.728 45.904 58.062 ;
     RECT  45.904 35.904 45.965 50.712 ;
     RECT  45.904 26.208 46.001 31.224 ;
     RECT  45.829 0.144 46.019 0.168 ;
     RECT  46.001 26.208 46.019 31.128 ;
     RECT  45.965 35.904 46.019 42.792 ;
     RECT  45.965 43.872 46.019 50.712 ;
     RECT  46.019 27.936 46.037 31.128 ;
     RECT  46.019 26.208 46.067 26.904 ;
     RECT  45.904 1.728 46.073 6.312 ;
     RECT  46.019 43.872 46.108 49.032 ;
     RECT  46.019 35.904 46.109 37.944 ;
     RECT  46.019 50.16 46.109 50.712 ;
     RECT  46.108 43.872 46.145 48.936 ;
     RECT  45.904 7.728 46.163 14.232 ;
     RECT  46.073 1.728 46.181 3.048 ;
     RECT  46.145 43.872 46.181 46.296 ;
     RECT  46.145 47.712 46.181 48.936 ;
     RECT  46.163 9.312 46.211 14.232 ;
     RECT  46.109 50.16 46.217 50.28 ;
     RECT  46.181 47.712 46.253 48.792 ;
     RECT  46.211 9.312 46.361 12.552 ;
     RECT  46.019 39.072 46.433 42.792 ;
     RECT  46.361 9.312 46.441 12.312 ;
     RECT  46.037 27.936 46.469 30.216 ;
     RECT  46.441 9.312 46.613 10.824 ;
     RECT  45.904 32.784 46.613 33.624 ;
     RECT  46.613 10.08 46.685 10.824 ;
     RECT  46.073 4.128 46.721 6.312 ;
     RECT  46.181 1.728 46.739 2.904 ;
     RECT  45.904 23.616 46.787 25.224 ;
     RECT  46.067 26.208 46.787 26.664 ;
     RECT  46.787 24.624 46.829 25.224 ;
     RECT  46.109 35.904 46.873 35.928 ;
     RECT  46.253 48.432 46.883 48.792 ;
     RECT  46.441 11.904 46.937 12.312 ;
     RECT  46.787 23.616 46.973 23.64 ;
     RECT  46.613 32.784 47.009 33.576 ;
     RECT  46.163 7.728 47.045 7.752 ;
     RECT  46.217 50.16 47.045 50.184 ;
     RECT  46.787 26.208 47.293 26.232 ;
     RECT  46.181 43.872 47.293 45 ;
     RECT  46.937 12.288 47.297 12.312 ;
     RECT  46.469 28.32 47.297 30.216 ;
     RECT  46.739 1.728 47.317 2.856 ;
     RECT  46.181 46.272 47.317 46.296 ;
     RECT  46.109 36.912 47.324 37.944 ;
     RECT  46.433 40.896 47.365 42.792 ;
     RECT  47.293 43.872 47.365 45.096 ;
     RECT  47.317 46.224 47.473 46.296 ;
     RECT  47.317 1.68 47.538 2.856 ;
     RECT  46.211 13.824 47.617 14.232 ;
     RECT  47.473 46.224 47.761 46.872 ;
     RECT  47.756 60.384 47.843 60.408 ;
     RECT  47.009 33.024 47.845 33.576 ;
     RECT  47.617 13.68 47.852 14.232 ;
     RECT  47.845 33.024 47.869 33.816 ;
     RECT  47.761 34.992 47.869 35.016 ;
     RECT  47.365 40.896 47.869 45.096 ;
     RECT  47.761 46.128 47.869 46.872 ;
     RECT  47.538 1.728 47.941 2.856 ;
     RECT  46.721 4.176 47.941 6.312 ;
     RECT  47.869 40.896 48.013 46.872 ;
     RECT  48.013 40.896 48.085 47.112 ;
     RECT  47.989 0.144 48.275 0.168 ;
     RECT  47.941 1.728 48.308 6.312 ;
     RECT  46.685 10.08 48.308 10.632 ;
     RECT  47.852 12.768 48.308 14.232 ;
     RECT  45.904 16.032 48.308 16.056 ;
     RECT  45.904 18.96 48.308 18.984 ;
     RECT  46.829 24.624 48.308 24.648 ;
     RECT  47.293 25.632 48.308 26.232 ;
     RECT  47.297 28.32 48.308 29.304 ;
     RECT  47.041 31.2 48.308 31.224 ;
     RECT  47.869 33.024 48.308 35.016 ;
     RECT  47.324 36.384 48.308 37.944 ;
     RECT  46.433 39.072 48.308 39.768 ;
     RECT  48.085 40.896 48.308 47.64 ;
     RECT  46.883 48.768 48.308 48.792 ;
     RECT  47.473 50.832 48.308 50.856 ;
     RECT  47.545 52.176 48.308 52.2 ;
     RECT  48.308 1.728 48.5 57.792 ;
     RECT  48.5 1.728 48.604 58.062 ;
     RECT  48.604 24.624 48.755 24.888 ;
     RECT  48.604 32.832 48.773 41.4 ;
     RECT  48.604 31.2 48.803 31.224 ;
     RECT  48.604 1.728 48.881 6.312 ;
     RECT  48.881 5.232 48.995 6.312 ;
     RECT  48.604 50.736 49.097 53.016 ;
     RECT  48.773 32.832 49.349 40.152 ;
     RECT  48.881 1.728 49.637 4.248 ;
     RECT  49.097 52.32 49.741 53.016 ;
     RECT  49.349 34.656 49.813 40.152 ;
     RECT  48.773 41.376 49.813 41.4 ;
     RECT  48.604 42.576 49.921 44.952 ;
     RECT  48.604 46.224 49.921 49.56 ;
     RECT  49.921 42.576 50.029 49.56 ;
     RECT  49.097 50.736 50.029 51.24 ;
     RECT  48.995 5.232 50.033 5.496 ;
     RECT  48.604 13.68 50.06 13.704 ;
     RECT  50.06 13.584 50.101 13.704 ;
     RECT  48.604 16.032 50.101 16.056 ;
     RECT  49.813 34.656 50.101 41.4 ;
     RECT  50.029 42.576 50.149 51.24 ;
     RECT  49.741 52.32 50.149 53.592 ;
     RECT  50.101 34.656 50.173 41.496 ;
     RECT  50.149 42.576 50.173 53.592 ;
     RECT  49.637 1.728 50.177 1.752 ;
     RECT  50.101 13.584 50.317 16.056 ;
     RECT  48.604 18.96 50.461 18.984 ;
     RECT  49.349 32.832 50.581 33.624 ;
     RECT  50.497 60.384 50.717 60.408 ;
     RECT  50.461 18.96 50.869 19.512 ;
     RECT  49.637 2.832 50.893 4.248 ;
     RECT  50.893 2.148 51.008 4.248 ;
     RECT  50.033 5.472 51.008 5.496 ;
     RECT  48.604 7.872 51.008 7.896 ;
     RECT  50.869 8.976 51.008 9 ;
     RECT  48.604 10.08 51.008 11.16 ;
     RECT  50.06 12.144 51.008 12.168 ;
     RECT  50.317 13.344 51.008 16.056 ;
     RECT  50.869 17.472 51.008 17.496 ;
     RECT  50.869 18.96 51.008 19.608 ;
     RECT  48.604 20.976 51.008 21 ;
     RECT  48.604 28.512 51.008 29.304 ;
     RECT  50.581 32.016 51.008 33.624 ;
     RECT  50.173 34.656 51.008 53.592 ;
     RECT  51.008 2.148 51.112 57.792 ;
     RECT  51.112 2.256 51.2 57.792 ;
     RECT  51.2 2.256 51.304 58.062 ;
     RECT  51.304 41.472 51.509 51.72 ;
     RECT  51.509 45.696 51.581 50.088 ;
     RECT  51.509 51.36 51.617 51.72 ;
     RECT  51.304 18.768 51.653 18.84 ;
     RECT  51.581 45.696 51.971 49.56 ;
     RECT  51.304 32.016 52.019 39.24 ;
     RECT  51.304 28.512 52.157 29.304 ;
     RECT  51.304 10.08 52.405 10.104 ;
     RECT  51.304 15.216 52.405 16.056 ;
     RECT  51.971 45.696 52.409 46.728 ;
     RECT  52.019 34.704 52.451 39.24 ;
     RECT  52.405 10.08 52.477 10.92 ;
     RECT  51.304 13.584 52.549 13.608 ;
     RECT  51.509 41.472 52.621 44.664 ;
     RECT  51.653 18.816 52.657 18.84 ;
     RECT  52.451 34.704 52.661 35.496 ;
     RECT  51.617 51.36 52.693 51.432 ;
     RECT  51.304 53.28 52.693 53.4 ;
     RECT  52.693 51.36 52.697 53.4 ;
     RECT  52.451 36.864 52.729 39.24 ;
     RECT  52.657 18.432 52.801 18.84 ;
     RECT  52.729 0.576 52.873 0.6 ;
     RECT  52.697 51.888 52.873 53.4 ;
     RECT  52.549 13.584 52.981 14.184 ;
     RECT  52.873 51.888 52.981 53.592 ;
     RECT  51.304 55.008 52.981 55.032 ;
     RECT  52.477 9.6 53.017 10.92 ;
     RECT  51.304 12.48 53.017 12.504 ;
     RECT  52.405 15.216 53.017 16.104 ;
     RECT  52.801 17.712 53.017 18.84 ;
     RECT  53.017 15.216 53.053 18.84 ;
     RECT  53.053 15.216 53.089 18.984 ;
     RECT  52.621 41.04 53.132 44.664 ;
     RECT  52.873 0.576 53.161 1.176 ;
     RECT  51.304 2.256 53.161 5.496 ;
     RECT  53.161 0.576 53.341 5.496 ;
     RECT  51.971 48.24 53.413 49.56 ;
     RECT  52.981 13.584 53.485 14.232 ;
     RECT  53.089 15.216 53.485 19.848 ;
     RECT  53.341 0.576 53.489 6.024 ;
     RECT  53.132 40.56 53.549 44.664 ;
     RECT  52.409 45.696 53.549 46.488 ;
     RECT  52.729 7.968 53.593 7.992 ;
     RECT  53.489 1.68 53.708 6.024 ;
     RECT  53.593 7.392 53.708 7.992 ;
     RECT  53.017 9.6 53.708 12.504 ;
     RECT  53.485 13.584 53.708 19.848 ;
     RECT  52.837 20.88 53.708 20.904 ;
     RECT  53.485 22.224 53.708 22.248 ;
     RECT  52.157 28.704 53.708 29.304 ;
     RECT  52.019 32.016 53.708 33.624 ;
     RECT  52.661 34.704 53.708 35.16 ;
     RECT  52.729 36.864 53.708 39.48 ;
     RECT  53.549 40.56 53.708 46.488 ;
     RECT  53.413 48.24 53.708 49.608 ;
     RECT  52.981 51.888 53.708 55.032 ;
     RECT  53.489 0.576 53.813 0.6 ;
     RECT  53.708 1.68 53.9 57.792 ;
     RECT  53.9 1.68 53.993 58.062 ;
     RECT  53.993 2.304 54.004 58.062 ;
     RECT  54.004 41.952 54.029 50.04 ;
     RECT  54.004 17.904 54.101 17.928 ;
     RECT  54.004 2.304 54.131 6.024 ;
     RECT  54.004 32.016 54.227 34.92 ;
     RECT  54.004 7.392 54.281 8.712 ;
     RECT  54.281 7.632 54.317 8.712 ;
     RECT  54.004 16.032 54.317 16.152 ;
     RECT  54.004 18.96 54.533 20.904 ;
     RECT  54.004 22.224 54.533 23.112 ;
     RECT  54.004 35.904 54.605 40.968 ;
     RECT  53.125 60.384 54.709 60.408 ;
     RECT  54.533 22.992 54.749 23.112 ;
     RECT  54.605 37.92 54.749 40.968 ;
     RECT  54.709 60.192 54.749 60.408 ;
     RECT  54.131 2.496 54.929 6.024 ;
     RECT  54.029 46.704 54.929 50.04 ;
     RECT  54.929 2.496 55.037 2.856 ;
     RECT  54.004 10.08 55.145 14.52 ;
     RECT  54.929 5.472 55.189 6.024 ;
     RECT  54.749 40.56 55.213 40.968 ;
     RECT  54.029 41.952 55.213 45.72 ;
     RECT  54.227 33.024 55.237 34.92 ;
     RECT  54.605 35.904 55.237 36.936 ;
     RECT  54.929 47.088 55.249 50.04 ;
     RECT  54.997 1.2 55.289 1.224 ;
     RECT  55.213 40.56 55.297 45.72 ;
     RECT  54.004 53.808 55.321 54.12 ;
     RECT  54.004 55.584 55.321 55.608 ;
     RECT  55.237 33.024 55.325 36.936 ;
     RECT  55.297 40.56 55.325 40.968 ;
     RECT  54.317 7.632 55.393 8.232 ;
     RECT  55.145 14.208 55.433 14.52 ;
     RECT  54.317 16.08 55.609 16.152 ;
     RECT  55.609 16.08 55.645 16.68 ;
     RECT  54.749 60.192 55.717 60.216 ;
     RECT  55.393 7.632 55.753 8.472 ;
     RECT  55.325 40.56 55.82 40.584 ;
     RECT  55.717 17.904 55.861 17.928 ;
     RECT  55.753 7.44 55.897 8.472 ;
     RECT  55.189 5.472 55.933 6.216 ;
     RECT  55.897 7.392 55.933 8.472 ;
     RECT  55.037 2.784 56.005 2.856 ;
     RECT  54.749 23.088 56.077 23.112 ;
     RECT  56.005 2.352 56.113 2.856 ;
     RECT  54.929 3.936 56.149 4.2 ;
     RECT  55.933 5.424 56.149 8.472 ;
     RECT  55.717 60.192 56.149 60.408 ;
     RECT  56.149 60.048 56.257 60.408 ;
     RECT  56.113 2.352 56.293 2.904 ;
     RECT  56.149 3.936 56.293 8.472 ;
     RECT  55.325 33.024 56.401 33.096 ;
     RECT  55.325 34.128 56.401 36.936 ;
     RECT  54.004 52.176 56.401 52.728 ;
     RECT  56.293 2.352 56.408 8.472 ;
     RECT  55.145 10.08 56.408 13.08 ;
     RECT  55.433 14.496 56.408 14.52 ;
     RECT  55.645 16.08 56.408 16.92 ;
     RECT  55.861 17.904 56.408 18.168 ;
     RECT  54.533 19.248 56.408 20.904 ;
     RECT  56.077 22.8 56.408 23.112 ;
     RECT  54.004 28.704 56.408 29.304 ;
     RECT  54.227 32.016 56.408 32.04 ;
     RECT  56.401 33.024 56.408 36.936 ;
     RECT  54.749 37.92 56.408 39.24 ;
     RECT  55.82 40.272 56.408 40.584 ;
     RECT  55.297 41.952 56.408 45.72 ;
     RECT  55.249 47.088 56.408 50.328 ;
     RECT  56.401 51.696 56.408 52.728 ;
     RECT  55.321 53.808 56.408 55.608 ;
     RECT  56.408 2.148 56.6 57.792 ;
     RECT  56.6 2.148 56.704 58.062 ;
     RECT  55.645 0.048 56.725 0.072 ;
     RECT  56.704 55.152 56.845 55.896 ;
     RECT  56.704 2.148 56.869 4.488 ;
     RECT  56.704 10.08 56.873 12.504 ;
     RECT  56.704 14.208 56.909 21.48 ;
     RECT  56.725 0.048 56.945 0.168 ;
     RECT  56.909 14.208 57.017 20.904 ;
     RECT  57.017 14.208 57.061 20.568 ;
     RECT  56.704 30.912 57.233 39.336 ;
     RECT  56.704 40.56 57.299 50.424 ;
     RECT  57.061 14.208 57.347 19.8 ;
     RECT  56.704 24.288 57.395 24.312 ;
     RECT  57.347 14.496 57.413 19.8 ;
     RECT  57.299 40.56 57.413 43.32 ;
     RECT  56.945 0.048 57.449 0.12 ;
     RECT  57.413 14.496 57.557 19.512 ;
     RECT  57.557 15.408 57.593 19.512 ;
     RECT  56.704 51.696 57.593 54.12 ;
     RECT  56.845 55.152 57.593 55.176 ;
     RECT  56.869 2.016 57.665 4.488 ;
     RECT  57.593 51.696 57.665 51.72 ;
     RECT  57.233 30.912 57.673 39.24 ;
     RECT  57.593 15.408 57.683 18.792 ;
     RECT  57.413 40.56 57.769 42.216 ;
     RECT  57.665 2.016 57.809 3.48 ;
     RECT  57.809 2.016 57.881 3.432 ;
     RECT  56.704 22.512 57.881 23.112 ;
     RECT  57.673 30.912 57.913 34.776 ;
     RECT  57.683 15.408 57.917 18.696 ;
     RECT  56.873 10.08 57.973 10.104 ;
     RECT  56.873 11.136 57.973 12.504 ;
     RECT  57.665 4.464 57.985 4.488 ;
     RECT  56.704 5.472 57.985 7.416 ;
     RECT  57.973 10.08 57.985 12.504 ;
     RECT  57.985 10.08 58.019 13.08 ;
     RECT  57.593 52.704 58.067 54.12 ;
     RECT  57.299 44.448 58.093 50.424 ;
     RECT  57.881 22.704 58.117 23.112 ;
     RECT  56.704 8.448 58.273 8.472 ;
     RECT  58.117 9.648 58.273 9.672 ;
     RECT  57.913 30.864 58.273 34.776 ;
     RECT  57.985 4.464 58.489 7.416 ;
     RECT  58.019 10.896 58.561 13.08 ;
     RECT  58.357 14.064 58.561 14.088 ;
     RECT  57.673 35.76 58.633 39.24 ;
     RECT  57.769 40.464 58.633 42.216 ;
     RECT  58.093 44.448 58.633 50.568 ;
     RECT  57.413 43.248 58.693 43.32 ;
     RECT  58.633 44.304 58.693 50.568 ;
     RECT  58.633 35.76 58.813 42.216 ;
     RECT  58.067 52.704 58.849 54.072 ;
     RECT  58.561 10.896 58.921 14.088 ;
     RECT  57.917 17.712 58.921 18.696 ;
     RECT  58.921 17.712 58.957 19.272 ;
     RECT  58.921 10.896 59.065 14.232 ;
     RECT  58.693 43.248 59.065 50.568 ;
     RECT  57.881 2.352 59.108 3.432 ;
     RECT  58.489 4.464 59.108 7.464 ;
     RECT  58.273 8.448 59.108 9.672 ;
     RECT  59.065 10.896 59.108 14.424 ;
     RECT  57.917 15.408 59.108 16.68 ;
     RECT  58.957 17.712 59.108 19.848 ;
     RECT  58.117 22.704 59.108 23.352 ;
     RECT  58.949 24.336 59.108 24.36 ;
     RECT  56.704 28.704 59.108 29.304 ;
     RECT  58.273 30.816 59.108 34.776 ;
     RECT  58.813 35.76 59.108 42.264 ;
     RECT  59.065 43.248 59.108 51.432 ;
     RECT  58.849 52.464 59.108 54.072 ;
     RECT  59.108 2.148 59.212 57.792 ;
     RECT  59.212 2.418 59.3 57.792 ;
     RECT  59.3 2.418 59.404 58.062 ;
     RECT  56.257 59.328 59.461 60.408 ;
     RECT  59.404 41.136 59.501 49.608 ;
     RECT  59.404 3.024 59.537 3.432 ;
     RECT  59.404 30.72 59.555 34.488 ;
     RECT  59.501 41.616 59.609 49.608 ;
     RECT  59.404 5.184 59.645 8.472 ;
     RECT  59.609 44.976 59.645 49.608 ;
     RECT  59.461 58.656 59.699 60.408 ;
     RECT  59.645 44.976 59.717 49.512 ;
     RECT  59.555 30.864 59.933 34.488 ;
     RECT  59.699 58.656 59.933 58.68 ;
     RECT  59.404 26.208 59.941 26.232 ;
     RECT  59.609 41.616 59.969 43.848 ;
     RECT  59.404 15.696 60.028 20.952 ;
     RECT  59.699 59.76 60.077 60.408 ;
     RECT  59.537 3.312 60.113 3.432 ;
     RECT  59.645 8.448 60.149 8.472 ;
     RECT  57.449 0.048 60.221 0.072 ;
     RECT  59.404 14.208 60.221 14.424 ;
     RECT  60.077 59.76 60.275 60.36 ;
     RECT  59.404 11.952 60.389 13.128 ;
     RECT  60.221 14.208 60.389 14.232 ;
     RECT  59.404 9.504 60.421 10.92 ;
     RECT  60.389 11.952 60.421 14.232 ;
     RECT  60.421 9.504 60.508 14.232 ;
     RECT  60.028 16.08 60.515 20.952 ;
     RECT  60.275 59.808 60.556 60.36 ;
     RECT  59.933 30.864 60.577 34.2 ;
     RECT  59.404 22.128 60.613 23.112 ;
     RECT  59.404 24.528 60.613 24.744 ;
     RECT  59.404 37.968 60.613 40.152 ;
     RECT  59.969 41.616 60.613 43.368 ;
     RECT  60.556 59.856 60.659 60.36 ;
     RECT  59.404 52.32 60.661 53.832 ;
     RECT  60.515 16.176 60.685 20.952 ;
     RECT  60.577 30.816 60.689 34.2 ;
     RECT  60.685 16.176 60.707 21.096 ;
     RECT  59.717 44.976 60.757 49.368 ;
     RECT  59.645 5.184 60.829 7.08 ;
     RECT  60.757 44.688 60.937 49.368 ;
     RECT  60.661 52.272 60.973 53.832 ;
     RECT  60.829 4.992 61.009 7.08 ;
     RECT  60.707 16.656 61.009 21.096 ;
     RECT  60.613 22.128 61.009 24.744 ;
     RECT  60.689 30.912 61.009 34.2 ;
     RECT  60.659 60 61.091 60.36 ;
     RECT  60.937 44.64 61.297 49.368 ;
     RECT  61.297 44.64 61.429 49.608 ;
     RECT  61.429 44.64 61.477 50.04 ;
     RECT  61.436 51.072 61.477 51.096 ;
     RECT  60.613 37.968 61.549 43.368 ;
     RECT  61.549 37.584 61.621 43.368 ;
     RECT  60.508 11.952 61.657 14.232 ;
     RECT  60.508 9.504 61.669 10.92 ;
     RECT  60.113 3.312 61.693 3.336 ;
     RECT  61.009 4.752 61.693 7.08 ;
     RECT  61.693 3.312 61.801 7.08 ;
     RECT  61.657 11.952 61.801 14.712 ;
     RECT  61.009 16.656 61.801 24.744 ;
     RECT  61.801 3.024 61.808 7.08 ;
     RECT  61.669 8.832 61.808 10.92 ;
     RECT  61.801 11.952 61.808 14.952 ;
     RECT  61.801 16.272 61.808 24.744 ;
     RECT  61.669 27.216 61.808 27.24 ;
     RECT  59.404 28.704 61.808 29.304 ;
     RECT  61.009 30.912 61.808 34.248 ;
     RECT  59.404 35.76 61.808 36.072 ;
     RECT  61.621 37.344 61.808 43.368 ;
     RECT  61.477 44.64 61.808 51.096 ;
     RECT  60.973 52.128 61.808 53.832 ;
     RECT  61.669 58.656 61.808 58.68 ;
     RECT  61.091 60.048 61.811 60.36 ;
     RECT  61.811 60.192 61.907 60.36 ;
     RECT  61.808 2.148 62.104 58.68 ;
     RECT  62.104 49.248 62.201 49.608 ;
     RECT  62.104 33.648 62.245 34.2 ;
     RECT  62.104 50.64 62.309 50.664 ;
     RECT  61.907 60.288 62.339 60.36 ;
     RECT  62.104 58.656 62.345 58.68 ;
     RECT  61.621 0.816 62.377 0.84 ;
     RECT  62.104 15.984 62.561 17.064 ;
     RECT  62.104 35.76 62.561 43.32 ;
     RECT  62.377 0.816 62.593 0.936 ;
     RECT  62.104 2.148 62.593 6.984 ;
     RECT  62.104 18.192 62.597 24.744 ;
     RECT  62.104 30.384 62.597 32.424 ;
     RECT  62.561 40.848 62.705 43.32 ;
     RECT  62.339 60.336 62.705 60.36 ;
     RECT  62.104 10.896 62.741 14.952 ;
     RECT  62.561 35.76 62.813 39.72 ;
     RECT  62.705 40.848 62.832 43.128 ;
     RECT  62.597 18.624 62.885 24.744 ;
     RECT  62.561 15.984 62.921 16.68 ;
     RECT  62.832 41.712 62.921 43.128 ;
     RECT  62.885 18.864 62.957 24.744 ;
     RECT  62.813 37.536 62.963 39.72 ;
     RECT  62.741 10.896 63.029 13.08 ;
     RECT  62.104 44.448 63.029 45.624 ;
     RECT  62.963 37.536 63.037 39.384 ;
     RECT  63.029 12.768 63.065 13.08 ;
     RECT  63.029 10.896 63.097 11.688 ;
     RECT  62.245 34.032 63.097 34.2 ;
     RECT  62.813 35.76 63.097 36.072 ;
     RECT  63.065 12.768 63.101 12.936 ;
     RECT  63.101 12.768 63.137 12.792 ;
     RECT  62.201 49.584 63.137 49.608 ;
     RECT  62.741 14.16 63.209 14.952 ;
     RECT  62.104 46.8 63.241 47.64 ;
     RECT  62.957 18.864 63.245 21.528 ;
     RECT  63.097 34.032 63.251 36.072 ;
     RECT  63.037 37.536 63.251 39.24 ;
     RECT  62.921 15.984 63.281 16.296 ;
     RECT  62.593 0.816 63.313 6.984 ;
     RECT  62.104 8.208 63.313 8.52 ;
     RECT  63.313 0.816 63.349 8.52 ;
     RECT  63.241 46.704 63.397 47.64 ;
     RECT  63.251 34.032 63.421 35.784 ;
     RECT  63.397 46.704 63.484 48.12 ;
     RECT  62.597 30.672 63.589 32.424 ;
     RECT  63.421 33.792 63.589 35.784 ;
     RECT  62.104 28.704 63.637 29.304 ;
     RECT  63.589 30.672 63.637 35.784 ;
     RECT  63.637 28.704 63.817 35.784 ;
     RECT  62.921 43.008 63.932 43.128 ;
     RECT  63.029 44.448 63.932 45.576 ;
     RECT  63.733 50.64 63.961 50.664 ;
     RECT  62.921 41.712 63.973 41.976 ;
     RECT  63.932 43.008 63.973 45.576 ;
     RECT  63.973 41.712 64.069 45.576 ;
     RECT  63.484 46.704 64.069 47.64 ;
     RECT  64.069 12.864 64.285 12.888 ;
     RECT  63.209 14.208 64.285 14.952 ;
     RECT  62.957 22.512 64.316 24.744 ;
     RECT  63.281 16.272 64.357 16.296 ;
     RECT  63.961 17.376 64.357 18.024 ;
     RECT  64.316 22.512 64.357 25.704 ;
     RECT  63.349 0.816 64.508 9.096 ;
     RECT  63.097 10.08 64.508 11.688 ;
     RECT  64.285 12.864 64.508 14.952 ;
     RECT  64.357 16.272 64.508 18.024 ;
     RECT  63.245 19.248 64.508 21.528 ;
     RECT  64.357 22.512 64.508 25.8 ;
     RECT  63.817 27.936 64.508 35.784 ;
     RECT  63.251 37.584 64.508 39.24 ;
     RECT  64.069 41.712 64.508 47.64 ;
     RECT  64.321 49.584 64.508 49.608 ;
     RECT  63.961 50.64 64.508 50.856 ;
     RECT  62.104 51.888 64.508 53.112 ;
     RECT  64.508 0.816 64.7 57.792 ;
     RECT  64.7 0.816 64.717 58.062 ;
     RECT  64.717 0.048 64.804 58.062 ;
     RECT  64.804 0.048 64.865 9.672 ;
     RECT  64.804 52.176 64.931 52.2 ;
     RECT  64.033 60.384 65.005 60.408 ;
     RECT  64.865 0.816 65.009 9.672 ;
     RECT  64.804 24.624 65.045 26.856 ;
     RECT  65.005 60.192 65.045 60.408 ;
     RECT  64.804 10.896 65.081 11.16 ;
     RECT  65.009 2.592 65.153 9.672 ;
     RECT  64.804 27.936 65.189 35.88 ;
     RECT  64.804 12.48 65.261 15.384 ;
     RECT  64.804 40.416 65.315 43.128 ;
     RECT  64.804 44.688 65.333 45.096 ;
     RECT  64.804 46.512 65.459 50.856 ;
     RECT  65.153 2.592 65.477 4.968 ;
     RECT  65.459 46.656 65.5 50.856 ;
     RECT  65.261 12.48 65.513 13.08 ;
     RECT  65.261 14.208 65.555 15.384 ;
     RECT  65.477 2.832 65.585 4.968 ;
     RECT  65.045 60.192 65.645 60.216 ;
     RECT  64.804 16.416 65.747 17.4 ;
     RECT  65.045 24.72 65.795 26.856 ;
     RECT  65.5 46.848 65.795 50.856 ;
     RECT  65.333 44.688 65.891 44.952 ;
     RECT  65.585 2.832 65.909 4.92 ;
     RECT  65.795 25.776 65.909 26.856 ;
     RECT  65.795 50.016 65.932 50.856 ;
     RECT  65.189 31.632 65.941 35.88 ;
     RECT  65.315 40.56 65.977 43.128 ;
     RECT  64.804 18.432 66.037 20.52 ;
     RECT  64.804 21.504 66.037 23.304 ;
     RECT  65.747 17.376 66.121 17.4 ;
     RECT  66.037 18.432 66.121 23.304 ;
     RECT  65.891 44.688 66.157 44.712 ;
     RECT  65.977 40.56 66.197 43.32 ;
     RECT  65.081 10.896 66.265 10.92 ;
     RECT  65.941 31.632 66.301 36.552 ;
     RECT  64.804 37.584 66.301 39.24 ;
     RECT  65.009 0.816 66.409 1.416 ;
     RECT  65.153 6.096 66.445 9.672 ;
     RECT  65.909 26.832 66.445 26.856 ;
     RECT  65.189 27.936 66.445 30.024 ;
     RECT  65.555 14.64 66.481 15.384 ;
     RECT  66.409 0.816 66.517 1.464 ;
     RECT  65.645 59.856 66.521 60.216 ;
     RECT  66.301 31.632 66.524 39.24 ;
     RECT  66.517 0.816 66.661 1.512 ;
     RECT  66.197 40.944 66.661 43.32 ;
     RECT  66.157 44.448 66.661 44.712 ;
     RECT  66.121 17.376 66.697 23.304 ;
     RECT  65.795 24.72 66.697 24.744 ;
     RECT  66.697 17.376 66.877 24.744 ;
     RECT  65.909 25.776 66.877 25.8 ;
     RECT  66.661 0.048 66.949 1.512 ;
     RECT  65.909 2.832 66.949 4.728 ;
     RECT  66.877 17.376 66.949 25.8 ;
     RECT  66.445 26.832 66.949 30.024 ;
     RECT  66.661 40.944 66.949 44.712 ;
     RECT  65.795 46.848 67.021 49.032 ;
     RECT  66.521 60.096 67.021 60.216 ;
     RECT  66.265 10.896 67.093 11.448 ;
     RECT  66.949 17.376 67.093 30.024 ;
     RECT  66.524 31.104 67.093 39.24 ;
     RECT  66.949 0.048 67.129 4.728 ;
     RECT  67.129 0.048 67.165 4.968 ;
     RECT  66.445 6.096 67.165 9.912 ;
     RECT  67.093 10.896 67.201 11.976 ;
     RECT  65.513 13.056 67.201 13.08 ;
     RECT  67.165 0.048 67.208 9.912 ;
     RECT  67.201 10.896 67.208 13.08 ;
     RECT  66.481 14.64 67.208 16.104 ;
     RECT  67.093 17.376 67.208 39.24 ;
     RECT  66.949 40.944 67.208 44.76 ;
     RECT  67.021 46.08 67.208 49.032 ;
     RECT  65.932 50.64 67.208 50.856 ;
     RECT  67.208 0.048 67.4 57.792 ;
     RECT  67.4 0.048 67.504 58.062 ;
     RECT  67.504 19.536 67.565 32.424 ;
     RECT  67.565 27.6 67.619 32.424 ;
     RECT  67.504 0.048 67.637 13.656 ;
     RECT  67.565 19.536 67.673 26.28 ;
     RECT  67.504 34.416 67.673 44.76 ;
     RECT  67.673 34.416 67.817 43.368 ;
     RECT  67.619 31.824 67.852 32.424 ;
     RECT  67.021 60.096 67.861 60.408 ;
     RECT  67.673 19.536 67.889 25.8 ;
     RECT  67.889 23.136 67.961 25.8 ;
     RECT  67.817 41.376 67.969 43.368 ;
     RECT  67.673 44.64 67.997 44.76 ;
     RECT  67.889 19.536 68.213 22.056 ;
     RECT  67.504 48.672 68.285 49.032 ;
     RECT  67.504 14.64 68.291 18.552 ;
     RECT  67.619 27.6 68.387 30.264 ;
     RECT  68.291 14.64 68.465 16.776 ;
     RECT  67.997 44.688 68.629 44.76 ;
     RECT  67.504 45.984 68.629 46.872 ;
     RECT  67.637 13.056 68.636 13.656 ;
     RECT  68.465 14.64 68.636 15.48 ;
     RECT  68.636 13.056 68.641 15.48 ;
     RECT  68.629 44.688 68.675 46.872 ;
     RECT  67.637 0.048 68.677 11.976 ;
     RECT  68.641 13.008 68.677 15.48 ;
     RECT  68.677 0.048 68.723 15.48 ;
     RECT  67.961 23.28 68.753 25.8 ;
     RECT  68.387 27.6 68.753 29.64 ;
     RECT  67.861 59.856 68.771 60.408 ;
     RECT  68.675 44.688 68.789 45.816 ;
     RECT  68.675 46.8 68.857 46.872 ;
     RECT  68.723 0.048 68.915 13.656 ;
     RECT  68.789 44.688 68.965 44.712 ;
     RECT  68.915 0.048 69.005 13.08 ;
     RECT  68.857 46.8 69.205 47.016 ;
     RECT  68.285 48.672 69.205 48.696 ;
     RECT  67.852 31.92 69.289 32.424 ;
     RECT  69.205 46.8 69.397 48.696 ;
     RECT  69.26 50.4 69.445 50.424 ;
     RECT  69.109 30.816 69.541 30.84 ;
     RECT  69.317 58.656 69.541 58.68 ;
     RECT  68.771 59.856 69.541 60.312 ;
     RECT  69.445 50.304 69.637 50.424 ;
     RECT  69.541 30.336 69.644 30.84 ;
     RECT  67.817 34.416 69.733 40.2 ;
     RECT  67.969 41.376 69.733 43.128 ;
     RECT  69.644 30.336 69.749 30.936 ;
     RECT  69.289 31.92 69.749 33 ;
     RECT  69.005 0.144 69.908 13.08 ;
     RECT  68.723 14.64 69.908 15.48 ;
     RECT  68.465 16.752 69.908 16.776 ;
     RECT  68.291 18.528 69.908 18.552 ;
     RECT  68.213 19.536 69.908 21.528 ;
     RECT  68.753 23.28 69.908 23.352 ;
     RECT  68.753 25.104 69.908 25.8 ;
     RECT  68.753 27.6 69.908 29.304 ;
     RECT  69.749 30.336 69.908 33 ;
     RECT  69.733 34.416 69.908 43.128 ;
     RECT  68.965 44.448 69.908 44.712 ;
     RECT  68.789 45.696 69.908 45.816 ;
     RECT  69.397 46.8 69.908 49.032 ;
     RECT  69.637 50.304 69.908 51.144 ;
     RECT  69.541 58.656 69.908 60.312 ;
     RECT  69.908 0.144 70.066 60.312 ;
     RECT  70.066 0.096 70.153 60.312 ;
     RECT  70.153 0.096 70.204 60.408 ;
     RECT  70.204 18.288 70.337 24.12 ;
     RECT  70.204 0.096 70.355 9.528 ;
     RECT  70.204 30.384 70.373 32.52 ;
     RECT  70.355 0.192 70.403 9.528 ;
     RECT  70.403 0.384 70.451 9.528 ;
     RECT  70.204 49.008 70.589 49.272 ;
     RECT  70.337 18.528 70.691 24.12 ;
     RECT  70.204 46.848 70.691 47.928 ;
     RECT  70.204 58.128 70.697 60.408 ;
     RECT  70.589 49.008 70.841 49.032 ;
     RECT  70.204 33.6 70.979 36.552 ;
     RECT  70.204 40.56 70.985 45.48 ;
     RECT  70.204 50.304 71.057 50.712 ;
     RECT  70.204 10.896 71.129 16.584 ;
     RECT  71.129 15.84 71.233 16.584 ;
     RECT  70.691 23.28 71.377 24.12 ;
     RECT  70.204 25.104 71.377 25.8 ;
     RECT  70.985 45.456 71.377 45.48 ;
     RECT  70.979 34.176 71.413 36.552 ;
     RECT  70.204 37.584 71.413 39.24 ;
     RECT  70.451 0.528 71.521 9.528 ;
     RECT  70.204 27.888 71.525 29.304 ;
     RECT  70.373 31.104 71.557 32.52 ;
     RECT  70.985 40.56 71.597 44.232 ;
     RECT  71.413 34.176 71.653 39.24 ;
     RECT  71.597 40.56 71.653 40.92 ;
     RECT  71.521 0.528 71.701 9.672 ;
     RECT  70.691 18.528 71.701 21.528 ;
     RECT  71.701 0.24 71.737 9.672 ;
     RECT  71.129 10.896 71.737 14.856 ;
     RECT  70.691 46.896 71.737 47.928 ;
     RECT  71.525 27.936 71.809 29.304 ;
     RECT  71.557 31.104 72.169 33.096 ;
     RECT  72.169 31.104 72.241 33.144 ;
     RECT  71.653 34.176 72.241 40.92 ;
     RECT  71.377 45.456 72.241 45.816 ;
     RECT  71.737 46.896 72.241 48.504 ;
     RECT  71.597 41.904 72.284 44.232 ;
     RECT  72.241 45.456 72.284 48.504 ;
     RECT  71.737 0.24 72.373 14.856 ;
     RECT  72.373 0.192 72.469 14.856 ;
     RECT  72.469 0.144 72.608 14.856 ;
     RECT  71.233 15.84 72.608 16.68 ;
     RECT  71.701 18.192 72.608 21.528 ;
     RECT  71.377 23.28 72.608 25.8 ;
     RECT  71.809 27.936 72.608 30.12 ;
     RECT  72.241 31.104 72.608 40.92 ;
     RECT  72.284 41.904 72.608 48.504 ;
     RECT  71.057 50.304 72.608 50.328 ;
     RECT  71.485 53.568 72.608 53.592 ;
     RECT  70.697 58.368 72.608 60.408 ;
     RECT  72.608 0.144 72.904 60.408 ;
     RECT  72.904 0.144 72.947 1.464 ;
     RECT  72.904 12.384 72.965 14.52 ;
     RECT  72.904 2.496 73.037 11.208 ;
     RECT  72.904 58.944 73.043 60.408 ;
     RECT  72.904 26.784 73.073 39.624 ;
     RECT  72.947 0.144 73.277 1.272 ;
     RECT  73.073 26.784 73.523 39.384 ;
     RECT  73.037 2.496 73.577 9.816 ;
     RECT  73.577 2.496 73.715 9.24 ;
     RECT  73.715 8.496 73.757 9.24 ;
     RECT  72.904 46.896 73.757 50.328 ;
     RECT  72.904 43.296 73.763 45.816 ;
     RECT  72.965 12.384 73.829 14.136 ;
     RECT  73.829 13.536 73.852 14.136 ;
     RECT  73.043 58.944 73.859 59.64 ;
     RECT  72.904 20.352 73.865 25.8 ;
     RECT  73.523 26.784 73.865 27.96 ;
     RECT  73.037 10.848 73.907 11.208 ;
     RECT  73.277 0.096 73.925 1.272 ;
     RECT  73.715 2.496 73.925 7.176 ;
     RECT  73.523 29.184 73.937 39.384 ;
     RECT  73.907 11.184 74.005 11.208 ;
     RECT  72.904 15.84 74.005 17.592 ;
     RECT  73.865 20.352 74.045 23.112 ;
     RECT  74.005 15.84 74.089 18.216 ;
     RECT  73.757 46.896 74.147 49.512 ;
     RECT  74.005 11.184 74.149 11.4 ;
     RECT  73.829 12.384 74.149 12.504 ;
     RECT  73.852 14.112 74.185 14.136 ;
     RECT  74.089 17.904 74.185 18.216 ;
     RECT  72.904 40.848 74.185 42.264 ;
     RECT  73.763 43.296 74.185 43.56 ;
     RECT  73.865 24.096 74.225 25.8 ;
     RECT  74.045 20.352 74.257 22.824 ;
     RECT  73.925 0.096 74.297 7.176 ;
     RECT  73.937 31.104 74.329 39.384 ;
     RECT  74.185 40.848 74.329 43.56 ;
     RECT  74.147 46.896 74.365 47.688 ;
     RECT  74.185 17.904 74.629 18.84 ;
     RECT  74.257 19.824 74.629 22.824 ;
     RECT  74.185 14.112 74.653 14.712 ;
     RECT  74.089 15.84 74.653 16.392 ;
     RECT  73.763 45.168 74.821 45.192 ;
     RECT  74.365 46.608 74.821 47.688 ;
     RECT  73.757 8.496 74.833 8.52 ;
     RECT  73.859 58.944 74.873 59.592 ;
     RECT  74.833 8.496 74.965 9 ;
     RECT  74.629 17.904 75.02 22.824 ;
     RECT  74.873 59.568 75.053 59.592 ;
     RECT  74.965 8.496 75.109 9.048 ;
     RECT  74.297 0.144 75.308 7.176 ;
     RECT  75.109 8.256 75.308 9.048 ;
     RECT  74.149 11.184 75.308 12.504 ;
     RECT  74.653 14.112 75.308 16.392 ;
     RECT  75.02 17.904 75.308 23.304 ;
     RECT  74.225 24.816 75.308 25.8 ;
     RECT  73.865 27.696 75.308 27.96 ;
     RECT  73.937 29.184 75.308 29.544 ;
     RECT  74.329 31.104 75.308 43.56 ;
     RECT  74.821 45.168 75.308 47.688 ;
     RECT  74.147 49.008 75.308 49.512 ;
     RECT  75.308 0.144 75.373 57.792 ;
     RECT  75.373 0.048 75.5 57.792 ;
     RECT  75.5 0.048 75.604 58.062 ;
     RECT  75.604 20.16 75.731 30.888 ;
     RECT  75.604 14.208 75.773 19.032 ;
     RECT  75.604 10.752 75.779 13.032 ;
     RECT  75.604 0.048 75.827 9.624 ;
     RECT  75.779 10.752 75.827 10.92 ;
     RECT  75.731 20.16 75.827 29.256 ;
     RECT  75.827 20.64 75.923 29.256 ;
     RECT  75.923 20.64 75.989 22.824 ;
     RECT  75.604 44.592 75.989 47.736 ;
     RECT  75.989 44.592 76.019 45.912 ;
     RECT  75.989 22.752 76.025 22.824 ;
     RECT  75.604 49.152 76.025 50.184 ;
     RECT  75.827 0.048 76.067 8.376 ;
     RECT  75.827 10.752 76.097 10.824 ;
     RECT  75.923 24.096 76.133 29.256 ;
     RECT  76.025 49.152 76.277 49.56 ;
     RECT  76.133 24.432 76.349 29.256 ;
     RECT  75.604 32.016 76.403 43.32 ;
     RECT  76.403 42.432 76.529 43.32 ;
     RECT  75.773 14.208 76.673 18.936 ;
     RECT  76.349 25.104 76.673 29.256 ;
     RECT  75.779 11.952 76.741 13.032 ;
     RECT  75.827 9.6 76.745 9.624 ;
     RECT  76.097 10.8 76.813 10.824 ;
     RECT  76.741 11.952 76.813 13.08 ;
     RECT  76.277 49.536 76.853 49.56 ;
     RECT  75.989 20.64 76.889 21.528 ;
     RECT  76.403 32.016 76.889 40.968 ;
     RECT  76.813 10.8 76.961 13.08 ;
     RECT  76.025 22.752 76.961 22.776 ;
     RECT  76.673 25.2 76.961 29.256 ;
     RECT  76.889 34.656 76.961 40.968 ;
     RECT  75.731 30.24 76.993 30.888 ;
     RECT  76.889 32.016 76.993 33.672 ;
     RECT  76.993 30.24 76.997 33.672 ;
     RECT  76.961 10.8 77.033 12.216 ;
     RECT  76.019 45.696 77.137 45.912 ;
     RECT  75.989 47.376 77.137 47.736 ;
     RECT  77.137 45.696 77.209 47.736 ;
     RECT  77.209 45.696 77.245 48.504 ;
     RECT  76.529 42.72 77.281 43.32 ;
     RECT  76.961 29.04 77.425 29.256 ;
     RECT  76.997 30.24 77.425 30.36 ;
     RECT  77.245 44.976 77.425 48.504 ;
     RECT  76.067 7.152 77.461 8.376 ;
     RECT  77.461 7.152 77.569 8.472 ;
     RECT  77.425 44.736 77.612 48.504 ;
     RECT  76.067 0.048 77.641 6.168 ;
     RECT  77.569 7.152 77.641 9.096 ;
     RECT  77.612 44.736 77.641 49.176 ;
     RECT  77.033 10.8 77.677 11.784 ;
     RECT  77.281 42.72 77.713 43.368 ;
     RECT  77.641 44.352 77.713 49.176 ;
     RECT  77.605 60.384 77.825 60.408 ;
     RECT  77.641 0.048 78.008 9.096 ;
     RECT  77.677 10.608 78.008 11.784 ;
     RECT  77.965 12.768 78.008 12.792 ;
     RECT  76.673 14.208 78.008 17.928 ;
     RECT  77.245 19.536 78.008 19.56 ;
     RECT  76.889 20.976 78.008 21.528 ;
     RECT  78.001 23.136 78.008 23.16 ;
     RECT  76.961 25.2 78.008 28.008 ;
     RECT  77.425 29.04 78.008 30.36 ;
     RECT  76.997 31.392 78.008 33.672 ;
     RECT  76.961 34.704 78.008 40.968 ;
     RECT  77.713 42.72 78.008 49.176 ;
     RECT  77.653 50.256 78.008 50.28 ;
     RECT  77.821 58.368 78.008 58.392 ;
     RECT  78.008 0.048 78.293 58.392 ;
     RECT  78.293 2.256 78.304 58.392 ;
     RECT  78.304 25.44 78.401 28.008 ;
     RECT  78.304 23.136 78.419 24.12 ;
     RECT  78.419 23.952 78.473 24.12 ;
     RECT  78.401 25.44 78.509 26.28 ;
     RECT  78.304 28.992 78.515 41.448 ;
     RECT  78.515 28.992 78.652 39.288 ;
     RECT  78.304 2.256 78.653 6.072 ;
     RECT  78.509 25.44 78.659 25.8 ;
     RECT  78.652 28.992 78.659 30.456 ;
     RECT  78.515 40.416 78.659 41.448 ;
     RECT  78.652 31.824 78.725 39.288 ;
     RECT  78.304 44.352 78.725 44.712 ;
     RECT  78.725 44.448 78.797 44.712 ;
     RECT  78.725 31.824 78.833 39.096 ;
     RECT  78.797 44.448 78.941 44.472 ;
     RECT  78.653 2.256 78.977 5.208 ;
     RECT  78.304 7.104 79.121 9.096 ;
     RECT  78.659 41.04 79.139 41.448 ;
     RECT  78.659 29.04 79.229 30.456 ;
     RECT  78.304 15.504 79.265 17.112 ;
     RECT  78.401 27.936 79.301 28.008 ;
     RECT  79.121 7.152 79.333 9.096 ;
     RECT  77.929 59.52 79.441 59.544 ;
     RECT  78.304 10.608 79.445 13.704 ;
     RECT  79.333 7.152 79.517 9.144 ;
     RECT  78.304 47.328 79.517 49.032 ;
     RECT  79.229 29.04 79.553 30.408 ;
     RECT  79.441 59.52 79.589 60.408 ;
     RECT  78.293 0.048 79.625 1.272 ;
     RECT  78.977 2.256 79.661 5.16 ;
     RECT  79.445 10.608 79.715 13.32 ;
     RECT  79.301 27.936 79.724 27.96 ;
     RECT  79.517 7.344 79.729 9.144 ;
     RECT  79.553 29.04 79.733 30.36 ;
     RECT  79.625 1.248 79.769 1.272 ;
     RECT  79.517 47.376 79.772 49.032 ;
     RECT  79.729 7.344 79.801 9.576 ;
     RECT  79.801 7.344 79.813 9.624 ;
     RECT  79.715 10.608 79.813 13.224 ;
     RECT  78.473 24.096 80.012 24.12 ;
     RECT  78.659 25.776 80.012 25.8 ;
     RECT  79.625 0.048 80.057 0.12 ;
     RECT  80.012 24.096 80.089 25.8 ;
     RECT  79.265 15.888 80.125 17.112 ;
     RECT  78.304 18.144 80.125 22.152 ;
     RECT  79.724 27.312 80.149 27.96 ;
     RECT  78.304 45.696 80.245 46.104 ;
     RECT  78.833 32.016 80.305 39.096 ;
     RECT  80.057 0.048 80.309 0.072 ;
     RECT  80.161 14.736 80.449 14.76 ;
     RECT  80.125 15.888 80.449 22.152 ;
     RECT  80.305 31.92 80.549 39.096 ;
     RECT  80.149 27.216 80.593 27.96 ;
     RECT  79.661 2.496 80.708 5.16 ;
     RECT  79.813 7.344 80.708 13.224 ;
     RECT  80.449 14.736 80.708 22.152 ;
     RECT  80.089 23.136 80.708 25.8 ;
     RECT  80.593 27.216 80.708 28.008 ;
     RECT  79.733 29.04 80.708 30.072 ;
     RECT  80.549 31.296 80.708 39.096 ;
     RECT  79.139 41.04 80.708 41.4 ;
     RECT  78.304 42.72 80.708 42.744 ;
     RECT  80.245 45.552 80.708 46.104 ;
     RECT  79.772 47.376 80.708 49.704 ;
     RECT  78.304 58.368 80.708 58.392 ;
     RECT  80.708 2.148 80.812 58.392 ;
     RECT  80.812 2.418 81.004 58.392 ;
     RECT  81.004 27.984 81.065 38.28 ;
     RECT  81.004 40.416 81.065 41.784 ;
     RECT  81.004 17.616 81.101 24.072 ;
     RECT  81.004 7.344 81.155 8.568 ;
     RECT  81.004 43.008 81.155 43.32 ;
     RECT  81.004 9.6 81.173 9.96 ;
     RECT  81.004 47.136 81.209 48.888 ;
     RECT  81.209 48.576 81.244 48.888 ;
     RECT  81.004 2.418 81.491 3.864 ;
     RECT  81.101 19.776 81.779 24.072 ;
     RECT  81.065 30.432 81.857 38.28 ;
     RECT  81.065 27.984 81.901 29.112 ;
     RECT  79.589 59.52 81.923 59.544 ;
     RECT  81.004 25.776 82.033 25.8 ;
     RECT  81.004 26.784 82.033 26.808 ;
     RECT  81.857 31.152 82.033 38.28 ;
     RECT  81.065 41.376 82.033 41.784 ;
     RECT  81.004 4.944 82.061 5.208 ;
     RECT  81.004 6.288 82.061 6.312 ;
     RECT  81.004 12.96 82.069 13.368 ;
     RECT  81.004 14.352 82.069 15.048 ;
     RECT  81.779 20.592 82.105 24.072 ;
     RECT  82.033 25.776 82.105 26.808 ;
     RECT  81.004 11.184 82.141 11.976 ;
     RECT  82.069 12.96 82.141 15.048 ;
     RECT  82.105 20.592 82.141 24.648 ;
     RECT  82.105 25.776 82.141 26.904 ;
     RECT  82.061 4.944 82.145 6.312 ;
     RECT  81.901 27.984 82.145 29.064 ;
     RECT  81.209 47.472 82.181 47.496 ;
     RECT  82.033 31.152 82.249 38.472 ;
     RECT  82.141 20.592 82.253 26.904 ;
     RECT  82.249 31.152 82.285 39.336 ;
     RECT  81.155 7.344 82.321 8.52 ;
     RECT  82.033 41.28 82.357 41.784 ;
     RECT  81.101 17.616 82.393 18.024 ;
     RECT  82.357 40.992 82.444 42.12 ;
     RECT  82.321 6.336 82.537 8.52 ;
     RECT  81.173 9.792 82.537 9.96 ;
     RECT  82.253 23.136 82.717 26.904 ;
     RECT  82.393 17.616 82.825 18.36 ;
     RECT  81.491 3.312 82.897 3.864 ;
     RECT  82.145 4.944 82.897 5.208 ;
     RECT  82.141 11.184 82.933 15.048 ;
     RECT  81.853 2.256 82.969 2.28 ;
     RECT  82.897 3.312 82.969 5.208 ;
     RECT  81.004 45.216 82.969 45.816 ;
     RECT  81.244 48.576 83.005 48.6 ;
     RECT  83.005 48.576 83.036 49.32 ;
     RECT  83.084 60.384 83.171 60.408 ;
     RECT  82.444 41.088 83.173 42.12 ;
     RECT  82.933 11.184 83.221 15.144 ;
     RECT  83.173 41.088 83.221 42.216 ;
     RECT  82.537 6.336 83.257 9.96 ;
     RECT  82.717 23.136 83.269 27.432 ;
     RECT  82.145 28.512 83.269 29.064 ;
     RECT  83.257 6.24 83.293 9.96 ;
     RECT  83.221 11.184 83.293 15.24 ;
     RECT  82.825 16.896 83.329 18.36 ;
     RECT  82.969 44.352 83.365 45.816 ;
     RECT  83.221 47.04 83.365 47.064 ;
     RECT  82.969 2.256 83.408 5.208 ;
     RECT  83.293 6.24 83.408 15.24 ;
     RECT  83.329 16.896 83.408 18.84 ;
     RECT  82.253 20.592 83.408 22.104 ;
     RECT  83.269 23.136 83.408 29.064 ;
     RECT  83.149 30.144 83.408 30.168 ;
     RECT  82.285 31.152 83.408 39.816 ;
     RECT  83.221 41.088 83.408 42.312 ;
     RECT  81.155 43.296 83.408 43.32 ;
     RECT  83.365 44.352 83.408 47.064 ;
     RECT  83.036 48.576 83.408 50.28 ;
     RECT  81.004 58.368 83.408 58.392 ;
     RECT  83.408 2.148 83.512 58.392 ;
     RECT  83.512 2.208 83.704 58.392 ;
     RECT  83.704 23.664 83.765 24.648 ;
     RECT  83.704 31.92 83.909 43.944 ;
     RECT  83.909 31.92 83.987 42.936 ;
     RECT  83.704 30.144 84.035 30.792 ;
     RECT  83.987 31.92 84.269 39.912 ;
     RECT  83.704 9.6 84.341 11.448 ;
     RECT  83.987 41.04 84.521 42.936 ;
     RECT  84.341 10.704 84.557 11.448 ;
     RECT  84.269 39.792 84.557 39.912 ;
     RECT  84.521 41.232 84.593 42.936 ;
     RECT  83.704 45.408 84.593 46.632 ;
     RECT  83.909 43.92 84.637 43.944 ;
     RECT  83.704 48.864 84.659 50.04 ;
     RECT  83.704 18.192 84.665 18.84 ;
     RECT  84.593 45.408 84.697 46.344 ;
     RECT  83.704 25.68 84.7 27.48 ;
     RECT  84.557 11.424 84.733 11.448 ;
     RECT  83.704 19.968 84.733 22.248 ;
     RECT  83.704 28.512 84.805 29.064 ;
     RECT  84.035 30.144 84.805 30.456 ;
     RECT  83.704 15.024 84.877 16.92 ;
     RECT  83.704 47.616 84.877 47.64 ;
     RECT  84.659 48.864 84.877 49.032 ;
     RECT  84.877 14.784 84.901 16.92 ;
     RECT  84.901 14.784 84.908 17.112 ;
     RECT  84.665 18.192 84.908 18.216 ;
     RECT  84.877 47.616 84.949 49.032 ;
     RECT  84.805 28.512 84.953 30.456 ;
     RECT  83.704 13.344 84.985 13.368 ;
     RECT  84.908 14.784 84.985 18.216 ;
     RECT  83.704 2.208 84.989 8.52 ;
     RECT  84.697 44.928 84.997 46.344 ;
     RECT  84.997 44.928 85.097 45.72 ;
     RECT  84.989 2.352 85.133 8.52 ;
     RECT  84.269 31.92 85.237 38.568 ;
     RECT  84.341 9.6 85.561 9.624 ;
     RECT  85.133 8.496 85.705 8.52 ;
     RECT  85.561 9.6 85.705 9.816 ;
     RECT  84.7 25.68 85.705 27.048 ;
     RECT  83.905 0.048 85.709 0.072 ;
     RECT  84.557 39.792 85.717 39.816 ;
     RECT  84.593 41.232 85.717 42.744 ;
     RECT  85.717 41.232 85.741 43.272 ;
     RECT  84.733 19.2 85.849 22.248 ;
     RECT  85.237 31.296 85.957 38.568 ;
     RECT  85.717 39.6 85.957 39.816 ;
     RECT  84.953 28.512 86.101 30.216 ;
     RECT  85.957 31.296 86.101 39.816 ;
     RECT  85.133 2.352 86.108 7.464 ;
     RECT  85.705 8.496 86.108 9.816 ;
     RECT  84.733 11.424 86.108 12.36 ;
     RECT  84.985 13.344 86.108 18.216 ;
     RECT  85.849 19.2 86.108 22.776 ;
     RECT  83.765 24.096 86.108 24.12 ;
     RECT  85.705 25.536 86.108 27.048 ;
     RECT  86.101 28.512 86.108 39.816 ;
     RECT  85.741 41.232 86.108 44.376 ;
     RECT  85.097 45.504 86.108 45.72 ;
     RECT  84.949 47.328 86.108 49.032 ;
     RECT  83.704 58.368 86.108 58.392 ;
     RECT  86.108 2.148 86.212 58.392 ;
     RECT  86.212 2.304 86.404 58.392 ;
     RECT  86.404 37.488 86.465 39.816 ;
     RECT  86.404 30.672 86.531 35.928 ;
     RECT  86.404 41.04 86.531 45.528 ;
     RECT  86.404 2.304 86.573 5.688 ;
     RECT  86.404 21.168 86.573 24.12 ;
     RECT  86.404 17.616 86.609 19.368 ;
     RECT  86.404 6.672 86.675 9.384 ;
     RECT  86.137 0.192 86.725 0.216 ;
     RECT  86.404 10.656 86.825 16.344 ;
     RECT  86.465 37.488 86.897 39.624 ;
     RECT  86.897 37.488 86.933 38.28 ;
     RECT  86.404 27.216 87.005 29.64 ;
     RECT  86.531 41.04 87.005 42.264 ;
     RECT  86.825 11.04 87.011 16.344 ;
     RECT  87.011 14.592 87.041 16.344 ;
     RECT  86.531 31.296 87.077 35.928 ;
     RECT  86.725 0.096 87.109 0.216 ;
     RECT  87.041 14.592 87.113 15.576 ;
     RECT  86.531 43.344 87.149 45.528 ;
     RECT  87.005 27.216 87.203 29.064 ;
     RECT  86.573 2.304 87.205 3.432 ;
     RECT  86.404 25.536 87.221 25.56 ;
     RECT  87.149 43.536 87.221 45.528 ;
     RECT  87.077 31.296 87.229 33.048 ;
     RECT  87.109 0.096 87.257 0.264 ;
     RECT  87.011 11.04 87.293 13.368 ;
     RECT  87.005 41.856 87.329 42.264 ;
     RECT  87.229 31.392 87.401 33.048 ;
     RECT  87.077 34.368 87.401 35.928 ;
     RECT  86.573 4.656 87.469 5.688 ;
     RECT  86.675 6.672 87.469 8.52 ;
     RECT  87.221 45.264 87.473 45.528 ;
     RECT  87.257 0.144 87.589 0.264 ;
     RECT  87.113 14.64 87.617 15.576 ;
     RECT  87.473 45.456 87.617 45.528 ;
     RECT  86.573 21.168 87.685 22.776 ;
     RECT  86.609 17.616 87.721 17.64 ;
     RECT  87.469 4.656 87.757 8.52 ;
     RECT  86.573 24.096 87.793 24.12 ;
     RECT  87.685 20.496 87.829 22.776 ;
     RECT  87.589 0.144 87.865 0.6 ;
     RECT  87.205 1.728 87.865 3.432 ;
     RECT  87.865 0.144 87.877 3.432 ;
     RECT  86.897 39.6 87.925 39.624 ;
     RECT  86.609 18.816 87.973 19.368 ;
     RECT  87.829 20.496 87.973 22.872 ;
     RECT  87.793 24.096 87.973 24.216 ;
     RECT  86.933 37.968 88.021 38.28 ;
     RECT  87.925 39.6 88.021 40.488 ;
     RECT  87.721 17.376 88.045 17.64 ;
     RECT  88.045 16.656 88.117 17.64 ;
     RECT  87.973 18.816 88.117 24.216 ;
     RECT  87.901 59.856 88.145 59.88 ;
     RECT  87.877 0.144 88.153 3.672 ;
     RECT  87.757 4.656 88.153 9.048 ;
     RECT  87.203 29.04 88.153 29.064 ;
     RECT  87.433 30.288 88.153 30.312 ;
     RECT  87.617 15.024 88.189 15.576 ;
     RECT  88.117 16.656 88.189 24.216 ;
     RECT  87.829 26.016 88.213 26.232 ;
     RECT  87.203 27.888 88.225 27.912 ;
     RECT  86.404 58.368 88.225 58.392 ;
     RECT  88.145 59.856 88.229 60.36 ;
     RECT  88.225 27.408 88.261 27.912 ;
     RECT  88.153 29.04 88.261 30.312 ;
     RECT  87.329 42.192 88.297 42.264 ;
     RECT  88.153 0.144 88.305 9.048 ;
     RECT  88.261 27.408 88.309 30.312 ;
     RECT  87.401 31.392 88.309 32.856 ;
     RECT  88.297 41.712 88.325 42.264 ;
     RECT  87.221 43.536 88.325 43.848 ;
     RECT  88.305 0.144 88.441 9.384 ;
     RECT  88.225 58.128 88.453 58.392 ;
     RECT  88.021 37.968 88.693 40.68 ;
     RECT  88.325 41.712 88.693 43.848 ;
     RECT  87.617 45.504 88.693 45.528 ;
     RECT  88.693 45.024 88.765 45.528 ;
     RECT  88.441 0.096 88.808 9.384 ;
     RECT  88.556 10.896 88.808 10.92 ;
     RECT  87.293 11.952 88.808 13.368 ;
     RECT  88.189 15.024 88.808 24.216 ;
     RECT  88.213 25.872 88.808 26.232 ;
     RECT  88.309 27.408 88.808 32.856 ;
     RECT  87.401 34.368 88.808 35.832 ;
     RECT  88.693 37.968 88.808 43.848 ;
     RECT  88.765 45.024 88.808 45.576 ;
     RECT  88.453 58.128 88.808 58.68 ;
     RECT  88.808 0.096 88.837 58.68 ;
     RECT  88.229 59.856 88.837 60.312 ;
     RECT  88.837 0.096 89.104 60.312 ;
     RECT  89.104 29.616 89.165 33.288 ;
     RECT  89.104 39.216 89.219 42.504 ;
     RECT  89.104 34.368 89.411 37.608 ;
     RECT  89.219 39.6 89.411 42.504 ;
     RECT  89.411 39.6 89.507 41.496 ;
     RECT  89.104 24.672 89.525 26.088 ;
     RECT  89.104 0.096 89.597 7.464 ;
     RECT  89.411 34.368 89.633 36.696 ;
     RECT  89.104 8.496 89.705 16.056 ;
     RECT  89.507 39.744 89.705 41.496 ;
     RECT  89.104 58.368 89.737 60.312 ;
     RECT  89.705 8.496 89.741 14.136 ;
     RECT  89.104 27.072 89.836 27.336 ;
     RECT  89.104 17.088 89.843 18.216 ;
     RECT  89.741 9.456 89.849 14.136 ;
     RECT  89.104 28.416 90.085 28.44 ;
     RECT  89.165 29.616 90.085 30.216 ;
     RECT  89.843 18.192 90.101 18.216 ;
     RECT  89.104 19.872 90.101 20.184 ;
     RECT  90.085 28.416 90.236 30.216 ;
     RECT  89.165 31.776 90.236 33.288 ;
     RECT  90.236 28.416 90.277 33.288 ;
     RECT  89.633 34.368 90.277 35.928 ;
     RECT  89.104 43.92 90.281 45.576 ;
     RECT  90.277 28.416 90.323 35.928 ;
     RECT  89.104 21.168 90.349 23.304 ;
     RECT  90.236 19.344 90.421 19.608 ;
     RECT  90.281 44.304 90.421 45.576 ;
     RECT  90.277 46.896 90.421 46.92 ;
     RECT  89.705 39.744 90.425 40.632 ;
     RECT  89.705 15.408 90.457 16.056 ;
     RECT  90.421 44.304 90.467 46.92 ;
     RECT  89.597 6.96 90.493 7.464 ;
     RECT  90.349 21.024 90.497 23.304 ;
     RECT  89.411 42.48 90.565 42.504 ;
     RECT  89.849 10.512 90.757 14.136 ;
     RECT  90.457 15.408 90.757 16.152 ;
     RECT  89.597 0.096 90.781 5.64 ;
     RECT  90.493 6.96 90.781 7.992 ;
     RECT  90.637 37.104 90.781 37.128 ;
     RECT  90.565 42.144 90.817 42.504 ;
     RECT  89.836 27.072 90.901 27.096 ;
     RECT  89.737 58.368 90.929 60.36 ;
     RECT  90.929 58.368 90.947 59.88 ;
     RECT  90.901 27.072 90.949 27.192 ;
     RECT  90.781 0.096 90.961 7.992 ;
     RECT  89.525 25.584 90.997 26.088 ;
     RECT  90.781 37.104 91.033 37.608 ;
     RECT  90.421 18.48 91.105 19.608 ;
     RECT  91.033 37.104 91.141 38.52 ;
     RECT  90.425 39.744 91.141 40.584 ;
     RECT  90.757 10.512 91.249 16.152 ;
     RECT  90.817 42.144 91.249 42.6 ;
     RECT  90.961 0.096 91.289 8.472 ;
     RECT  90.497 21.168 91.381 23.304 ;
     RECT  91.289 2.016 91.501 8.472 ;
     RECT  89.849 9.456 91.501 9.48 ;
     RECT  91.501 2.016 91.508 9.48 ;
     RECT  91.249 10.512 91.508 16.632 ;
     RECT  91.105 18.48 91.508 19.8 ;
     RECT  91.381 21.168 91.508 23.88 ;
     RECT  90.997 25.008 91.508 26.088 ;
     RECT  90.949 27.072 91.508 27.336 ;
     RECT  90.323 28.416 91.508 30.168 ;
     RECT  90.323 31.536 91.508 35.928 ;
     RECT  91.141 37.104 91.508 40.584 ;
     RECT  91.249 41.664 91.508 42.6 ;
     RECT  90.467 44.304 91.508 46.104 ;
     RECT  91.045 53.376 91.508 53.4 ;
     RECT  90.947 58.368 91.508 59.544 ;
     RECT  91.508 2.016 91.804 59.544 ;
     RECT  91.289 0.096 91.865 0.888 ;
     RECT  91.804 36.864 91.901 39.768 ;
     RECT  91.804 14.736 91.955 16.632 ;
     RECT  91.804 2.016 91.973 4.68 ;
     RECT  91.804 21.168 91.973 23.304 ;
     RECT  91.901 36.864 92.009 37.128 ;
     RECT  91.804 45.168 92.009 45.432 ;
     RECT  91.804 17.808 92.051 20.04 ;
     RECT  91.901 38.448 92.081 39.768 ;
     RECT  92.081 38.496 92.153 39.768 ;
     RECT  91.865 0.096 92.189 0.84 ;
     RECT  91.804 25.008 92.189 29.304 ;
     RECT  92.189 0.096 92.225 0.216 ;
     RECT  92.009 36.864 92.261 37.08 ;
     RECT  91.804 58.368 92.339 59.544 ;
     RECT  91.804 41.664 92.369 43.704 ;
     RECT  91.804 5.712 92.513 13.32 ;
     RECT  91.973 21.6 92.513 23.304 ;
     RECT  92.369 42.72 92.513 43.704 ;
     RECT  92.153 38.736 92.541 39.768 ;
     RECT  92.189 25.008 92.549 25.032 ;
     RECT  91.973 2.352 92.729 4.68 ;
     RECT  92.513 42.816 92.729 43.704 ;
     RECT  92.051 18.144 92.812 20.04 ;
     RECT  92.513 11.376 92.867 13.32 ;
     RECT  92.867 11.616 92.873 13.32 ;
     RECT  92.873 11.616 92.908 13.032 ;
     RECT  92.541 38.736 92.945 38.76 ;
     RECT  91.804 30.96 92.977 35.688 ;
     RECT  92.261 36.864 92.977 37.032 ;
     RECT  91.955 14.832 93.049 16.632 ;
     RECT  92.812 18.144 93.049 19.512 ;
     RECT  92.189 26.064 93.089 29.304 ;
     RECT  92.729 43.392 93.157 43.704 ;
     RECT  92.009 45.408 93.157 45.432 ;
     RECT  92.513 21.6 93.161 22.824 ;
     RECT  93.157 43.392 93.197 45.432 ;
     RECT  93.049 14.832 93.233 19.512 ;
     RECT  92.977 30.96 93.233 37.032 ;
     RECT  92.225 0.192 93.269 0.216 ;
     RECT  92.729 3.84 93.373 4.68 ;
     RECT  92.513 5.712 93.373 10.104 ;
     RECT  93.373 3.84 93.553 10.104 ;
     RECT  92.941 23.856 93.596 23.88 ;
     RECT  93.596 23.856 93.637 24.504 ;
     RECT  93.089 26.064 93.637 26.088 ;
     RECT  93.553 3.84 93.913 10.344 ;
     RECT  92.908 11.616 93.913 12.504 ;
     RECT  93.161 21.696 93.973 22.824 ;
     RECT  93.637 23.856 93.973 26.088 ;
     RECT  93.089 27.072 94.069 29.304 ;
     RECT  93.233 30.96 94.069 35.736 ;
     RECT  92.729 2.352 94.208 2.376 ;
     RECT  93.913 3.84 94.208 12.504 ;
     RECT  93.233 14.832 94.208 18.888 ;
     RECT  94.201 19.872 94.208 19.896 ;
     RECT  93.973 21.696 94.208 26.088 ;
     RECT  94.069 27.072 94.208 35.736 ;
     RECT  93.233 37.008 94.208 37.032 ;
     RECT  92.541 39.744 94.208 39.768 ;
     RECT  92.369 41.664 94.208 41.688 ;
     RECT  93.197 43.392 94.208 44.712 ;
     RECT  94.208 2.148 94.312 57.792 ;
     RECT  94.312 2.418 94.4 57.792 ;
     RECT  92.339 58.944 94.4 59.544 ;
     RECT  94.4 2.418 94.504 59.544 ;
     RECT  94.504 39.744 94.78 42.408 ;
     RECT  94.504 9.744 94.817 14.232 ;
     RECT  94.78 39.744 94.817 42.168 ;
     RECT  94.633 0.096 94.849 0.12 ;
     RECT  94.817 10.992 94.889 14.232 ;
     RECT  94.504 43.392 94.925 43.656 ;
     RECT  94.925 43.392 94.961 43.416 ;
     RECT  94.817 39.744 94.979 41.016 ;
     RECT  94.979 39.744 94.997 40.68 ;
     RECT  94.997 39.84 95.005 40.68 ;
     RECT  94.504 15.456 95.069 15.576 ;
     RECT  94.504 44.688 95.141 44.712 ;
     RECT  94.504 21.744 95.171 24.6 ;
     RECT  94.504 19.872 95.213 20.52 ;
     RECT  95.171 22.224 95.285 24.6 ;
     RECT  94.504 25.824 95.285 38.28 ;
     RECT  95.285 24.576 95.308 24.6 ;
     RECT  94.889 10.992 95.429 13.656 ;
     RECT  94.817 42.144 95.465 42.168 ;
     RECT  94.504 18.24 95.533 18.552 ;
     RECT  95.213 19.872 95.533 20.184 ;
     RECT  95.285 22.224 95.681 23.592 ;
     RECT  94.504 3.408 95.825 3.912 ;
     RECT  95.281 2.304 95.929 2.328 ;
     RECT  95.929 2.304 95.965 2.376 ;
     RECT  95.825 3.408 95.965 3.528 ;
     RECT  94.504 58.944 96.005 59.544 ;
     RECT  94.504 16.896 96.217 16.92 ;
     RECT  95.533 18.24 96.217 20.184 ;
     RECT  95.429 13.632 96.317 13.656 ;
     RECT  95.285 25.824 96.332 37.608 ;
     RECT  95.965 2.304 96.757 3.528 ;
     RECT  96.217 16.896 96.829 20.184 ;
     RECT  94.504 5.184 96.865 8.76 ;
     RECT  96.332 25.584 96.901 37.608 ;
     RECT  96.757 1.824 96.905 3.528 ;
     RECT  96.905 2.148 96.908 3.528 ;
     RECT  96.865 4.512 96.908 8.76 ;
     RECT  94.817 9.744 96.908 9.768 ;
     RECT  95.429 10.992 96.908 12.504 ;
     RECT  96.317 13.632 96.908 13.704 ;
     RECT  95.069 15.456 96.908 15.48 ;
     RECT  96.829 16.896 96.908 21 ;
     RECT  95.681 22.32 96.908 23.592 ;
     RECT  96.901 25.2 96.908 37.608 ;
     RECT  95.005 40.512 96.908 40.68 ;
     RECT  96.908 2.148 97.012 57.792 ;
     RECT  97.012 2.418 97.1 57.792 ;
     RECT  97.1 2.418 97.204 58.062 ;
     RECT  97.204 2.418 97.373 7.368 ;
     RECT  97.204 22.176 97.373 24.408 ;
     RECT  97.204 20.976 97.379 21 ;
     RECT  97.204 8.544 97.445 8.904 ;
     RECT  97.204 13.632 97.481 15.432 ;
     RECT  97.373 2.418 97.517 7.224 ;
     RECT  97.204 33.504 97.697 36.072 ;
     RECT  97.517 2.418 97.733 3.96 ;
     RECT  97.517 5.28 97.733 7.224 ;
     RECT  97.733 5.28 97.769 6.6 ;
     RECT  97.697 33.504 97.769 36.024 ;
     RECT  97.204 11.136 97.805 12.504 ;
     RECT  97.204 28.608 97.805 32.52 ;
     RECT  97.445 8.88 97.841 8.904 ;
     RECT  94.849 0.096 97.877 0.168 ;
     RECT  97.769 5.28 97.913 6.024 ;
     RECT  97.805 11.424 97.913 12.504 ;
     RECT  97.913 5.712 97.949 6.024 ;
     RECT  97.733 3.408 97.985 3.96 ;
     RECT  97.481 14.208 98.003 15.432 ;
     RECT  98.003 14.64 98.029 15.432 ;
     RECT  97.204 26.256 98.051 27.576 ;
     RECT  97.805 28.608 98.051 29.592 ;
     RECT  97.949 6 98.129 6.024 ;
     RECT  97.913 11.424 98.129 11.448 ;
     RECT  97.373 22.176 98.129 23.688 ;
     RECT  98.051 26.256 98.197 26.28 ;
     RECT  98.051 27.552 98.197 27.576 ;
     RECT  98.051 28.608 98.197 29.064 ;
     RECT  97.204 18.576 98.237 19.56 ;
     RECT  98.197 25.584 98.243 26.28 ;
     RECT  98.197 27.552 98.243 29.064 ;
     RECT  97.985 3.936 98.273 3.96 ;
     RECT  96.005 59.52 98.273 59.544 ;
     RECT  98.243 25.584 98.284 26.04 ;
     RECT  98.029 14.64 98.345 14.664 ;
     RECT  97.204 37.584 98.345 37.608 ;
     RECT  98.017 2.304 98.561 2.328 ;
     RECT  97.805 30.768 98.581 32.52 ;
     RECT  97.769 33.504 98.581 35.832 ;
     RECT  98.521 7.728 98.593 7.752 ;
     RECT  97.877 0.096 98.597 0.12 ;
     RECT  98.129 22.752 98.629 23.688 ;
     RECT  97.204 9.936 98.845 9.96 ;
     RECT  98.593 7.728 98.917 7.944 ;
     RECT  98.581 30.768 98.917 35.832 ;
     RECT  98.917 30.144 98.989 35.832 ;
     RECT  97.913 12.48 99.133 12.504 ;
     RECT  99.133 12.48 99.253 13.08 ;
     RECT  99.169 5.76 99.277 5.784 ;
     RECT  99.277 5.76 99.608 5.832 ;
     RECT  98.917 6.816 99.608 7.944 ;
     RECT  98.845 8.976 99.608 9.96 ;
     RECT  99.253 11.808 99.608 13.08 ;
     RECT  98.237 19.008 99.608 19.56 ;
     RECT  98.629 22.752 99.608 24.648 ;
     RECT  98.284 26.016 99.608 26.04 ;
     RECT  99.097 27.072 99.608 27.096 ;
     RECT  98.243 28.416 99.608 29.064 ;
     RECT  98.989 30.144 99.608 35.88 ;
     RECT  99.608 2.148 99.712 57.792 ;
     RECT  99.712 2.418 99.8 57.792 ;
     RECT  99.8 2.418 99.904 58.062 ;
     RECT  99.904 28.416 99.965 29.064 ;
     RECT  99.904 30.864 100.037 32.424 ;
     RECT  99.904 26.4 100.073 27.096 ;
     RECT  99.904 33.84 100.073 33.864 ;
     RECT  99.904 23.856 100.109 23.88 ;
     RECT  99.904 6.24 100.289 9 ;
     RECT  100.289 7.728 100.361 9 ;
     RECT  100.073 26.4 100.361 26.424 ;
     RECT  99.965 28.416 100.361 28.44 ;
     RECT  99.904 35.424 100.505 35.448 ;
     RECT  100.361 8.496 100.685 9 ;
     RECT  100.289 6.24 100.829 6.264 ;
     RECT  100.685 8.976 100.829 9 ;
     RECT  99.904 12.48 100.829 12.504 ;
     RECT  99.904 19.008 100.829 19.032 ;
     RECT  100.037 31.296 100.829 32.424 ;
     RECT  100.829 32.016 102.013 32.424 ;
     RECT  102.013 32.016 102.589 32.616 ;
     RECT  102.589 32.016 104.028 32.808 ;
    LAYER M5 ;
     RECT  86.736 0.016 89.736 0.131 ;
     RECT  45.264 0.016 48.264 0.179 ;
     RECT  86.832 0.131 89.736 0.179 ;
     RECT  29.136 0.016 32.136 0.227 ;
     RECT  86.928 0.179 89.736 0.227 ;
     RECT  67.536 0.016 76.68 1.139 ;
     RECT  67.632 1.139 76.68 1.189 ;
     RECT  38.784 1.141 38.808 1.283 ;
     RECT  67.632 1.189 76.824 1.331 ;
     RECT  29.136 0.227 31.992 1.763 ;
     RECT  45.264 0.179 48.168 1.763 ;
     RECT  67.632 1.331 76.68 1.763 ;
     RECT  45.456 1.763 48.168 1.811 ;
     RECT  21.168 2.053 21.192 2.137 ;
     RECT  29.232 1.763 31.992 2.137 ;
     RECT  45.6 1.811 48.168 2.137 ;
     RECT  67.632 1.763 76.584 2.137 ;
     RECT  87.024 0.227 89.736 2.137 ;
     RECT  2.4 2.137 2.52 2.151 ;
     RECT  5.1 2.137 5.22 2.151 ;
     RECT  7.8 2.137 7.92 2.151 ;
     RECT  10.5 2.137 10.62 2.151 ;
     RECT  13.2 2.137 13.32 2.151 ;
     RECT  15.9 2.137 16.02 2.151 ;
     RECT  18.6 2.137 18.72 2.151 ;
     RECT  21.168 2.137 21.42 2.151 ;
     RECT  24 2.137 24.12 2.151 ;
     RECT  26.7 2.137 26.82 2.151 ;
     RECT  29.232 2.137 32.22 2.151 ;
     RECT  34.8 2.137 34.92 2.151 ;
     RECT  37.5 2.137 37.62 2.151 ;
     RECT  40.2 2.137 40.32 2.151 ;
     RECT  42.9 2.137 43.02 2.151 ;
     RECT  45.6 2.137 48.42 2.151 ;
     RECT  51 2.137 51.12 2.151 ;
     RECT  53.7 2.137 53.82 2.151 ;
     RECT  56.4 2.137 56.52 2.151 ;
     RECT  59.1 2.137 59.22 2.151 ;
     RECT  61.8 2.137 61.92 2.151 ;
     RECT  64.5 2.137 64.62 2.151 ;
     RECT  78 2.137 78.12 2.151 ;
     RECT  80.7 2.137 80.82 2.151 ;
     RECT  83.4 2.137 83.52 2.151 ;
     RECT  91.5 2.137 91.62 2.151 ;
     RECT  94.2 2.137 94.32 2.151 ;
     RECT  96.9 2.137 97.02 2.151 ;
     RECT  99.6 2.137 99.72 2.151 ;
     RECT  13.2 2.151 13.512 2.245 ;
     RECT  21.168 2.151 21.612 2.245 ;
     RECT  40.2 2.151 40.512 2.245 ;
     RECT  53.7 2.151 54.012 2.293 ;
     RECT  29.232 2.151 32.412 2.339 ;
     RECT  5.1 2.151 5.412 2.485 ;
     RECT  40.08 2.245 40.512 2.485 ;
     RECT  13.2 2.245 14.424 2.677 ;
     RECT  7.8 2.151 8.112 2.725 ;
     RECT  12.24 2.677 14.424 2.725 ;
     RECT  18.6 2.151 18.912 2.725 ;
     RECT  80.7 2.151 81.012 2.725 ;
     RECT  19.92 2.197 19.944 2.773 ;
     RECT  21.168 2.245 22.152 2.773 ;
     RECT  42.9 2.151 43.212 2.821 ;
     RECT  44.208 2.533 44.232 2.821 ;
     RECT  5.1 2.485 5.976 2.915 ;
     RECT  40.08 2.485 41.496 2.915 ;
     RECT  42.9 2.821 44.232 3.205 ;
     RECT  56.4 2.151 56.712 3.301 ;
     RECT  41.952 3.205 44.232 3.349 ;
     RECT  45.6 2.151 48.612 3.349 ;
     RECT  84.912 2.869 84.936 3.443 ;
     RECT  29.4 2.339 32.412 3.445 ;
     RECT  37.5 2.151 37.812 3.445 ;
     RECT  17.904 2.725 18.912 3.589 ;
     RECT  17.184 3.589 18.912 3.637 ;
     RECT  19.92 2.773 22.152 3.637 ;
     RECT  53.7 2.293 54.12 3.637 ;
     RECT  53.04 3.637 54.12 3.685 ;
     RECT  24 2.151 24.312 3.733 ;
     RECT  53.04 3.685 54.792 3.779 ;
     RECT  86.1 2.137 89.736 3.781 ;
     RECT  91.5 2.151 91.812 3.781 ;
     RECT  41.952 3.349 48.612 3.829 ;
     RECT  61.8 2.151 62.112 3.829 ;
     RECT  67.2 2.137 76.584 3.829 ;
     RECT  78 2.151 78.312 3.829 ;
     RECT  86.1 3.781 91.812 3.829 ;
     RECT  29.4 3.445 33.096 3.877 ;
     RECT  34.8 2.151 35.112 3.877 ;
     RECT  67.2 3.829 78.312 3.877 ;
     RECT  7.8 2.725 8.232 3.925 ;
     RECT  40.08 2.915 40.92 3.925 ;
     RECT  41.952 3.829 49.416 3.925 ;
     RECT  53.7 3.779 54.792 3.925 ;
     RECT  56.4 3.301 56.856 3.925 ;
     RECT  12.048 2.725 14.424 4.019 ;
     RECT  25.68 3.349 25.704 4.213 ;
     RECT  26.7 2.151 27.012 4.213 ;
     RECT  83.4 2.151 83.712 4.261 ;
     RECT  40.08 3.925 49.416 4.309 ;
     RECT  37.5 3.445 38.616 4.453 ;
     RECT  5.1 2.915 5.412 4.501 ;
     RECT  83.4 4.261 84.456 4.501 ;
     RECT  17.184 3.637 22.152 4.595 ;
     RECT  67.2 3.877 79.224 4.595 ;
     RECT  85.536 3.829 91.812 4.595 ;
     RECT  64.5 2.151 64.812 4.597 ;
     RECT  90.624 4.595 91.812 4.691 ;
     RECT  12.048 4.019 13.512 4.693 ;
     RECT  85.536 4.595 89.4 4.739 ;
     RECT  64.32 4.597 64.812 4.741 ;
     RECT  36.096 4.501 36.12 4.789 ;
     RECT  37.5 4.453 39 4.789 ;
     RECT  39.984 4.309 49.416 4.789 ;
     RECT  28.176 4.405 28.2 4.837 ;
     RECT  29.4 3.877 35.112 4.837 ;
     RECT  83.088 4.501 84.456 4.837 ;
     RECT  85.536 4.739 87.336 4.837 ;
     RECT  23.328 3.733 24.312 4.885 ;
     RECT  53.7 3.925 56.856 4.885 ;
     RECT  25.68 4.213 27.012 4.931 ;
     RECT  80.7 2.725 81.48 4.933 ;
     RECT  36.096 4.789 36.456 4.981 ;
     RECT  37.5 4.789 49.416 4.981 ;
     RECT  64.32 4.741 65.592 5.029 ;
     RECT  7.8 3.925 8.952 5.171 ;
     RECT  61.8 3.829 62.52 5.173 ;
     RECT  36.096 4.981 49.416 5.219 ;
     RECT  67.2 4.595 78.744 5.219 ;
     RECT  15.9 2.151 16.212 5.221 ;
     RECT  47.376 5.219 49.416 5.267 ;
     RECT  10.5 2.151 10.812 5.269 ;
     RECT  47.52 5.267 49.416 5.315 ;
     RECT  61.8 5.173 62.712 5.315 ;
     RECT  88.464 4.739 89.4 5.411 ;
     RECT  15.216 5.221 16.212 5.461 ;
     RECT  28.176 4.837 35.112 5.461 ;
     RECT  36.096 5.219 46.296 5.461 ;
     RECT  14.784 5.461 16.212 5.747 ;
     RECT  18.6 4.595 22.152 5.747 ;
     RECT  53.424 4.885 56.856 5.747 ;
     RECT  80.7 4.933 82.104 5.747 ;
     RECT  14.784 5.747 14.808 5.749 ;
     RECT  15.9 5.747 16.212 5.749 ;
     RECT  17.184 4.595 17.208 5.749 ;
     RECT  63.84 5.029 65.592 5.795 ;
     RECT  88.464 5.411 89.208 5.795 ;
     RECT  28.176 5.461 46.296 5.797 ;
     RECT  11.904 4.693 13.512 5.845 ;
     RECT  11.904 5.845 13.656 5.989 ;
     RECT  14.736 5.749 14.808 5.989 ;
     RECT  64.5 5.795 65.592 6.131 ;
     RECT  26.4 4.931 27.012 6.133 ;
     RECT  83.088 4.837 87.336 6.181 ;
     RECT  88.464 5.795 89.112 6.181 ;
     RECT  7.8 5.171 8.232 6.229 ;
     RECT  59.1 2.151 59.412 6.229 ;
     RECT  67.2 5.219 75.96 6.229 ;
     RECT  90.336 5.557 90.36 6.229 ;
     RECT  91.5 4.691 91.812 6.229 ;
     RECT  10.128 5.269 10.812 6.323 ;
     RECT  80.7 5.747 81.48 6.323 ;
     RECT  18.6 5.747 20.088 6.419 ;
     RECT  28.08 5.797 46.296 6.515 ;
     RECT  67.2 6.229 76.056 6.659 ;
     RECT  15.9 5.749 17.208 6.661 ;
     RECT  11.904 5.989 14.808 6.707 ;
     RECT  96.9 2.151 97.212 6.805 ;
     RECT  67.2 6.659 71.592 6.899 ;
     RECT  21.12 5.747 22.152 6.901 ;
     RECT  23.328 4.885 24.408 6.901 ;
     RECT  15.9 6.661 17.4 6.997 ;
     RECT  18.6 6.419 19.896 6.997 ;
     RECT  21.12 6.901 24.408 7.141 ;
     RECT  7.44 6.229 8.232 7.187 ;
     RECT  26.016 6.133 27.012 7.189 ;
     RECT  28.08 6.515 28.2 7.189 ;
     RECT  83.088 6.181 89.112 7.189 ;
     RECT  72.6 6.659 76.056 7.235 ;
     RECT  64.5 6.131 65.112 7.237 ;
     RECT  29.184 6.515 46.296 7.283 ;
     RECT  90.336 6.229 91.812 7.379 ;
     RECT  15.9 6.997 19.896 7.381 ;
     RECT  21.12 7.141 24.456 7.381 ;
     RECT  80.7 6.323 81.012 7.381 ;
     RECT  58.512 6.229 59.412 7.475 ;
     RECT  67.2 6.899 71.16 7.523 ;
     RECT  15.9 7.381 24.456 7.573 ;
     RECT  53.424 5.747 54.012 7.621 ;
     RECT  72.6 7.235 75.96 7.669 ;
     RECT  26.016 7.189 28.2 7.717 ;
     RECT  29.184 7.283 39.144 7.717 ;
     RECT  94.2 2.151 94.512 7.765 ;
     RECT  51 2.151 51.312 7.861 ;
     RECT  7.8 7.187 8.232 7.909 ;
     RECT  12.816 6.707 14.808 7.909 ;
     RECT  15.9 7.573 24.504 7.909 ;
     RECT  99.6 2.151 99.912 7.909 ;
     RECT  12.816 7.909 24.504 8.005 ;
     RECT  26.016 7.717 39.144 8.005 ;
     RECT  12.816 8.005 39.144 8.051 ;
     RECT  64.32 7.237 65.112 8.243 ;
     RECT  91.5 7.379 91.812 8.437 ;
     RECT  7.8 7.909 9.144 8.485 ;
     RECT  12.816 8.051 19.896 8.485 ;
     RECT  80.7 7.381 81.144 8.485 ;
     RECT  80.592 8.485 81.144 8.579 ;
     RECT  53.424 7.621 54.12 8.723 ;
     RECT  7.248 8.485 9.144 8.821 ;
     RECT  10.5 6.323 10.812 8.821 ;
     RECT  61.8 5.315 62.112 8.821 ;
     RECT  64.5 8.243 65.112 8.821 ;
     RECT  50.88 7.861 51.312 9.011 ;
     RECT  99.168 7.909 99.912 9.011 ;
     RECT  12.528 8.485 19.896 9.061 ;
     RECT  7.248 8.821 10.812 9.107 ;
     RECT  21.12 8.051 39.144 9.395 ;
     RECT  80.592 8.579 81.012 9.541 ;
     RECT  2.4 2.151 2.712 9.589 ;
     RECT  82.656 7.189 89.112 9.589 ;
     RECT  90.336 7.379 90.36 9.589 ;
     RECT  59.1 7.475 59.412 9.637 ;
     RECT  69.504 7.523 71.16 9.637 ;
     RECT  72.144 7.669 75.96 9.637 ;
     RECT  21.12 9.395 28.2 9.731 ;
     RECT  82.656 9.589 90.36 9.731 ;
     RECT  95.52 3.829 95.544 9.733 ;
     RECT  96.576 6.805 97.212 9.733 ;
     RECT  61.68 8.821 62.112 9.827 ;
     RECT  12.384 9.061 19.896 10.067 ;
     RECT  58.128 9.637 59.412 10.069 ;
     RECT  12.384 10.067 17.4 10.115 ;
     RECT  91.5 8.437 92.328 10.211 ;
     RECT  23.136 9.731 28.2 10.405 ;
     RECT  29.4 9.395 39.144 10.405 ;
     RECT  21.12 9.731 22.152 10.453 ;
     RECT  40.2 7.283 46.296 10.597 ;
     RECT  83.088 9.731 90.36 10.883 ;
     RECT  47.952 5.315 49.416 11.125 ;
     RECT  51 9.011 51.312 11.125 ;
     RECT  2.4 9.589 2.904 11.171 ;
     RECT  20.88 10.453 22.152 11.219 ;
     RECT  23.136 10.405 39.144 11.267 ;
     RECT  12.384 10.115 14.808 11.315 ;
     RECT  15.792 10.115 17.4 11.315 ;
     RECT  79.824 9.541 81.012 11.315 ;
     RECT  67.2 7.523 68.376 11.365 ;
     RECT  69.504 9.637 75.96 11.365 ;
     RECT  5.1 4.501 5.736 11.459 ;
     RECT  40.2 10.597 46.392 11.459 ;
     RECT  94.032 7.765 94.512 11.795 ;
     RECT  77.472 5.219 78.744 11.797 ;
     RECT  91.5 10.211 91.812 11.797 ;
     RECT  92.832 11.365 92.856 11.797 ;
     RECT  99.6 9.011 99.912 11.797 ;
     RECT  80.7 11.315 81.012 11.893 ;
     RECT  7.8 9.107 10.812 11.941 ;
     RECT  18.6 10.067 19.896 11.941 ;
     RECT  55.2 5.747 56.856 11.941 ;
     RECT  57.984 10.069 59.412 11.941 ;
     RECT  60.432 11.797 60.456 11.941 ;
     RECT  61.8 9.827 62.112 11.941 ;
     RECT  47.952 11.125 51.312 12.179 ;
     RECT  15.9 11.315 17.4 12.325 ;
     RECT  5.1 11.459 5.412 12.469 ;
     RECT  18.48 11.941 19.896 12.515 ;
     RECT  25.632 11.267 39.144 12.515 ;
     RECT  99.264 11.797 99.912 12.515 ;
     RECT  4.224 12.469 6.312 12.517 ;
     RECT  7.8 11.941 11.352 12.517 ;
     RECT  60.432 11.941 62.112 12.517 ;
     RECT  21.12 11.219 22.152 12.563 ;
     RECT  67.2 11.365 75.96 12.563 ;
     RECT  4.224 12.517 11.352 12.755 ;
     RECT  18.6 12.515 19.896 12.757 ;
     RECT  21.12 12.563 21.612 12.757 ;
     RECT  47.952 12.179 49.416 12.757 ;
     RECT  91.5 11.797 92.856 13.043 ;
     RECT  12.528 11.315 14.808 13.045 ;
     RECT  15.9 12.325 17.496 13.045 ;
     RECT  40.2 11.459 45.912 13.045 ;
     RECT  64.5 8.821 65.448 13.045 ;
     RECT  23.136 11.267 24.408 13.091 ;
     RECT  4.224 12.755 11.304 13.139 ;
     RECT  12.528 13.045 17.496 13.141 ;
     RECT  77.472 11.797 79.224 13.189 ;
     RECT  77.472 13.189 79.704 13.331 ;
     RECT  29.232 12.515 39.144 13.333 ;
     RECT  40.2 13.045 46.2 13.333 ;
     RECT  80.7 11.893 81.24 13.333 ;
     RECT  60.432 12.517 62.616 13.571 ;
     RECT  47.904 12.757 49.416 13.573 ;
     RECT  51 12.179 51.312 13.573 ;
     RECT  90.336 10.883 90.36 13.573 ;
     RECT  91.5 13.043 92.328 13.573 ;
     RECT  67.2 12.563 68.376 13.621 ;
     RECT  69.408 12.563 75.96 13.621 ;
     RECT  18.6 12.757 21.612 13.667 ;
     RECT  47.904 13.573 51.312 13.715 ;
     RECT  77.472 13.331 79.224 13.715 ;
     RECT  95.52 9.733 97.212 13.715 ;
     RECT  25.632 12.515 28.2 13.813 ;
     RECT  29.232 13.333 46.2 13.813 ;
     RECT  2.4 11.171 2.712 14.005 ;
     RECT  25.632 13.813 46.2 14.099 ;
     RECT  55.2 11.941 59.412 14.099 ;
     RECT  12.336 13.141 17.496 14.197 ;
     RECT  59.1 14.099 59.412 14.197 ;
     RECT  60.432 13.571 62.568 14.197 ;
     RECT  96.9 13.715 97.212 14.197 ;
     RECT  5.1 13.139 11.304 14.243 ;
     RECT  7.44 14.243 11.304 14.485 ;
     RECT  12.336 14.197 17.544 14.485 ;
     RECT  18.6 13.667 19.896 14.677 ;
     RECT  21.3 13.667 21.612 14.677 ;
     RECT  77.472 13.715 78.744 14.773 ;
     RECT  94.2 11.795 94.512 14.821 ;
     RECT  47.952 13.715 51.312 14.867 ;
     RECT  2.4 14.005 3.48 14.963 ;
     RECT  59.1 14.197 62.568 14.963 ;
     RECT  18.6 14.677 21.612 15.349 ;
     RECT  90.336 13.573 92.328 15.443 ;
     RECT  96.9 14.197 97.992 15.443 ;
     RECT  55.2 14.099 58.008 15.445 ;
     RECT  59.1 14.963 62.328 15.445 ;
     RECT  5.1 14.243 6.312 15.733 ;
     RECT  7.44 14.485 17.544 15.733 ;
     RECT  23.136 13.091 24.312 15.733 ;
     RECT  25.632 14.099 45.912 15.733 ;
     RECT  94.08 14.821 94.512 15.829 ;
     RECT  22.8 15.733 24.312 15.875 ;
     RECT  5.1 15.733 17.544 15.925 ;
     RECT  18.6 15.349 21.72 15.925 ;
     RECT  5.1 15.925 21.72 16.019 ;
     RECT  53.424 8.723 54.012 16.021 ;
     RECT  9.12 16.019 21.72 16.067 ;
     RECT  64.5 13.045 65.544 16.405 ;
     RECT  5.1 16.019 8.112 16.547 ;
     RECT  67.2 13.621 75.96 16.789 ;
     RECT  77.424 14.773 78.744 16.789 ;
     RECT  25.488 15.733 45.912 16.835 ;
     RECT  25.632 16.835 45.912 16.931 ;
     RECT  80.7 13.333 81.912 17.029 ;
     RECT  83.088 10.883 89.112 17.029 ;
     RECT  53.04 16.021 54.012 17.075 ;
     RECT  80.7 17.029 89.112 17.077 ;
     RECT  90.336 15.443 90.36 17.077 ;
     RECT  9.792 16.067 21.72 17.363 ;
     RECT  25.632 16.931 39.192 17.411 ;
     RECT  6.816 16.547 8.112 17.459 ;
     RECT  51 14.867 51.312 17.461 ;
     RECT  64.5 16.405 65.736 17.605 ;
     RECT  67.2 16.789 78.744 17.651 ;
     RECT  80.4 17.077 90.36 17.651 ;
     RECT  80.4 17.651 81.912 17.747 ;
     RECT  10.08 17.363 21.72 18.035 ;
     RECT  25.632 17.411 28.2 18.131 ;
     RECT  7.68 17.459 8.112 18.179 ;
     RECT  64.5 17.605 66.168 18.181 ;
     RECT  67.2 17.651 75.96 18.181 ;
     RECT  83.088 17.651 90.36 18.227 ;
     RECT  95.52 13.715 95.544 18.229 ;
     RECT  10.08 18.035 19.944 18.419 ;
     RECT  96.9 15.443 97.212 18.565 ;
     RECT  55.2 15.445 62.328 18.613 ;
     RECT  20.928 18.035 21.72 18.661 ;
     RECT  10.08 18.419 14.856 18.755 ;
     RECT  5.1 16.547 5.544 18.803 ;
     RECT  55.2 18.613 62.808 18.803 ;
     RECT  95.52 18.229 95.784 18.851 ;
     RECT  10.08 18.755 11.4 18.947 ;
     RECT  23.136 15.875 24.312 19.093 ;
     RECT  26.016 18.131 28.2 19.093 ;
     RECT  53.424 17.075 54.012 19.237 ;
     RECT  55.2 18.803 62.328 19.237 ;
     RECT  15.9 18.419 19.944 19.333 ;
     RECT  20.928 18.661 22.056 19.333 ;
     RECT  23.136 19.093 28.2 19.333 ;
     RECT  90.336 18.227 90.36 19.333 ;
     RECT  91.5 15.443 92.328 19.333 ;
     RECT  93.456 15.829 94.512 19.333 ;
     RECT  12.624 18.755 14.856 19.379 ;
     RECT  96.9 18.565 98.184 19.571 ;
     RECT  50.88 17.461 51.312 19.619 ;
     RECT  53.424 19.237 62.328 19.813 ;
     RECT  91.5 19.333 94.512 19.909 ;
     RECT  95.52 18.851 95.544 19.909 ;
     RECT  53.424 19.813 62.616 19.955 ;
     RECT  91.5 19.909 95.544 20.051 ;
     RECT  15.9 19.333 28.2 20.341 ;
     RECT  29.184 17.411 39.192 20.341 ;
     RECT  15.9 20.341 39.192 20.867 ;
     RECT  7.8 18.179 8.112 20.869 ;
     RECT  60.48 19.955 62.616 20.869 ;
     RECT  96.9 19.571 97.212 20.965 ;
     RECT  60.48 20.869 62.712 21.011 ;
     RECT  60.48 21.011 62.616 21.395 ;
     RECT  12.624 19.379 14.808 21.445 ;
     RECT  15.9 20.867 39.144 21.445 ;
     RECT  77.424 17.651 78.744 21.493 ;
     RECT  12.624 21.445 39.144 21.683 ;
     RECT  93.456 20.051 95.544 21.731 ;
     RECT  90.288 19.333 90.36 21.779 ;
     RECT  12.624 21.683 21.612 21.923 ;
     RECT  7.8 20.869 8.328 21.925 ;
     RECT  40.2 16.931 45.912 21.971 ;
     RECT  10.368 18.947 11.4 22.021 ;
     RECT  23.136 21.683 39.144 22.549 ;
     RECT  40.2 21.971 44.232 22.595 ;
     RECT  23.136 22.549 39.192 22.739 ;
     RECT  94.2 21.731 95.544 22.741 ;
     RECT  96.9 20.965 97.368 22.741 ;
     RECT  99.6 12.515 99.912 22.741 ;
     RECT  91.5 20.051 92.328 22.789 ;
     RECT  53.424 19.955 59.412 23.027 ;
     RECT  9.552 22.021 11.4 23.267 ;
     RECT  25.392 22.739 39.192 23.317 ;
     RECT  40.2 22.595 40.776 23.317 ;
     RECT  94.2 22.741 97.368 23.317 ;
     RECT  93.984 23.317 97.368 23.411 ;
     RECT  12.624 21.923 14.808 23.557 ;
     RECT  15.9 21.923 21.612 23.557 ;
     RECT  98.784 22.741 99.912 23.557 ;
     RECT  45.6 21.971 45.912 23.653 ;
     RECT  96.9 23.411 97.368 23.653 ;
     RECT  98.64 23.557 99.912 23.653 ;
     RECT  64.5 18.181 75.96 23.845 ;
     RECT  93.984 23.411 95.544 23.845 ;
     RECT  91.392 22.789 92.328 23.891 ;
     RECT  5.1 18.803 5.412 23.893 ;
     RECT  25.392 23.317 40.776 23.939 ;
     RECT  23.136 22.739 24.312 23.941 ;
     RECT  12.624 23.557 21.612 23.987 ;
     RECT  64.368 23.845 75.96 24.085 ;
     RECT  76.992 21.493 78.744 24.085 ;
     RECT  21.072 23.987 21.612 24.131 ;
     RECT  64.368 24.085 78.744 24.227 ;
     RECT  25.632 23.939 40.776 24.469 ;
     RECT  41.808 22.595 44.232 24.469 ;
     RECT  80.7 17.747 81.912 24.469 ;
     RECT  7.8 21.925 8.52 24.563 ;
     RECT  96.9 23.653 99.912 24.659 ;
     RECT  21.3 24.131 21.612 24.709 ;
     RECT  80.064 24.469 81.912 25.091 ;
     RECT  5.1 23.893 5.88 25.139 ;
     RECT  10.32 23.267 11.4 25.189 ;
     RECT  93.648 23.845 95.544 25.235 ;
     RECT  22.992 23.941 24.312 25.571 ;
     RECT  83.088 18.227 89.112 25.573 ;
     RECT  90.336 21.779 90.36 25.573 ;
     RECT  94.2 25.235 95.544 25.573 ;
     RECT  96.9 24.659 98.232 25.573 ;
     RECT  45.6 23.653 46.776 25.621 ;
     RECT  47.952 14.867 49.416 25.621 ;
     RECT  64.368 24.227 75.96 25.715 ;
     RECT  83.088 25.573 90.36 25.715 ;
     RECT  23.136 25.571 24.312 25.763 ;
     RECT  12.624 23.987 19.992 25.859 ;
     RECT  25.632 24.469 44.232 25.859 ;
     RECT  29.232 25.859 44.232 26.147 ;
     RECT  21.3 24.709 21.912 26.197 ;
     RECT  55.2 23.027 59.412 26.197 ;
     RECT  60.48 21.395 62.328 26.197 ;
     RECT  45.6 25.621 49.416 26.243 ;
     RECT  94.2 25.573 98.232 26.291 ;
     RECT  45.6 26.243 46.776 26.675 ;
     RECT  10.272 25.189 11.4 26.725 ;
     RECT  29.4 26.147 44.232 26.725 ;
     RECT  9.936 26.725 11.4 26.773 ;
     RECT  29.4 26.725 44.376 26.821 ;
     RECT  45.6 26.675 46.056 26.821 ;
     RECT  29.4 26.821 46.056 26.915 ;
     RECT  9.936 26.773 11.64 26.917 ;
     RECT  9.792 26.917 11.64 27.011 ;
     RECT  94.2 26.291 95.544 27.011 ;
     RECT  83.136 25.715 90.36 27.109 ;
     RECT  91.5 23.891 92.328 27.109 ;
     RECT  9.792 27.011 11.4 27.155 ;
     RECT  80.7 25.091 81.912 27.205 ;
     RECT  9.936 27.155 11.4 27.299 ;
     RECT  12.624 25.859 19.896 27.301 ;
     RECT  80.16 27.205 81.912 27.301 ;
     RECT  23.28 25.763 24.312 27.397 ;
     RECT  76.992 24.227 78.744 27.587 ;
     RECT  94.2 27.011 94.512 27.733 ;
     RECT  95.52 27.011 95.544 27.829 ;
     RECT  21.3 26.197 22.056 27.877 ;
     RECT  64.5 25.715 75.96 27.971 ;
     RECT  23.28 27.397 24.408 27.973 ;
     RECT  25.632 25.859 28.2 27.973 ;
     RECT  23.28 27.973 28.2 28.019 ;
     RECT  41.808 26.915 46.008 28.211 ;
     RECT  10.32 27.299 11.4 28.307 ;
     RECT  93.456 27.733 94.512 28.451 ;
     RECT  94.2 28.451 94.512 28.453 ;
     RECT  95.52 27.829 95.736 28.453 ;
     RECT  10.368 28.307 11.4 28.499 ;
     RECT  96.9 26.291 98.232 28.643 ;
     RECT  21.168 27.877 22.104 28.739 ;
     RECT  26.4 28.019 28.2 28.741 ;
     RECT  29.4 26.915 40.68 28.741 ;
     RECT  42.9 28.211 46.008 28.979 ;
     RECT  94.2 28.453 95.736 28.979 ;
     RECT  51 19.619 51.312 29.029 ;
     RECT  55.2 26.197 62.328 29.029 ;
     RECT  79.776 27.301 81.912 29.075 ;
     RECT  41.808 28.211 41.832 29.221 ;
     RECT  42.9 28.979 44.376 29.221 ;
     RECT  26.4 28.741 40.68 29.267 ;
     RECT  40.032 29.267 40.68 29.315 ;
     RECT  64.5 27.971 75.612 29.509 ;
     RECT  21.3 28.739 22.104 29.557 ;
     RECT  23.28 28.019 25.128 29.557 ;
     RECT  94.2 28.979 95.544 29.603 ;
     RECT  55.2 29.029 62.808 29.941 ;
     RECT  64.5 29.509 75.72 29.941 ;
     RECT  80.208 29.075 81.912 30.083 ;
     RECT  94.2 29.603 94.512 30.133 ;
     RECT  95.52 29.603 95.544 30.133 ;
     RECT  96.9 28.643 98.04 30.133 ;
     RECT  99.6 24.659 99.912 30.133 ;
     RECT  55.2 29.941 75.72 30.275 ;
     RECT  77.424 27.587 78.744 30.275 ;
     RECT  26.4 29.267 28.2 30.709 ;
     RECT  29.4 29.267 38.664 30.709 ;
     RECT  95.52 30.133 98.04 30.757 ;
     RECT  99.504 30.133 99.912 30.757 ;
     RECT  21.3 29.557 25.128 30.851 ;
     RECT  95.52 30.757 99.912 30.851 ;
     RECT  55.2 30.275 75.612 30.899 ;
     RECT  96.9 30.851 99.912 30.899 ;
     RECT  26.4 30.709 38.664 30.901 ;
     RECT  40.2 29.315 40.68 30.901 ;
     RECT  41.808 29.221 44.376 30.949 ;
     RECT  45.6 28.979 46.008 30.949 ;
     RECT  41.808 30.949 46.008 30.995 ;
     RECT  80.7 30.083 81.912 31.285 ;
     RECT  26.4 30.901 40.68 31.381 ;
     RECT  99.504 30.899 99.912 31.427 ;
     RECT  10.5 28.499 11.4 31.765 ;
     RECT  12.48 27.301 19.896 31.765 ;
     RECT  63.648 30.899 75.612 31.861 ;
     RECT  50.592 29.029 51.312 32.051 ;
     RECT  80.592 31.285 82.056 32.149 ;
     RECT  95.52 30.851 95.928 32.195 ;
     RECT  95.52 32.195 95.784 32.291 ;
     RECT  77.424 30.275 78.648 32.341 ;
     RECT  79.776 32.149 82.056 32.341 ;
     RECT  83.136 27.109 92.328 32.341 ;
     RECT  53.424 23.027 54.012 32.437 ;
     RECT  96.9 30.899 98.04 32.437 ;
     RECT  63.6 31.861 75.612 32.485 ;
     RECT  10.5 31.765 19.896 32.531 ;
     RECT  79.776 32.341 92.328 32.531 ;
     RECT  26.4 31.381 40.728 32.723 ;
     RECT  94.08 30.133 94.512 32.965 ;
     RECT  51 32.051 51.312 33.013 ;
     RECT  26.4 32.723 28.2 33.107 ;
     RECT  41.808 30.995 45.912 33.107 ;
     RECT  47.952 26.243 49.416 33.301 ;
     RECT  29.4 32.723 40.728 33.445 ;
     RECT  96.9 32.437 98.616 33.539 ;
     RECT  45.6 33.107 45.912 33.541 ;
     RECT  47.28 33.301 49.416 33.541 ;
     RECT  45.6 33.541 49.416 33.587 ;
     RECT  98.592 33.539 98.616 33.635 ;
     RECT  10.5 32.531 11.4 33.637 ;
     RECT  12.384 32.531 19.896 33.637 ;
     RECT  10.5 33.637 19.896 33.683 ;
     RECT  29.4 33.445 40.776 33.779 ;
     RECT  63.6 32.485 75.96 33.827 ;
     RECT  21.3 30.851 24.312 33.829 ;
     RECT  21.3 33.829 25.128 34.115 ;
     RECT  51 33.013 52.008 34.115 ;
     RECT  53.424 32.437 54.216 34.117 ;
     RECT  55.2 30.899 62.328 34.117 ;
     RECT  94.08 32.965 94.728 34.163 ;
     RECT  29.4 33.779 38.712 34.165 ;
     RECT  26.448 33.107 28.2 34.357 ;
     RECT  29.28 34.165 38.712 34.357 ;
     RECT  39.984 33.779 40.776 34.451 ;
     RECT  22.752 34.115 25.128 34.691 ;
     RECT  63.648 33.827 75.96 34.741 ;
     RECT  77.184 32.341 78.648 34.741 ;
     RECT  99.6 31.427 99.912 34.741 ;
     RECT  53.424 34.117 62.328 34.885 ;
     RECT  63.648 34.741 78.648 34.885 ;
     RECT  23.184 34.691 25.128 34.931 ;
     RECT  26.448 34.357 38.712 34.931 ;
     RECT  53.424 34.885 78.648 34.931 ;
     RECT  41.808 33.107 44.232 34.933 ;
     RECT  45.6 33.587 46.824 34.933 ;
     RECT  47.856 33.587 49.416 35.027 ;
     RECT  95.76 32.291 95.784 35.123 ;
     RECT  21.3 34.115 21.612 35.125 ;
     RECT  40.032 34.451 40.776 35.171 ;
     RECT  94.08 34.163 94.512 35.219 ;
     RECT  99.504 34.741 99.912 35.459 ;
     RECT  40.08 35.171 40.776 35.507 ;
     RECT  51 34.115 51.312 35.509 ;
     RECT  80.592 32.531 92.328 35.653 ;
     RECT  41.808 34.933 46.824 35.939 ;
     RECT  47.952 35.027 49.416 36.085 ;
     RECT  47.952 36.085 49.512 36.373 ;
     RECT  80.592 35.653 92.52 36.373 ;
     RECT  42.624 35.939 45.912 36.659 ;
     RECT  80.544 36.373 92.52 36.659 ;
     RECT  83.136 36.659 92.52 36.899 ;
     RECT  42.768 36.659 45.912 36.901 ;
     RECT  47.376 36.373 49.512 37.043 ;
     RECT  23.184 34.931 24.504 37.045 ;
     RECT  23.184 37.045 24.936 37.091 ;
     RECT  26.448 34.931 38.664 37.091 ;
     RECT  40.2 35.507 40.776 37.093 ;
     RECT  42.768 36.901 46.008 37.381 ;
     RECT  21.168 35.125 21.612 37.475 ;
     RECT  52.416 36.421 52.44 37.573 ;
     RECT  53.424 34.931 78.312 37.573 ;
     RECT  80.544 36.659 81.912 37.573 ;
     RECT  52.416 37.573 78.504 37.619 ;
     RECT  95.712 36.949 95.736 37.619 ;
     RECT  29.136 37.091 38.664 37.667 ;
     RECT  53.184 37.619 78.504 37.667 ;
     RECT  47.808 37.043 49.512 37.669 ;
     RECT  50.832 35.509 51.312 37.669 ;
     RECT  42.768 37.381 46.104 37.763 ;
     RECT  26.448 37.091 28.152 37.859 ;
     RECT  23.28 37.091 24.936 37.861 ;
     RECT  26.448 37.859 27.192 37.861 ;
     RECT  80.208 37.573 81.912 38.197 ;
     RECT  80.112 38.197 81.912 38.435 ;
     RECT  23.28 37.861 27.192 38.483 ;
     RECT  55.2 37.667 78.504 38.725 ;
     RECT  83.136 36.899 92.328 38.725 ;
     RECT  39.888 37.093 40.776 38.773 ;
     RECT  42.768 37.763 46.008 38.773 ;
     RECT  42.72 38.773 46.008 38.819 ;
     RECT  29.136 37.667 33.432 39.205 ;
     RECT  47.808 37.669 51.312 39.205 ;
     RECT  55.2 38.725 78.648 39.251 ;
     RECT  83.136 38.725 92.472 39.299 ;
     RECT  80.7 38.435 81.912 39.301 ;
     RECT  83.136 39.299 92.328 39.301 ;
     RECT  42.72 38.819 45.912 39.347 ;
     RECT  55.2 39.251 75.612 39.731 ;
     RECT  39.888 38.773 40.872 39.779 ;
     RECT  39.888 39.779 40.824 39.827 ;
     RECT  94.2 35.219 94.512 39.829 ;
     RECT  23.28 38.483 27.012 40.309 ;
     RECT  63.792 39.731 75.612 40.405 ;
     RECT  80.7 39.301 92.328 40.499 ;
     RECT  23.28 40.309 27.624 40.547 ;
     RECT  53.184 37.667 54.012 40.549 ;
     RECT  55.2 39.731 62.328 40.549 ;
     RECT  53.184 40.549 62.328 40.595 ;
     RECT  53.28 40.595 62.328 40.837 ;
     RECT  29.088 39.205 33.432 40.883 ;
     RECT  47.328 39.205 51.312 40.931 ;
     RECT  23.28 40.547 25.704 40.979 ;
     RECT  53.28 40.837 62.76 40.979 ;
     RECT  94.2 39.829 94.968 41.027 ;
     RECT  34.8 37.667 38.664 41.075 ;
     RECT  34.8 41.075 35.64 41.077 ;
     RECT  25.68 40.979 25.704 41.123 ;
     RECT  42.9 39.347 45.912 41.219 ;
     RECT  40.2 39.827 40.824 41.269 ;
     RECT  40.2 41.269 41.784 41.315 ;
     RECT  77.424 39.251 78.648 41.413 ;
     RECT  45.504 41.219 45.912 41.461 ;
     RECT  80.7 40.499 87.048 41.651 ;
     RECT  55.2 40.979 62.76 41.747 ;
     RECT  26.7 40.547 27.624 42.085 ;
     RECT  80.7 41.651 84.6 42.131 ;
     RECT  45.504 41.461 46.728 42.227 ;
     RECT  53.28 40.979 54.012 42.227 ;
     RECT  88.032 40.499 92.328 42.227 ;
     RECT  94.2 41.027 94.728 42.419 ;
     RECT  63.792 40.405 76.392 42.467 ;
     RECT  42.9 41.219 44.472 42.563 ;
     RECT  36.912 41.075 38.664 42.709 ;
     RECT  41.76 41.315 41.784 42.709 ;
     RECT  42.9 42.563 44.28 42.709 ;
     RECT  88.08 42.227 92.328 42.709 ;
     RECT  77.424 41.413 79.128 42.755 ;
     RECT  40.2 41.315 40.776 42.757 ;
     RECT  41.76 42.709 44.28 42.757 ;
     RECT  26.7 42.085 27.912 42.803 ;
     RECT  47.808 40.931 51.312 42.899 ;
     RECT  85.728 41.651 87.048 43.283 ;
     RECT  45.6 42.227 46.728 43.285 ;
     RECT  47.808 42.899 49.416 43.285 ;
     RECT  77.424 42.755 78.312 43.379 ;
     RECT  85.968 43.283 87.048 43.379 ;
     RECT  40.2 42.757 44.28 43.427 ;
     RECT  36.816 42.709 38.664 43.525 ;
     RECT  88.08 42.709 92.472 43.715 ;
     RECT  53.424 42.227 54.012 43.813 ;
     RECT  55.2 41.747 62.328 43.813 ;
     RECT  51 42.899 51.312 43.861 ;
     RECT  45.6 43.285 49.416 43.955 ;
     RECT  83.136 42.131 84.6 43.955 ;
     RECT  36.816 43.525 38.952 44.005 ;
     RECT  85.968 43.379 86.52 44.195 ;
     RECT  29.4 40.883 33.432 44.437 ;
     RECT  34.416 41.077 35.64 44.437 ;
     RECT  40.2 43.427 41.832 44.437 ;
     RECT  42.9 43.427 44.28 44.437 ;
     RECT  36.768 44.005 38.952 44.483 ;
     RECT  40.2 44.437 44.28 44.483 ;
     RECT  40.2 44.483 43.212 44.723 ;
     RECT  44.256 44.483 44.28 44.723 ;
     RECT  40.2 44.723 40.68 44.963 ;
     RECT  53.424 43.813 62.328 44.965 ;
     RECT  63.792 42.467 76.008 44.965 ;
     RECT  29.4 44.437 35.64 45.059 ;
     RECT  53.424 44.965 76.008 45.059 ;
     RECT  53.424 45.059 63 45.107 ;
     RECT  40.2 44.963 40.632 45.203 ;
     RECT  50.88 43.861 51.312 45.301 ;
     RECT  80.7 42.131 81.912 45.541 ;
     RECT  55.2 45.107 63 45.635 ;
     RECT  34.8 45.059 35.64 45.637 ;
     RECT  36.768 44.483 37.812 45.637 ;
     RECT  50.304 45.301 51.312 45.685 ;
     RECT  38.928 44.483 38.952 45.731 ;
     RECT  85.968 44.195 86.412 45.731 ;
     RECT  80.256 45.541 81.912 45.733 ;
     RECT  64.5 45.059 76.008 45.923 ;
     RECT  50.304 45.685 51.912 45.973 ;
     RECT  41.76 44.723 43.212 46.211 ;
     RECT  29.4 45.059 33.48 46.259 ;
     RECT  45.6 43.955 48.612 46.259 ;
     RECT  34.8 45.637 37.812 46.307 ;
     RECT  50.256 45.973 51.912 46.693 ;
     RECT  53.424 45.107 54.012 46.693 ;
     RECT  55.2 45.635 62.328 46.693 ;
     RECT  50.256 46.693 51.96 46.739 ;
     RECT  37.152 46.307 37.812 46.787 ;
     RECT  42.192 46.211 43.212 46.883 ;
     RECT  45.6 46.259 46.776 47.029 ;
     RECT  37.344 46.787 37.812 47.317 ;
     RECT  53.424 46.693 62.328 47.363 ;
     RECT  84.96 46.309 84.984 47.363 ;
     RECT  80.064 45.733 81.912 47.365 ;
     RECT  64.5 45.923 75.96 47.411 ;
     RECT  79.536 47.365 81.912 47.411 ;
     RECT  37.344 47.317 38.76 47.555 ;
     RECT  50.304 46.739 51.96 47.845 ;
     RECT  79.536 47.411 79.56 47.987 ;
     RECT  55.2 47.363 62.328 48.131 ;
     RECT  63.408 46.693 63.432 48.131 ;
     RECT  37.5 47.555 38.76 48.179 ;
     RECT  49.776 47.845 51.96 48.179 ;
     RECT  45.36 47.029 46.776 48.421 ;
     RECT  47.808 46.259 48.612 48.421 ;
     RECT  78 43.379 78.312 48.469 ;
     RECT  49.776 48.179 51.912 48.515 ;
     RECT  55.2 48.131 55.224 48.515 ;
     RECT  77.664 48.469 78.312 48.661 ;
     RECT  45.36 48.421 48.612 48.757 ;
     RECT  45.36 48.757 48.744 48.803 ;
     RECT  83.136 43.955 83.712 48.853 ;
     RECT  77.664 48.661 79.512 48.949 ;
     RECT  80.7 47.411 81.912 48.949 ;
     RECT  83.136 48.853 84.456 48.949 ;
     RECT  53.424 47.363 54.012 48.997 ;
     RECT  45.6 48.803 48.744 49.043 ;
     RECT  77.664 48.949 81.912 49.043 ;
     RECT  83.136 48.949 84.648 49.285 ;
     RECT  64.5 47.411 75.612 49.477 ;
     RECT  50.304 48.515 51.912 49.571 ;
     RECT  53.424 48.997 54.888 49.571 ;
     RECT  53.424 49.571 54.012 49.619 ;
     RECT  79.824 49.043 81.912 49.715 ;
     RECT  83.088 49.285 84.648 50.051 ;
     RECT  45.6 49.043 48.612 50.195 ;
     RECT  64.5 49.477 75.768 50.195 ;
     RECT  77.664 49.043 78.312 50.291 ;
     RECT  83.088 50.051 83.712 50.291 ;
     RECT  45.6 50.195 46.008 50.579 ;
     RECT  64.5 50.195 75.612 50.629 ;
     RECT  47.808 50.195 48.612 51.781 ;
     RECT  50.304 49.571 51.312 51.781 ;
     RECT  50.16 51.781 51.312 52.981 ;
     RECT  47.808 51.781 49.032 53.027 ;
     RECT  63.744 50.629 75.612 53.075 ;
     RECT  53.7 49.619 54.012 53.365 ;
     RECT  50.112 52.981 51.312 53.603 ;
     RECT  52.992 53.365 54.012 54.131 ;
     RECT  23.28 40.979 24.312 57.635 ;
     RECT  2.4 14.963 2.712 58.059 ;
     RECT  5.1 25.139 5.412 58.059 ;
     RECT  7.8 24.563 8.112 58.059 ;
     RECT  10.5 33.683 18.912 58.059 ;
     RECT  21.3 37.475 21.612 58.059 ;
     RECT  24 57.635 24.312 58.059 ;
     RECT  26.7 42.803 27.012 58.059 ;
     RECT  29.4 46.259 33.432 58.059 ;
     RECT  34.8 46.307 35.64 58.059 ;
     RECT  37.5 48.179 37.812 58.059 ;
     RECT  40.2 45.203 40.512 58.059 ;
     RECT  42.9 46.883 43.212 58.059 ;
     RECT  45.6 50.579 45.912 58.059 ;
     RECT  51 53.603 51.312 58.059 ;
     RECT  53.7 54.131 54.012 58.059 ;
     RECT  56.4 48.131 62.328 58.059 ;
     RECT  64.5 53.075 75.612 58.059 ;
     RECT  78 50.291 78.312 58.059 ;
     RECT  80.7 49.715 81.912 58.059 ;
     RECT  86.1 45.731 86.412 58.059 ;
     RECT  94.2 42.419 94.512 58.059 ;
     RECT  96.9 33.539 97.212 58.059 ;
     RECT  99.6 35.459 99.912 58.059 ;
     RECT  2.592 58.059 2.712 58.073 ;
     RECT  5.292 58.059 5.412 58.073 ;
     RECT  7.992 58.059 8.112 58.073 ;
     RECT  10.692 58.059 18.912 58.073 ;
     RECT  21.492 58.059 21.612 58.073 ;
     RECT  24.192 58.059 24.312 58.073 ;
     RECT  26.892 58.059 27.012 58.073 ;
     RECT  29.592 58.059 33.432 58.073 ;
     RECT  34.992 58.059 35.64 58.073 ;
     RECT  37.692 58.059 37.812 58.073 ;
     RECT  40.392 58.059 40.512 58.073 ;
     RECT  43.092 58.059 43.212 58.073 ;
     RECT  45.792 58.059 45.912 58.073 ;
     RECT  47.808 53.027 48.612 58.073 ;
     RECT  51.192 58.059 51.312 58.073 ;
     RECT  53.892 58.059 54.012 58.073 ;
     RECT  56.592 58.059 62.328 58.073 ;
     RECT  64.692 58.059 66.408 58.073 ;
     RECT  67.392 58.059 74.376 58.073 ;
     RECT  75.492 58.059 75.612 58.073 ;
     RECT  78.192 58.059 78.312 58.073 ;
     RECT  80.892 58.059 81.912 58.073 ;
     RECT  83.136 50.291 83.712 58.073 ;
     RECT  86.292 58.059 86.412 58.073 ;
     RECT  88.08 43.715 92.328 58.073 ;
     RECT  94.392 58.059 94.512 58.073 ;
     RECT  97.092 58.059 97.212 58.073 ;
     RECT  99.792 58.059 99.912 58.073 ;
     RECT  92.304 58.073 92.328 58.403 ;
     RECT  73.008 58.073 74.376 59.267 ;
     RECT  81.888 58.073 81.912 59.555 ;
     RECT  73.008 59.267 73.848 59.651 ;
     RECT  57.312 58.073 62.328 59.843 ;
     RECT  65.664 58.073 66.408 59.891 ;
     RECT  67.872 58.073 71.88 59.891 ;
     RECT  68.016 59.891 71.88 59.939 ;
     RECT  66.144 59.891 66.168 59.987 ;
     RECT  30.384 58.073 33.432 60.181 ;
     RECT  58.08 59.843 62.328 60.323 ;
     RECT  30.384 60.181 33.48 60.371 ;
     RECT  58.416 60.323 61.896 60.371 ;
     RECT  11.28 58.073 17.928 60.419 ;
     RECT  35.616 58.073 35.64 60.419 ;
     RECT  47.808 58.073 47.832 60.419 ;
     RECT  68.16 59.939 71.88 60.419 ;
     RECT  73.008 59.651 73.032 60.419 ;
     RECT  83.136 58.073 83.16 60.419 ;
     RECT  11.28 60.419 17.352 60.432 ;
     RECT  30.48 60.371 33.48 60.432 ;
     RECT  58.896 60.371 61.896 60.432 ;
     RECT  68.88 60.419 71.88 60.432 ;
     RECT  88.08 58.073 91.08 60.432 ;
  END
END qfd_landh_600_NS_104x60
END LIBRARY
